# OpenTallas memory compiler (tools/mem_compiler), ASAP7 abstract view
VERSION 5.7 ;
BUSBITCHARS "[]" ;
DIVIDERCHAR "/" ;
PROPERTYDEFINITIONS
  MACRO width INTEGER ;
  MACRO depth INTEGER ;
  MACRO banks INTEGER ;
END PROPERTYDEFINITIONS
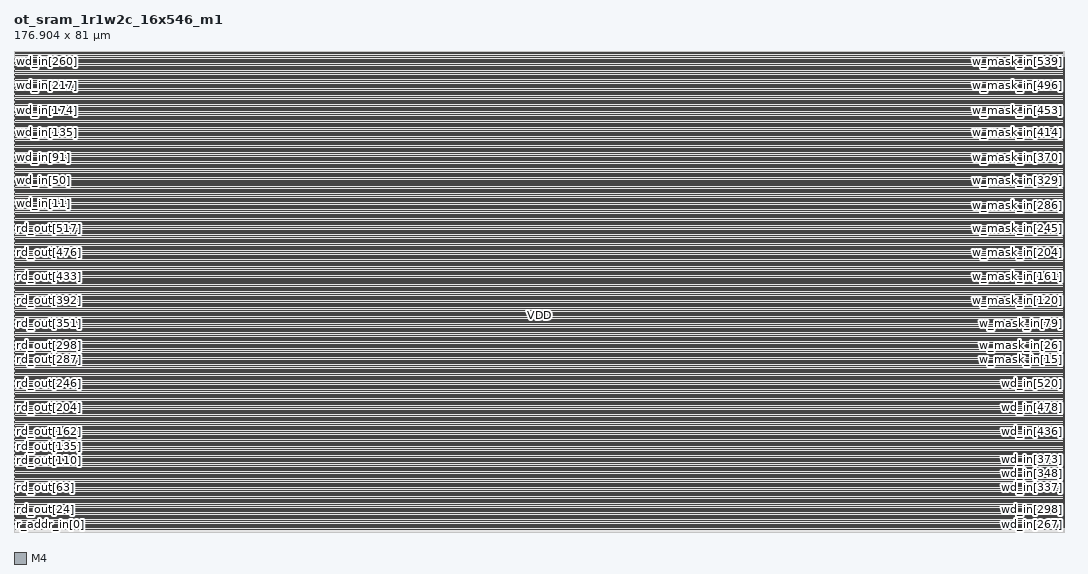
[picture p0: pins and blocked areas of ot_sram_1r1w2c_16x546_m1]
MACRO ot_sram_1r1w2c_16x546_m1
  PROPERTY width 546 ;
  PROPERTY depth 16 ;
  PROPERTY banks 1 ;
  FOREIGN ot_sram_1r1w2c_16x546_m1 0 0 ;
  SYMMETRY X Y R90 ;
  SIZE 176.904 BY 81.000 ;
  CLASS BLOCK ;
  PIN wclk
    DIRECTION INPUT ;
    USE CLOCK ;
    SHAPE ABUTMENT ;
    PORT
      LAYER M4 ;
      RECT 0.000 0.768 0.024 0.792 ;
    END
  END wclk
  PIN rclk
    DIRECTION INPUT ;
    USE CLOCK ;
    SHAPE ABUTMENT ;
    PORT
      LAYER M4 ;
      RECT 0.000 0.864 0.024 0.888 ;
    END
  END rclk
  PIN r_ce_in
    DIRECTION INPUT ;
    USE SIGNAL ;
    SHAPE ABUTMENT ;
    PORT
      LAYER M4 ;
      RECT 0.000 0.960 0.024 0.984 ;
    END
  END r_ce_in
  PIN r_addr_in[0]
    DIRECTION INPUT ;
    USE SIGNAL ;
    SHAPE ABUTMENT ;
    PORT
      LAYER M4 ;
      RECT 0.000 1.056 0.024 1.080 ;
    END
  END r_addr_in[0]
  PIN r_addr_in[1]
    DIRECTION INPUT ;
    USE SIGNAL ;
    SHAPE ABUTMENT ;
    PORT
      LAYER M4 ;
      RECT 0.000 1.152 0.024 1.176 ;
    END
  END r_addr_in[1]
  PIN r_addr_in[2]
    DIRECTION INPUT ;
    USE SIGNAL ;
    SHAPE ABUTMENT ;
    PORT
      LAYER M4 ;
      RECT 0.000 1.248 0.024 1.272 ;
    END
  END r_addr_in[2]
  PIN r_addr_in[3]
    DIRECTION INPUT ;
    USE SIGNAL ;
    SHAPE ABUTMENT ;
    PORT
      LAYER M4 ;
      RECT 0.000 1.344 0.024 1.368 ;
    END
  END r_addr_in[3]
  PIN rd_out[0]
    DIRECTION OUTPUT ;
    USE SIGNAL ;
    SHAPE ABUTMENT ;
    PORT
      LAYER M4 ;
      RECT 0.000 1.440 0.024 1.464 ;
    END
  END rd_out[0]
  PIN rd_out[1]
    DIRECTION OUTPUT ;
    USE SIGNAL ;
    SHAPE ABUTMENT ;
    PORT
      LAYER M4 ;
      RECT 0.000 1.536 0.024 1.560 ;
    END
  END rd_out[1]
  PIN rd_out[2]
    DIRECTION OUTPUT ;
    USE SIGNAL ;
    SHAPE ABUTMENT ;
    PORT
      LAYER M4 ;
      RECT 0.000 1.632 0.024 1.656 ;
    END
  END rd_out[2]
  PIN rd_out[3]
    DIRECTION OUTPUT ;
    USE SIGNAL ;
    SHAPE ABUTMENT ;
    PORT
      LAYER M4 ;
      RECT 0.000 1.728 0.024 1.752 ;
    END
  END rd_out[3]
  PIN rd_out[4]
    DIRECTION OUTPUT ;
    USE SIGNAL ;
    SHAPE ABUTMENT ;
    PORT
      LAYER M4 ;
      RECT 0.000 1.824 0.024 1.848 ;
    END
  END rd_out[4]
  PIN rd_out[5]
    DIRECTION OUTPUT ;
    USE SIGNAL ;
    SHAPE ABUTMENT ;
    PORT
      LAYER M4 ;
      RECT 0.000 1.920 0.024 1.944 ;
    END
  END rd_out[5]
  PIN rd_out[6]
    DIRECTION OUTPUT ;
    USE SIGNAL ;
    SHAPE ABUTMENT ;
    PORT
      LAYER M4 ;
      RECT 0.000 2.016 0.024 2.040 ;
    END
  END rd_out[6]
  PIN rd_out[7]
    DIRECTION OUTPUT ;
    USE SIGNAL ;
    SHAPE ABUTMENT ;
    PORT
      LAYER M4 ;
      RECT 0.000 2.112 0.024 2.136 ;
    END
  END rd_out[7]
  PIN rd_out[8]
    DIRECTION OUTPUT ;
    USE SIGNAL ;
    SHAPE ABUTMENT ;
    PORT
      LAYER M4 ;
      RECT 0.000 2.208 0.024 2.232 ;
    END
  END rd_out[8]
  PIN rd_out[9]
    DIRECTION OUTPUT ;
    USE SIGNAL ;
    SHAPE ABUTMENT ;
    PORT
      LAYER M4 ;
      RECT 0.000 2.304 0.024 2.328 ;
    END
  END rd_out[9]
  PIN rd_out[10]
    DIRECTION OUTPUT ;
    USE SIGNAL ;
    SHAPE ABUTMENT ;
    PORT
      LAYER M4 ;
      RECT 0.000 2.400 0.024 2.424 ;
    END
  END rd_out[10]
  PIN rd_out[11]
    DIRECTION OUTPUT ;
    USE SIGNAL ;
    SHAPE ABUTMENT ;
    PORT
      LAYER M4 ;
      RECT 0.000 2.496 0.024 2.520 ;
    END
  END rd_out[11]
  PIN rd_out[12]
    DIRECTION OUTPUT ;
    USE SIGNAL ;
    SHAPE ABUTMENT ;
    PORT
      LAYER M4 ;
      RECT 0.000 2.592 0.024 2.616 ;
    END
  END rd_out[12]
  PIN rd_out[13]
    DIRECTION OUTPUT ;
    USE SIGNAL ;
    SHAPE ABUTMENT ;
    PORT
      LAYER M4 ;
      RECT 0.000 2.688 0.024 2.712 ;
    END
  END rd_out[13]
  PIN rd_out[14]
    DIRECTION OUTPUT ;
    USE SIGNAL ;
    SHAPE ABUTMENT ;
    PORT
      LAYER M4 ;
      RECT 0.000 2.784 0.024 2.808 ;
    END
  END rd_out[14]
  PIN rd_out[15]
    DIRECTION OUTPUT ;
    USE SIGNAL ;
    SHAPE ABUTMENT ;
    PORT
      LAYER M4 ;
      RECT 0.000 2.880 0.024 2.904 ;
    END
  END rd_out[15]
  PIN rd_out[16]
    DIRECTION OUTPUT ;
    USE SIGNAL ;
    SHAPE ABUTMENT ;
    PORT
      LAYER M4 ;
      RECT 0.000 2.976 0.024 3.000 ;
    END
  END rd_out[16]
  PIN rd_out[17]
    DIRECTION OUTPUT ;
    USE SIGNAL ;
    SHAPE ABUTMENT ;
    PORT
      LAYER M4 ;
      RECT 0.000 3.072 0.024 3.096 ;
    END
  END rd_out[17]
  PIN rd_out[18]
    DIRECTION OUTPUT ;
    USE SIGNAL ;
    SHAPE ABUTMENT ;
    PORT
      LAYER M4 ;
      RECT 0.000 3.168 0.024 3.192 ;
    END
  END rd_out[18]
  PIN rd_out[19]
    DIRECTION OUTPUT ;
    USE SIGNAL ;
    SHAPE ABUTMENT ;
    PORT
      LAYER M4 ;
      RECT 0.000 3.264 0.024 3.288 ;
    END
  END rd_out[19]
  PIN rd_out[20]
    DIRECTION OUTPUT ;
    USE SIGNAL ;
    SHAPE ABUTMENT ;
    PORT
      LAYER M4 ;
      RECT 0.000 3.360 0.024 3.384 ;
    END
  END rd_out[20]
  PIN rd_out[21]
    DIRECTION OUTPUT ;
    USE SIGNAL ;
    SHAPE ABUTMENT ;
    PORT
      LAYER M4 ;
      RECT 0.000 3.456 0.024 3.480 ;
    END
  END rd_out[21]
  PIN rd_out[22]
    DIRECTION OUTPUT ;
    USE SIGNAL ;
    SHAPE ABUTMENT ;
    PORT
      LAYER M4 ;
      RECT 0.000 3.552 0.024 3.576 ;
    END
  END rd_out[22]
  PIN rd_out[23]
    DIRECTION OUTPUT ;
    USE SIGNAL ;
    SHAPE ABUTMENT ;
    PORT
      LAYER M4 ;
      RECT 0.000 3.648 0.024 3.672 ;
    END
  END rd_out[23]
  PIN rd_out[24]
    DIRECTION OUTPUT ;
    USE SIGNAL ;
    SHAPE ABUTMENT ;
    PORT
      LAYER M4 ;
      RECT 0.000 3.744 0.024 3.768 ;
    END
  END rd_out[24]
  PIN rd_out[25]
    DIRECTION OUTPUT ;
    USE SIGNAL ;
    SHAPE ABUTMENT ;
    PORT
      LAYER M4 ;
      RECT 0.000 3.840 0.024 3.864 ;
    END
  END rd_out[25]
  PIN rd_out[26]
    DIRECTION OUTPUT ;
    USE SIGNAL ;
    SHAPE ABUTMENT ;
    PORT
      LAYER M4 ;
      RECT 0.000 3.936 0.024 3.960 ;
    END
  END rd_out[26]
  PIN rd_out[27]
    DIRECTION OUTPUT ;
    USE SIGNAL ;
    SHAPE ABUTMENT ;
    PORT
      LAYER M4 ;
      RECT 0.000 4.032 0.024 4.056 ;
    END
  END rd_out[27]
  PIN rd_out[28]
    DIRECTION OUTPUT ;
    USE SIGNAL ;
    SHAPE ABUTMENT ;
    PORT
      LAYER M4 ;
      RECT 0.000 4.128 0.024 4.152 ;
    END
  END rd_out[28]
  PIN rd_out[29]
    DIRECTION OUTPUT ;
    USE SIGNAL ;
    SHAPE ABUTMENT ;
    PORT
      LAYER M4 ;
      RECT 0.000 4.224 0.024 4.248 ;
    END
  END rd_out[29]
  PIN rd_out[30]
    DIRECTION OUTPUT ;
    USE SIGNAL ;
    SHAPE ABUTMENT ;
    PORT
      LAYER M4 ;
      RECT 0.000 4.320 0.024 4.344 ;
    END
  END rd_out[30]
  PIN rd_out[31]
    DIRECTION OUTPUT ;
    USE SIGNAL ;
    SHAPE ABUTMENT ;
    PORT
      LAYER M4 ;
      RECT 0.000 4.416 0.024 4.440 ;
    END
  END rd_out[31]
  PIN rd_out[32]
    DIRECTION OUTPUT ;
    USE SIGNAL ;
    SHAPE ABUTMENT ;
    PORT
      LAYER M4 ;
      RECT 0.000 4.512 0.024 4.536 ;
    END
  END rd_out[32]
  PIN rd_out[33]
    DIRECTION OUTPUT ;
    USE SIGNAL ;
    SHAPE ABUTMENT ;
    PORT
      LAYER M4 ;
      RECT 0.000 4.608 0.024 4.632 ;
    END
  END rd_out[33]
  PIN rd_out[34]
    DIRECTION OUTPUT ;
    USE SIGNAL ;
    SHAPE ABUTMENT ;
    PORT
      LAYER M4 ;
      RECT 0.000 4.704 0.024 4.728 ;
    END
  END rd_out[34]
  PIN rd_out[35]
    DIRECTION OUTPUT ;
    USE SIGNAL ;
    SHAPE ABUTMENT ;
    PORT
      LAYER M4 ;
      RECT 0.000 4.800 0.024 4.824 ;
    END
  END rd_out[35]
  PIN rd_out[36]
    DIRECTION OUTPUT ;
    USE SIGNAL ;
    SHAPE ABUTMENT ;
    PORT
      LAYER M4 ;
      RECT 0.000 4.896 0.024 4.920 ;
    END
  END rd_out[36]
  PIN rd_out[37]
    DIRECTION OUTPUT ;
    USE SIGNAL ;
    SHAPE ABUTMENT ;
    PORT
      LAYER M4 ;
      RECT 0.000 4.992 0.024 5.016 ;
    END
  END rd_out[37]
  PIN rd_out[38]
    DIRECTION OUTPUT ;
    USE SIGNAL ;
    SHAPE ABUTMENT ;
    PORT
      LAYER M4 ;
      RECT 0.000 5.088 0.024 5.112 ;
    END
  END rd_out[38]
  PIN rd_out[39]
    DIRECTION OUTPUT ;
    USE SIGNAL ;
    SHAPE ABUTMENT ;
    PORT
      LAYER M4 ;
      RECT 0.000 5.184 0.024 5.208 ;
    END
  END rd_out[39]
  PIN rd_out[40]
    DIRECTION OUTPUT ;
    USE SIGNAL ;
    SHAPE ABUTMENT ;
    PORT
      LAYER M4 ;
      RECT 0.000 5.280 0.024 5.304 ;
    END
  END rd_out[40]
  PIN rd_out[41]
    DIRECTION OUTPUT ;
    USE SIGNAL ;
    SHAPE ABUTMENT ;
    PORT
      LAYER M4 ;
      RECT 0.000 5.376 0.024 5.400 ;
    END
  END rd_out[41]
  PIN rd_out[42]
    DIRECTION OUTPUT ;
    USE SIGNAL ;
    SHAPE ABUTMENT ;
    PORT
      LAYER M4 ;
      RECT 0.000 5.472 0.024 5.496 ;
    END
  END rd_out[42]
  PIN rd_out[43]
    DIRECTION OUTPUT ;
    USE SIGNAL ;
    SHAPE ABUTMENT ;
    PORT
      LAYER M4 ;
      RECT 0.000 5.568 0.024 5.592 ;
    END
  END rd_out[43]
  PIN rd_out[44]
    DIRECTION OUTPUT ;
    USE SIGNAL ;
    SHAPE ABUTMENT ;
    PORT
      LAYER M4 ;
      RECT 0.000 5.664 0.024 5.688 ;
    END
  END rd_out[44]
  PIN rd_out[45]
    DIRECTION OUTPUT ;
    USE SIGNAL ;
    SHAPE ABUTMENT ;
    PORT
      LAYER M4 ;
      RECT 0.000 5.760 0.024 5.784 ;
    END
  END rd_out[45]
  PIN rd_out[46]
    DIRECTION OUTPUT ;
    USE SIGNAL ;
    SHAPE ABUTMENT ;
    PORT
      LAYER M4 ;
      RECT 0.000 5.856 0.024 5.880 ;
    END
  END rd_out[46]
  PIN rd_out[47]
    DIRECTION OUTPUT ;
    USE SIGNAL ;
    SHAPE ABUTMENT ;
    PORT
      LAYER M4 ;
      RECT 0.000 5.952 0.024 5.976 ;
    END
  END rd_out[47]
  PIN rd_out[48]
    DIRECTION OUTPUT ;
    USE SIGNAL ;
    SHAPE ABUTMENT ;
    PORT
      LAYER M4 ;
      RECT 0.000 6.048 0.024 6.072 ;
    END
  END rd_out[48]
  PIN rd_out[49]
    DIRECTION OUTPUT ;
    USE SIGNAL ;
    SHAPE ABUTMENT ;
    PORT
      LAYER M4 ;
      RECT 0.000 6.144 0.024 6.168 ;
    END
  END rd_out[49]
  PIN rd_out[50]
    DIRECTION OUTPUT ;
    USE SIGNAL ;
    SHAPE ABUTMENT ;
    PORT
      LAYER M4 ;
      RECT 0.000 6.240 0.024 6.264 ;
    END
  END rd_out[50]
  PIN rd_out[51]
    DIRECTION OUTPUT ;
    USE SIGNAL ;
    SHAPE ABUTMENT ;
    PORT
      LAYER M4 ;
      RECT 0.000 6.336 0.024 6.360 ;
    END
  END rd_out[51]
  PIN rd_out[52]
    DIRECTION OUTPUT ;
    USE SIGNAL ;
    SHAPE ABUTMENT ;
    PORT
      LAYER M4 ;
      RECT 0.000 6.432 0.024 6.456 ;
    END
  END rd_out[52]
  PIN rd_out[53]
    DIRECTION OUTPUT ;
    USE SIGNAL ;
    SHAPE ABUTMENT ;
    PORT
      LAYER M4 ;
      RECT 0.000 6.528 0.024 6.552 ;
    END
  END rd_out[53]
  PIN rd_out[54]
    DIRECTION OUTPUT ;
    USE SIGNAL ;
    SHAPE ABUTMENT ;
    PORT
      LAYER M4 ;
      RECT 0.000 6.624 0.024 6.648 ;
    END
  END rd_out[54]
  PIN rd_out[55]
    DIRECTION OUTPUT ;
    USE SIGNAL ;
    SHAPE ABUTMENT ;
    PORT
      LAYER M4 ;
      RECT 0.000 6.720 0.024 6.744 ;
    END
  END rd_out[55]
  PIN rd_out[56]
    DIRECTION OUTPUT ;
    USE SIGNAL ;
    SHAPE ABUTMENT ;
    PORT
      LAYER M4 ;
      RECT 0.000 6.816 0.024 6.840 ;
    END
  END rd_out[56]
  PIN rd_out[57]
    DIRECTION OUTPUT ;
    USE SIGNAL ;
    SHAPE ABUTMENT ;
    PORT
      LAYER M4 ;
      RECT 0.000 6.912 0.024 6.936 ;
    END
  END rd_out[57]
  PIN rd_out[58]
    DIRECTION OUTPUT ;
    USE SIGNAL ;
    SHAPE ABUTMENT ;
    PORT
      LAYER M4 ;
      RECT 0.000 7.008 0.024 7.032 ;
    END
  END rd_out[58]
  PIN rd_out[59]
    DIRECTION OUTPUT ;
    USE SIGNAL ;
    SHAPE ABUTMENT ;
    PORT
      LAYER M4 ;
      RECT 0.000 7.104 0.024 7.128 ;
    END
  END rd_out[59]
  PIN rd_out[60]
    DIRECTION OUTPUT ;
    USE SIGNAL ;
    SHAPE ABUTMENT ;
    PORT
      LAYER M4 ;
      RECT 0.000 7.200 0.024 7.224 ;
    END
  END rd_out[60]
  PIN rd_out[61]
    DIRECTION OUTPUT ;
    USE SIGNAL ;
    SHAPE ABUTMENT ;
    PORT
      LAYER M4 ;
      RECT 0.000 7.296 0.024 7.320 ;
    END
  END rd_out[61]
  PIN rd_out[62]
    DIRECTION OUTPUT ;
    USE SIGNAL ;
    SHAPE ABUTMENT ;
    PORT
      LAYER M4 ;
      RECT 0.000 7.392 0.024 7.416 ;
    END
  END rd_out[62]
  PIN rd_out[63]
    DIRECTION OUTPUT ;
    USE SIGNAL ;
    SHAPE ABUTMENT ;
    PORT
      LAYER M4 ;
      RECT 0.000 7.488 0.024 7.512 ;
    END
  END rd_out[63]
  PIN rd_out[64]
    DIRECTION OUTPUT ;
    USE SIGNAL ;
    SHAPE ABUTMENT ;
    PORT
      LAYER M4 ;
      RECT 0.000 7.584 0.024 7.608 ;
    END
  END rd_out[64]
  PIN rd_out[65]
    DIRECTION OUTPUT ;
    USE SIGNAL ;
    SHAPE ABUTMENT ;
    PORT
      LAYER M4 ;
      RECT 0.000 7.680 0.024 7.704 ;
    END
  END rd_out[65]
  PIN rd_out[66]
    DIRECTION OUTPUT ;
    USE SIGNAL ;
    SHAPE ABUTMENT ;
    PORT
      LAYER M4 ;
      RECT 0.000 7.776 0.024 7.800 ;
    END
  END rd_out[66]
  PIN rd_out[67]
    DIRECTION OUTPUT ;
    USE SIGNAL ;
    SHAPE ABUTMENT ;
    PORT
      LAYER M4 ;
      RECT 0.000 7.872 0.024 7.896 ;
    END
  END rd_out[67]
  PIN rd_out[68]
    DIRECTION OUTPUT ;
    USE SIGNAL ;
    SHAPE ABUTMENT ;
    PORT
      LAYER M4 ;
      RECT 0.000 7.968 0.024 7.992 ;
    END
  END rd_out[68]
  PIN rd_out[69]
    DIRECTION OUTPUT ;
    USE SIGNAL ;
    SHAPE ABUTMENT ;
    PORT
      LAYER M4 ;
      RECT 0.000 8.064 0.024 8.088 ;
    END
  END rd_out[69]
  PIN rd_out[70]
    DIRECTION OUTPUT ;
    USE SIGNAL ;
    SHAPE ABUTMENT ;
    PORT
      LAYER M4 ;
      RECT 0.000 8.160 0.024 8.184 ;
    END
  END rd_out[70]
  PIN rd_out[71]
    DIRECTION OUTPUT ;
    USE SIGNAL ;
    SHAPE ABUTMENT ;
    PORT
      LAYER M4 ;
      RECT 0.000 8.256 0.024 8.280 ;
    END
  END rd_out[71]
  PIN rd_out[72]
    DIRECTION OUTPUT ;
    USE SIGNAL ;
    SHAPE ABUTMENT ;
    PORT
      LAYER M4 ;
      RECT 0.000 8.352 0.024 8.376 ;
    END
  END rd_out[72]
  PIN rd_out[73]
    DIRECTION OUTPUT ;
    USE SIGNAL ;
    SHAPE ABUTMENT ;
    PORT
      LAYER M4 ;
      RECT 0.000 8.448 0.024 8.472 ;
    END
  END rd_out[73]
  PIN rd_out[74]
    DIRECTION OUTPUT ;
    USE SIGNAL ;
    SHAPE ABUTMENT ;
    PORT
      LAYER M4 ;
      RECT 0.000 8.544 0.024 8.568 ;
    END
  END rd_out[74]
  PIN rd_out[75]
    DIRECTION OUTPUT ;
    USE SIGNAL ;
    SHAPE ABUTMENT ;
    PORT
      LAYER M4 ;
      RECT 0.000 8.640 0.024 8.664 ;
    END
  END rd_out[75]
  PIN rd_out[76]
    DIRECTION OUTPUT ;
    USE SIGNAL ;
    SHAPE ABUTMENT ;
    PORT
      LAYER M4 ;
      RECT 0.000 8.736 0.024 8.760 ;
    END
  END rd_out[76]
  PIN rd_out[77]
    DIRECTION OUTPUT ;
    USE SIGNAL ;
    SHAPE ABUTMENT ;
    PORT
      LAYER M4 ;
      RECT 0.000 8.832 0.024 8.856 ;
    END
  END rd_out[77]
  PIN rd_out[78]
    DIRECTION OUTPUT ;
    USE SIGNAL ;
    SHAPE ABUTMENT ;
    PORT
      LAYER M4 ;
      RECT 0.000 8.928 0.024 8.952 ;
    END
  END rd_out[78]
  PIN rd_out[79]
    DIRECTION OUTPUT ;
    USE SIGNAL ;
    SHAPE ABUTMENT ;
    PORT
      LAYER M4 ;
      RECT 0.000 9.024 0.024 9.048 ;
    END
  END rd_out[79]
  PIN rd_out[80]
    DIRECTION OUTPUT ;
    USE SIGNAL ;
    SHAPE ABUTMENT ;
    PORT
      LAYER M4 ;
      RECT 0.000 9.120 0.024 9.144 ;
    END
  END rd_out[80]
  PIN rd_out[81]
    DIRECTION OUTPUT ;
    USE SIGNAL ;
    SHAPE ABUTMENT ;
    PORT
      LAYER M4 ;
      RECT 0.000 9.216 0.024 9.240 ;
    END
  END rd_out[81]
  PIN rd_out[82]
    DIRECTION OUTPUT ;
    USE SIGNAL ;
    SHAPE ABUTMENT ;
    PORT
      LAYER M4 ;
      RECT 0.000 9.312 0.024 9.336 ;
    END
  END rd_out[82]
  PIN rd_out[83]
    DIRECTION OUTPUT ;
    USE SIGNAL ;
    SHAPE ABUTMENT ;
    PORT
      LAYER M4 ;
      RECT 0.000 9.408 0.024 9.432 ;
    END
  END rd_out[83]
  PIN rd_out[84]
    DIRECTION OUTPUT ;
    USE SIGNAL ;
    SHAPE ABUTMENT ;
    PORT
      LAYER M4 ;
      RECT 0.000 9.504 0.024 9.528 ;
    END
  END rd_out[84]
  PIN rd_out[85]
    DIRECTION OUTPUT ;
    USE SIGNAL ;
    SHAPE ABUTMENT ;
    PORT
      LAYER M4 ;
      RECT 0.000 9.600 0.024 9.624 ;
    END
  END rd_out[85]
  PIN rd_out[86]
    DIRECTION OUTPUT ;
    USE SIGNAL ;
    SHAPE ABUTMENT ;
    PORT
      LAYER M4 ;
      RECT 0.000 9.696 0.024 9.720 ;
    END
  END rd_out[86]
  PIN rd_out[87]
    DIRECTION OUTPUT ;
    USE SIGNAL ;
    SHAPE ABUTMENT ;
    PORT
      LAYER M4 ;
      RECT 0.000 9.792 0.024 9.816 ;
    END
  END rd_out[87]
  PIN rd_out[88]
    DIRECTION OUTPUT ;
    USE SIGNAL ;
    SHAPE ABUTMENT ;
    PORT
      LAYER M4 ;
      RECT 0.000 9.888 0.024 9.912 ;
    END
  END rd_out[88]
  PIN rd_out[89]
    DIRECTION OUTPUT ;
    USE SIGNAL ;
    SHAPE ABUTMENT ;
    PORT
      LAYER M4 ;
      RECT 0.000 9.984 0.024 10.008 ;
    END
  END rd_out[89]
  PIN rd_out[90]
    DIRECTION OUTPUT ;
    USE SIGNAL ;
    SHAPE ABUTMENT ;
    PORT
      LAYER M4 ;
      RECT 0.000 10.080 0.024 10.104 ;
    END
  END rd_out[90]
  PIN rd_out[91]
    DIRECTION OUTPUT ;
    USE SIGNAL ;
    SHAPE ABUTMENT ;
    PORT
      LAYER M4 ;
      RECT 0.000 10.176 0.024 10.200 ;
    END
  END rd_out[91]
  PIN rd_out[92]
    DIRECTION OUTPUT ;
    USE SIGNAL ;
    SHAPE ABUTMENT ;
    PORT
      LAYER M4 ;
      RECT 0.000 10.272 0.024 10.296 ;
    END
  END rd_out[92]
  PIN rd_out[93]
    DIRECTION OUTPUT ;
    USE SIGNAL ;
    SHAPE ABUTMENT ;
    PORT
      LAYER M4 ;
      RECT 0.000 10.368 0.024 10.392 ;
    END
  END rd_out[93]
  PIN rd_out[94]
    DIRECTION OUTPUT ;
    USE SIGNAL ;
    SHAPE ABUTMENT ;
    PORT
      LAYER M4 ;
      RECT 0.000 10.464 0.024 10.488 ;
    END
  END rd_out[94]
  PIN rd_out[95]
    DIRECTION OUTPUT ;
    USE SIGNAL ;
    SHAPE ABUTMENT ;
    PORT
      LAYER M4 ;
      RECT 0.000 10.560 0.024 10.584 ;
    END
  END rd_out[95]
  PIN rd_out[96]
    DIRECTION OUTPUT ;
    USE SIGNAL ;
    SHAPE ABUTMENT ;
    PORT
      LAYER M4 ;
      RECT 0.000 10.656 0.024 10.680 ;
    END
  END rd_out[96]
  PIN rd_out[97]
    DIRECTION OUTPUT ;
    USE SIGNAL ;
    SHAPE ABUTMENT ;
    PORT
      LAYER M4 ;
      RECT 0.000 10.752 0.024 10.776 ;
    END
  END rd_out[97]
  PIN rd_out[98]
    DIRECTION OUTPUT ;
    USE SIGNAL ;
    SHAPE ABUTMENT ;
    PORT
      LAYER M4 ;
      RECT 0.000 10.848 0.024 10.872 ;
    END
  END rd_out[98]
  PIN rd_out[99]
    DIRECTION OUTPUT ;
    USE SIGNAL ;
    SHAPE ABUTMENT ;
    PORT
      LAYER M4 ;
      RECT 0.000 10.944 0.024 10.968 ;
    END
  END rd_out[99]
  PIN rd_out[100]
    DIRECTION OUTPUT ;
    USE SIGNAL ;
    SHAPE ABUTMENT ;
    PORT
      LAYER M4 ;
      RECT 0.000 11.040 0.024 11.064 ;
    END
  END rd_out[100]
  PIN rd_out[101]
    DIRECTION OUTPUT ;
    USE SIGNAL ;
    SHAPE ABUTMENT ;
    PORT
      LAYER M4 ;
      RECT 0.000 11.136 0.024 11.160 ;
    END
  END rd_out[101]
  PIN rd_out[102]
    DIRECTION OUTPUT ;
    USE SIGNAL ;
    SHAPE ABUTMENT ;
    PORT
      LAYER M4 ;
      RECT 0.000 11.232 0.024 11.256 ;
    END
  END rd_out[102]
  PIN rd_out[103]
    DIRECTION OUTPUT ;
    USE SIGNAL ;
    SHAPE ABUTMENT ;
    PORT
      LAYER M4 ;
      RECT 0.000 11.328 0.024 11.352 ;
    END
  END rd_out[103]
  PIN rd_out[104]
    DIRECTION OUTPUT ;
    USE SIGNAL ;
    SHAPE ABUTMENT ;
    PORT
      LAYER M4 ;
      RECT 0.000 11.424 0.024 11.448 ;
    END
  END rd_out[104]
  PIN rd_out[105]
    DIRECTION OUTPUT ;
    USE SIGNAL ;
    SHAPE ABUTMENT ;
    PORT
      LAYER M4 ;
      RECT 0.000 11.520 0.024 11.544 ;
    END
  END rd_out[105]
  PIN rd_out[106]
    DIRECTION OUTPUT ;
    USE SIGNAL ;
    SHAPE ABUTMENT ;
    PORT
      LAYER M4 ;
      RECT 0.000 11.616 0.024 11.640 ;
    END
  END rd_out[106]
  PIN rd_out[107]
    DIRECTION OUTPUT ;
    USE SIGNAL ;
    SHAPE ABUTMENT ;
    PORT
      LAYER M4 ;
      RECT 0.000 11.712 0.024 11.736 ;
    END
  END rd_out[107]
  PIN rd_out[108]
    DIRECTION OUTPUT ;
    USE SIGNAL ;
    SHAPE ABUTMENT ;
    PORT
      LAYER M4 ;
      RECT 0.000 11.808 0.024 11.832 ;
    END
  END rd_out[108]
  PIN rd_out[109]
    DIRECTION OUTPUT ;
    USE SIGNAL ;
    SHAPE ABUTMENT ;
    PORT
      LAYER M4 ;
      RECT 0.000 11.904 0.024 11.928 ;
    END
  END rd_out[109]
  PIN rd_out[110]
    DIRECTION OUTPUT ;
    USE SIGNAL ;
    SHAPE ABUTMENT ;
    PORT
      LAYER M4 ;
      RECT 0.000 12.000 0.024 12.024 ;
    END
  END rd_out[110]
  PIN rd_out[111]
    DIRECTION OUTPUT ;
    USE SIGNAL ;
    SHAPE ABUTMENT ;
    PORT
      LAYER M4 ;
      RECT 0.000 12.096 0.024 12.120 ;
    END
  END rd_out[111]
  PIN rd_out[112]
    DIRECTION OUTPUT ;
    USE SIGNAL ;
    SHAPE ABUTMENT ;
    PORT
      LAYER M4 ;
      RECT 0.000 12.192 0.024 12.216 ;
    END
  END rd_out[112]
  PIN rd_out[113]
    DIRECTION OUTPUT ;
    USE SIGNAL ;
    SHAPE ABUTMENT ;
    PORT
      LAYER M4 ;
      RECT 0.000 12.288 0.024 12.312 ;
    END
  END rd_out[113]
  PIN rd_out[114]
    DIRECTION OUTPUT ;
    USE SIGNAL ;
    SHAPE ABUTMENT ;
    PORT
      LAYER M4 ;
      RECT 0.000 12.384 0.024 12.408 ;
    END
  END rd_out[114]
  PIN rd_out[115]
    DIRECTION OUTPUT ;
    USE SIGNAL ;
    SHAPE ABUTMENT ;
    PORT
      LAYER M4 ;
      RECT 0.000 12.480 0.024 12.504 ;
    END
  END rd_out[115]
  PIN rd_out[116]
    DIRECTION OUTPUT ;
    USE SIGNAL ;
    SHAPE ABUTMENT ;
    PORT
      LAYER M4 ;
      RECT 0.000 12.576 0.024 12.600 ;
    END
  END rd_out[116]
  PIN rd_out[117]
    DIRECTION OUTPUT ;
    USE SIGNAL ;
    SHAPE ABUTMENT ;
    PORT
      LAYER M4 ;
      RECT 0.000 12.672 0.024 12.696 ;
    END
  END rd_out[117]
  PIN rd_out[118]
    DIRECTION OUTPUT ;
    USE SIGNAL ;
    SHAPE ABUTMENT ;
    PORT
      LAYER M4 ;
      RECT 0.000 12.768 0.024 12.792 ;
    END
  END rd_out[118]
  PIN rd_out[119]
    DIRECTION OUTPUT ;
    USE SIGNAL ;
    SHAPE ABUTMENT ;
    PORT
      LAYER M4 ;
      RECT 0.000 12.864 0.024 12.888 ;
    END
  END rd_out[119]
  PIN rd_out[120]
    DIRECTION OUTPUT ;
    USE SIGNAL ;
    SHAPE ABUTMENT ;
    PORT
      LAYER M4 ;
      RECT 0.000 12.960 0.024 12.984 ;
    END
  END rd_out[120]
  PIN rd_out[121]
    DIRECTION OUTPUT ;
    USE SIGNAL ;
    SHAPE ABUTMENT ;
    PORT
      LAYER M4 ;
      RECT 0.000 13.056 0.024 13.080 ;
    END
  END rd_out[121]
  PIN rd_out[122]
    DIRECTION OUTPUT ;
    USE SIGNAL ;
    SHAPE ABUTMENT ;
    PORT
      LAYER M4 ;
      RECT 0.000 13.152 0.024 13.176 ;
    END
  END rd_out[122]
  PIN rd_out[123]
    DIRECTION OUTPUT ;
    USE SIGNAL ;
    SHAPE ABUTMENT ;
    PORT
      LAYER M4 ;
      RECT 0.000 13.248 0.024 13.272 ;
    END
  END rd_out[123]
  PIN rd_out[124]
    DIRECTION OUTPUT ;
    USE SIGNAL ;
    SHAPE ABUTMENT ;
    PORT
      LAYER M4 ;
      RECT 0.000 13.344 0.024 13.368 ;
    END
  END rd_out[124]
  PIN rd_out[125]
    DIRECTION OUTPUT ;
    USE SIGNAL ;
    SHAPE ABUTMENT ;
    PORT
      LAYER M4 ;
      RECT 0.000 13.440 0.024 13.464 ;
    END
  END rd_out[125]
  PIN rd_out[126]
    DIRECTION OUTPUT ;
    USE SIGNAL ;
    SHAPE ABUTMENT ;
    PORT
      LAYER M4 ;
      RECT 0.000 13.536 0.024 13.560 ;
    END
  END rd_out[126]
  PIN rd_out[127]
    DIRECTION OUTPUT ;
    USE SIGNAL ;
    SHAPE ABUTMENT ;
    PORT
      LAYER M4 ;
      RECT 0.000 13.632 0.024 13.656 ;
    END
  END rd_out[127]
  PIN rd_out[128]
    DIRECTION OUTPUT ;
    USE SIGNAL ;
    SHAPE ABUTMENT ;
    PORT
      LAYER M4 ;
      RECT 0.000 13.728 0.024 13.752 ;
    END
  END rd_out[128]
  PIN rd_out[129]
    DIRECTION OUTPUT ;
    USE SIGNAL ;
    SHAPE ABUTMENT ;
    PORT
      LAYER M4 ;
      RECT 0.000 13.824 0.024 13.848 ;
    END
  END rd_out[129]
  PIN rd_out[130]
    DIRECTION OUTPUT ;
    USE SIGNAL ;
    SHAPE ABUTMENT ;
    PORT
      LAYER M4 ;
      RECT 0.000 13.920 0.024 13.944 ;
    END
  END rd_out[130]
  PIN rd_out[131]
    DIRECTION OUTPUT ;
    USE SIGNAL ;
    SHAPE ABUTMENT ;
    PORT
      LAYER M4 ;
      RECT 0.000 14.016 0.024 14.040 ;
    END
  END rd_out[131]
  PIN rd_out[132]
    DIRECTION OUTPUT ;
    USE SIGNAL ;
    SHAPE ABUTMENT ;
    PORT
      LAYER M4 ;
      RECT 0.000 14.112 0.024 14.136 ;
    END
  END rd_out[132]
  PIN rd_out[133]
    DIRECTION OUTPUT ;
    USE SIGNAL ;
    SHAPE ABUTMENT ;
    PORT
      LAYER M4 ;
      RECT 0.000 14.208 0.024 14.232 ;
    END
  END rd_out[133]
  PIN rd_out[134]
    DIRECTION OUTPUT ;
    USE SIGNAL ;
    SHAPE ABUTMENT ;
    PORT
      LAYER M4 ;
      RECT 0.000 14.304 0.024 14.328 ;
    END
  END rd_out[134]
  PIN rd_out[135]
    DIRECTION OUTPUT ;
    USE SIGNAL ;
    SHAPE ABUTMENT ;
    PORT
      LAYER M4 ;
      RECT 0.000 14.400 0.024 14.424 ;
    END
  END rd_out[135]
  PIN rd_out[136]
    DIRECTION OUTPUT ;
    USE SIGNAL ;
    SHAPE ABUTMENT ;
    PORT
      LAYER M4 ;
      RECT 0.000 14.496 0.024 14.520 ;
    END
  END rd_out[136]
  PIN rd_out[137]
    DIRECTION OUTPUT ;
    USE SIGNAL ;
    SHAPE ABUTMENT ;
    PORT
      LAYER M4 ;
      RECT 0.000 14.592 0.024 14.616 ;
    END
  END rd_out[137]
  PIN rd_out[138]
    DIRECTION OUTPUT ;
    USE SIGNAL ;
    SHAPE ABUTMENT ;
    PORT
      LAYER M4 ;
      RECT 0.000 14.688 0.024 14.712 ;
    END
  END rd_out[138]
  PIN rd_out[139]
    DIRECTION OUTPUT ;
    USE SIGNAL ;
    SHAPE ABUTMENT ;
    PORT
      LAYER M4 ;
      RECT 0.000 14.784 0.024 14.808 ;
    END
  END rd_out[139]
  PIN rd_out[140]
    DIRECTION OUTPUT ;
    USE SIGNAL ;
    SHAPE ABUTMENT ;
    PORT
      LAYER M4 ;
      RECT 0.000 14.880 0.024 14.904 ;
    END
  END rd_out[140]
  PIN rd_out[141]
    DIRECTION OUTPUT ;
    USE SIGNAL ;
    SHAPE ABUTMENT ;
    PORT
      LAYER M4 ;
      RECT 0.000 14.976 0.024 15.000 ;
    END
  END rd_out[141]
  PIN rd_out[142]
    DIRECTION OUTPUT ;
    USE SIGNAL ;
    SHAPE ABUTMENT ;
    PORT
      LAYER M4 ;
      RECT 0.000 15.072 0.024 15.096 ;
    END
  END rd_out[142]
  PIN rd_out[143]
    DIRECTION OUTPUT ;
    USE SIGNAL ;
    SHAPE ABUTMENT ;
    PORT
      LAYER M4 ;
      RECT 0.000 15.168 0.024 15.192 ;
    END
  END rd_out[143]
  PIN rd_out[144]
    DIRECTION OUTPUT ;
    USE SIGNAL ;
    SHAPE ABUTMENT ;
    PORT
      LAYER M4 ;
      RECT 0.000 15.264 0.024 15.288 ;
    END
  END rd_out[144]
  PIN rd_out[145]
    DIRECTION OUTPUT ;
    USE SIGNAL ;
    SHAPE ABUTMENT ;
    PORT
      LAYER M4 ;
      RECT 0.000 15.360 0.024 15.384 ;
    END
  END rd_out[145]
  PIN rd_out[146]
    DIRECTION OUTPUT ;
    USE SIGNAL ;
    SHAPE ABUTMENT ;
    PORT
      LAYER M4 ;
      RECT 0.000 15.456 0.024 15.480 ;
    END
  END rd_out[146]
  PIN rd_out[147]
    DIRECTION OUTPUT ;
    USE SIGNAL ;
    SHAPE ABUTMENT ;
    PORT
      LAYER M4 ;
      RECT 0.000 15.552 0.024 15.576 ;
    END
  END rd_out[147]
  PIN rd_out[148]
    DIRECTION OUTPUT ;
    USE SIGNAL ;
    SHAPE ABUTMENT ;
    PORT
      LAYER M4 ;
      RECT 0.000 15.648 0.024 15.672 ;
    END
  END rd_out[148]
  PIN rd_out[149]
    DIRECTION OUTPUT ;
    USE SIGNAL ;
    SHAPE ABUTMENT ;
    PORT
      LAYER M4 ;
      RECT 0.000 15.744 0.024 15.768 ;
    END
  END rd_out[149]
  PIN rd_out[150]
    DIRECTION OUTPUT ;
    USE SIGNAL ;
    SHAPE ABUTMENT ;
    PORT
      LAYER M4 ;
      RECT 0.000 15.840 0.024 15.864 ;
    END
  END rd_out[150]
  PIN rd_out[151]
    DIRECTION OUTPUT ;
    USE SIGNAL ;
    SHAPE ABUTMENT ;
    PORT
      LAYER M4 ;
      RECT 0.000 15.936 0.024 15.960 ;
    END
  END rd_out[151]
  PIN rd_out[152]
    DIRECTION OUTPUT ;
    USE SIGNAL ;
    SHAPE ABUTMENT ;
    PORT
      LAYER M4 ;
      RECT 0.000 16.032 0.024 16.056 ;
    END
  END rd_out[152]
  PIN rd_out[153]
    DIRECTION OUTPUT ;
    USE SIGNAL ;
    SHAPE ABUTMENT ;
    PORT
      LAYER M4 ;
      RECT 0.000 16.128 0.024 16.152 ;
    END
  END rd_out[153]
  PIN rd_out[154]
    DIRECTION OUTPUT ;
    USE SIGNAL ;
    SHAPE ABUTMENT ;
    PORT
      LAYER M4 ;
      RECT 0.000 16.224 0.024 16.248 ;
    END
  END rd_out[154]
  PIN rd_out[155]
    DIRECTION OUTPUT ;
    USE SIGNAL ;
    SHAPE ABUTMENT ;
    PORT
      LAYER M4 ;
      RECT 0.000 16.320 0.024 16.344 ;
    END
  END rd_out[155]
  PIN rd_out[156]
    DIRECTION OUTPUT ;
    USE SIGNAL ;
    SHAPE ABUTMENT ;
    PORT
      LAYER M4 ;
      RECT 0.000 16.416 0.024 16.440 ;
    END
  END rd_out[156]
  PIN rd_out[157]
    DIRECTION OUTPUT ;
    USE SIGNAL ;
    SHAPE ABUTMENT ;
    PORT
      LAYER M4 ;
      RECT 0.000 16.512 0.024 16.536 ;
    END
  END rd_out[157]
  PIN rd_out[158]
    DIRECTION OUTPUT ;
    USE SIGNAL ;
    SHAPE ABUTMENT ;
    PORT
      LAYER M4 ;
      RECT 0.000 16.608 0.024 16.632 ;
    END
  END rd_out[158]
  PIN rd_out[159]
    DIRECTION OUTPUT ;
    USE SIGNAL ;
    SHAPE ABUTMENT ;
    PORT
      LAYER M4 ;
      RECT 0.000 16.704 0.024 16.728 ;
    END
  END rd_out[159]
  PIN rd_out[160]
    DIRECTION OUTPUT ;
    USE SIGNAL ;
    SHAPE ABUTMENT ;
    PORT
      LAYER M4 ;
      RECT 0.000 16.800 0.024 16.824 ;
    END
  END rd_out[160]
  PIN rd_out[161]
    DIRECTION OUTPUT ;
    USE SIGNAL ;
    SHAPE ABUTMENT ;
    PORT
      LAYER M4 ;
      RECT 0.000 16.896 0.024 16.920 ;
    END
  END rd_out[161]
  PIN rd_out[162]
    DIRECTION OUTPUT ;
    USE SIGNAL ;
    SHAPE ABUTMENT ;
    PORT
      LAYER M4 ;
      RECT 0.000 16.992 0.024 17.016 ;
    END
  END rd_out[162]
  PIN rd_out[163]
    DIRECTION OUTPUT ;
    USE SIGNAL ;
    SHAPE ABUTMENT ;
    PORT
      LAYER M4 ;
      RECT 0.000 17.088 0.024 17.112 ;
    END
  END rd_out[163]
  PIN rd_out[164]
    DIRECTION OUTPUT ;
    USE SIGNAL ;
    SHAPE ABUTMENT ;
    PORT
      LAYER M4 ;
      RECT 0.000 17.184 0.024 17.208 ;
    END
  END rd_out[164]
  PIN rd_out[165]
    DIRECTION OUTPUT ;
    USE SIGNAL ;
    SHAPE ABUTMENT ;
    PORT
      LAYER M4 ;
      RECT 0.000 17.280 0.024 17.304 ;
    END
  END rd_out[165]
  PIN rd_out[166]
    DIRECTION OUTPUT ;
    USE SIGNAL ;
    SHAPE ABUTMENT ;
    PORT
      LAYER M4 ;
      RECT 0.000 17.376 0.024 17.400 ;
    END
  END rd_out[166]
  PIN rd_out[167]
    DIRECTION OUTPUT ;
    USE SIGNAL ;
    SHAPE ABUTMENT ;
    PORT
      LAYER M4 ;
      RECT 0.000 17.472 0.024 17.496 ;
    END
  END rd_out[167]
  PIN rd_out[168]
    DIRECTION OUTPUT ;
    USE SIGNAL ;
    SHAPE ABUTMENT ;
    PORT
      LAYER M4 ;
      RECT 0.000 17.568 0.024 17.592 ;
    END
  END rd_out[168]
  PIN rd_out[169]
    DIRECTION OUTPUT ;
    USE SIGNAL ;
    SHAPE ABUTMENT ;
    PORT
      LAYER M4 ;
      RECT 0.000 17.664 0.024 17.688 ;
    END
  END rd_out[169]
  PIN rd_out[170]
    DIRECTION OUTPUT ;
    USE SIGNAL ;
    SHAPE ABUTMENT ;
    PORT
      LAYER M4 ;
      RECT 0.000 17.760 0.024 17.784 ;
    END
  END rd_out[170]
  PIN rd_out[171]
    DIRECTION OUTPUT ;
    USE SIGNAL ;
    SHAPE ABUTMENT ;
    PORT
      LAYER M4 ;
      RECT 0.000 17.856 0.024 17.880 ;
    END
  END rd_out[171]
  PIN rd_out[172]
    DIRECTION OUTPUT ;
    USE SIGNAL ;
    SHAPE ABUTMENT ;
    PORT
      LAYER M4 ;
      RECT 0.000 17.952 0.024 17.976 ;
    END
  END rd_out[172]
  PIN rd_out[173]
    DIRECTION OUTPUT ;
    USE SIGNAL ;
    SHAPE ABUTMENT ;
    PORT
      LAYER M4 ;
      RECT 0.000 18.048 0.024 18.072 ;
    END
  END rd_out[173]
  PIN rd_out[174]
    DIRECTION OUTPUT ;
    USE SIGNAL ;
    SHAPE ABUTMENT ;
    PORT
      LAYER M4 ;
      RECT 0.000 18.144 0.024 18.168 ;
    END
  END rd_out[174]
  PIN rd_out[175]
    DIRECTION OUTPUT ;
    USE SIGNAL ;
    SHAPE ABUTMENT ;
    PORT
      LAYER M4 ;
      RECT 0.000 18.240 0.024 18.264 ;
    END
  END rd_out[175]
  PIN rd_out[176]
    DIRECTION OUTPUT ;
    USE SIGNAL ;
    SHAPE ABUTMENT ;
    PORT
      LAYER M4 ;
      RECT 0.000 18.336 0.024 18.360 ;
    END
  END rd_out[176]
  PIN rd_out[177]
    DIRECTION OUTPUT ;
    USE SIGNAL ;
    SHAPE ABUTMENT ;
    PORT
      LAYER M4 ;
      RECT 0.000 18.432 0.024 18.456 ;
    END
  END rd_out[177]
  PIN rd_out[178]
    DIRECTION OUTPUT ;
    USE SIGNAL ;
    SHAPE ABUTMENT ;
    PORT
      LAYER M4 ;
      RECT 0.000 18.528 0.024 18.552 ;
    END
  END rd_out[178]
  PIN rd_out[179]
    DIRECTION OUTPUT ;
    USE SIGNAL ;
    SHAPE ABUTMENT ;
    PORT
      LAYER M4 ;
      RECT 0.000 18.624 0.024 18.648 ;
    END
  END rd_out[179]
  PIN rd_out[180]
    DIRECTION OUTPUT ;
    USE SIGNAL ;
    SHAPE ABUTMENT ;
    PORT
      LAYER M4 ;
      RECT 0.000 18.720 0.024 18.744 ;
    END
  END rd_out[180]
  PIN rd_out[181]
    DIRECTION OUTPUT ;
    USE SIGNAL ;
    SHAPE ABUTMENT ;
    PORT
      LAYER M4 ;
      RECT 0.000 18.816 0.024 18.840 ;
    END
  END rd_out[181]
  PIN rd_out[182]
    DIRECTION OUTPUT ;
    USE SIGNAL ;
    SHAPE ABUTMENT ;
    PORT
      LAYER M4 ;
      RECT 0.000 18.912 0.024 18.936 ;
    END
  END rd_out[182]
  PIN rd_out[183]
    DIRECTION OUTPUT ;
    USE SIGNAL ;
    SHAPE ABUTMENT ;
    PORT
      LAYER M4 ;
      RECT 0.000 19.008 0.024 19.032 ;
    END
  END rd_out[183]
  PIN rd_out[184]
    DIRECTION OUTPUT ;
    USE SIGNAL ;
    SHAPE ABUTMENT ;
    PORT
      LAYER M4 ;
      RECT 0.000 19.104 0.024 19.128 ;
    END
  END rd_out[184]
  PIN rd_out[185]
    DIRECTION OUTPUT ;
    USE SIGNAL ;
    SHAPE ABUTMENT ;
    PORT
      LAYER M4 ;
      RECT 0.000 19.200 0.024 19.224 ;
    END
  END rd_out[185]
  PIN rd_out[186]
    DIRECTION OUTPUT ;
    USE SIGNAL ;
    SHAPE ABUTMENT ;
    PORT
      LAYER M4 ;
      RECT 0.000 19.296 0.024 19.320 ;
    END
  END rd_out[186]
  PIN rd_out[187]
    DIRECTION OUTPUT ;
    USE SIGNAL ;
    SHAPE ABUTMENT ;
    PORT
      LAYER M4 ;
      RECT 0.000 19.392 0.024 19.416 ;
    END
  END rd_out[187]
  PIN rd_out[188]
    DIRECTION OUTPUT ;
    USE SIGNAL ;
    SHAPE ABUTMENT ;
    PORT
      LAYER M4 ;
      RECT 0.000 19.488 0.024 19.512 ;
    END
  END rd_out[188]
  PIN rd_out[189]
    DIRECTION OUTPUT ;
    USE SIGNAL ;
    SHAPE ABUTMENT ;
    PORT
      LAYER M4 ;
      RECT 0.000 19.584 0.024 19.608 ;
    END
  END rd_out[189]
  PIN rd_out[190]
    DIRECTION OUTPUT ;
    USE SIGNAL ;
    SHAPE ABUTMENT ;
    PORT
      LAYER M4 ;
      RECT 0.000 19.680 0.024 19.704 ;
    END
  END rd_out[190]
  PIN rd_out[191]
    DIRECTION OUTPUT ;
    USE SIGNAL ;
    SHAPE ABUTMENT ;
    PORT
      LAYER M4 ;
      RECT 0.000 19.776 0.024 19.800 ;
    END
  END rd_out[191]
  PIN rd_out[192]
    DIRECTION OUTPUT ;
    USE SIGNAL ;
    SHAPE ABUTMENT ;
    PORT
      LAYER M4 ;
      RECT 0.000 19.872 0.024 19.896 ;
    END
  END rd_out[192]
  PIN rd_out[193]
    DIRECTION OUTPUT ;
    USE SIGNAL ;
    SHAPE ABUTMENT ;
    PORT
      LAYER M4 ;
      RECT 0.000 19.968 0.024 19.992 ;
    END
  END rd_out[193]
  PIN rd_out[194]
    DIRECTION OUTPUT ;
    USE SIGNAL ;
    SHAPE ABUTMENT ;
    PORT
      LAYER M4 ;
      RECT 0.000 20.064 0.024 20.088 ;
    END
  END rd_out[194]
  PIN rd_out[195]
    DIRECTION OUTPUT ;
    USE SIGNAL ;
    SHAPE ABUTMENT ;
    PORT
      LAYER M4 ;
      RECT 0.000 20.160 0.024 20.184 ;
    END
  END rd_out[195]
  PIN rd_out[196]
    DIRECTION OUTPUT ;
    USE SIGNAL ;
    SHAPE ABUTMENT ;
    PORT
      LAYER M4 ;
      RECT 0.000 20.256 0.024 20.280 ;
    END
  END rd_out[196]
  PIN rd_out[197]
    DIRECTION OUTPUT ;
    USE SIGNAL ;
    SHAPE ABUTMENT ;
    PORT
      LAYER M4 ;
      RECT 0.000 20.352 0.024 20.376 ;
    END
  END rd_out[197]
  PIN rd_out[198]
    DIRECTION OUTPUT ;
    USE SIGNAL ;
    SHAPE ABUTMENT ;
    PORT
      LAYER M4 ;
      RECT 0.000 20.448 0.024 20.472 ;
    END
  END rd_out[198]
  PIN rd_out[199]
    DIRECTION OUTPUT ;
    USE SIGNAL ;
    SHAPE ABUTMENT ;
    PORT
      LAYER M4 ;
      RECT 0.000 20.544 0.024 20.568 ;
    END
  END rd_out[199]
  PIN rd_out[200]
    DIRECTION OUTPUT ;
    USE SIGNAL ;
    SHAPE ABUTMENT ;
    PORT
      LAYER M4 ;
      RECT 0.000 20.640 0.024 20.664 ;
    END
  END rd_out[200]
  PIN rd_out[201]
    DIRECTION OUTPUT ;
    USE SIGNAL ;
    SHAPE ABUTMENT ;
    PORT
      LAYER M4 ;
      RECT 0.000 20.736 0.024 20.760 ;
    END
  END rd_out[201]
  PIN rd_out[202]
    DIRECTION OUTPUT ;
    USE SIGNAL ;
    SHAPE ABUTMENT ;
    PORT
      LAYER M4 ;
      RECT 0.000 20.832 0.024 20.856 ;
    END
  END rd_out[202]
  PIN rd_out[203]
    DIRECTION OUTPUT ;
    USE SIGNAL ;
    SHAPE ABUTMENT ;
    PORT
      LAYER M4 ;
      RECT 0.000 20.928 0.024 20.952 ;
    END
  END rd_out[203]
  PIN rd_out[204]
    DIRECTION OUTPUT ;
    USE SIGNAL ;
    SHAPE ABUTMENT ;
    PORT
      LAYER M4 ;
      RECT 0.000 21.024 0.024 21.048 ;
    END
  END rd_out[204]
  PIN rd_out[205]
    DIRECTION OUTPUT ;
    USE SIGNAL ;
    SHAPE ABUTMENT ;
    PORT
      LAYER M4 ;
      RECT 0.000 21.120 0.024 21.144 ;
    END
  END rd_out[205]
  PIN rd_out[206]
    DIRECTION OUTPUT ;
    USE SIGNAL ;
    SHAPE ABUTMENT ;
    PORT
      LAYER M4 ;
      RECT 0.000 21.216 0.024 21.240 ;
    END
  END rd_out[206]
  PIN rd_out[207]
    DIRECTION OUTPUT ;
    USE SIGNAL ;
    SHAPE ABUTMENT ;
    PORT
      LAYER M4 ;
      RECT 0.000 21.312 0.024 21.336 ;
    END
  END rd_out[207]
  PIN rd_out[208]
    DIRECTION OUTPUT ;
    USE SIGNAL ;
    SHAPE ABUTMENT ;
    PORT
      LAYER M4 ;
      RECT 0.000 21.408 0.024 21.432 ;
    END
  END rd_out[208]
  PIN rd_out[209]
    DIRECTION OUTPUT ;
    USE SIGNAL ;
    SHAPE ABUTMENT ;
    PORT
      LAYER M4 ;
      RECT 0.000 21.504 0.024 21.528 ;
    END
  END rd_out[209]
  PIN rd_out[210]
    DIRECTION OUTPUT ;
    USE SIGNAL ;
    SHAPE ABUTMENT ;
    PORT
      LAYER M4 ;
      RECT 0.000 21.600 0.024 21.624 ;
    END
  END rd_out[210]
  PIN rd_out[211]
    DIRECTION OUTPUT ;
    USE SIGNAL ;
    SHAPE ABUTMENT ;
    PORT
      LAYER M4 ;
      RECT 0.000 21.696 0.024 21.720 ;
    END
  END rd_out[211]
  PIN rd_out[212]
    DIRECTION OUTPUT ;
    USE SIGNAL ;
    SHAPE ABUTMENT ;
    PORT
      LAYER M4 ;
      RECT 0.000 21.792 0.024 21.816 ;
    END
  END rd_out[212]
  PIN rd_out[213]
    DIRECTION OUTPUT ;
    USE SIGNAL ;
    SHAPE ABUTMENT ;
    PORT
      LAYER M4 ;
      RECT 0.000 21.888 0.024 21.912 ;
    END
  END rd_out[213]
  PIN rd_out[214]
    DIRECTION OUTPUT ;
    USE SIGNAL ;
    SHAPE ABUTMENT ;
    PORT
      LAYER M4 ;
      RECT 0.000 21.984 0.024 22.008 ;
    END
  END rd_out[214]
  PIN rd_out[215]
    DIRECTION OUTPUT ;
    USE SIGNAL ;
    SHAPE ABUTMENT ;
    PORT
      LAYER M4 ;
      RECT 0.000 22.080 0.024 22.104 ;
    END
  END rd_out[215]
  PIN rd_out[216]
    DIRECTION OUTPUT ;
    USE SIGNAL ;
    SHAPE ABUTMENT ;
    PORT
      LAYER M4 ;
      RECT 0.000 22.176 0.024 22.200 ;
    END
  END rd_out[216]
  PIN rd_out[217]
    DIRECTION OUTPUT ;
    USE SIGNAL ;
    SHAPE ABUTMENT ;
    PORT
      LAYER M4 ;
      RECT 0.000 22.272 0.024 22.296 ;
    END
  END rd_out[217]
  PIN rd_out[218]
    DIRECTION OUTPUT ;
    USE SIGNAL ;
    SHAPE ABUTMENT ;
    PORT
      LAYER M4 ;
      RECT 0.000 22.368 0.024 22.392 ;
    END
  END rd_out[218]
  PIN rd_out[219]
    DIRECTION OUTPUT ;
    USE SIGNAL ;
    SHAPE ABUTMENT ;
    PORT
      LAYER M4 ;
      RECT 0.000 22.464 0.024 22.488 ;
    END
  END rd_out[219]
  PIN rd_out[220]
    DIRECTION OUTPUT ;
    USE SIGNAL ;
    SHAPE ABUTMENT ;
    PORT
      LAYER M4 ;
      RECT 0.000 22.560 0.024 22.584 ;
    END
  END rd_out[220]
  PIN rd_out[221]
    DIRECTION OUTPUT ;
    USE SIGNAL ;
    SHAPE ABUTMENT ;
    PORT
      LAYER M4 ;
      RECT 0.000 22.656 0.024 22.680 ;
    END
  END rd_out[221]
  PIN rd_out[222]
    DIRECTION OUTPUT ;
    USE SIGNAL ;
    SHAPE ABUTMENT ;
    PORT
      LAYER M4 ;
      RECT 0.000 22.752 0.024 22.776 ;
    END
  END rd_out[222]
  PIN rd_out[223]
    DIRECTION OUTPUT ;
    USE SIGNAL ;
    SHAPE ABUTMENT ;
    PORT
      LAYER M4 ;
      RECT 0.000 22.848 0.024 22.872 ;
    END
  END rd_out[223]
  PIN rd_out[224]
    DIRECTION OUTPUT ;
    USE SIGNAL ;
    SHAPE ABUTMENT ;
    PORT
      LAYER M4 ;
      RECT 0.000 22.944 0.024 22.968 ;
    END
  END rd_out[224]
  PIN rd_out[225]
    DIRECTION OUTPUT ;
    USE SIGNAL ;
    SHAPE ABUTMENT ;
    PORT
      LAYER M4 ;
      RECT 0.000 23.040 0.024 23.064 ;
    END
  END rd_out[225]
  PIN rd_out[226]
    DIRECTION OUTPUT ;
    USE SIGNAL ;
    SHAPE ABUTMENT ;
    PORT
      LAYER M4 ;
      RECT 0.000 23.136 0.024 23.160 ;
    END
  END rd_out[226]
  PIN rd_out[227]
    DIRECTION OUTPUT ;
    USE SIGNAL ;
    SHAPE ABUTMENT ;
    PORT
      LAYER M4 ;
      RECT 0.000 23.232 0.024 23.256 ;
    END
  END rd_out[227]
  PIN rd_out[228]
    DIRECTION OUTPUT ;
    USE SIGNAL ;
    SHAPE ABUTMENT ;
    PORT
      LAYER M4 ;
      RECT 0.000 23.328 0.024 23.352 ;
    END
  END rd_out[228]
  PIN rd_out[229]
    DIRECTION OUTPUT ;
    USE SIGNAL ;
    SHAPE ABUTMENT ;
    PORT
      LAYER M4 ;
      RECT 0.000 23.424 0.024 23.448 ;
    END
  END rd_out[229]
  PIN rd_out[230]
    DIRECTION OUTPUT ;
    USE SIGNAL ;
    SHAPE ABUTMENT ;
    PORT
      LAYER M4 ;
      RECT 0.000 23.520 0.024 23.544 ;
    END
  END rd_out[230]
  PIN rd_out[231]
    DIRECTION OUTPUT ;
    USE SIGNAL ;
    SHAPE ABUTMENT ;
    PORT
      LAYER M4 ;
      RECT 0.000 23.616 0.024 23.640 ;
    END
  END rd_out[231]
  PIN rd_out[232]
    DIRECTION OUTPUT ;
    USE SIGNAL ;
    SHAPE ABUTMENT ;
    PORT
      LAYER M4 ;
      RECT 0.000 23.712 0.024 23.736 ;
    END
  END rd_out[232]
  PIN rd_out[233]
    DIRECTION OUTPUT ;
    USE SIGNAL ;
    SHAPE ABUTMENT ;
    PORT
      LAYER M4 ;
      RECT 0.000 23.808 0.024 23.832 ;
    END
  END rd_out[233]
  PIN rd_out[234]
    DIRECTION OUTPUT ;
    USE SIGNAL ;
    SHAPE ABUTMENT ;
    PORT
      LAYER M4 ;
      RECT 0.000 23.904 0.024 23.928 ;
    END
  END rd_out[234]
  PIN rd_out[235]
    DIRECTION OUTPUT ;
    USE SIGNAL ;
    SHAPE ABUTMENT ;
    PORT
      LAYER M4 ;
      RECT 0.000 24.000 0.024 24.024 ;
    END
  END rd_out[235]
  PIN rd_out[236]
    DIRECTION OUTPUT ;
    USE SIGNAL ;
    SHAPE ABUTMENT ;
    PORT
      LAYER M4 ;
      RECT 0.000 24.096 0.024 24.120 ;
    END
  END rd_out[236]
  PIN rd_out[237]
    DIRECTION OUTPUT ;
    USE SIGNAL ;
    SHAPE ABUTMENT ;
    PORT
      LAYER M4 ;
      RECT 0.000 24.192 0.024 24.216 ;
    END
  END rd_out[237]
  PIN rd_out[238]
    DIRECTION OUTPUT ;
    USE SIGNAL ;
    SHAPE ABUTMENT ;
    PORT
      LAYER M4 ;
      RECT 0.000 24.288 0.024 24.312 ;
    END
  END rd_out[238]
  PIN rd_out[239]
    DIRECTION OUTPUT ;
    USE SIGNAL ;
    SHAPE ABUTMENT ;
    PORT
      LAYER M4 ;
      RECT 0.000 24.384 0.024 24.408 ;
    END
  END rd_out[239]
  PIN rd_out[240]
    DIRECTION OUTPUT ;
    USE SIGNAL ;
    SHAPE ABUTMENT ;
    PORT
      LAYER M4 ;
      RECT 0.000 24.480 0.024 24.504 ;
    END
  END rd_out[240]
  PIN rd_out[241]
    DIRECTION OUTPUT ;
    USE SIGNAL ;
    SHAPE ABUTMENT ;
    PORT
      LAYER M4 ;
      RECT 0.000 24.576 0.024 24.600 ;
    END
  END rd_out[241]
  PIN rd_out[242]
    DIRECTION OUTPUT ;
    USE SIGNAL ;
    SHAPE ABUTMENT ;
    PORT
      LAYER M4 ;
      RECT 0.000 24.672 0.024 24.696 ;
    END
  END rd_out[242]
  PIN rd_out[243]
    DIRECTION OUTPUT ;
    USE SIGNAL ;
    SHAPE ABUTMENT ;
    PORT
      LAYER M4 ;
      RECT 0.000 24.768 0.024 24.792 ;
    END
  END rd_out[243]
  PIN rd_out[244]
    DIRECTION OUTPUT ;
    USE SIGNAL ;
    SHAPE ABUTMENT ;
    PORT
      LAYER M4 ;
      RECT 0.000 24.864 0.024 24.888 ;
    END
  END rd_out[244]
  PIN rd_out[245]
    DIRECTION OUTPUT ;
    USE SIGNAL ;
    SHAPE ABUTMENT ;
    PORT
      LAYER M4 ;
      RECT 0.000 24.960 0.024 24.984 ;
    END
  END rd_out[245]
  PIN rd_out[246]
    DIRECTION OUTPUT ;
    USE SIGNAL ;
    SHAPE ABUTMENT ;
    PORT
      LAYER M4 ;
      RECT 0.000 25.056 0.024 25.080 ;
    END
  END rd_out[246]
  PIN rd_out[247]
    DIRECTION OUTPUT ;
    USE SIGNAL ;
    SHAPE ABUTMENT ;
    PORT
      LAYER M4 ;
      RECT 0.000 25.152 0.024 25.176 ;
    END
  END rd_out[247]
  PIN rd_out[248]
    DIRECTION OUTPUT ;
    USE SIGNAL ;
    SHAPE ABUTMENT ;
    PORT
      LAYER M4 ;
      RECT 0.000 25.248 0.024 25.272 ;
    END
  END rd_out[248]
  PIN rd_out[249]
    DIRECTION OUTPUT ;
    USE SIGNAL ;
    SHAPE ABUTMENT ;
    PORT
      LAYER M4 ;
      RECT 0.000 25.344 0.024 25.368 ;
    END
  END rd_out[249]
  PIN rd_out[250]
    DIRECTION OUTPUT ;
    USE SIGNAL ;
    SHAPE ABUTMENT ;
    PORT
      LAYER M4 ;
      RECT 0.000 25.440 0.024 25.464 ;
    END
  END rd_out[250]
  PIN rd_out[251]
    DIRECTION OUTPUT ;
    USE SIGNAL ;
    SHAPE ABUTMENT ;
    PORT
      LAYER M4 ;
      RECT 0.000 25.536 0.024 25.560 ;
    END
  END rd_out[251]
  PIN rd_out[252]
    DIRECTION OUTPUT ;
    USE SIGNAL ;
    SHAPE ABUTMENT ;
    PORT
      LAYER M4 ;
      RECT 0.000 25.632 0.024 25.656 ;
    END
  END rd_out[252]
  PIN rd_out[253]
    DIRECTION OUTPUT ;
    USE SIGNAL ;
    SHAPE ABUTMENT ;
    PORT
      LAYER M4 ;
      RECT 0.000 25.728 0.024 25.752 ;
    END
  END rd_out[253]
  PIN rd_out[254]
    DIRECTION OUTPUT ;
    USE SIGNAL ;
    SHAPE ABUTMENT ;
    PORT
      LAYER M4 ;
      RECT 0.000 25.824 0.024 25.848 ;
    END
  END rd_out[254]
  PIN rd_out[255]
    DIRECTION OUTPUT ;
    USE SIGNAL ;
    SHAPE ABUTMENT ;
    PORT
      LAYER M4 ;
      RECT 0.000 25.920 0.024 25.944 ;
    END
  END rd_out[255]
  PIN rd_out[256]
    DIRECTION OUTPUT ;
    USE SIGNAL ;
    SHAPE ABUTMENT ;
    PORT
      LAYER M4 ;
      RECT 0.000 26.016 0.024 26.040 ;
    END
  END rd_out[256]
  PIN rd_out[257]
    DIRECTION OUTPUT ;
    USE SIGNAL ;
    SHAPE ABUTMENT ;
    PORT
      LAYER M4 ;
      RECT 0.000 26.112 0.024 26.136 ;
    END
  END rd_out[257]
  PIN rd_out[258]
    DIRECTION OUTPUT ;
    USE SIGNAL ;
    SHAPE ABUTMENT ;
    PORT
      LAYER M4 ;
      RECT 0.000 26.208 0.024 26.232 ;
    END
  END rd_out[258]
  PIN rd_out[259]
    DIRECTION OUTPUT ;
    USE SIGNAL ;
    SHAPE ABUTMENT ;
    PORT
      LAYER M4 ;
      RECT 0.000 26.304 0.024 26.328 ;
    END
  END rd_out[259]
  PIN rd_out[260]
    DIRECTION OUTPUT ;
    USE SIGNAL ;
    SHAPE ABUTMENT ;
    PORT
      LAYER M4 ;
      RECT 0.000 26.400 0.024 26.424 ;
    END
  END rd_out[260]
  PIN rd_out[261]
    DIRECTION OUTPUT ;
    USE SIGNAL ;
    SHAPE ABUTMENT ;
    PORT
      LAYER M4 ;
      RECT 0.000 26.496 0.024 26.520 ;
    END
  END rd_out[261]
  PIN rd_out[262]
    DIRECTION OUTPUT ;
    USE SIGNAL ;
    SHAPE ABUTMENT ;
    PORT
      LAYER M4 ;
      RECT 0.000 26.592 0.024 26.616 ;
    END
  END rd_out[262]
  PIN rd_out[263]
    DIRECTION OUTPUT ;
    USE SIGNAL ;
    SHAPE ABUTMENT ;
    PORT
      LAYER M4 ;
      RECT 0.000 26.688 0.024 26.712 ;
    END
  END rd_out[263]
  PIN rd_out[264]
    DIRECTION OUTPUT ;
    USE SIGNAL ;
    SHAPE ABUTMENT ;
    PORT
      LAYER M4 ;
      RECT 0.000 26.784 0.024 26.808 ;
    END
  END rd_out[264]
  PIN rd_out[265]
    DIRECTION OUTPUT ;
    USE SIGNAL ;
    SHAPE ABUTMENT ;
    PORT
      LAYER M4 ;
      RECT 0.000 26.880 0.024 26.904 ;
    END
  END rd_out[265]
  PIN rd_out[266]
    DIRECTION OUTPUT ;
    USE SIGNAL ;
    SHAPE ABUTMENT ;
    PORT
      LAYER M4 ;
      RECT 0.000 26.976 0.024 27.000 ;
    END
  END rd_out[266]
  PIN rd_out[267]
    DIRECTION OUTPUT ;
    USE SIGNAL ;
    SHAPE ABUTMENT ;
    PORT
      LAYER M4 ;
      RECT 0.000 27.072 0.024 27.096 ;
    END
  END rd_out[267]
  PIN rd_out[268]
    DIRECTION OUTPUT ;
    USE SIGNAL ;
    SHAPE ABUTMENT ;
    PORT
      LAYER M4 ;
      RECT 0.000 27.168 0.024 27.192 ;
    END
  END rd_out[268]
  PIN rd_out[269]
    DIRECTION OUTPUT ;
    USE SIGNAL ;
    SHAPE ABUTMENT ;
    PORT
      LAYER M4 ;
      RECT 0.000 27.264 0.024 27.288 ;
    END
  END rd_out[269]
  PIN rd_out[270]
    DIRECTION OUTPUT ;
    USE SIGNAL ;
    SHAPE ABUTMENT ;
    PORT
      LAYER M4 ;
      RECT 0.000 27.360 0.024 27.384 ;
    END
  END rd_out[270]
  PIN rd_out[271]
    DIRECTION OUTPUT ;
    USE SIGNAL ;
    SHAPE ABUTMENT ;
    PORT
      LAYER M4 ;
      RECT 0.000 27.456 0.024 27.480 ;
    END
  END rd_out[271]
  PIN rd_out[272]
    DIRECTION OUTPUT ;
    USE SIGNAL ;
    SHAPE ABUTMENT ;
    PORT
      LAYER M4 ;
      RECT 0.000 27.552 0.024 27.576 ;
    END
  END rd_out[272]
  PIN rd_out[273]
    DIRECTION OUTPUT ;
    USE SIGNAL ;
    SHAPE ABUTMENT ;
    PORT
      LAYER M4 ;
      RECT 0.000 27.648 0.024 27.672 ;
    END
  END rd_out[273]
  PIN rd_out[274]
    DIRECTION OUTPUT ;
    USE SIGNAL ;
    SHAPE ABUTMENT ;
    PORT
      LAYER M4 ;
      RECT 0.000 27.744 0.024 27.768 ;
    END
  END rd_out[274]
  PIN rd_out[275]
    DIRECTION OUTPUT ;
    USE SIGNAL ;
    SHAPE ABUTMENT ;
    PORT
      LAYER M4 ;
      RECT 0.000 27.840 0.024 27.864 ;
    END
  END rd_out[275]
  PIN rd_out[276]
    DIRECTION OUTPUT ;
    USE SIGNAL ;
    SHAPE ABUTMENT ;
    PORT
      LAYER M4 ;
      RECT 0.000 27.936 0.024 27.960 ;
    END
  END rd_out[276]
  PIN rd_out[277]
    DIRECTION OUTPUT ;
    USE SIGNAL ;
    SHAPE ABUTMENT ;
    PORT
      LAYER M4 ;
      RECT 0.000 28.032 0.024 28.056 ;
    END
  END rd_out[277]
  PIN rd_out[278]
    DIRECTION OUTPUT ;
    USE SIGNAL ;
    SHAPE ABUTMENT ;
    PORT
      LAYER M4 ;
      RECT 0.000 28.128 0.024 28.152 ;
    END
  END rd_out[278]
  PIN rd_out[279]
    DIRECTION OUTPUT ;
    USE SIGNAL ;
    SHAPE ABUTMENT ;
    PORT
      LAYER M4 ;
      RECT 0.000 28.224 0.024 28.248 ;
    END
  END rd_out[279]
  PIN rd_out[280]
    DIRECTION OUTPUT ;
    USE SIGNAL ;
    SHAPE ABUTMENT ;
    PORT
      LAYER M4 ;
      RECT 0.000 28.320 0.024 28.344 ;
    END
  END rd_out[280]
  PIN rd_out[281]
    DIRECTION OUTPUT ;
    USE SIGNAL ;
    SHAPE ABUTMENT ;
    PORT
      LAYER M4 ;
      RECT 0.000 28.416 0.024 28.440 ;
    END
  END rd_out[281]
  PIN rd_out[282]
    DIRECTION OUTPUT ;
    USE SIGNAL ;
    SHAPE ABUTMENT ;
    PORT
      LAYER M4 ;
      RECT 0.000 28.512 0.024 28.536 ;
    END
  END rd_out[282]
  PIN rd_out[283]
    DIRECTION OUTPUT ;
    USE SIGNAL ;
    SHAPE ABUTMENT ;
    PORT
      LAYER M4 ;
      RECT 0.000 28.608 0.024 28.632 ;
    END
  END rd_out[283]
  PIN rd_out[284]
    DIRECTION OUTPUT ;
    USE SIGNAL ;
    SHAPE ABUTMENT ;
    PORT
      LAYER M4 ;
      RECT 0.000 28.704 0.024 28.728 ;
    END
  END rd_out[284]
  PIN rd_out[285]
    DIRECTION OUTPUT ;
    USE SIGNAL ;
    SHAPE ABUTMENT ;
    PORT
      LAYER M4 ;
      RECT 0.000 28.800 0.024 28.824 ;
    END
  END rd_out[285]
  PIN rd_out[286]
    DIRECTION OUTPUT ;
    USE SIGNAL ;
    SHAPE ABUTMENT ;
    PORT
      LAYER M4 ;
      RECT 0.000 28.896 0.024 28.920 ;
    END
  END rd_out[286]
  PIN rd_out[287]
    DIRECTION OUTPUT ;
    USE SIGNAL ;
    SHAPE ABUTMENT ;
    PORT
      LAYER M4 ;
      RECT 0.000 28.992 0.024 29.016 ;
    END
  END rd_out[287]
  PIN rd_out[288]
    DIRECTION OUTPUT ;
    USE SIGNAL ;
    SHAPE ABUTMENT ;
    PORT
      LAYER M4 ;
      RECT 0.000 29.088 0.024 29.112 ;
    END
  END rd_out[288]
  PIN rd_out[289]
    DIRECTION OUTPUT ;
    USE SIGNAL ;
    SHAPE ABUTMENT ;
    PORT
      LAYER M4 ;
      RECT 0.000 29.184 0.024 29.208 ;
    END
  END rd_out[289]
  PIN rd_out[290]
    DIRECTION OUTPUT ;
    USE SIGNAL ;
    SHAPE ABUTMENT ;
    PORT
      LAYER M4 ;
      RECT 0.000 29.280 0.024 29.304 ;
    END
  END rd_out[290]
  PIN rd_out[291]
    DIRECTION OUTPUT ;
    USE SIGNAL ;
    SHAPE ABUTMENT ;
    PORT
      LAYER M4 ;
      RECT 0.000 29.376 0.024 29.400 ;
    END
  END rd_out[291]
  PIN rd_out[292]
    DIRECTION OUTPUT ;
    USE SIGNAL ;
    SHAPE ABUTMENT ;
    PORT
      LAYER M4 ;
      RECT 0.000 29.472 0.024 29.496 ;
    END
  END rd_out[292]
  PIN rd_out[293]
    DIRECTION OUTPUT ;
    USE SIGNAL ;
    SHAPE ABUTMENT ;
    PORT
      LAYER M4 ;
      RECT 0.000 29.568 0.024 29.592 ;
    END
  END rd_out[293]
  PIN rd_out[294]
    DIRECTION OUTPUT ;
    USE SIGNAL ;
    SHAPE ABUTMENT ;
    PORT
      LAYER M4 ;
      RECT 0.000 29.664 0.024 29.688 ;
    END
  END rd_out[294]
  PIN rd_out[295]
    DIRECTION OUTPUT ;
    USE SIGNAL ;
    SHAPE ABUTMENT ;
    PORT
      LAYER M4 ;
      RECT 0.000 29.760 0.024 29.784 ;
    END
  END rd_out[295]
  PIN rd_out[296]
    DIRECTION OUTPUT ;
    USE SIGNAL ;
    SHAPE ABUTMENT ;
    PORT
      LAYER M4 ;
      RECT 0.000 29.856 0.024 29.880 ;
    END
  END rd_out[296]
  PIN rd_out[297]
    DIRECTION OUTPUT ;
    USE SIGNAL ;
    SHAPE ABUTMENT ;
    PORT
      LAYER M4 ;
      RECT 0.000 29.952 0.024 29.976 ;
    END
  END rd_out[297]
  PIN rd_out[298]
    DIRECTION OUTPUT ;
    USE SIGNAL ;
    SHAPE ABUTMENT ;
    PORT
      LAYER M4 ;
      RECT 0.000 30.048 0.024 30.072 ;
    END
  END rd_out[298]
  PIN rd_out[299]
    DIRECTION OUTPUT ;
    USE SIGNAL ;
    SHAPE ABUTMENT ;
    PORT
      LAYER M4 ;
      RECT 0.000 30.144 0.024 30.168 ;
    END
  END rd_out[299]
  PIN rd_out[300]
    DIRECTION OUTPUT ;
    USE SIGNAL ;
    SHAPE ABUTMENT ;
    PORT
      LAYER M4 ;
      RECT 0.000 30.240 0.024 30.264 ;
    END
  END rd_out[300]
  PIN rd_out[301]
    DIRECTION OUTPUT ;
    USE SIGNAL ;
    SHAPE ABUTMENT ;
    PORT
      LAYER M4 ;
      RECT 0.000 30.336 0.024 30.360 ;
    END
  END rd_out[301]
  PIN rd_out[302]
    DIRECTION OUTPUT ;
    USE SIGNAL ;
    SHAPE ABUTMENT ;
    PORT
      LAYER M4 ;
      RECT 0.000 30.432 0.024 30.456 ;
    END
  END rd_out[302]
  PIN rd_out[303]
    DIRECTION OUTPUT ;
    USE SIGNAL ;
    SHAPE ABUTMENT ;
    PORT
      LAYER M4 ;
      RECT 0.000 30.528 0.024 30.552 ;
    END
  END rd_out[303]
  PIN rd_out[304]
    DIRECTION OUTPUT ;
    USE SIGNAL ;
    SHAPE ABUTMENT ;
    PORT
      LAYER M4 ;
      RECT 0.000 30.624 0.024 30.648 ;
    END
  END rd_out[304]
  PIN rd_out[305]
    DIRECTION OUTPUT ;
    USE SIGNAL ;
    SHAPE ABUTMENT ;
    PORT
      LAYER M4 ;
      RECT 0.000 30.720 0.024 30.744 ;
    END
  END rd_out[305]
  PIN rd_out[306]
    DIRECTION OUTPUT ;
    USE SIGNAL ;
    SHAPE ABUTMENT ;
    PORT
      LAYER M4 ;
      RECT 0.000 30.816 0.024 30.840 ;
    END
  END rd_out[306]
  PIN rd_out[307]
    DIRECTION OUTPUT ;
    USE SIGNAL ;
    SHAPE ABUTMENT ;
    PORT
      LAYER M4 ;
      RECT 0.000 30.912 0.024 30.936 ;
    END
  END rd_out[307]
  PIN rd_out[308]
    DIRECTION OUTPUT ;
    USE SIGNAL ;
    SHAPE ABUTMENT ;
    PORT
      LAYER M4 ;
      RECT 0.000 31.008 0.024 31.032 ;
    END
  END rd_out[308]
  PIN rd_out[309]
    DIRECTION OUTPUT ;
    USE SIGNAL ;
    SHAPE ABUTMENT ;
    PORT
      LAYER M4 ;
      RECT 0.000 31.104 0.024 31.128 ;
    END
  END rd_out[309]
  PIN rd_out[310]
    DIRECTION OUTPUT ;
    USE SIGNAL ;
    SHAPE ABUTMENT ;
    PORT
      LAYER M4 ;
      RECT 0.000 31.200 0.024 31.224 ;
    END
  END rd_out[310]
  PIN rd_out[311]
    DIRECTION OUTPUT ;
    USE SIGNAL ;
    SHAPE ABUTMENT ;
    PORT
      LAYER M4 ;
      RECT 0.000 31.296 0.024 31.320 ;
    END
  END rd_out[311]
  PIN rd_out[312]
    DIRECTION OUTPUT ;
    USE SIGNAL ;
    SHAPE ABUTMENT ;
    PORT
      LAYER M4 ;
      RECT 0.000 31.392 0.024 31.416 ;
    END
  END rd_out[312]
  PIN rd_out[313]
    DIRECTION OUTPUT ;
    USE SIGNAL ;
    SHAPE ABUTMENT ;
    PORT
      LAYER M4 ;
      RECT 0.000 31.488 0.024 31.512 ;
    END
  END rd_out[313]
  PIN rd_out[314]
    DIRECTION OUTPUT ;
    USE SIGNAL ;
    SHAPE ABUTMENT ;
    PORT
      LAYER M4 ;
      RECT 0.000 31.584 0.024 31.608 ;
    END
  END rd_out[314]
  PIN rd_out[315]
    DIRECTION OUTPUT ;
    USE SIGNAL ;
    SHAPE ABUTMENT ;
    PORT
      LAYER M4 ;
      RECT 0.000 31.680 0.024 31.704 ;
    END
  END rd_out[315]
  PIN rd_out[316]
    DIRECTION OUTPUT ;
    USE SIGNAL ;
    SHAPE ABUTMENT ;
    PORT
      LAYER M4 ;
      RECT 0.000 31.776 0.024 31.800 ;
    END
  END rd_out[316]
  PIN rd_out[317]
    DIRECTION OUTPUT ;
    USE SIGNAL ;
    SHAPE ABUTMENT ;
    PORT
      LAYER M4 ;
      RECT 0.000 31.872 0.024 31.896 ;
    END
  END rd_out[317]
  PIN rd_out[318]
    DIRECTION OUTPUT ;
    USE SIGNAL ;
    SHAPE ABUTMENT ;
    PORT
      LAYER M4 ;
      RECT 0.000 31.968 0.024 31.992 ;
    END
  END rd_out[318]
  PIN rd_out[319]
    DIRECTION OUTPUT ;
    USE SIGNAL ;
    SHAPE ABUTMENT ;
    PORT
      LAYER M4 ;
      RECT 0.000 32.064 0.024 32.088 ;
    END
  END rd_out[319]
  PIN rd_out[320]
    DIRECTION OUTPUT ;
    USE SIGNAL ;
    SHAPE ABUTMENT ;
    PORT
      LAYER M4 ;
      RECT 0.000 32.160 0.024 32.184 ;
    END
  END rd_out[320]
  PIN rd_out[321]
    DIRECTION OUTPUT ;
    USE SIGNAL ;
    SHAPE ABUTMENT ;
    PORT
      LAYER M4 ;
      RECT 0.000 32.256 0.024 32.280 ;
    END
  END rd_out[321]
  PIN rd_out[322]
    DIRECTION OUTPUT ;
    USE SIGNAL ;
    SHAPE ABUTMENT ;
    PORT
      LAYER M4 ;
      RECT 0.000 32.352 0.024 32.376 ;
    END
  END rd_out[322]
  PIN rd_out[323]
    DIRECTION OUTPUT ;
    USE SIGNAL ;
    SHAPE ABUTMENT ;
    PORT
      LAYER M4 ;
      RECT 0.000 32.448 0.024 32.472 ;
    END
  END rd_out[323]
  PIN rd_out[324]
    DIRECTION OUTPUT ;
    USE SIGNAL ;
    SHAPE ABUTMENT ;
    PORT
      LAYER M4 ;
      RECT 0.000 32.544 0.024 32.568 ;
    END
  END rd_out[324]
  PIN rd_out[325]
    DIRECTION OUTPUT ;
    USE SIGNAL ;
    SHAPE ABUTMENT ;
    PORT
      LAYER M4 ;
      RECT 0.000 32.640 0.024 32.664 ;
    END
  END rd_out[325]
  PIN rd_out[326]
    DIRECTION OUTPUT ;
    USE SIGNAL ;
    SHAPE ABUTMENT ;
    PORT
      LAYER M4 ;
      RECT 0.000 32.736 0.024 32.760 ;
    END
  END rd_out[326]
  PIN rd_out[327]
    DIRECTION OUTPUT ;
    USE SIGNAL ;
    SHAPE ABUTMENT ;
    PORT
      LAYER M4 ;
      RECT 0.000 32.832 0.024 32.856 ;
    END
  END rd_out[327]
  PIN rd_out[328]
    DIRECTION OUTPUT ;
    USE SIGNAL ;
    SHAPE ABUTMENT ;
    PORT
      LAYER M4 ;
      RECT 0.000 32.928 0.024 32.952 ;
    END
  END rd_out[328]
  PIN rd_out[329]
    DIRECTION OUTPUT ;
    USE SIGNAL ;
    SHAPE ABUTMENT ;
    PORT
      LAYER M4 ;
      RECT 0.000 33.024 0.024 33.048 ;
    END
  END rd_out[329]
  PIN rd_out[330]
    DIRECTION OUTPUT ;
    USE SIGNAL ;
    SHAPE ABUTMENT ;
    PORT
      LAYER M4 ;
      RECT 0.000 33.120 0.024 33.144 ;
    END
  END rd_out[330]
  PIN rd_out[331]
    DIRECTION OUTPUT ;
    USE SIGNAL ;
    SHAPE ABUTMENT ;
    PORT
      LAYER M4 ;
      RECT 0.000 33.216 0.024 33.240 ;
    END
  END rd_out[331]
  PIN rd_out[332]
    DIRECTION OUTPUT ;
    USE SIGNAL ;
    SHAPE ABUTMENT ;
    PORT
      LAYER M4 ;
      RECT 0.000 33.312 0.024 33.336 ;
    END
  END rd_out[332]
  PIN rd_out[333]
    DIRECTION OUTPUT ;
    USE SIGNAL ;
    SHAPE ABUTMENT ;
    PORT
      LAYER M4 ;
      RECT 0.000 33.408 0.024 33.432 ;
    END
  END rd_out[333]
  PIN rd_out[334]
    DIRECTION OUTPUT ;
    USE SIGNAL ;
    SHAPE ABUTMENT ;
    PORT
      LAYER M4 ;
      RECT 0.000 33.504 0.024 33.528 ;
    END
  END rd_out[334]
  PIN rd_out[335]
    DIRECTION OUTPUT ;
    USE SIGNAL ;
    SHAPE ABUTMENT ;
    PORT
      LAYER M4 ;
      RECT 0.000 33.600 0.024 33.624 ;
    END
  END rd_out[335]
  PIN rd_out[336]
    DIRECTION OUTPUT ;
    USE SIGNAL ;
    SHAPE ABUTMENT ;
    PORT
      LAYER M4 ;
      RECT 0.000 33.696 0.024 33.720 ;
    END
  END rd_out[336]
  PIN rd_out[337]
    DIRECTION OUTPUT ;
    USE SIGNAL ;
    SHAPE ABUTMENT ;
    PORT
      LAYER M4 ;
      RECT 0.000 33.792 0.024 33.816 ;
    END
  END rd_out[337]
  PIN rd_out[338]
    DIRECTION OUTPUT ;
    USE SIGNAL ;
    SHAPE ABUTMENT ;
    PORT
      LAYER M4 ;
      RECT 0.000 33.888 0.024 33.912 ;
    END
  END rd_out[338]
  PIN rd_out[339]
    DIRECTION OUTPUT ;
    USE SIGNAL ;
    SHAPE ABUTMENT ;
    PORT
      LAYER M4 ;
      RECT 0.000 33.984 0.024 34.008 ;
    END
  END rd_out[339]
  PIN rd_out[340]
    DIRECTION OUTPUT ;
    USE SIGNAL ;
    SHAPE ABUTMENT ;
    PORT
      LAYER M4 ;
      RECT 0.000 34.080 0.024 34.104 ;
    END
  END rd_out[340]
  PIN rd_out[341]
    DIRECTION OUTPUT ;
    USE SIGNAL ;
    SHAPE ABUTMENT ;
    PORT
      LAYER M4 ;
      RECT 0.000 34.176 0.024 34.200 ;
    END
  END rd_out[341]
  PIN rd_out[342]
    DIRECTION OUTPUT ;
    USE SIGNAL ;
    SHAPE ABUTMENT ;
    PORT
      LAYER M4 ;
      RECT 0.000 34.272 0.024 34.296 ;
    END
  END rd_out[342]
  PIN rd_out[343]
    DIRECTION OUTPUT ;
    USE SIGNAL ;
    SHAPE ABUTMENT ;
    PORT
      LAYER M4 ;
      RECT 0.000 34.368 0.024 34.392 ;
    END
  END rd_out[343]
  PIN rd_out[344]
    DIRECTION OUTPUT ;
    USE SIGNAL ;
    SHAPE ABUTMENT ;
    PORT
      LAYER M4 ;
      RECT 0.000 34.464 0.024 34.488 ;
    END
  END rd_out[344]
  PIN rd_out[345]
    DIRECTION OUTPUT ;
    USE SIGNAL ;
    SHAPE ABUTMENT ;
    PORT
      LAYER M4 ;
      RECT 0.000 34.560 0.024 34.584 ;
    END
  END rd_out[345]
  PIN rd_out[346]
    DIRECTION OUTPUT ;
    USE SIGNAL ;
    SHAPE ABUTMENT ;
    PORT
      LAYER M4 ;
      RECT 0.000 34.656 0.024 34.680 ;
    END
  END rd_out[346]
  PIN rd_out[347]
    DIRECTION OUTPUT ;
    USE SIGNAL ;
    SHAPE ABUTMENT ;
    PORT
      LAYER M4 ;
      RECT 0.000 34.752 0.024 34.776 ;
    END
  END rd_out[347]
  PIN rd_out[348]
    DIRECTION OUTPUT ;
    USE SIGNAL ;
    SHAPE ABUTMENT ;
    PORT
      LAYER M4 ;
      RECT 0.000 34.848 0.024 34.872 ;
    END
  END rd_out[348]
  PIN rd_out[349]
    DIRECTION OUTPUT ;
    USE SIGNAL ;
    SHAPE ABUTMENT ;
    PORT
      LAYER M4 ;
      RECT 0.000 34.944 0.024 34.968 ;
    END
  END rd_out[349]
  PIN rd_out[350]
    DIRECTION OUTPUT ;
    USE SIGNAL ;
    SHAPE ABUTMENT ;
    PORT
      LAYER M4 ;
      RECT 0.000 35.040 0.024 35.064 ;
    END
  END rd_out[350]
  PIN rd_out[351]
    DIRECTION OUTPUT ;
    USE SIGNAL ;
    SHAPE ABUTMENT ;
    PORT
      LAYER M4 ;
      RECT 0.000 35.136 0.024 35.160 ;
    END
  END rd_out[351]
  PIN rd_out[352]
    DIRECTION OUTPUT ;
    USE SIGNAL ;
    SHAPE ABUTMENT ;
    PORT
      LAYER M4 ;
      RECT 0.000 35.232 0.024 35.256 ;
    END
  END rd_out[352]
  PIN rd_out[353]
    DIRECTION OUTPUT ;
    USE SIGNAL ;
    SHAPE ABUTMENT ;
    PORT
      LAYER M4 ;
      RECT 0.000 35.328 0.024 35.352 ;
    END
  END rd_out[353]
  PIN rd_out[354]
    DIRECTION OUTPUT ;
    USE SIGNAL ;
    SHAPE ABUTMENT ;
    PORT
      LAYER M4 ;
      RECT 0.000 35.424 0.024 35.448 ;
    END
  END rd_out[354]
  PIN rd_out[355]
    DIRECTION OUTPUT ;
    USE SIGNAL ;
    SHAPE ABUTMENT ;
    PORT
      LAYER M4 ;
      RECT 0.000 35.520 0.024 35.544 ;
    END
  END rd_out[355]
  PIN rd_out[356]
    DIRECTION OUTPUT ;
    USE SIGNAL ;
    SHAPE ABUTMENT ;
    PORT
      LAYER M4 ;
      RECT 0.000 35.616 0.024 35.640 ;
    END
  END rd_out[356]
  PIN rd_out[357]
    DIRECTION OUTPUT ;
    USE SIGNAL ;
    SHAPE ABUTMENT ;
    PORT
      LAYER M4 ;
      RECT 0.000 35.712 0.024 35.736 ;
    END
  END rd_out[357]
  PIN rd_out[358]
    DIRECTION OUTPUT ;
    USE SIGNAL ;
    SHAPE ABUTMENT ;
    PORT
      LAYER M4 ;
      RECT 0.000 35.808 0.024 35.832 ;
    END
  END rd_out[358]
  PIN rd_out[359]
    DIRECTION OUTPUT ;
    USE SIGNAL ;
    SHAPE ABUTMENT ;
    PORT
      LAYER M4 ;
      RECT 0.000 35.904 0.024 35.928 ;
    END
  END rd_out[359]
  PIN rd_out[360]
    DIRECTION OUTPUT ;
    USE SIGNAL ;
    SHAPE ABUTMENT ;
    PORT
      LAYER M4 ;
      RECT 0.000 36.000 0.024 36.024 ;
    END
  END rd_out[360]
  PIN rd_out[361]
    DIRECTION OUTPUT ;
    USE SIGNAL ;
    SHAPE ABUTMENT ;
    PORT
      LAYER M4 ;
      RECT 0.000 36.096 0.024 36.120 ;
    END
  END rd_out[361]
  PIN rd_out[362]
    DIRECTION OUTPUT ;
    USE SIGNAL ;
    SHAPE ABUTMENT ;
    PORT
      LAYER M4 ;
      RECT 0.000 36.192 0.024 36.216 ;
    END
  END rd_out[362]
  PIN rd_out[363]
    DIRECTION OUTPUT ;
    USE SIGNAL ;
    SHAPE ABUTMENT ;
    PORT
      LAYER M4 ;
      RECT 0.000 36.288 0.024 36.312 ;
    END
  END rd_out[363]
  PIN rd_out[364]
    DIRECTION OUTPUT ;
    USE SIGNAL ;
    SHAPE ABUTMENT ;
    PORT
      LAYER M4 ;
      RECT 0.000 36.384 0.024 36.408 ;
    END
  END rd_out[364]
  PIN rd_out[365]
    DIRECTION OUTPUT ;
    USE SIGNAL ;
    SHAPE ABUTMENT ;
    PORT
      LAYER M4 ;
      RECT 0.000 36.480 0.024 36.504 ;
    END
  END rd_out[365]
  PIN rd_out[366]
    DIRECTION OUTPUT ;
    USE SIGNAL ;
    SHAPE ABUTMENT ;
    PORT
      LAYER M4 ;
      RECT 0.000 36.576 0.024 36.600 ;
    END
  END rd_out[366]
  PIN rd_out[367]
    DIRECTION OUTPUT ;
    USE SIGNAL ;
    SHAPE ABUTMENT ;
    PORT
      LAYER M4 ;
      RECT 0.000 36.672 0.024 36.696 ;
    END
  END rd_out[367]
  PIN rd_out[368]
    DIRECTION OUTPUT ;
    USE SIGNAL ;
    SHAPE ABUTMENT ;
    PORT
      LAYER M4 ;
      RECT 0.000 36.768 0.024 36.792 ;
    END
  END rd_out[368]
  PIN rd_out[369]
    DIRECTION OUTPUT ;
    USE SIGNAL ;
    SHAPE ABUTMENT ;
    PORT
      LAYER M4 ;
      RECT 0.000 36.864 0.024 36.888 ;
    END
  END rd_out[369]
  PIN rd_out[370]
    DIRECTION OUTPUT ;
    USE SIGNAL ;
    SHAPE ABUTMENT ;
    PORT
      LAYER M4 ;
      RECT 0.000 36.960 0.024 36.984 ;
    END
  END rd_out[370]
  PIN rd_out[371]
    DIRECTION OUTPUT ;
    USE SIGNAL ;
    SHAPE ABUTMENT ;
    PORT
      LAYER M4 ;
      RECT 0.000 37.056 0.024 37.080 ;
    END
  END rd_out[371]
  PIN rd_out[372]
    DIRECTION OUTPUT ;
    USE SIGNAL ;
    SHAPE ABUTMENT ;
    PORT
      LAYER M4 ;
      RECT 0.000 37.152 0.024 37.176 ;
    END
  END rd_out[372]
  PIN rd_out[373]
    DIRECTION OUTPUT ;
    USE SIGNAL ;
    SHAPE ABUTMENT ;
    PORT
      LAYER M4 ;
      RECT 0.000 37.248 0.024 37.272 ;
    END
  END rd_out[373]
  PIN rd_out[374]
    DIRECTION OUTPUT ;
    USE SIGNAL ;
    SHAPE ABUTMENT ;
    PORT
      LAYER M4 ;
      RECT 0.000 37.344 0.024 37.368 ;
    END
  END rd_out[374]
  PIN rd_out[375]
    DIRECTION OUTPUT ;
    USE SIGNAL ;
    SHAPE ABUTMENT ;
    PORT
      LAYER M4 ;
      RECT 0.000 37.440 0.024 37.464 ;
    END
  END rd_out[375]
  PIN rd_out[376]
    DIRECTION OUTPUT ;
    USE SIGNAL ;
    SHAPE ABUTMENT ;
    PORT
      LAYER M4 ;
      RECT 0.000 37.536 0.024 37.560 ;
    END
  END rd_out[376]
  PIN rd_out[377]
    DIRECTION OUTPUT ;
    USE SIGNAL ;
    SHAPE ABUTMENT ;
    PORT
      LAYER M4 ;
      RECT 0.000 37.632 0.024 37.656 ;
    END
  END rd_out[377]
  PIN rd_out[378]
    DIRECTION OUTPUT ;
    USE SIGNAL ;
    SHAPE ABUTMENT ;
    PORT
      LAYER M4 ;
      RECT 0.000 37.728 0.024 37.752 ;
    END
  END rd_out[378]
  PIN rd_out[379]
    DIRECTION OUTPUT ;
    USE SIGNAL ;
    SHAPE ABUTMENT ;
    PORT
      LAYER M4 ;
      RECT 0.000 37.824 0.024 37.848 ;
    END
  END rd_out[379]
  PIN rd_out[380]
    DIRECTION OUTPUT ;
    USE SIGNAL ;
    SHAPE ABUTMENT ;
    PORT
      LAYER M4 ;
      RECT 0.000 37.920 0.024 37.944 ;
    END
  END rd_out[380]
  PIN rd_out[381]
    DIRECTION OUTPUT ;
    USE SIGNAL ;
    SHAPE ABUTMENT ;
    PORT
      LAYER M4 ;
      RECT 0.000 38.016 0.024 38.040 ;
    END
  END rd_out[381]
  PIN rd_out[382]
    DIRECTION OUTPUT ;
    USE SIGNAL ;
    SHAPE ABUTMENT ;
    PORT
      LAYER M4 ;
      RECT 0.000 38.112 0.024 38.136 ;
    END
  END rd_out[382]
  PIN rd_out[383]
    DIRECTION OUTPUT ;
    USE SIGNAL ;
    SHAPE ABUTMENT ;
    PORT
      LAYER M4 ;
      RECT 0.000 38.208 0.024 38.232 ;
    END
  END rd_out[383]
  PIN rd_out[384]
    DIRECTION OUTPUT ;
    USE SIGNAL ;
    SHAPE ABUTMENT ;
    PORT
      LAYER M4 ;
      RECT 0.000 38.304 0.024 38.328 ;
    END
  END rd_out[384]
  PIN rd_out[385]
    DIRECTION OUTPUT ;
    USE SIGNAL ;
    SHAPE ABUTMENT ;
    PORT
      LAYER M4 ;
      RECT 0.000 38.400 0.024 38.424 ;
    END
  END rd_out[385]
  PIN rd_out[386]
    DIRECTION OUTPUT ;
    USE SIGNAL ;
    SHAPE ABUTMENT ;
    PORT
      LAYER M4 ;
      RECT 0.000 38.496 0.024 38.520 ;
    END
  END rd_out[386]
  PIN rd_out[387]
    DIRECTION OUTPUT ;
    USE SIGNAL ;
    SHAPE ABUTMENT ;
    PORT
      LAYER M4 ;
      RECT 0.000 38.592 0.024 38.616 ;
    END
  END rd_out[387]
  PIN rd_out[388]
    DIRECTION OUTPUT ;
    USE SIGNAL ;
    SHAPE ABUTMENT ;
    PORT
      LAYER M4 ;
      RECT 0.000 38.688 0.024 38.712 ;
    END
  END rd_out[388]
  PIN rd_out[389]
    DIRECTION OUTPUT ;
    USE SIGNAL ;
    SHAPE ABUTMENT ;
    PORT
      LAYER M4 ;
      RECT 0.000 38.784 0.024 38.808 ;
    END
  END rd_out[389]
  PIN rd_out[390]
    DIRECTION OUTPUT ;
    USE SIGNAL ;
    SHAPE ABUTMENT ;
    PORT
      LAYER M4 ;
      RECT 0.000 38.880 0.024 38.904 ;
    END
  END rd_out[390]
  PIN rd_out[391]
    DIRECTION OUTPUT ;
    USE SIGNAL ;
    SHAPE ABUTMENT ;
    PORT
      LAYER M4 ;
      RECT 0.000 38.976 0.024 39.000 ;
    END
  END rd_out[391]
  PIN rd_out[392]
    DIRECTION OUTPUT ;
    USE SIGNAL ;
    SHAPE ABUTMENT ;
    PORT
      LAYER M4 ;
      RECT 0.000 39.072 0.024 39.096 ;
    END
  END rd_out[392]
  PIN rd_out[393]
    DIRECTION OUTPUT ;
    USE SIGNAL ;
    SHAPE ABUTMENT ;
    PORT
      LAYER M4 ;
      RECT 0.000 39.168 0.024 39.192 ;
    END
  END rd_out[393]
  PIN rd_out[394]
    DIRECTION OUTPUT ;
    USE SIGNAL ;
    SHAPE ABUTMENT ;
    PORT
      LAYER M4 ;
      RECT 0.000 39.264 0.024 39.288 ;
    END
  END rd_out[394]
  PIN rd_out[395]
    DIRECTION OUTPUT ;
    USE SIGNAL ;
    SHAPE ABUTMENT ;
    PORT
      LAYER M4 ;
      RECT 0.000 39.360 0.024 39.384 ;
    END
  END rd_out[395]
  PIN rd_out[396]
    DIRECTION OUTPUT ;
    USE SIGNAL ;
    SHAPE ABUTMENT ;
    PORT
      LAYER M4 ;
      RECT 0.000 39.456 0.024 39.480 ;
    END
  END rd_out[396]
  PIN rd_out[397]
    DIRECTION OUTPUT ;
    USE SIGNAL ;
    SHAPE ABUTMENT ;
    PORT
      LAYER M4 ;
      RECT 0.000 39.552 0.024 39.576 ;
    END
  END rd_out[397]
  PIN rd_out[398]
    DIRECTION OUTPUT ;
    USE SIGNAL ;
    SHAPE ABUTMENT ;
    PORT
      LAYER M4 ;
      RECT 0.000 39.648 0.024 39.672 ;
    END
  END rd_out[398]
  PIN rd_out[399]
    DIRECTION OUTPUT ;
    USE SIGNAL ;
    SHAPE ABUTMENT ;
    PORT
      LAYER M4 ;
      RECT 0.000 39.744 0.024 39.768 ;
    END
  END rd_out[399]
  PIN rd_out[400]
    DIRECTION OUTPUT ;
    USE SIGNAL ;
    SHAPE ABUTMENT ;
    PORT
      LAYER M4 ;
      RECT 0.000 39.840 0.024 39.864 ;
    END
  END rd_out[400]
  PIN rd_out[401]
    DIRECTION OUTPUT ;
    USE SIGNAL ;
    SHAPE ABUTMENT ;
    PORT
      LAYER M4 ;
      RECT 0.000 39.936 0.024 39.960 ;
    END
  END rd_out[401]
  PIN rd_out[402]
    DIRECTION OUTPUT ;
    USE SIGNAL ;
    SHAPE ABUTMENT ;
    PORT
      LAYER M4 ;
      RECT 0.000 40.032 0.024 40.056 ;
    END
  END rd_out[402]
  PIN rd_out[403]
    DIRECTION OUTPUT ;
    USE SIGNAL ;
    SHAPE ABUTMENT ;
    PORT
      LAYER M4 ;
      RECT 0.000 40.128 0.024 40.152 ;
    END
  END rd_out[403]
  PIN rd_out[404]
    DIRECTION OUTPUT ;
    USE SIGNAL ;
    SHAPE ABUTMENT ;
    PORT
      LAYER M4 ;
      RECT 0.000 40.224 0.024 40.248 ;
    END
  END rd_out[404]
  PIN rd_out[405]
    DIRECTION OUTPUT ;
    USE SIGNAL ;
    SHAPE ABUTMENT ;
    PORT
      LAYER M4 ;
      RECT 0.000 40.320 0.024 40.344 ;
    END
  END rd_out[405]
  PIN rd_out[406]
    DIRECTION OUTPUT ;
    USE SIGNAL ;
    SHAPE ABUTMENT ;
    PORT
      LAYER M4 ;
      RECT 0.000 40.416 0.024 40.440 ;
    END
  END rd_out[406]
  PIN rd_out[407]
    DIRECTION OUTPUT ;
    USE SIGNAL ;
    SHAPE ABUTMENT ;
    PORT
      LAYER M4 ;
      RECT 0.000 40.512 0.024 40.536 ;
    END
  END rd_out[407]
  PIN rd_out[408]
    DIRECTION OUTPUT ;
    USE SIGNAL ;
    SHAPE ABUTMENT ;
    PORT
      LAYER M4 ;
      RECT 0.000 40.608 0.024 40.632 ;
    END
  END rd_out[408]
  PIN rd_out[409]
    DIRECTION OUTPUT ;
    USE SIGNAL ;
    SHAPE ABUTMENT ;
    PORT
      LAYER M4 ;
      RECT 0.000 40.704 0.024 40.728 ;
    END
  END rd_out[409]
  PIN rd_out[410]
    DIRECTION OUTPUT ;
    USE SIGNAL ;
    SHAPE ABUTMENT ;
    PORT
      LAYER M4 ;
      RECT 0.000 40.800 0.024 40.824 ;
    END
  END rd_out[410]
  PIN rd_out[411]
    DIRECTION OUTPUT ;
    USE SIGNAL ;
    SHAPE ABUTMENT ;
    PORT
      LAYER M4 ;
      RECT 0.000 40.896 0.024 40.920 ;
    END
  END rd_out[411]
  PIN rd_out[412]
    DIRECTION OUTPUT ;
    USE SIGNAL ;
    SHAPE ABUTMENT ;
    PORT
      LAYER M4 ;
      RECT 0.000 40.992 0.024 41.016 ;
    END
  END rd_out[412]
  PIN rd_out[413]
    DIRECTION OUTPUT ;
    USE SIGNAL ;
    SHAPE ABUTMENT ;
    PORT
      LAYER M4 ;
      RECT 0.000 41.088 0.024 41.112 ;
    END
  END rd_out[413]
  PIN rd_out[414]
    DIRECTION OUTPUT ;
    USE SIGNAL ;
    SHAPE ABUTMENT ;
    PORT
      LAYER M4 ;
      RECT 0.000 41.184 0.024 41.208 ;
    END
  END rd_out[414]
  PIN rd_out[415]
    DIRECTION OUTPUT ;
    USE SIGNAL ;
    SHAPE ABUTMENT ;
    PORT
      LAYER M4 ;
      RECT 0.000 41.280 0.024 41.304 ;
    END
  END rd_out[415]
  PIN rd_out[416]
    DIRECTION OUTPUT ;
    USE SIGNAL ;
    SHAPE ABUTMENT ;
    PORT
      LAYER M4 ;
      RECT 0.000 41.376 0.024 41.400 ;
    END
  END rd_out[416]
  PIN rd_out[417]
    DIRECTION OUTPUT ;
    USE SIGNAL ;
    SHAPE ABUTMENT ;
    PORT
      LAYER M4 ;
      RECT 0.000 41.472 0.024 41.496 ;
    END
  END rd_out[417]
  PIN rd_out[418]
    DIRECTION OUTPUT ;
    USE SIGNAL ;
    SHAPE ABUTMENT ;
    PORT
      LAYER M4 ;
      RECT 0.000 41.568 0.024 41.592 ;
    END
  END rd_out[418]
  PIN rd_out[419]
    DIRECTION OUTPUT ;
    USE SIGNAL ;
    SHAPE ABUTMENT ;
    PORT
      LAYER M4 ;
      RECT 0.000 41.664 0.024 41.688 ;
    END
  END rd_out[419]
  PIN rd_out[420]
    DIRECTION OUTPUT ;
    USE SIGNAL ;
    SHAPE ABUTMENT ;
    PORT
      LAYER M4 ;
      RECT 0.000 41.760 0.024 41.784 ;
    END
  END rd_out[420]
  PIN rd_out[421]
    DIRECTION OUTPUT ;
    USE SIGNAL ;
    SHAPE ABUTMENT ;
    PORT
      LAYER M4 ;
      RECT 0.000 41.856 0.024 41.880 ;
    END
  END rd_out[421]
  PIN rd_out[422]
    DIRECTION OUTPUT ;
    USE SIGNAL ;
    SHAPE ABUTMENT ;
    PORT
      LAYER M4 ;
      RECT 0.000 41.952 0.024 41.976 ;
    END
  END rd_out[422]
  PIN rd_out[423]
    DIRECTION OUTPUT ;
    USE SIGNAL ;
    SHAPE ABUTMENT ;
    PORT
      LAYER M4 ;
      RECT 0.000 42.048 0.024 42.072 ;
    END
  END rd_out[423]
  PIN rd_out[424]
    DIRECTION OUTPUT ;
    USE SIGNAL ;
    SHAPE ABUTMENT ;
    PORT
      LAYER M4 ;
      RECT 0.000 42.144 0.024 42.168 ;
    END
  END rd_out[424]
  PIN rd_out[425]
    DIRECTION OUTPUT ;
    USE SIGNAL ;
    SHAPE ABUTMENT ;
    PORT
      LAYER M4 ;
      RECT 0.000 42.240 0.024 42.264 ;
    END
  END rd_out[425]
  PIN rd_out[426]
    DIRECTION OUTPUT ;
    USE SIGNAL ;
    SHAPE ABUTMENT ;
    PORT
      LAYER M4 ;
      RECT 0.000 42.336 0.024 42.360 ;
    END
  END rd_out[426]
  PIN rd_out[427]
    DIRECTION OUTPUT ;
    USE SIGNAL ;
    SHAPE ABUTMENT ;
    PORT
      LAYER M4 ;
      RECT 0.000 42.432 0.024 42.456 ;
    END
  END rd_out[427]
  PIN rd_out[428]
    DIRECTION OUTPUT ;
    USE SIGNAL ;
    SHAPE ABUTMENT ;
    PORT
      LAYER M4 ;
      RECT 0.000 42.528 0.024 42.552 ;
    END
  END rd_out[428]
  PIN rd_out[429]
    DIRECTION OUTPUT ;
    USE SIGNAL ;
    SHAPE ABUTMENT ;
    PORT
      LAYER M4 ;
      RECT 0.000 42.624 0.024 42.648 ;
    END
  END rd_out[429]
  PIN rd_out[430]
    DIRECTION OUTPUT ;
    USE SIGNAL ;
    SHAPE ABUTMENT ;
    PORT
      LAYER M4 ;
      RECT 0.000 42.720 0.024 42.744 ;
    END
  END rd_out[430]
  PIN rd_out[431]
    DIRECTION OUTPUT ;
    USE SIGNAL ;
    SHAPE ABUTMENT ;
    PORT
      LAYER M4 ;
      RECT 0.000 42.816 0.024 42.840 ;
    END
  END rd_out[431]
  PIN rd_out[432]
    DIRECTION OUTPUT ;
    USE SIGNAL ;
    SHAPE ABUTMENT ;
    PORT
      LAYER M4 ;
      RECT 0.000 42.912 0.024 42.936 ;
    END
  END rd_out[432]
  PIN rd_out[433]
    DIRECTION OUTPUT ;
    USE SIGNAL ;
    SHAPE ABUTMENT ;
    PORT
      LAYER M4 ;
      RECT 0.000 43.008 0.024 43.032 ;
    END
  END rd_out[433]
  PIN rd_out[434]
    DIRECTION OUTPUT ;
    USE SIGNAL ;
    SHAPE ABUTMENT ;
    PORT
      LAYER M4 ;
      RECT 0.000 43.104 0.024 43.128 ;
    END
  END rd_out[434]
  PIN rd_out[435]
    DIRECTION OUTPUT ;
    USE SIGNAL ;
    SHAPE ABUTMENT ;
    PORT
      LAYER M4 ;
      RECT 0.000 43.200 0.024 43.224 ;
    END
  END rd_out[435]
  PIN rd_out[436]
    DIRECTION OUTPUT ;
    USE SIGNAL ;
    SHAPE ABUTMENT ;
    PORT
      LAYER M4 ;
      RECT 0.000 43.296 0.024 43.320 ;
    END
  END rd_out[436]
  PIN rd_out[437]
    DIRECTION OUTPUT ;
    USE SIGNAL ;
    SHAPE ABUTMENT ;
    PORT
      LAYER M4 ;
      RECT 0.000 43.392 0.024 43.416 ;
    END
  END rd_out[437]
  PIN rd_out[438]
    DIRECTION OUTPUT ;
    USE SIGNAL ;
    SHAPE ABUTMENT ;
    PORT
      LAYER M4 ;
      RECT 0.000 43.488 0.024 43.512 ;
    END
  END rd_out[438]
  PIN rd_out[439]
    DIRECTION OUTPUT ;
    USE SIGNAL ;
    SHAPE ABUTMENT ;
    PORT
      LAYER M4 ;
      RECT 0.000 43.584 0.024 43.608 ;
    END
  END rd_out[439]
  PIN rd_out[440]
    DIRECTION OUTPUT ;
    USE SIGNAL ;
    SHAPE ABUTMENT ;
    PORT
      LAYER M4 ;
      RECT 0.000 43.680 0.024 43.704 ;
    END
  END rd_out[440]
  PIN rd_out[441]
    DIRECTION OUTPUT ;
    USE SIGNAL ;
    SHAPE ABUTMENT ;
    PORT
      LAYER M4 ;
      RECT 0.000 43.776 0.024 43.800 ;
    END
  END rd_out[441]
  PIN rd_out[442]
    DIRECTION OUTPUT ;
    USE SIGNAL ;
    SHAPE ABUTMENT ;
    PORT
      LAYER M4 ;
      RECT 0.000 43.872 0.024 43.896 ;
    END
  END rd_out[442]
  PIN rd_out[443]
    DIRECTION OUTPUT ;
    USE SIGNAL ;
    SHAPE ABUTMENT ;
    PORT
      LAYER M4 ;
      RECT 0.000 43.968 0.024 43.992 ;
    END
  END rd_out[443]
  PIN rd_out[444]
    DIRECTION OUTPUT ;
    USE SIGNAL ;
    SHAPE ABUTMENT ;
    PORT
      LAYER M4 ;
      RECT 0.000 44.064 0.024 44.088 ;
    END
  END rd_out[444]
  PIN rd_out[445]
    DIRECTION OUTPUT ;
    USE SIGNAL ;
    SHAPE ABUTMENT ;
    PORT
      LAYER M4 ;
      RECT 0.000 44.160 0.024 44.184 ;
    END
  END rd_out[445]
  PIN rd_out[446]
    DIRECTION OUTPUT ;
    USE SIGNAL ;
    SHAPE ABUTMENT ;
    PORT
      LAYER M4 ;
      RECT 0.000 44.256 0.024 44.280 ;
    END
  END rd_out[446]
  PIN rd_out[447]
    DIRECTION OUTPUT ;
    USE SIGNAL ;
    SHAPE ABUTMENT ;
    PORT
      LAYER M4 ;
      RECT 0.000 44.352 0.024 44.376 ;
    END
  END rd_out[447]
  PIN rd_out[448]
    DIRECTION OUTPUT ;
    USE SIGNAL ;
    SHAPE ABUTMENT ;
    PORT
      LAYER M4 ;
      RECT 0.000 44.448 0.024 44.472 ;
    END
  END rd_out[448]
  PIN rd_out[449]
    DIRECTION OUTPUT ;
    USE SIGNAL ;
    SHAPE ABUTMENT ;
    PORT
      LAYER M4 ;
      RECT 0.000 44.544 0.024 44.568 ;
    END
  END rd_out[449]
  PIN rd_out[450]
    DIRECTION OUTPUT ;
    USE SIGNAL ;
    SHAPE ABUTMENT ;
    PORT
      LAYER M4 ;
      RECT 0.000 44.640 0.024 44.664 ;
    END
  END rd_out[450]
  PIN rd_out[451]
    DIRECTION OUTPUT ;
    USE SIGNAL ;
    SHAPE ABUTMENT ;
    PORT
      LAYER M4 ;
      RECT 0.000 44.736 0.024 44.760 ;
    END
  END rd_out[451]
  PIN rd_out[452]
    DIRECTION OUTPUT ;
    USE SIGNAL ;
    SHAPE ABUTMENT ;
    PORT
      LAYER M4 ;
      RECT 0.000 44.832 0.024 44.856 ;
    END
  END rd_out[452]
  PIN rd_out[453]
    DIRECTION OUTPUT ;
    USE SIGNAL ;
    SHAPE ABUTMENT ;
    PORT
      LAYER M4 ;
      RECT 0.000 44.928 0.024 44.952 ;
    END
  END rd_out[453]
  PIN rd_out[454]
    DIRECTION OUTPUT ;
    USE SIGNAL ;
    SHAPE ABUTMENT ;
    PORT
      LAYER M4 ;
      RECT 0.000 45.024 0.024 45.048 ;
    END
  END rd_out[454]
  PIN rd_out[455]
    DIRECTION OUTPUT ;
    USE SIGNAL ;
    SHAPE ABUTMENT ;
    PORT
      LAYER M4 ;
      RECT 0.000 45.120 0.024 45.144 ;
    END
  END rd_out[455]
  PIN rd_out[456]
    DIRECTION OUTPUT ;
    USE SIGNAL ;
    SHAPE ABUTMENT ;
    PORT
      LAYER M4 ;
      RECT 0.000 45.216 0.024 45.240 ;
    END
  END rd_out[456]
  PIN rd_out[457]
    DIRECTION OUTPUT ;
    USE SIGNAL ;
    SHAPE ABUTMENT ;
    PORT
      LAYER M4 ;
      RECT 0.000 45.312 0.024 45.336 ;
    END
  END rd_out[457]
  PIN rd_out[458]
    DIRECTION OUTPUT ;
    USE SIGNAL ;
    SHAPE ABUTMENT ;
    PORT
      LAYER M4 ;
      RECT 0.000 45.408 0.024 45.432 ;
    END
  END rd_out[458]
  PIN rd_out[459]
    DIRECTION OUTPUT ;
    USE SIGNAL ;
    SHAPE ABUTMENT ;
    PORT
      LAYER M4 ;
      RECT 0.000 45.504 0.024 45.528 ;
    END
  END rd_out[459]
  PIN rd_out[460]
    DIRECTION OUTPUT ;
    USE SIGNAL ;
    SHAPE ABUTMENT ;
    PORT
      LAYER M4 ;
      RECT 0.000 45.600 0.024 45.624 ;
    END
  END rd_out[460]
  PIN rd_out[461]
    DIRECTION OUTPUT ;
    USE SIGNAL ;
    SHAPE ABUTMENT ;
    PORT
      LAYER M4 ;
      RECT 0.000 45.696 0.024 45.720 ;
    END
  END rd_out[461]
  PIN rd_out[462]
    DIRECTION OUTPUT ;
    USE SIGNAL ;
    SHAPE ABUTMENT ;
    PORT
      LAYER M4 ;
      RECT 0.000 45.792 0.024 45.816 ;
    END
  END rd_out[462]
  PIN rd_out[463]
    DIRECTION OUTPUT ;
    USE SIGNAL ;
    SHAPE ABUTMENT ;
    PORT
      LAYER M4 ;
      RECT 0.000 45.888 0.024 45.912 ;
    END
  END rd_out[463]
  PIN rd_out[464]
    DIRECTION OUTPUT ;
    USE SIGNAL ;
    SHAPE ABUTMENT ;
    PORT
      LAYER M4 ;
      RECT 0.000 45.984 0.024 46.008 ;
    END
  END rd_out[464]
  PIN rd_out[465]
    DIRECTION OUTPUT ;
    USE SIGNAL ;
    SHAPE ABUTMENT ;
    PORT
      LAYER M4 ;
      RECT 0.000 46.080 0.024 46.104 ;
    END
  END rd_out[465]
  PIN rd_out[466]
    DIRECTION OUTPUT ;
    USE SIGNAL ;
    SHAPE ABUTMENT ;
    PORT
      LAYER M4 ;
      RECT 0.000 46.176 0.024 46.200 ;
    END
  END rd_out[466]
  PIN rd_out[467]
    DIRECTION OUTPUT ;
    USE SIGNAL ;
    SHAPE ABUTMENT ;
    PORT
      LAYER M4 ;
      RECT 0.000 46.272 0.024 46.296 ;
    END
  END rd_out[467]
  PIN rd_out[468]
    DIRECTION OUTPUT ;
    USE SIGNAL ;
    SHAPE ABUTMENT ;
    PORT
      LAYER M4 ;
      RECT 0.000 46.368 0.024 46.392 ;
    END
  END rd_out[468]
  PIN rd_out[469]
    DIRECTION OUTPUT ;
    USE SIGNAL ;
    SHAPE ABUTMENT ;
    PORT
      LAYER M4 ;
      RECT 0.000 46.464 0.024 46.488 ;
    END
  END rd_out[469]
  PIN rd_out[470]
    DIRECTION OUTPUT ;
    USE SIGNAL ;
    SHAPE ABUTMENT ;
    PORT
      LAYER M4 ;
      RECT 0.000 46.560 0.024 46.584 ;
    END
  END rd_out[470]
  PIN rd_out[471]
    DIRECTION OUTPUT ;
    USE SIGNAL ;
    SHAPE ABUTMENT ;
    PORT
      LAYER M4 ;
      RECT 0.000 46.656 0.024 46.680 ;
    END
  END rd_out[471]
  PIN rd_out[472]
    DIRECTION OUTPUT ;
    USE SIGNAL ;
    SHAPE ABUTMENT ;
    PORT
      LAYER M4 ;
      RECT 0.000 46.752 0.024 46.776 ;
    END
  END rd_out[472]
  PIN rd_out[473]
    DIRECTION OUTPUT ;
    USE SIGNAL ;
    SHAPE ABUTMENT ;
    PORT
      LAYER M4 ;
      RECT 0.000 46.848 0.024 46.872 ;
    END
  END rd_out[473]
  PIN rd_out[474]
    DIRECTION OUTPUT ;
    USE SIGNAL ;
    SHAPE ABUTMENT ;
    PORT
      LAYER M4 ;
      RECT 0.000 46.944 0.024 46.968 ;
    END
  END rd_out[474]
  PIN rd_out[475]
    DIRECTION OUTPUT ;
    USE SIGNAL ;
    SHAPE ABUTMENT ;
    PORT
      LAYER M4 ;
      RECT 0.000 47.040 0.024 47.064 ;
    END
  END rd_out[475]
  PIN rd_out[476]
    DIRECTION OUTPUT ;
    USE SIGNAL ;
    SHAPE ABUTMENT ;
    PORT
      LAYER M4 ;
      RECT 0.000 47.136 0.024 47.160 ;
    END
  END rd_out[476]
  PIN rd_out[477]
    DIRECTION OUTPUT ;
    USE SIGNAL ;
    SHAPE ABUTMENT ;
    PORT
      LAYER M4 ;
      RECT 0.000 47.232 0.024 47.256 ;
    END
  END rd_out[477]
  PIN rd_out[478]
    DIRECTION OUTPUT ;
    USE SIGNAL ;
    SHAPE ABUTMENT ;
    PORT
      LAYER M4 ;
      RECT 0.000 47.328 0.024 47.352 ;
    END
  END rd_out[478]
  PIN rd_out[479]
    DIRECTION OUTPUT ;
    USE SIGNAL ;
    SHAPE ABUTMENT ;
    PORT
      LAYER M4 ;
      RECT 0.000 47.424 0.024 47.448 ;
    END
  END rd_out[479]
  PIN rd_out[480]
    DIRECTION OUTPUT ;
    USE SIGNAL ;
    SHAPE ABUTMENT ;
    PORT
      LAYER M4 ;
      RECT 0.000 47.520 0.024 47.544 ;
    END
  END rd_out[480]
  PIN rd_out[481]
    DIRECTION OUTPUT ;
    USE SIGNAL ;
    SHAPE ABUTMENT ;
    PORT
      LAYER M4 ;
      RECT 0.000 47.616 0.024 47.640 ;
    END
  END rd_out[481]
  PIN rd_out[482]
    DIRECTION OUTPUT ;
    USE SIGNAL ;
    SHAPE ABUTMENT ;
    PORT
      LAYER M4 ;
      RECT 0.000 47.712 0.024 47.736 ;
    END
  END rd_out[482]
  PIN rd_out[483]
    DIRECTION OUTPUT ;
    USE SIGNAL ;
    SHAPE ABUTMENT ;
    PORT
      LAYER M4 ;
      RECT 0.000 47.808 0.024 47.832 ;
    END
  END rd_out[483]
  PIN rd_out[484]
    DIRECTION OUTPUT ;
    USE SIGNAL ;
    SHAPE ABUTMENT ;
    PORT
      LAYER M4 ;
      RECT 0.000 47.904 0.024 47.928 ;
    END
  END rd_out[484]
  PIN rd_out[485]
    DIRECTION OUTPUT ;
    USE SIGNAL ;
    SHAPE ABUTMENT ;
    PORT
      LAYER M4 ;
      RECT 0.000 48.000 0.024 48.024 ;
    END
  END rd_out[485]
  PIN rd_out[486]
    DIRECTION OUTPUT ;
    USE SIGNAL ;
    SHAPE ABUTMENT ;
    PORT
      LAYER M4 ;
      RECT 0.000 48.096 0.024 48.120 ;
    END
  END rd_out[486]
  PIN rd_out[487]
    DIRECTION OUTPUT ;
    USE SIGNAL ;
    SHAPE ABUTMENT ;
    PORT
      LAYER M4 ;
      RECT 0.000 48.192 0.024 48.216 ;
    END
  END rd_out[487]
  PIN rd_out[488]
    DIRECTION OUTPUT ;
    USE SIGNAL ;
    SHAPE ABUTMENT ;
    PORT
      LAYER M4 ;
      RECT 0.000 48.288 0.024 48.312 ;
    END
  END rd_out[488]
  PIN rd_out[489]
    DIRECTION OUTPUT ;
    USE SIGNAL ;
    SHAPE ABUTMENT ;
    PORT
      LAYER M4 ;
      RECT 0.000 48.384 0.024 48.408 ;
    END
  END rd_out[489]
  PIN rd_out[490]
    DIRECTION OUTPUT ;
    USE SIGNAL ;
    SHAPE ABUTMENT ;
    PORT
      LAYER M4 ;
      RECT 0.000 48.480 0.024 48.504 ;
    END
  END rd_out[490]
  PIN rd_out[491]
    DIRECTION OUTPUT ;
    USE SIGNAL ;
    SHAPE ABUTMENT ;
    PORT
      LAYER M4 ;
      RECT 0.000 48.576 0.024 48.600 ;
    END
  END rd_out[491]
  PIN rd_out[492]
    DIRECTION OUTPUT ;
    USE SIGNAL ;
    SHAPE ABUTMENT ;
    PORT
      LAYER M4 ;
      RECT 0.000 48.672 0.024 48.696 ;
    END
  END rd_out[492]
  PIN rd_out[493]
    DIRECTION OUTPUT ;
    USE SIGNAL ;
    SHAPE ABUTMENT ;
    PORT
      LAYER M4 ;
      RECT 0.000 48.768 0.024 48.792 ;
    END
  END rd_out[493]
  PIN rd_out[494]
    DIRECTION OUTPUT ;
    USE SIGNAL ;
    SHAPE ABUTMENT ;
    PORT
      LAYER M4 ;
      RECT 0.000 48.864 0.024 48.888 ;
    END
  END rd_out[494]
  PIN rd_out[495]
    DIRECTION OUTPUT ;
    USE SIGNAL ;
    SHAPE ABUTMENT ;
    PORT
      LAYER M4 ;
      RECT 0.000 48.960 0.024 48.984 ;
    END
  END rd_out[495]
  PIN rd_out[496]
    DIRECTION OUTPUT ;
    USE SIGNAL ;
    SHAPE ABUTMENT ;
    PORT
      LAYER M4 ;
      RECT 0.000 49.056 0.024 49.080 ;
    END
  END rd_out[496]
  PIN rd_out[497]
    DIRECTION OUTPUT ;
    USE SIGNAL ;
    SHAPE ABUTMENT ;
    PORT
      LAYER M4 ;
      RECT 0.000 49.152 0.024 49.176 ;
    END
  END rd_out[497]
  PIN rd_out[498]
    DIRECTION OUTPUT ;
    USE SIGNAL ;
    SHAPE ABUTMENT ;
    PORT
      LAYER M4 ;
      RECT 0.000 49.248 0.024 49.272 ;
    END
  END rd_out[498]
  PIN rd_out[499]
    DIRECTION OUTPUT ;
    USE SIGNAL ;
    SHAPE ABUTMENT ;
    PORT
      LAYER M4 ;
      RECT 0.000 49.344 0.024 49.368 ;
    END
  END rd_out[499]
  PIN rd_out[500]
    DIRECTION OUTPUT ;
    USE SIGNAL ;
    SHAPE ABUTMENT ;
    PORT
      LAYER M4 ;
      RECT 0.000 49.440 0.024 49.464 ;
    END
  END rd_out[500]
  PIN rd_out[501]
    DIRECTION OUTPUT ;
    USE SIGNAL ;
    SHAPE ABUTMENT ;
    PORT
      LAYER M4 ;
      RECT 0.000 49.536 0.024 49.560 ;
    END
  END rd_out[501]
  PIN rd_out[502]
    DIRECTION OUTPUT ;
    USE SIGNAL ;
    SHAPE ABUTMENT ;
    PORT
      LAYER M4 ;
      RECT 0.000 49.632 0.024 49.656 ;
    END
  END rd_out[502]
  PIN rd_out[503]
    DIRECTION OUTPUT ;
    USE SIGNAL ;
    SHAPE ABUTMENT ;
    PORT
      LAYER M4 ;
      RECT 0.000 49.728 0.024 49.752 ;
    END
  END rd_out[503]
  PIN rd_out[504]
    DIRECTION OUTPUT ;
    USE SIGNAL ;
    SHAPE ABUTMENT ;
    PORT
      LAYER M4 ;
      RECT 0.000 49.824 0.024 49.848 ;
    END
  END rd_out[504]
  PIN rd_out[505]
    DIRECTION OUTPUT ;
    USE SIGNAL ;
    SHAPE ABUTMENT ;
    PORT
      LAYER M4 ;
      RECT 0.000 49.920 0.024 49.944 ;
    END
  END rd_out[505]
  PIN rd_out[506]
    DIRECTION OUTPUT ;
    USE SIGNAL ;
    SHAPE ABUTMENT ;
    PORT
      LAYER M4 ;
      RECT 0.000 50.016 0.024 50.040 ;
    END
  END rd_out[506]
  PIN rd_out[507]
    DIRECTION OUTPUT ;
    USE SIGNAL ;
    SHAPE ABUTMENT ;
    PORT
      LAYER M4 ;
      RECT 0.000 50.112 0.024 50.136 ;
    END
  END rd_out[507]
  PIN rd_out[508]
    DIRECTION OUTPUT ;
    USE SIGNAL ;
    SHAPE ABUTMENT ;
    PORT
      LAYER M4 ;
      RECT 0.000 50.208 0.024 50.232 ;
    END
  END rd_out[508]
  PIN rd_out[509]
    DIRECTION OUTPUT ;
    USE SIGNAL ;
    SHAPE ABUTMENT ;
    PORT
      LAYER M4 ;
      RECT 0.000 50.304 0.024 50.328 ;
    END
  END rd_out[509]
  PIN rd_out[510]
    DIRECTION OUTPUT ;
    USE SIGNAL ;
    SHAPE ABUTMENT ;
    PORT
      LAYER M4 ;
      RECT 0.000 50.400 0.024 50.424 ;
    END
  END rd_out[510]
  PIN rd_out[511]
    DIRECTION OUTPUT ;
    USE SIGNAL ;
    SHAPE ABUTMENT ;
    PORT
      LAYER M4 ;
      RECT 0.000 50.496 0.024 50.520 ;
    END
  END rd_out[511]
  PIN rd_out[512]
    DIRECTION OUTPUT ;
    USE SIGNAL ;
    SHAPE ABUTMENT ;
    PORT
      LAYER M4 ;
      RECT 0.000 50.592 0.024 50.616 ;
    END
  END rd_out[512]
  PIN rd_out[513]
    DIRECTION OUTPUT ;
    USE SIGNAL ;
    SHAPE ABUTMENT ;
    PORT
      LAYER M4 ;
      RECT 0.000 50.688 0.024 50.712 ;
    END
  END rd_out[513]
  PIN rd_out[514]
    DIRECTION OUTPUT ;
    USE SIGNAL ;
    SHAPE ABUTMENT ;
    PORT
      LAYER M4 ;
      RECT 0.000 50.784 0.024 50.808 ;
    END
  END rd_out[514]
  PIN rd_out[515]
    DIRECTION OUTPUT ;
    USE SIGNAL ;
    SHAPE ABUTMENT ;
    PORT
      LAYER M4 ;
      RECT 0.000 50.880 0.024 50.904 ;
    END
  END rd_out[515]
  PIN rd_out[516]
    DIRECTION OUTPUT ;
    USE SIGNAL ;
    SHAPE ABUTMENT ;
    PORT
      LAYER M4 ;
      RECT 0.000 50.976 0.024 51.000 ;
    END
  END rd_out[516]
  PIN rd_out[517]
    DIRECTION OUTPUT ;
    USE SIGNAL ;
    SHAPE ABUTMENT ;
    PORT
      LAYER M4 ;
      RECT 0.000 51.072 0.024 51.096 ;
    END
  END rd_out[517]
  PIN rd_out[518]
    DIRECTION OUTPUT ;
    USE SIGNAL ;
    SHAPE ABUTMENT ;
    PORT
      LAYER M4 ;
      RECT 0.000 51.168 0.024 51.192 ;
    END
  END rd_out[518]
  PIN rd_out[519]
    DIRECTION OUTPUT ;
    USE SIGNAL ;
    SHAPE ABUTMENT ;
    PORT
      LAYER M4 ;
      RECT 0.000 51.264 0.024 51.288 ;
    END
  END rd_out[519]
  PIN rd_out[520]
    DIRECTION OUTPUT ;
    USE SIGNAL ;
    SHAPE ABUTMENT ;
    PORT
      LAYER M4 ;
      RECT 0.000 51.360 0.024 51.384 ;
    END
  END rd_out[520]
  PIN rd_out[521]
    DIRECTION OUTPUT ;
    USE SIGNAL ;
    SHAPE ABUTMENT ;
    PORT
      LAYER M4 ;
      RECT 0.000 51.456 0.024 51.480 ;
    END
  END rd_out[521]
  PIN rd_out[522]
    DIRECTION OUTPUT ;
    USE SIGNAL ;
    SHAPE ABUTMENT ;
    PORT
      LAYER M4 ;
      RECT 0.000 51.552 0.024 51.576 ;
    END
  END rd_out[522]
  PIN rd_out[523]
    DIRECTION OUTPUT ;
    USE SIGNAL ;
    SHAPE ABUTMENT ;
    PORT
      LAYER M4 ;
      RECT 0.000 51.648 0.024 51.672 ;
    END
  END rd_out[523]
  PIN rd_out[524]
    DIRECTION OUTPUT ;
    USE SIGNAL ;
    SHAPE ABUTMENT ;
    PORT
      LAYER M4 ;
      RECT 0.000 51.744 0.024 51.768 ;
    END
  END rd_out[524]
  PIN rd_out[525]
    DIRECTION OUTPUT ;
    USE SIGNAL ;
    SHAPE ABUTMENT ;
    PORT
      LAYER M4 ;
      RECT 0.000 51.840 0.024 51.864 ;
    END
  END rd_out[525]
  PIN rd_out[526]
    DIRECTION OUTPUT ;
    USE SIGNAL ;
    SHAPE ABUTMENT ;
    PORT
      LAYER M4 ;
      RECT 0.000 51.936 0.024 51.960 ;
    END
  END rd_out[526]
  PIN rd_out[527]
    DIRECTION OUTPUT ;
    USE SIGNAL ;
    SHAPE ABUTMENT ;
    PORT
      LAYER M4 ;
      RECT 0.000 52.032 0.024 52.056 ;
    END
  END rd_out[527]
  PIN rd_out[528]
    DIRECTION OUTPUT ;
    USE SIGNAL ;
    SHAPE ABUTMENT ;
    PORT
      LAYER M4 ;
      RECT 0.000 52.128 0.024 52.152 ;
    END
  END rd_out[528]
  PIN rd_out[529]
    DIRECTION OUTPUT ;
    USE SIGNAL ;
    SHAPE ABUTMENT ;
    PORT
      LAYER M4 ;
      RECT 0.000 52.224 0.024 52.248 ;
    END
  END rd_out[529]
  PIN rd_out[530]
    DIRECTION OUTPUT ;
    USE SIGNAL ;
    SHAPE ABUTMENT ;
    PORT
      LAYER M4 ;
      RECT 0.000 52.320 0.024 52.344 ;
    END
  END rd_out[530]
  PIN rd_out[531]
    DIRECTION OUTPUT ;
    USE SIGNAL ;
    SHAPE ABUTMENT ;
    PORT
      LAYER M4 ;
      RECT 0.000 52.416 0.024 52.440 ;
    END
  END rd_out[531]
  PIN rd_out[532]
    DIRECTION OUTPUT ;
    USE SIGNAL ;
    SHAPE ABUTMENT ;
    PORT
      LAYER M4 ;
      RECT 0.000 52.512 0.024 52.536 ;
    END
  END rd_out[532]
  PIN rd_out[533]
    DIRECTION OUTPUT ;
    USE SIGNAL ;
    SHAPE ABUTMENT ;
    PORT
      LAYER M4 ;
      RECT 0.000 52.608 0.024 52.632 ;
    END
  END rd_out[533]
  PIN rd_out[534]
    DIRECTION OUTPUT ;
    USE SIGNAL ;
    SHAPE ABUTMENT ;
    PORT
      LAYER M4 ;
      RECT 0.000 52.704 0.024 52.728 ;
    END
  END rd_out[534]
  PIN rd_out[535]
    DIRECTION OUTPUT ;
    USE SIGNAL ;
    SHAPE ABUTMENT ;
    PORT
      LAYER M4 ;
      RECT 0.000 52.800 0.024 52.824 ;
    END
  END rd_out[535]
  PIN rd_out[536]
    DIRECTION OUTPUT ;
    USE SIGNAL ;
    SHAPE ABUTMENT ;
    PORT
      LAYER M4 ;
      RECT 0.000 52.896 0.024 52.920 ;
    END
  END rd_out[536]
  PIN rd_out[537]
    DIRECTION OUTPUT ;
    USE SIGNAL ;
    SHAPE ABUTMENT ;
    PORT
      LAYER M4 ;
      RECT 0.000 52.992 0.024 53.016 ;
    END
  END rd_out[537]
  PIN rd_out[538]
    DIRECTION OUTPUT ;
    USE SIGNAL ;
    SHAPE ABUTMENT ;
    PORT
      LAYER M4 ;
      RECT 0.000 53.088 0.024 53.112 ;
    END
  END rd_out[538]
  PIN rd_out[539]
    DIRECTION OUTPUT ;
    USE SIGNAL ;
    SHAPE ABUTMENT ;
    PORT
      LAYER M4 ;
      RECT 0.000 53.184 0.024 53.208 ;
    END
  END rd_out[539]
  PIN rd_out[540]
    DIRECTION OUTPUT ;
    USE SIGNAL ;
    SHAPE ABUTMENT ;
    PORT
      LAYER M4 ;
      RECT 0.000 53.280 0.024 53.304 ;
    END
  END rd_out[540]
  PIN rd_out[541]
    DIRECTION OUTPUT ;
    USE SIGNAL ;
    SHAPE ABUTMENT ;
    PORT
      LAYER M4 ;
      RECT 0.000 53.376 0.024 53.400 ;
    END
  END rd_out[541]
  PIN rd_out[542]
    DIRECTION OUTPUT ;
    USE SIGNAL ;
    SHAPE ABUTMENT ;
    PORT
      LAYER M4 ;
      RECT 0.000 53.472 0.024 53.496 ;
    END
  END rd_out[542]
  PIN rd_out[543]
    DIRECTION OUTPUT ;
    USE SIGNAL ;
    SHAPE ABUTMENT ;
    PORT
      LAYER M4 ;
      RECT 0.000 53.568 0.024 53.592 ;
    END
  END rd_out[543]
  PIN rd_out[544]
    DIRECTION OUTPUT ;
    USE SIGNAL ;
    SHAPE ABUTMENT ;
    PORT
      LAYER M4 ;
      RECT 0.000 53.664 0.024 53.688 ;
    END
  END rd_out[544]
  PIN rd_out[545]
    DIRECTION OUTPUT ;
    USE SIGNAL ;
    SHAPE ABUTMENT ;
    PORT
      LAYER M4 ;
      RECT 0.000 53.760 0.024 53.784 ;
    END
  END rd_out[545]
  PIN w_ce_in
    DIRECTION INPUT ;
    USE SIGNAL ;
    SHAPE ABUTMENT ;
    PORT
      LAYER M4 ;
      RECT 0.000 53.856 0.024 53.880 ;
    END
  END w_ce_in
  PIN w_addr_in[0]
    DIRECTION INPUT ;
    USE SIGNAL ;
    SHAPE ABUTMENT ;
    PORT
      LAYER M4 ;
      RECT 0.000 53.952 0.024 53.976 ;
    END
  END w_addr_in[0]
  PIN w_addr_in[1]
    DIRECTION INPUT ;
    USE SIGNAL ;
    SHAPE ABUTMENT ;
    PORT
      LAYER M4 ;
      RECT 0.000 54.048 0.024 54.072 ;
    END
  END w_addr_in[1]
  PIN w_addr_in[2]
    DIRECTION INPUT ;
    USE SIGNAL ;
    SHAPE ABUTMENT ;
    PORT
      LAYER M4 ;
      RECT 0.000 54.144 0.024 54.168 ;
    END
  END w_addr_in[2]
  PIN w_addr_in[3]
    DIRECTION INPUT ;
    USE SIGNAL ;
    SHAPE ABUTMENT ;
    PORT
      LAYER M4 ;
      RECT 0.000 54.240 0.024 54.264 ;
    END
  END w_addr_in[3]
  PIN wd_in[0]
    DIRECTION INPUT ;
    USE SIGNAL ;
    SHAPE ABUTMENT ;
    PORT
      LAYER M4 ;
      RECT 0.000 54.336 0.024 54.360 ;
    END
  END wd_in[0]
  PIN wd_in[1]
    DIRECTION INPUT ;
    USE SIGNAL ;
    SHAPE ABUTMENT ;
    PORT
      LAYER M4 ;
      RECT 0.000 54.432 0.024 54.456 ;
    END
  END wd_in[1]
  PIN wd_in[2]
    DIRECTION INPUT ;
    USE SIGNAL ;
    SHAPE ABUTMENT ;
    PORT
      LAYER M4 ;
      RECT 0.000 54.528 0.024 54.552 ;
    END
  END wd_in[2]
  PIN wd_in[3]
    DIRECTION INPUT ;
    USE SIGNAL ;
    SHAPE ABUTMENT ;
    PORT
      LAYER M4 ;
      RECT 0.000 54.624 0.024 54.648 ;
    END
  END wd_in[3]
  PIN wd_in[4]
    DIRECTION INPUT ;
    USE SIGNAL ;
    SHAPE ABUTMENT ;
    PORT
      LAYER M4 ;
      RECT 0.000 54.720 0.024 54.744 ;
    END
  END wd_in[4]
  PIN wd_in[5]
    DIRECTION INPUT ;
    USE SIGNAL ;
    SHAPE ABUTMENT ;
    PORT
      LAYER M4 ;
      RECT 0.000 54.816 0.024 54.840 ;
    END
  END wd_in[5]
  PIN wd_in[6]
    DIRECTION INPUT ;
    USE SIGNAL ;
    SHAPE ABUTMENT ;
    PORT
      LAYER M4 ;
      RECT 0.000 54.912 0.024 54.936 ;
    END
  END wd_in[6]
  PIN wd_in[7]
    DIRECTION INPUT ;
    USE SIGNAL ;
    SHAPE ABUTMENT ;
    PORT
      LAYER M4 ;
      RECT 0.000 55.008 0.024 55.032 ;
    END
  END wd_in[7]
  PIN wd_in[8]
    DIRECTION INPUT ;
    USE SIGNAL ;
    SHAPE ABUTMENT ;
    PORT
      LAYER M4 ;
      RECT 0.000 55.104 0.024 55.128 ;
    END
  END wd_in[8]
  PIN wd_in[9]
    DIRECTION INPUT ;
    USE SIGNAL ;
    SHAPE ABUTMENT ;
    PORT
      LAYER M4 ;
      RECT 0.000 55.200 0.024 55.224 ;
    END
  END wd_in[9]
  PIN wd_in[10]
    DIRECTION INPUT ;
    USE SIGNAL ;
    SHAPE ABUTMENT ;
    PORT
      LAYER M4 ;
      RECT 0.000 55.296 0.024 55.320 ;
    END
  END wd_in[10]
  PIN wd_in[11]
    DIRECTION INPUT ;
    USE SIGNAL ;
    SHAPE ABUTMENT ;
    PORT
      LAYER M4 ;
      RECT 0.000 55.392 0.024 55.416 ;
    END
  END wd_in[11]
  PIN wd_in[12]
    DIRECTION INPUT ;
    USE SIGNAL ;
    SHAPE ABUTMENT ;
    PORT
      LAYER M4 ;
      RECT 0.000 55.488 0.024 55.512 ;
    END
  END wd_in[12]
  PIN wd_in[13]
    DIRECTION INPUT ;
    USE SIGNAL ;
    SHAPE ABUTMENT ;
    PORT
      LAYER M4 ;
      RECT 0.000 55.584 0.024 55.608 ;
    END
  END wd_in[13]
  PIN wd_in[14]
    DIRECTION INPUT ;
    USE SIGNAL ;
    SHAPE ABUTMENT ;
    PORT
      LAYER M4 ;
      RECT 0.000 55.680 0.024 55.704 ;
    END
  END wd_in[14]
  PIN wd_in[15]
    DIRECTION INPUT ;
    USE SIGNAL ;
    SHAPE ABUTMENT ;
    PORT
      LAYER M4 ;
      RECT 0.000 55.776 0.024 55.800 ;
    END
  END wd_in[15]
  PIN wd_in[16]
    DIRECTION INPUT ;
    USE SIGNAL ;
    SHAPE ABUTMENT ;
    PORT
      LAYER M4 ;
      RECT 0.000 55.872 0.024 55.896 ;
    END
  END wd_in[16]
  PIN wd_in[17]
    DIRECTION INPUT ;
    USE SIGNAL ;
    SHAPE ABUTMENT ;
    PORT
      LAYER M4 ;
      RECT 0.000 55.968 0.024 55.992 ;
    END
  END wd_in[17]
  PIN wd_in[18]
    DIRECTION INPUT ;
    USE SIGNAL ;
    SHAPE ABUTMENT ;
    PORT
      LAYER M4 ;
      RECT 0.000 56.064 0.024 56.088 ;
    END
  END wd_in[18]
  PIN wd_in[19]
    DIRECTION INPUT ;
    USE SIGNAL ;
    SHAPE ABUTMENT ;
    PORT
      LAYER M4 ;
      RECT 0.000 56.160 0.024 56.184 ;
    END
  END wd_in[19]
  PIN wd_in[20]
    DIRECTION INPUT ;
    USE SIGNAL ;
    SHAPE ABUTMENT ;
    PORT
      LAYER M4 ;
      RECT 0.000 56.256 0.024 56.280 ;
    END
  END wd_in[20]
  PIN wd_in[21]
    DIRECTION INPUT ;
    USE SIGNAL ;
    SHAPE ABUTMENT ;
    PORT
      LAYER M4 ;
      RECT 0.000 56.352 0.024 56.376 ;
    END
  END wd_in[21]
  PIN wd_in[22]
    DIRECTION INPUT ;
    USE SIGNAL ;
    SHAPE ABUTMENT ;
    PORT
      LAYER M4 ;
      RECT 0.000 56.448 0.024 56.472 ;
    END
  END wd_in[22]
  PIN wd_in[23]
    DIRECTION INPUT ;
    USE SIGNAL ;
    SHAPE ABUTMENT ;
    PORT
      LAYER M4 ;
      RECT 0.000 56.544 0.024 56.568 ;
    END
  END wd_in[23]
  PIN wd_in[24]
    DIRECTION INPUT ;
    USE SIGNAL ;
    SHAPE ABUTMENT ;
    PORT
      LAYER M4 ;
      RECT 0.000 56.640 0.024 56.664 ;
    END
  END wd_in[24]
  PIN wd_in[25]
    DIRECTION INPUT ;
    USE SIGNAL ;
    SHAPE ABUTMENT ;
    PORT
      LAYER M4 ;
      RECT 0.000 56.736 0.024 56.760 ;
    END
  END wd_in[25]
  PIN wd_in[26]
    DIRECTION INPUT ;
    USE SIGNAL ;
    SHAPE ABUTMENT ;
    PORT
      LAYER M4 ;
      RECT 0.000 56.832 0.024 56.856 ;
    END
  END wd_in[26]
  PIN wd_in[27]
    DIRECTION INPUT ;
    USE SIGNAL ;
    SHAPE ABUTMENT ;
    PORT
      LAYER M4 ;
      RECT 0.000 56.928 0.024 56.952 ;
    END
  END wd_in[27]
  PIN wd_in[28]
    DIRECTION INPUT ;
    USE SIGNAL ;
    SHAPE ABUTMENT ;
    PORT
      LAYER M4 ;
      RECT 0.000 57.024 0.024 57.048 ;
    END
  END wd_in[28]
  PIN wd_in[29]
    DIRECTION INPUT ;
    USE SIGNAL ;
    SHAPE ABUTMENT ;
    PORT
      LAYER M4 ;
      RECT 0.000 57.120 0.024 57.144 ;
    END
  END wd_in[29]
  PIN wd_in[30]
    DIRECTION INPUT ;
    USE SIGNAL ;
    SHAPE ABUTMENT ;
    PORT
      LAYER M4 ;
      RECT 0.000 57.216 0.024 57.240 ;
    END
  END wd_in[30]
  PIN wd_in[31]
    DIRECTION INPUT ;
    USE SIGNAL ;
    SHAPE ABUTMENT ;
    PORT
      LAYER M4 ;
      RECT 0.000 57.312 0.024 57.336 ;
    END
  END wd_in[31]
  PIN wd_in[32]
    DIRECTION INPUT ;
    USE SIGNAL ;
    SHAPE ABUTMENT ;
    PORT
      LAYER M4 ;
      RECT 0.000 57.408 0.024 57.432 ;
    END
  END wd_in[32]
  PIN wd_in[33]
    DIRECTION INPUT ;
    USE SIGNAL ;
    SHAPE ABUTMENT ;
    PORT
      LAYER M4 ;
      RECT 0.000 57.504 0.024 57.528 ;
    END
  END wd_in[33]
  PIN wd_in[34]
    DIRECTION INPUT ;
    USE SIGNAL ;
    SHAPE ABUTMENT ;
    PORT
      LAYER M4 ;
      RECT 0.000 57.600 0.024 57.624 ;
    END
  END wd_in[34]
  PIN wd_in[35]
    DIRECTION INPUT ;
    USE SIGNAL ;
    SHAPE ABUTMENT ;
    PORT
      LAYER M4 ;
      RECT 0.000 57.696 0.024 57.720 ;
    END
  END wd_in[35]
  PIN wd_in[36]
    DIRECTION INPUT ;
    USE SIGNAL ;
    SHAPE ABUTMENT ;
    PORT
      LAYER M4 ;
      RECT 0.000 57.792 0.024 57.816 ;
    END
  END wd_in[36]
  PIN wd_in[37]
    DIRECTION INPUT ;
    USE SIGNAL ;
    SHAPE ABUTMENT ;
    PORT
      LAYER M4 ;
      RECT 0.000 57.888 0.024 57.912 ;
    END
  END wd_in[37]
  PIN wd_in[38]
    DIRECTION INPUT ;
    USE SIGNAL ;
    SHAPE ABUTMENT ;
    PORT
      LAYER M4 ;
      RECT 0.000 57.984 0.024 58.008 ;
    END
  END wd_in[38]
  PIN wd_in[39]
    DIRECTION INPUT ;
    USE SIGNAL ;
    SHAPE ABUTMENT ;
    PORT
      LAYER M4 ;
      RECT 0.000 58.080 0.024 58.104 ;
    END
  END wd_in[39]
  PIN wd_in[40]
    DIRECTION INPUT ;
    USE SIGNAL ;
    SHAPE ABUTMENT ;
    PORT
      LAYER M4 ;
      RECT 0.000 58.176 0.024 58.200 ;
    END
  END wd_in[40]
  PIN wd_in[41]
    DIRECTION INPUT ;
    USE SIGNAL ;
    SHAPE ABUTMENT ;
    PORT
      LAYER M4 ;
      RECT 0.000 58.272 0.024 58.296 ;
    END
  END wd_in[41]
  PIN wd_in[42]
    DIRECTION INPUT ;
    USE SIGNAL ;
    SHAPE ABUTMENT ;
    PORT
      LAYER M4 ;
      RECT 0.000 58.368 0.024 58.392 ;
    END
  END wd_in[42]
  PIN wd_in[43]
    DIRECTION INPUT ;
    USE SIGNAL ;
    SHAPE ABUTMENT ;
    PORT
      LAYER M4 ;
      RECT 0.000 58.464 0.024 58.488 ;
    END
  END wd_in[43]
  PIN wd_in[44]
    DIRECTION INPUT ;
    USE SIGNAL ;
    SHAPE ABUTMENT ;
    PORT
      LAYER M4 ;
      RECT 0.000 58.560 0.024 58.584 ;
    END
  END wd_in[44]
  PIN wd_in[45]
    DIRECTION INPUT ;
    USE SIGNAL ;
    SHAPE ABUTMENT ;
    PORT
      LAYER M4 ;
      RECT 0.000 58.656 0.024 58.680 ;
    END
  END wd_in[45]
  PIN wd_in[46]
    DIRECTION INPUT ;
    USE SIGNAL ;
    SHAPE ABUTMENT ;
    PORT
      LAYER M4 ;
      RECT 0.000 58.752 0.024 58.776 ;
    END
  END wd_in[46]
  PIN wd_in[47]
    DIRECTION INPUT ;
    USE SIGNAL ;
    SHAPE ABUTMENT ;
    PORT
      LAYER M4 ;
      RECT 0.000 58.848 0.024 58.872 ;
    END
  END wd_in[47]
  PIN wd_in[48]
    DIRECTION INPUT ;
    USE SIGNAL ;
    SHAPE ABUTMENT ;
    PORT
      LAYER M4 ;
      RECT 0.000 58.944 0.024 58.968 ;
    END
  END wd_in[48]
  PIN wd_in[49]
    DIRECTION INPUT ;
    USE SIGNAL ;
    SHAPE ABUTMENT ;
    PORT
      LAYER M4 ;
      RECT 0.000 59.040 0.024 59.064 ;
    END
  END wd_in[49]
  PIN wd_in[50]
    DIRECTION INPUT ;
    USE SIGNAL ;
    SHAPE ABUTMENT ;
    PORT
      LAYER M4 ;
      RECT 0.000 59.136 0.024 59.160 ;
    END
  END wd_in[50]
  PIN wd_in[51]
    DIRECTION INPUT ;
    USE SIGNAL ;
    SHAPE ABUTMENT ;
    PORT
      LAYER M4 ;
      RECT 0.000 59.232 0.024 59.256 ;
    END
  END wd_in[51]
  PIN wd_in[52]
    DIRECTION INPUT ;
    USE SIGNAL ;
    SHAPE ABUTMENT ;
    PORT
      LAYER M4 ;
      RECT 0.000 59.328 0.024 59.352 ;
    END
  END wd_in[52]
  PIN wd_in[53]
    DIRECTION INPUT ;
    USE SIGNAL ;
    SHAPE ABUTMENT ;
    PORT
      LAYER M4 ;
      RECT 0.000 59.424 0.024 59.448 ;
    END
  END wd_in[53]
  PIN wd_in[54]
    DIRECTION INPUT ;
    USE SIGNAL ;
    SHAPE ABUTMENT ;
    PORT
      LAYER M4 ;
      RECT 0.000 59.520 0.024 59.544 ;
    END
  END wd_in[54]
  PIN wd_in[55]
    DIRECTION INPUT ;
    USE SIGNAL ;
    SHAPE ABUTMENT ;
    PORT
      LAYER M4 ;
      RECT 0.000 59.616 0.024 59.640 ;
    END
  END wd_in[55]
  PIN wd_in[56]
    DIRECTION INPUT ;
    USE SIGNAL ;
    SHAPE ABUTMENT ;
    PORT
      LAYER M4 ;
      RECT 0.000 59.712 0.024 59.736 ;
    END
  END wd_in[56]
  PIN wd_in[57]
    DIRECTION INPUT ;
    USE SIGNAL ;
    SHAPE ABUTMENT ;
    PORT
      LAYER M4 ;
      RECT 0.000 59.808 0.024 59.832 ;
    END
  END wd_in[57]
  PIN wd_in[58]
    DIRECTION INPUT ;
    USE SIGNAL ;
    SHAPE ABUTMENT ;
    PORT
      LAYER M4 ;
      RECT 0.000 59.904 0.024 59.928 ;
    END
  END wd_in[58]
  PIN wd_in[59]
    DIRECTION INPUT ;
    USE SIGNAL ;
    SHAPE ABUTMENT ;
    PORT
      LAYER M4 ;
      RECT 0.000 60.000 0.024 60.024 ;
    END
  END wd_in[59]
  PIN wd_in[60]
    DIRECTION INPUT ;
    USE SIGNAL ;
    SHAPE ABUTMENT ;
    PORT
      LAYER M4 ;
      RECT 0.000 60.096 0.024 60.120 ;
    END
  END wd_in[60]
  PIN wd_in[61]
    DIRECTION INPUT ;
    USE SIGNAL ;
    SHAPE ABUTMENT ;
    PORT
      LAYER M4 ;
      RECT 0.000 60.192 0.024 60.216 ;
    END
  END wd_in[61]
  PIN wd_in[62]
    DIRECTION INPUT ;
    USE SIGNAL ;
    SHAPE ABUTMENT ;
    PORT
      LAYER M4 ;
      RECT 0.000 60.288 0.024 60.312 ;
    END
  END wd_in[62]
  PIN wd_in[63]
    DIRECTION INPUT ;
    USE SIGNAL ;
    SHAPE ABUTMENT ;
    PORT
      LAYER M4 ;
      RECT 0.000 60.384 0.024 60.408 ;
    END
  END wd_in[63]
  PIN wd_in[64]
    DIRECTION INPUT ;
    USE SIGNAL ;
    SHAPE ABUTMENT ;
    PORT
      LAYER M4 ;
      RECT 0.000 60.480 0.024 60.504 ;
    END
  END wd_in[64]
  PIN wd_in[65]
    DIRECTION INPUT ;
    USE SIGNAL ;
    SHAPE ABUTMENT ;
    PORT
      LAYER M4 ;
      RECT 0.000 60.576 0.024 60.600 ;
    END
  END wd_in[65]
  PIN wd_in[66]
    DIRECTION INPUT ;
    USE SIGNAL ;
    SHAPE ABUTMENT ;
    PORT
      LAYER M4 ;
      RECT 0.000 60.672 0.024 60.696 ;
    END
  END wd_in[66]
  PIN wd_in[67]
    DIRECTION INPUT ;
    USE SIGNAL ;
    SHAPE ABUTMENT ;
    PORT
      LAYER M4 ;
      RECT 0.000 60.768 0.024 60.792 ;
    END
  END wd_in[67]
  PIN wd_in[68]
    DIRECTION INPUT ;
    USE SIGNAL ;
    SHAPE ABUTMENT ;
    PORT
      LAYER M4 ;
      RECT 0.000 60.864 0.024 60.888 ;
    END
  END wd_in[68]
  PIN wd_in[69]
    DIRECTION INPUT ;
    USE SIGNAL ;
    SHAPE ABUTMENT ;
    PORT
      LAYER M4 ;
      RECT 0.000 60.960 0.024 60.984 ;
    END
  END wd_in[69]
  PIN wd_in[70]
    DIRECTION INPUT ;
    USE SIGNAL ;
    SHAPE ABUTMENT ;
    PORT
      LAYER M4 ;
      RECT 0.000 61.056 0.024 61.080 ;
    END
  END wd_in[70]
  PIN wd_in[71]
    DIRECTION INPUT ;
    USE SIGNAL ;
    SHAPE ABUTMENT ;
    PORT
      LAYER M4 ;
      RECT 0.000 61.152 0.024 61.176 ;
    END
  END wd_in[71]
  PIN wd_in[72]
    DIRECTION INPUT ;
    USE SIGNAL ;
    SHAPE ABUTMENT ;
    PORT
      LAYER M4 ;
      RECT 0.000 61.248 0.024 61.272 ;
    END
  END wd_in[72]
  PIN wd_in[73]
    DIRECTION INPUT ;
    USE SIGNAL ;
    SHAPE ABUTMENT ;
    PORT
      LAYER M4 ;
      RECT 0.000 61.344 0.024 61.368 ;
    END
  END wd_in[73]
  PIN wd_in[74]
    DIRECTION INPUT ;
    USE SIGNAL ;
    SHAPE ABUTMENT ;
    PORT
      LAYER M4 ;
      RECT 0.000 61.440 0.024 61.464 ;
    END
  END wd_in[74]
  PIN wd_in[75]
    DIRECTION INPUT ;
    USE SIGNAL ;
    SHAPE ABUTMENT ;
    PORT
      LAYER M4 ;
      RECT 0.000 61.536 0.024 61.560 ;
    END
  END wd_in[75]
  PIN wd_in[76]
    DIRECTION INPUT ;
    USE SIGNAL ;
    SHAPE ABUTMENT ;
    PORT
      LAYER M4 ;
      RECT 0.000 61.632 0.024 61.656 ;
    END
  END wd_in[76]
  PIN wd_in[77]
    DIRECTION INPUT ;
    USE SIGNAL ;
    SHAPE ABUTMENT ;
    PORT
      LAYER M4 ;
      RECT 0.000 61.728 0.024 61.752 ;
    END
  END wd_in[77]
  PIN wd_in[78]
    DIRECTION INPUT ;
    USE SIGNAL ;
    SHAPE ABUTMENT ;
    PORT
      LAYER M4 ;
      RECT 0.000 61.824 0.024 61.848 ;
    END
  END wd_in[78]
  PIN wd_in[79]
    DIRECTION INPUT ;
    USE SIGNAL ;
    SHAPE ABUTMENT ;
    PORT
      LAYER M4 ;
      RECT 0.000 61.920 0.024 61.944 ;
    END
  END wd_in[79]
  PIN wd_in[80]
    DIRECTION INPUT ;
    USE SIGNAL ;
    SHAPE ABUTMENT ;
    PORT
      LAYER M4 ;
      RECT 0.000 62.016 0.024 62.040 ;
    END
  END wd_in[80]
  PIN wd_in[81]
    DIRECTION INPUT ;
    USE SIGNAL ;
    SHAPE ABUTMENT ;
    PORT
      LAYER M4 ;
      RECT 0.000 62.112 0.024 62.136 ;
    END
  END wd_in[81]
  PIN wd_in[82]
    DIRECTION INPUT ;
    USE SIGNAL ;
    SHAPE ABUTMENT ;
    PORT
      LAYER M4 ;
      RECT 0.000 62.208 0.024 62.232 ;
    END
  END wd_in[82]
  PIN wd_in[83]
    DIRECTION INPUT ;
    USE SIGNAL ;
    SHAPE ABUTMENT ;
    PORT
      LAYER M4 ;
      RECT 0.000 62.304 0.024 62.328 ;
    END
  END wd_in[83]
  PIN wd_in[84]
    DIRECTION INPUT ;
    USE SIGNAL ;
    SHAPE ABUTMENT ;
    PORT
      LAYER M4 ;
      RECT 0.000 62.400 0.024 62.424 ;
    END
  END wd_in[84]
  PIN wd_in[85]
    DIRECTION INPUT ;
    USE SIGNAL ;
    SHAPE ABUTMENT ;
    PORT
      LAYER M4 ;
      RECT 0.000 62.496 0.024 62.520 ;
    END
  END wd_in[85]
  PIN wd_in[86]
    DIRECTION INPUT ;
    USE SIGNAL ;
    SHAPE ABUTMENT ;
    PORT
      LAYER M4 ;
      RECT 0.000 62.592 0.024 62.616 ;
    END
  END wd_in[86]
  PIN wd_in[87]
    DIRECTION INPUT ;
    USE SIGNAL ;
    SHAPE ABUTMENT ;
    PORT
      LAYER M4 ;
      RECT 0.000 62.688 0.024 62.712 ;
    END
  END wd_in[87]
  PIN wd_in[88]
    DIRECTION INPUT ;
    USE SIGNAL ;
    SHAPE ABUTMENT ;
    PORT
      LAYER M4 ;
      RECT 0.000 62.784 0.024 62.808 ;
    END
  END wd_in[88]
  PIN wd_in[89]
    DIRECTION INPUT ;
    USE SIGNAL ;
    SHAPE ABUTMENT ;
    PORT
      LAYER M4 ;
      RECT 0.000 62.880 0.024 62.904 ;
    END
  END wd_in[89]
  PIN wd_in[90]
    DIRECTION INPUT ;
    USE SIGNAL ;
    SHAPE ABUTMENT ;
    PORT
      LAYER M4 ;
      RECT 0.000 62.976 0.024 63.000 ;
    END
  END wd_in[90]
  PIN wd_in[91]
    DIRECTION INPUT ;
    USE SIGNAL ;
    SHAPE ABUTMENT ;
    PORT
      LAYER M4 ;
      RECT 0.000 63.072 0.024 63.096 ;
    END
  END wd_in[91]
  PIN wd_in[92]
    DIRECTION INPUT ;
    USE SIGNAL ;
    SHAPE ABUTMENT ;
    PORT
      LAYER M4 ;
      RECT 0.000 63.168 0.024 63.192 ;
    END
  END wd_in[92]
  PIN wd_in[93]
    DIRECTION INPUT ;
    USE SIGNAL ;
    SHAPE ABUTMENT ;
    PORT
      LAYER M4 ;
      RECT 0.000 63.264 0.024 63.288 ;
    END
  END wd_in[93]
  PIN wd_in[94]
    DIRECTION INPUT ;
    USE SIGNAL ;
    SHAPE ABUTMENT ;
    PORT
      LAYER M4 ;
      RECT 0.000 63.360 0.024 63.384 ;
    END
  END wd_in[94]
  PIN wd_in[95]
    DIRECTION INPUT ;
    USE SIGNAL ;
    SHAPE ABUTMENT ;
    PORT
      LAYER M4 ;
      RECT 0.000 63.456 0.024 63.480 ;
    END
  END wd_in[95]
  PIN wd_in[96]
    DIRECTION INPUT ;
    USE SIGNAL ;
    SHAPE ABUTMENT ;
    PORT
      LAYER M4 ;
      RECT 0.000 63.552 0.024 63.576 ;
    END
  END wd_in[96]
  PIN wd_in[97]
    DIRECTION INPUT ;
    USE SIGNAL ;
    SHAPE ABUTMENT ;
    PORT
      LAYER M4 ;
      RECT 0.000 63.648 0.024 63.672 ;
    END
  END wd_in[97]
  PIN wd_in[98]
    DIRECTION INPUT ;
    USE SIGNAL ;
    SHAPE ABUTMENT ;
    PORT
      LAYER M4 ;
      RECT 0.000 63.744 0.024 63.768 ;
    END
  END wd_in[98]
  PIN wd_in[99]
    DIRECTION INPUT ;
    USE SIGNAL ;
    SHAPE ABUTMENT ;
    PORT
      LAYER M4 ;
      RECT 0.000 63.840 0.024 63.864 ;
    END
  END wd_in[99]
  PIN wd_in[100]
    DIRECTION INPUT ;
    USE SIGNAL ;
    SHAPE ABUTMENT ;
    PORT
      LAYER M4 ;
      RECT 0.000 63.936 0.024 63.960 ;
    END
  END wd_in[100]
  PIN wd_in[101]
    DIRECTION INPUT ;
    USE SIGNAL ;
    SHAPE ABUTMENT ;
    PORT
      LAYER M4 ;
      RECT 0.000 64.032 0.024 64.056 ;
    END
  END wd_in[101]
  PIN wd_in[102]
    DIRECTION INPUT ;
    USE SIGNAL ;
    SHAPE ABUTMENT ;
    PORT
      LAYER M4 ;
      RECT 0.000 64.128 0.024 64.152 ;
    END
  END wd_in[102]
  PIN wd_in[103]
    DIRECTION INPUT ;
    USE SIGNAL ;
    SHAPE ABUTMENT ;
    PORT
      LAYER M4 ;
      RECT 0.000 64.224 0.024 64.248 ;
    END
  END wd_in[103]
  PIN wd_in[104]
    DIRECTION INPUT ;
    USE SIGNAL ;
    SHAPE ABUTMENT ;
    PORT
      LAYER M4 ;
      RECT 0.000 64.320 0.024 64.344 ;
    END
  END wd_in[104]
  PIN wd_in[105]
    DIRECTION INPUT ;
    USE SIGNAL ;
    SHAPE ABUTMENT ;
    PORT
      LAYER M4 ;
      RECT 0.000 64.416 0.024 64.440 ;
    END
  END wd_in[105]
  PIN wd_in[106]
    DIRECTION INPUT ;
    USE SIGNAL ;
    SHAPE ABUTMENT ;
    PORT
      LAYER M4 ;
      RECT 0.000 64.512 0.024 64.536 ;
    END
  END wd_in[106]
  PIN wd_in[107]
    DIRECTION INPUT ;
    USE SIGNAL ;
    SHAPE ABUTMENT ;
    PORT
      LAYER M4 ;
      RECT 0.000 64.608 0.024 64.632 ;
    END
  END wd_in[107]
  PIN wd_in[108]
    DIRECTION INPUT ;
    USE SIGNAL ;
    SHAPE ABUTMENT ;
    PORT
      LAYER M4 ;
      RECT 0.000 64.704 0.024 64.728 ;
    END
  END wd_in[108]
  PIN wd_in[109]
    DIRECTION INPUT ;
    USE SIGNAL ;
    SHAPE ABUTMENT ;
    PORT
      LAYER M4 ;
      RECT 0.000 64.800 0.024 64.824 ;
    END
  END wd_in[109]
  PIN wd_in[110]
    DIRECTION INPUT ;
    USE SIGNAL ;
    SHAPE ABUTMENT ;
    PORT
      LAYER M4 ;
      RECT 0.000 64.896 0.024 64.920 ;
    END
  END wd_in[110]
  PIN wd_in[111]
    DIRECTION INPUT ;
    USE SIGNAL ;
    SHAPE ABUTMENT ;
    PORT
      LAYER M4 ;
      RECT 0.000 64.992 0.024 65.016 ;
    END
  END wd_in[111]
  PIN wd_in[112]
    DIRECTION INPUT ;
    USE SIGNAL ;
    SHAPE ABUTMENT ;
    PORT
      LAYER M4 ;
      RECT 0.000 65.088 0.024 65.112 ;
    END
  END wd_in[112]
  PIN wd_in[113]
    DIRECTION INPUT ;
    USE SIGNAL ;
    SHAPE ABUTMENT ;
    PORT
      LAYER M4 ;
      RECT 0.000 65.184 0.024 65.208 ;
    END
  END wd_in[113]
  PIN wd_in[114]
    DIRECTION INPUT ;
    USE SIGNAL ;
    SHAPE ABUTMENT ;
    PORT
      LAYER M4 ;
      RECT 0.000 65.280 0.024 65.304 ;
    END
  END wd_in[114]
  PIN wd_in[115]
    DIRECTION INPUT ;
    USE SIGNAL ;
    SHAPE ABUTMENT ;
    PORT
      LAYER M4 ;
      RECT 0.000 65.376 0.024 65.400 ;
    END
  END wd_in[115]
  PIN wd_in[116]
    DIRECTION INPUT ;
    USE SIGNAL ;
    SHAPE ABUTMENT ;
    PORT
      LAYER M4 ;
      RECT 0.000 65.472 0.024 65.496 ;
    END
  END wd_in[116]
  PIN wd_in[117]
    DIRECTION INPUT ;
    USE SIGNAL ;
    SHAPE ABUTMENT ;
    PORT
      LAYER M4 ;
      RECT 0.000 65.568 0.024 65.592 ;
    END
  END wd_in[117]
  PIN wd_in[118]
    DIRECTION INPUT ;
    USE SIGNAL ;
    SHAPE ABUTMENT ;
    PORT
      LAYER M4 ;
      RECT 0.000 65.664 0.024 65.688 ;
    END
  END wd_in[118]
  PIN wd_in[119]
    DIRECTION INPUT ;
    USE SIGNAL ;
    SHAPE ABUTMENT ;
    PORT
      LAYER M4 ;
      RECT 0.000 65.760 0.024 65.784 ;
    END
  END wd_in[119]
  PIN wd_in[120]
    DIRECTION INPUT ;
    USE SIGNAL ;
    SHAPE ABUTMENT ;
    PORT
      LAYER M4 ;
      RECT 0.000 65.856 0.024 65.880 ;
    END
  END wd_in[120]
  PIN wd_in[121]
    DIRECTION INPUT ;
    USE SIGNAL ;
    SHAPE ABUTMENT ;
    PORT
      LAYER M4 ;
      RECT 0.000 65.952 0.024 65.976 ;
    END
  END wd_in[121]
  PIN wd_in[122]
    DIRECTION INPUT ;
    USE SIGNAL ;
    SHAPE ABUTMENT ;
    PORT
      LAYER M4 ;
      RECT 0.000 66.048 0.024 66.072 ;
    END
  END wd_in[122]
  PIN wd_in[123]
    DIRECTION INPUT ;
    USE SIGNAL ;
    SHAPE ABUTMENT ;
    PORT
      LAYER M4 ;
      RECT 0.000 66.144 0.024 66.168 ;
    END
  END wd_in[123]
  PIN wd_in[124]
    DIRECTION INPUT ;
    USE SIGNAL ;
    SHAPE ABUTMENT ;
    PORT
      LAYER M4 ;
      RECT 0.000 66.240 0.024 66.264 ;
    END
  END wd_in[124]
  PIN wd_in[125]
    DIRECTION INPUT ;
    USE SIGNAL ;
    SHAPE ABUTMENT ;
    PORT
      LAYER M4 ;
      RECT 0.000 66.336 0.024 66.360 ;
    END
  END wd_in[125]
  PIN wd_in[126]
    DIRECTION INPUT ;
    USE SIGNAL ;
    SHAPE ABUTMENT ;
    PORT
      LAYER M4 ;
      RECT 0.000 66.432 0.024 66.456 ;
    END
  END wd_in[126]
  PIN wd_in[127]
    DIRECTION INPUT ;
    USE SIGNAL ;
    SHAPE ABUTMENT ;
    PORT
      LAYER M4 ;
      RECT 0.000 66.528 0.024 66.552 ;
    END
  END wd_in[127]
  PIN wd_in[128]
    DIRECTION INPUT ;
    USE SIGNAL ;
    SHAPE ABUTMENT ;
    PORT
      LAYER M4 ;
      RECT 0.000 66.624 0.024 66.648 ;
    END
  END wd_in[128]
  PIN wd_in[129]
    DIRECTION INPUT ;
    USE SIGNAL ;
    SHAPE ABUTMENT ;
    PORT
      LAYER M4 ;
      RECT 0.000 66.720 0.024 66.744 ;
    END
  END wd_in[129]
  PIN wd_in[130]
    DIRECTION INPUT ;
    USE SIGNAL ;
    SHAPE ABUTMENT ;
    PORT
      LAYER M4 ;
      RECT 0.000 66.816 0.024 66.840 ;
    END
  END wd_in[130]
  PIN wd_in[131]
    DIRECTION INPUT ;
    USE SIGNAL ;
    SHAPE ABUTMENT ;
    PORT
      LAYER M4 ;
      RECT 0.000 66.912 0.024 66.936 ;
    END
  END wd_in[131]
  PIN wd_in[132]
    DIRECTION INPUT ;
    USE SIGNAL ;
    SHAPE ABUTMENT ;
    PORT
      LAYER M4 ;
      RECT 0.000 67.008 0.024 67.032 ;
    END
  END wd_in[132]
  PIN wd_in[133]
    DIRECTION INPUT ;
    USE SIGNAL ;
    SHAPE ABUTMENT ;
    PORT
      LAYER M4 ;
      RECT 0.000 67.104 0.024 67.128 ;
    END
  END wd_in[133]
  PIN wd_in[134]
    DIRECTION INPUT ;
    USE SIGNAL ;
    SHAPE ABUTMENT ;
    PORT
      LAYER M4 ;
      RECT 0.000 67.200 0.024 67.224 ;
    END
  END wd_in[134]
  PIN wd_in[135]
    DIRECTION INPUT ;
    USE SIGNAL ;
    SHAPE ABUTMENT ;
    PORT
      LAYER M4 ;
      RECT 0.000 67.296 0.024 67.320 ;
    END
  END wd_in[135]
  PIN wd_in[136]
    DIRECTION INPUT ;
    USE SIGNAL ;
    SHAPE ABUTMENT ;
    PORT
      LAYER M4 ;
      RECT 0.000 67.392 0.024 67.416 ;
    END
  END wd_in[136]
  PIN wd_in[137]
    DIRECTION INPUT ;
    USE SIGNAL ;
    SHAPE ABUTMENT ;
    PORT
      LAYER M4 ;
      RECT 0.000 67.488 0.024 67.512 ;
    END
  END wd_in[137]
  PIN wd_in[138]
    DIRECTION INPUT ;
    USE SIGNAL ;
    SHAPE ABUTMENT ;
    PORT
      LAYER M4 ;
      RECT 0.000 67.584 0.024 67.608 ;
    END
  END wd_in[138]
  PIN wd_in[139]
    DIRECTION INPUT ;
    USE SIGNAL ;
    SHAPE ABUTMENT ;
    PORT
      LAYER M4 ;
      RECT 0.000 67.680 0.024 67.704 ;
    END
  END wd_in[139]
  PIN wd_in[140]
    DIRECTION INPUT ;
    USE SIGNAL ;
    SHAPE ABUTMENT ;
    PORT
      LAYER M4 ;
      RECT 0.000 67.776 0.024 67.800 ;
    END
  END wd_in[140]
  PIN wd_in[141]
    DIRECTION INPUT ;
    USE SIGNAL ;
    SHAPE ABUTMENT ;
    PORT
      LAYER M4 ;
      RECT 0.000 67.872 0.024 67.896 ;
    END
  END wd_in[141]
  PIN wd_in[142]
    DIRECTION INPUT ;
    USE SIGNAL ;
    SHAPE ABUTMENT ;
    PORT
      LAYER M4 ;
      RECT 0.000 67.968 0.024 67.992 ;
    END
  END wd_in[142]
  PIN wd_in[143]
    DIRECTION INPUT ;
    USE SIGNAL ;
    SHAPE ABUTMENT ;
    PORT
      LAYER M4 ;
      RECT 0.000 68.064 0.024 68.088 ;
    END
  END wd_in[143]
  PIN wd_in[144]
    DIRECTION INPUT ;
    USE SIGNAL ;
    SHAPE ABUTMENT ;
    PORT
      LAYER M4 ;
      RECT 0.000 68.160 0.024 68.184 ;
    END
  END wd_in[144]
  PIN wd_in[145]
    DIRECTION INPUT ;
    USE SIGNAL ;
    SHAPE ABUTMENT ;
    PORT
      LAYER M4 ;
      RECT 0.000 68.256 0.024 68.280 ;
    END
  END wd_in[145]
  PIN wd_in[146]
    DIRECTION INPUT ;
    USE SIGNAL ;
    SHAPE ABUTMENT ;
    PORT
      LAYER M4 ;
      RECT 0.000 68.352 0.024 68.376 ;
    END
  END wd_in[146]
  PIN wd_in[147]
    DIRECTION INPUT ;
    USE SIGNAL ;
    SHAPE ABUTMENT ;
    PORT
      LAYER M4 ;
      RECT 0.000 68.448 0.024 68.472 ;
    END
  END wd_in[147]
  PIN wd_in[148]
    DIRECTION INPUT ;
    USE SIGNAL ;
    SHAPE ABUTMENT ;
    PORT
      LAYER M4 ;
      RECT 0.000 68.544 0.024 68.568 ;
    END
  END wd_in[148]
  PIN wd_in[149]
    DIRECTION INPUT ;
    USE SIGNAL ;
    SHAPE ABUTMENT ;
    PORT
      LAYER M4 ;
      RECT 0.000 68.640 0.024 68.664 ;
    END
  END wd_in[149]
  PIN wd_in[150]
    DIRECTION INPUT ;
    USE SIGNAL ;
    SHAPE ABUTMENT ;
    PORT
      LAYER M4 ;
      RECT 0.000 68.736 0.024 68.760 ;
    END
  END wd_in[150]
  PIN wd_in[151]
    DIRECTION INPUT ;
    USE SIGNAL ;
    SHAPE ABUTMENT ;
    PORT
      LAYER M4 ;
      RECT 0.000 68.832 0.024 68.856 ;
    END
  END wd_in[151]
  PIN wd_in[152]
    DIRECTION INPUT ;
    USE SIGNAL ;
    SHAPE ABUTMENT ;
    PORT
      LAYER M4 ;
      RECT 0.000 68.928 0.024 68.952 ;
    END
  END wd_in[152]
  PIN wd_in[153]
    DIRECTION INPUT ;
    USE SIGNAL ;
    SHAPE ABUTMENT ;
    PORT
      LAYER M4 ;
      RECT 0.000 69.024 0.024 69.048 ;
    END
  END wd_in[153]
  PIN wd_in[154]
    DIRECTION INPUT ;
    USE SIGNAL ;
    SHAPE ABUTMENT ;
    PORT
      LAYER M4 ;
      RECT 0.000 69.120 0.024 69.144 ;
    END
  END wd_in[154]
  PIN wd_in[155]
    DIRECTION INPUT ;
    USE SIGNAL ;
    SHAPE ABUTMENT ;
    PORT
      LAYER M4 ;
      RECT 0.000 69.216 0.024 69.240 ;
    END
  END wd_in[155]
  PIN wd_in[156]
    DIRECTION INPUT ;
    USE SIGNAL ;
    SHAPE ABUTMENT ;
    PORT
      LAYER M4 ;
      RECT 0.000 69.312 0.024 69.336 ;
    END
  END wd_in[156]
  PIN wd_in[157]
    DIRECTION INPUT ;
    USE SIGNAL ;
    SHAPE ABUTMENT ;
    PORT
      LAYER M4 ;
      RECT 0.000 69.408 0.024 69.432 ;
    END
  END wd_in[157]
  PIN wd_in[158]
    DIRECTION INPUT ;
    USE SIGNAL ;
    SHAPE ABUTMENT ;
    PORT
      LAYER M4 ;
      RECT 0.000 69.504 0.024 69.528 ;
    END
  END wd_in[158]
  PIN wd_in[159]
    DIRECTION INPUT ;
    USE SIGNAL ;
    SHAPE ABUTMENT ;
    PORT
      LAYER M4 ;
      RECT 0.000 69.600 0.024 69.624 ;
    END
  END wd_in[159]
  PIN wd_in[160]
    DIRECTION INPUT ;
    USE SIGNAL ;
    SHAPE ABUTMENT ;
    PORT
      LAYER M4 ;
      RECT 0.000 69.696 0.024 69.720 ;
    END
  END wd_in[160]
  PIN wd_in[161]
    DIRECTION INPUT ;
    USE SIGNAL ;
    SHAPE ABUTMENT ;
    PORT
      LAYER M4 ;
      RECT 0.000 69.792 0.024 69.816 ;
    END
  END wd_in[161]
  PIN wd_in[162]
    DIRECTION INPUT ;
    USE SIGNAL ;
    SHAPE ABUTMENT ;
    PORT
      LAYER M4 ;
      RECT 0.000 69.888 0.024 69.912 ;
    END
  END wd_in[162]
  PIN wd_in[163]
    DIRECTION INPUT ;
    USE SIGNAL ;
    SHAPE ABUTMENT ;
    PORT
      LAYER M4 ;
      RECT 0.000 69.984 0.024 70.008 ;
    END
  END wd_in[163]
  PIN wd_in[164]
    DIRECTION INPUT ;
    USE SIGNAL ;
    SHAPE ABUTMENT ;
    PORT
      LAYER M4 ;
      RECT 0.000 70.080 0.024 70.104 ;
    END
  END wd_in[164]
  PIN wd_in[165]
    DIRECTION INPUT ;
    USE SIGNAL ;
    SHAPE ABUTMENT ;
    PORT
      LAYER M4 ;
      RECT 0.000 70.176 0.024 70.200 ;
    END
  END wd_in[165]
  PIN wd_in[166]
    DIRECTION INPUT ;
    USE SIGNAL ;
    SHAPE ABUTMENT ;
    PORT
      LAYER M4 ;
      RECT 0.000 70.272 0.024 70.296 ;
    END
  END wd_in[166]
  PIN wd_in[167]
    DIRECTION INPUT ;
    USE SIGNAL ;
    SHAPE ABUTMENT ;
    PORT
      LAYER M4 ;
      RECT 0.000 70.368 0.024 70.392 ;
    END
  END wd_in[167]
  PIN wd_in[168]
    DIRECTION INPUT ;
    USE SIGNAL ;
    SHAPE ABUTMENT ;
    PORT
      LAYER M4 ;
      RECT 0.000 70.464 0.024 70.488 ;
    END
  END wd_in[168]
  PIN wd_in[169]
    DIRECTION INPUT ;
    USE SIGNAL ;
    SHAPE ABUTMENT ;
    PORT
      LAYER M4 ;
      RECT 0.000 70.560 0.024 70.584 ;
    END
  END wd_in[169]
  PIN wd_in[170]
    DIRECTION INPUT ;
    USE SIGNAL ;
    SHAPE ABUTMENT ;
    PORT
      LAYER M4 ;
      RECT 0.000 70.656 0.024 70.680 ;
    END
  END wd_in[170]
  PIN wd_in[171]
    DIRECTION INPUT ;
    USE SIGNAL ;
    SHAPE ABUTMENT ;
    PORT
      LAYER M4 ;
      RECT 0.000 70.752 0.024 70.776 ;
    END
  END wd_in[171]
  PIN wd_in[172]
    DIRECTION INPUT ;
    USE SIGNAL ;
    SHAPE ABUTMENT ;
    PORT
      LAYER M4 ;
      RECT 0.000 70.848 0.024 70.872 ;
    END
  END wd_in[172]
  PIN wd_in[173]
    DIRECTION INPUT ;
    USE SIGNAL ;
    SHAPE ABUTMENT ;
    PORT
      LAYER M4 ;
      RECT 0.000 70.944 0.024 70.968 ;
    END
  END wd_in[173]
  PIN wd_in[174]
    DIRECTION INPUT ;
    USE SIGNAL ;
    SHAPE ABUTMENT ;
    PORT
      LAYER M4 ;
      RECT 0.000 71.040 0.024 71.064 ;
    END
  END wd_in[174]
  PIN wd_in[175]
    DIRECTION INPUT ;
    USE SIGNAL ;
    SHAPE ABUTMENT ;
    PORT
      LAYER M4 ;
      RECT 0.000 71.136 0.024 71.160 ;
    END
  END wd_in[175]
  PIN wd_in[176]
    DIRECTION INPUT ;
    USE SIGNAL ;
    SHAPE ABUTMENT ;
    PORT
      LAYER M4 ;
      RECT 0.000 71.232 0.024 71.256 ;
    END
  END wd_in[176]
  PIN wd_in[177]
    DIRECTION INPUT ;
    USE SIGNAL ;
    SHAPE ABUTMENT ;
    PORT
      LAYER M4 ;
      RECT 0.000 71.328 0.024 71.352 ;
    END
  END wd_in[177]
  PIN wd_in[178]
    DIRECTION INPUT ;
    USE SIGNAL ;
    SHAPE ABUTMENT ;
    PORT
      LAYER M4 ;
      RECT 0.000 71.424 0.024 71.448 ;
    END
  END wd_in[178]
  PIN wd_in[179]
    DIRECTION INPUT ;
    USE SIGNAL ;
    SHAPE ABUTMENT ;
    PORT
      LAYER M4 ;
      RECT 0.000 71.520 0.024 71.544 ;
    END
  END wd_in[179]
  PIN wd_in[180]
    DIRECTION INPUT ;
    USE SIGNAL ;
    SHAPE ABUTMENT ;
    PORT
      LAYER M4 ;
      RECT 0.000 71.616 0.024 71.640 ;
    END
  END wd_in[180]
  PIN wd_in[181]
    DIRECTION INPUT ;
    USE SIGNAL ;
    SHAPE ABUTMENT ;
    PORT
      LAYER M4 ;
      RECT 0.000 71.712 0.024 71.736 ;
    END
  END wd_in[181]
  PIN wd_in[182]
    DIRECTION INPUT ;
    USE SIGNAL ;
    SHAPE ABUTMENT ;
    PORT
      LAYER M4 ;
      RECT 0.000 71.808 0.024 71.832 ;
    END
  END wd_in[182]
  PIN wd_in[183]
    DIRECTION INPUT ;
    USE SIGNAL ;
    SHAPE ABUTMENT ;
    PORT
      LAYER M4 ;
      RECT 0.000 71.904 0.024 71.928 ;
    END
  END wd_in[183]
  PIN wd_in[184]
    DIRECTION INPUT ;
    USE SIGNAL ;
    SHAPE ABUTMENT ;
    PORT
      LAYER M4 ;
      RECT 0.000 72.000 0.024 72.024 ;
    END
  END wd_in[184]
  PIN wd_in[185]
    DIRECTION INPUT ;
    USE SIGNAL ;
    SHAPE ABUTMENT ;
    PORT
      LAYER M4 ;
      RECT 0.000 72.096 0.024 72.120 ;
    END
  END wd_in[185]
  PIN wd_in[186]
    DIRECTION INPUT ;
    USE SIGNAL ;
    SHAPE ABUTMENT ;
    PORT
      LAYER M4 ;
      RECT 0.000 72.192 0.024 72.216 ;
    END
  END wd_in[186]
  PIN wd_in[187]
    DIRECTION INPUT ;
    USE SIGNAL ;
    SHAPE ABUTMENT ;
    PORT
      LAYER M4 ;
      RECT 0.000 72.288 0.024 72.312 ;
    END
  END wd_in[187]
  PIN wd_in[188]
    DIRECTION INPUT ;
    USE SIGNAL ;
    SHAPE ABUTMENT ;
    PORT
      LAYER M4 ;
      RECT 0.000 72.384 0.024 72.408 ;
    END
  END wd_in[188]
  PIN wd_in[189]
    DIRECTION INPUT ;
    USE SIGNAL ;
    SHAPE ABUTMENT ;
    PORT
      LAYER M4 ;
      RECT 0.000 72.480 0.024 72.504 ;
    END
  END wd_in[189]
  PIN wd_in[190]
    DIRECTION INPUT ;
    USE SIGNAL ;
    SHAPE ABUTMENT ;
    PORT
      LAYER M4 ;
      RECT 0.000 72.576 0.024 72.600 ;
    END
  END wd_in[190]
  PIN wd_in[191]
    DIRECTION INPUT ;
    USE SIGNAL ;
    SHAPE ABUTMENT ;
    PORT
      LAYER M4 ;
      RECT 0.000 72.672 0.024 72.696 ;
    END
  END wd_in[191]
  PIN wd_in[192]
    DIRECTION INPUT ;
    USE SIGNAL ;
    SHAPE ABUTMENT ;
    PORT
      LAYER M4 ;
      RECT 0.000 72.768 0.024 72.792 ;
    END
  END wd_in[192]
  PIN wd_in[193]
    DIRECTION INPUT ;
    USE SIGNAL ;
    SHAPE ABUTMENT ;
    PORT
      LAYER M4 ;
      RECT 0.000 72.864 0.024 72.888 ;
    END
  END wd_in[193]
  PIN wd_in[194]
    DIRECTION INPUT ;
    USE SIGNAL ;
    SHAPE ABUTMENT ;
    PORT
      LAYER M4 ;
      RECT 0.000 72.960 0.024 72.984 ;
    END
  END wd_in[194]
  PIN wd_in[195]
    DIRECTION INPUT ;
    USE SIGNAL ;
    SHAPE ABUTMENT ;
    PORT
      LAYER M4 ;
      RECT 0.000 73.056 0.024 73.080 ;
    END
  END wd_in[195]
  PIN wd_in[196]
    DIRECTION INPUT ;
    USE SIGNAL ;
    SHAPE ABUTMENT ;
    PORT
      LAYER M4 ;
      RECT 0.000 73.152 0.024 73.176 ;
    END
  END wd_in[196]
  PIN wd_in[197]
    DIRECTION INPUT ;
    USE SIGNAL ;
    SHAPE ABUTMENT ;
    PORT
      LAYER M4 ;
      RECT 0.000 73.248 0.024 73.272 ;
    END
  END wd_in[197]
  PIN wd_in[198]
    DIRECTION INPUT ;
    USE SIGNAL ;
    SHAPE ABUTMENT ;
    PORT
      LAYER M4 ;
      RECT 0.000 73.344 0.024 73.368 ;
    END
  END wd_in[198]
  PIN wd_in[199]
    DIRECTION INPUT ;
    USE SIGNAL ;
    SHAPE ABUTMENT ;
    PORT
      LAYER M4 ;
      RECT 0.000 73.440 0.024 73.464 ;
    END
  END wd_in[199]
  PIN wd_in[200]
    DIRECTION INPUT ;
    USE SIGNAL ;
    SHAPE ABUTMENT ;
    PORT
      LAYER M4 ;
      RECT 0.000 73.536 0.024 73.560 ;
    END
  END wd_in[200]
  PIN wd_in[201]
    DIRECTION INPUT ;
    USE SIGNAL ;
    SHAPE ABUTMENT ;
    PORT
      LAYER M4 ;
      RECT 0.000 73.632 0.024 73.656 ;
    END
  END wd_in[201]
  PIN wd_in[202]
    DIRECTION INPUT ;
    USE SIGNAL ;
    SHAPE ABUTMENT ;
    PORT
      LAYER M4 ;
      RECT 0.000 73.728 0.024 73.752 ;
    END
  END wd_in[202]
  PIN wd_in[203]
    DIRECTION INPUT ;
    USE SIGNAL ;
    SHAPE ABUTMENT ;
    PORT
      LAYER M4 ;
      RECT 0.000 73.824 0.024 73.848 ;
    END
  END wd_in[203]
  PIN wd_in[204]
    DIRECTION INPUT ;
    USE SIGNAL ;
    SHAPE ABUTMENT ;
    PORT
      LAYER M4 ;
      RECT 0.000 73.920 0.024 73.944 ;
    END
  END wd_in[204]
  PIN wd_in[205]
    DIRECTION INPUT ;
    USE SIGNAL ;
    SHAPE ABUTMENT ;
    PORT
      LAYER M4 ;
      RECT 0.000 74.016 0.024 74.040 ;
    END
  END wd_in[205]
  PIN wd_in[206]
    DIRECTION INPUT ;
    USE SIGNAL ;
    SHAPE ABUTMENT ;
    PORT
      LAYER M4 ;
      RECT 0.000 74.112 0.024 74.136 ;
    END
  END wd_in[206]
  PIN wd_in[207]
    DIRECTION INPUT ;
    USE SIGNAL ;
    SHAPE ABUTMENT ;
    PORT
      LAYER M4 ;
      RECT 0.000 74.208 0.024 74.232 ;
    END
  END wd_in[207]
  PIN wd_in[208]
    DIRECTION INPUT ;
    USE SIGNAL ;
    SHAPE ABUTMENT ;
    PORT
      LAYER M4 ;
      RECT 0.000 74.304 0.024 74.328 ;
    END
  END wd_in[208]
  PIN wd_in[209]
    DIRECTION INPUT ;
    USE SIGNAL ;
    SHAPE ABUTMENT ;
    PORT
      LAYER M4 ;
      RECT 0.000 74.400 0.024 74.424 ;
    END
  END wd_in[209]
  PIN wd_in[210]
    DIRECTION INPUT ;
    USE SIGNAL ;
    SHAPE ABUTMENT ;
    PORT
      LAYER M4 ;
      RECT 0.000 74.496 0.024 74.520 ;
    END
  END wd_in[210]
  PIN wd_in[211]
    DIRECTION INPUT ;
    USE SIGNAL ;
    SHAPE ABUTMENT ;
    PORT
      LAYER M4 ;
      RECT 0.000 74.592 0.024 74.616 ;
    END
  END wd_in[211]
  PIN wd_in[212]
    DIRECTION INPUT ;
    USE SIGNAL ;
    SHAPE ABUTMENT ;
    PORT
      LAYER M4 ;
      RECT 0.000 74.688 0.024 74.712 ;
    END
  END wd_in[212]
  PIN wd_in[213]
    DIRECTION INPUT ;
    USE SIGNAL ;
    SHAPE ABUTMENT ;
    PORT
      LAYER M4 ;
      RECT 0.000 74.784 0.024 74.808 ;
    END
  END wd_in[213]
  PIN wd_in[214]
    DIRECTION INPUT ;
    USE SIGNAL ;
    SHAPE ABUTMENT ;
    PORT
      LAYER M4 ;
      RECT 0.000 74.880 0.024 74.904 ;
    END
  END wd_in[214]
  PIN wd_in[215]
    DIRECTION INPUT ;
    USE SIGNAL ;
    SHAPE ABUTMENT ;
    PORT
      LAYER M4 ;
      RECT 0.000 74.976 0.024 75.000 ;
    END
  END wd_in[215]
  PIN wd_in[216]
    DIRECTION INPUT ;
    USE SIGNAL ;
    SHAPE ABUTMENT ;
    PORT
      LAYER M4 ;
      RECT 0.000 75.072 0.024 75.096 ;
    END
  END wd_in[216]
  PIN wd_in[217]
    DIRECTION INPUT ;
    USE SIGNAL ;
    SHAPE ABUTMENT ;
    PORT
      LAYER M4 ;
      RECT 0.000 75.168 0.024 75.192 ;
    END
  END wd_in[217]
  PIN wd_in[218]
    DIRECTION INPUT ;
    USE SIGNAL ;
    SHAPE ABUTMENT ;
    PORT
      LAYER M4 ;
      RECT 0.000 75.264 0.024 75.288 ;
    END
  END wd_in[218]
  PIN wd_in[219]
    DIRECTION INPUT ;
    USE SIGNAL ;
    SHAPE ABUTMENT ;
    PORT
      LAYER M4 ;
      RECT 0.000 75.360 0.024 75.384 ;
    END
  END wd_in[219]
  PIN wd_in[220]
    DIRECTION INPUT ;
    USE SIGNAL ;
    SHAPE ABUTMENT ;
    PORT
      LAYER M4 ;
      RECT 0.000 75.456 0.024 75.480 ;
    END
  END wd_in[220]
  PIN wd_in[221]
    DIRECTION INPUT ;
    USE SIGNAL ;
    SHAPE ABUTMENT ;
    PORT
      LAYER M4 ;
      RECT 0.000 75.552 0.024 75.576 ;
    END
  END wd_in[221]
  PIN wd_in[222]
    DIRECTION INPUT ;
    USE SIGNAL ;
    SHAPE ABUTMENT ;
    PORT
      LAYER M4 ;
      RECT 0.000 75.648 0.024 75.672 ;
    END
  END wd_in[222]
  PIN wd_in[223]
    DIRECTION INPUT ;
    USE SIGNAL ;
    SHAPE ABUTMENT ;
    PORT
      LAYER M4 ;
      RECT 0.000 75.744 0.024 75.768 ;
    END
  END wd_in[223]
  PIN wd_in[224]
    DIRECTION INPUT ;
    USE SIGNAL ;
    SHAPE ABUTMENT ;
    PORT
      LAYER M4 ;
      RECT 0.000 75.840 0.024 75.864 ;
    END
  END wd_in[224]
  PIN wd_in[225]
    DIRECTION INPUT ;
    USE SIGNAL ;
    SHAPE ABUTMENT ;
    PORT
      LAYER M4 ;
      RECT 0.000 75.936 0.024 75.960 ;
    END
  END wd_in[225]
  PIN wd_in[226]
    DIRECTION INPUT ;
    USE SIGNAL ;
    SHAPE ABUTMENT ;
    PORT
      LAYER M4 ;
      RECT 0.000 76.032 0.024 76.056 ;
    END
  END wd_in[226]
  PIN wd_in[227]
    DIRECTION INPUT ;
    USE SIGNAL ;
    SHAPE ABUTMENT ;
    PORT
      LAYER M4 ;
      RECT 0.000 76.128 0.024 76.152 ;
    END
  END wd_in[227]
  PIN wd_in[228]
    DIRECTION INPUT ;
    USE SIGNAL ;
    SHAPE ABUTMENT ;
    PORT
      LAYER M4 ;
      RECT 0.000 76.224 0.024 76.248 ;
    END
  END wd_in[228]
  PIN wd_in[229]
    DIRECTION INPUT ;
    USE SIGNAL ;
    SHAPE ABUTMENT ;
    PORT
      LAYER M4 ;
      RECT 0.000 76.320 0.024 76.344 ;
    END
  END wd_in[229]
  PIN wd_in[230]
    DIRECTION INPUT ;
    USE SIGNAL ;
    SHAPE ABUTMENT ;
    PORT
      LAYER M4 ;
      RECT 0.000 76.416 0.024 76.440 ;
    END
  END wd_in[230]
  PIN wd_in[231]
    DIRECTION INPUT ;
    USE SIGNAL ;
    SHAPE ABUTMENT ;
    PORT
      LAYER M4 ;
      RECT 0.000 76.512 0.024 76.536 ;
    END
  END wd_in[231]
  PIN wd_in[232]
    DIRECTION INPUT ;
    USE SIGNAL ;
    SHAPE ABUTMENT ;
    PORT
      LAYER M4 ;
      RECT 0.000 76.608 0.024 76.632 ;
    END
  END wd_in[232]
  PIN wd_in[233]
    DIRECTION INPUT ;
    USE SIGNAL ;
    SHAPE ABUTMENT ;
    PORT
      LAYER M4 ;
      RECT 0.000 76.704 0.024 76.728 ;
    END
  END wd_in[233]
  PIN wd_in[234]
    DIRECTION INPUT ;
    USE SIGNAL ;
    SHAPE ABUTMENT ;
    PORT
      LAYER M4 ;
      RECT 0.000 76.800 0.024 76.824 ;
    END
  END wd_in[234]
  PIN wd_in[235]
    DIRECTION INPUT ;
    USE SIGNAL ;
    SHAPE ABUTMENT ;
    PORT
      LAYER M4 ;
      RECT 0.000 76.896 0.024 76.920 ;
    END
  END wd_in[235]
  PIN wd_in[236]
    DIRECTION INPUT ;
    USE SIGNAL ;
    SHAPE ABUTMENT ;
    PORT
      LAYER M4 ;
      RECT 0.000 76.992 0.024 77.016 ;
    END
  END wd_in[236]
  PIN wd_in[237]
    DIRECTION INPUT ;
    USE SIGNAL ;
    SHAPE ABUTMENT ;
    PORT
      LAYER M4 ;
      RECT 0.000 77.088 0.024 77.112 ;
    END
  END wd_in[237]
  PIN wd_in[238]
    DIRECTION INPUT ;
    USE SIGNAL ;
    SHAPE ABUTMENT ;
    PORT
      LAYER M4 ;
      RECT 0.000 77.184 0.024 77.208 ;
    END
  END wd_in[238]
  PIN wd_in[239]
    DIRECTION INPUT ;
    USE SIGNAL ;
    SHAPE ABUTMENT ;
    PORT
      LAYER M4 ;
      RECT 0.000 77.280 0.024 77.304 ;
    END
  END wd_in[239]
  PIN wd_in[240]
    DIRECTION INPUT ;
    USE SIGNAL ;
    SHAPE ABUTMENT ;
    PORT
      LAYER M4 ;
      RECT 0.000 77.376 0.024 77.400 ;
    END
  END wd_in[240]
  PIN wd_in[241]
    DIRECTION INPUT ;
    USE SIGNAL ;
    SHAPE ABUTMENT ;
    PORT
      LAYER M4 ;
      RECT 0.000 77.472 0.024 77.496 ;
    END
  END wd_in[241]
  PIN wd_in[242]
    DIRECTION INPUT ;
    USE SIGNAL ;
    SHAPE ABUTMENT ;
    PORT
      LAYER M4 ;
      RECT 0.000 77.568 0.024 77.592 ;
    END
  END wd_in[242]
  PIN wd_in[243]
    DIRECTION INPUT ;
    USE SIGNAL ;
    SHAPE ABUTMENT ;
    PORT
      LAYER M4 ;
      RECT 0.000 77.664 0.024 77.688 ;
    END
  END wd_in[243]
  PIN wd_in[244]
    DIRECTION INPUT ;
    USE SIGNAL ;
    SHAPE ABUTMENT ;
    PORT
      LAYER M4 ;
      RECT 0.000 77.760 0.024 77.784 ;
    END
  END wd_in[244]
  PIN wd_in[245]
    DIRECTION INPUT ;
    USE SIGNAL ;
    SHAPE ABUTMENT ;
    PORT
      LAYER M4 ;
      RECT 0.000 77.856 0.024 77.880 ;
    END
  END wd_in[245]
  PIN wd_in[246]
    DIRECTION INPUT ;
    USE SIGNAL ;
    SHAPE ABUTMENT ;
    PORT
      LAYER M4 ;
      RECT 0.000 77.952 0.024 77.976 ;
    END
  END wd_in[246]
  PIN wd_in[247]
    DIRECTION INPUT ;
    USE SIGNAL ;
    SHAPE ABUTMENT ;
    PORT
      LAYER M4 ;
      RECT 0.000 78.048 0.024 78.072 ;
    END
  END wd_in[247]
  PIN wd_in[248]
    DIRECTION INPUT ;
    USE SIGNAL ;
    SHAPE ABUTMENT ;
    PORT
      LAYER M4 ;
      RECT 0.000 78.144 0.024 78.168 ;
    END
  END wd_in[248]
  PIN wd_in[249]
    DIRECTION INPUT ;
    USE SIGNAL ;
    SHAPE ABUTMENT ;
    PORT
      LAYER M4 ;
      RECT 0.000 78.240 0.024 78.264 ;
    END
  END wd_in[249]
  PIN wd_in[250]
    DIRECTION INPUT ;
    USE SIGNAL ;
    SHAPE ABUTMENT ;
    PORT
      LAYER M4 ;
      RECT 0.000 78.336 0.024 78.360 ;
    END
  END wd_in[250]
  PIN wd_in[251]
    DIRECTION INPUT ;
    USE SIGNAL ;
    SHAPE ABUTMENT ;
    PORT
      LAYER M4 ;
      RECT 0.000 78.432 0.024 78.456 ;
    END
  END wd_in[251]
  PIN wd_in[252]
    DIRECTION INPUT ;
    USE SIGNAL ;
    SHAPE ABUTMENT ;
    PORT
      LAYER M4 ;
      RECT 0.000 78.528 0.024 78.552 ;
    END
  END wd_in[252]
  PIN wd_in[253]
    DIRECTION INPUT ;
    USE SIGNAL ;
    SHAPE ABUTMENT ;
    PORT
      LAYER M4 ;
      RECT 0.000 78.624 0.024 78.648 ;
    END
  END wd_in[253]
  PIN wd_in[254]
    DIRECTION INPUT ;
    USE SIGNAL ;
    SHAPE ABUTMENT ;
    PORT
      LAYER M4 ;
      RECT 0.000 78.720 0.024 78.744 ;
    END
  END wd_in[254]
  PIN wd_in[255]
    DIRECTION INPUT ;
    USE SIGNAL ;
    SHAPE ABUTMENT ;
    PORT
      LAYER M4 ;
      RECT 0.000 78.816 0.024 78.840 ;
    END
  END wd_in[255]
  PIN wd_in[256]
    DIRECTION INPUT ;
    USE SIGNAL ;
    SHAPE ABUTMENT ;
    PORT
      LAYER M4 ;
      RECT 0.000 78.912 0.024 78.936 ;
    END
  END wd_in[256]
  PIN wd_in[257]
    DIRECTION INPUT ;
    USE SIGNAL ;
    SHAPE ABUTMENT ;
    PORT
      LAYER M4 ;
      RECT 0.000 79.008 0.024 79.032 ;
    END
  END wd_in[257]
  PIN wd_in[258]
    DIRECTION INPUT ;
    USE SIGNAL ;
    SHAPE ABUTMENT ;
    PORT
      LAYER M4 ;
      RECT 0.000 79.104 0.024 79.128 ;
    END
  END wd_in[258]
  PIN wd_in[259]
    DIRECTION INPUT ;
    USE SIGNAL ;
    SHAPE ABUTMENT ;
    PORT
      LAYER M4 ;
      RECT 0.000 79.200 0.024 79.224 ;
    END
  END wd_in[259]
  PIN wd_in[260]
    DIRECTION INPUT ;
    USE SIGNAL ;
    SHAPE ABUTMENT ;
    PORT
      LAYER M4 ;
      RECT 0.000 79.296 0.024 79.320 ;
    END
  END wd_in[260]
  PIN wd_in[261]
    DIRECTION INPUT ;
    USE SIGNAL ;
    SHAPE ABUTMENT ;
    PORT
      LAYER M4 ;
      RECT 0.000 79.392 0.024 79.416 ;
    END
  END wd_in[261]
  PIN wd_in[262]
    DIRECTION INPUT ;
    USE SIGNAL ;
    SHAPE ABUTMENT ;
    PORT
      LAYER M4 ;
      RECT 0.000 79.488 0.024 79.512 ;
    END
  END wd_in[262]
  PIN wd_in[263]
    DIRECTION INPUT ;
    USE SIGNAL ;
    SHAPE ABUTMENT ;
    PORT
      LAYER M4 ;
      RECT 0.000 79.584 0.024 79.608 ;
    END
  END wd_in[263]
  PIN wd_in[264]
    DIRECTION INPUT ;
    USE SIGNAL ;
    SHAPE ABUTMENT ;
    PORT
      LAYER M4 ;
      RECT 0.000 79.680 0.024 79.704 ;
    END
  END wd_in[264]
  PIN wd_in[265]
    DIRECTION INPUT ;
    USE SIGNAL ;
    SHAPE ABUTMENT ;
    PORT
      LAYER M4 ;
      RECT 0.000 79.776 0.024 79.800 ;
    END
  END wd_in[265]
  PIN wd_in[266]
    DIRECTION INPUT ;
    USE SIGNAL ;
    SHAPE ABUTMENT ;
    PORT
      LAYER M4 ;
      RECT 0.000 79.872 0.024 79.896 ;
    END
  END wd_in[266]
  PIN wd_in[267]
    DIRECTION INPUT ;
    USE SIGNAL ;
    SHAPE ABUTMENT ;
    PORT
      LAYER M4 ;
      RECT 176.880 0.768 176.904 0.792 ;
    END
  END wd_in[267]
  PIN wd_in[268]
    DIRECTION INPUT ;
    USE SIGNAL ;
    SHAPE ABUTMENT ;
    PORT
      LAYER M4 ;
      RECT 176.880 0.864 176.904 0.888 ;
    END
  END wd_in[268]
  PIN wd_in[269]
    DIRECTION INPUT ;
    USE SIGNAL ;
    SHAPE ABUTMENT ;
    PORT
      LAYER M4 ;
      RECT 176.880 0.960 176.904 0.984 ;
    END
  END wd_in[269]
  PIN wd_in[270]
    DIRECTION INPUT ;
    USE SIGNAL ;
    SHAPE ABUTMENT ;
    PORT
      LAYER M4 ;
      RECT 176.880 1.056 176.904 1.080 ;
    END
  END wd_in[270]
  PIN wd_in[271]
    DIRECTION INPUT ;
    USE SIGNAL ;
    SHAPE ABUTMENT ;
    PORT
      LAYER M4 ;
      RECT 176.880 1.152 176.904 1.176 ;
    END
  END wd_in[271]
  PIN wd_in[272]
    DIRECTION INPUT ;
    USE SIGNAL ;
    SHAPE ABUTMENT ;
    PORT
      LAYER M4 ;
      RECT 176.880 1.248 176.904 1.272 ;
    END
  END wd_in[272]
  PIN wd_in[273]
    DIRECTION INPUT ;
    USE SIGNAL ;
    SHAPE ABUTMENT ;
    PORT
      LAYER M4 ;
      RECT 176.880 1.344 176.904 1.368 ;
    END
  END wd_in[273]
  PIN wd_in[274]
    DIRECTION INPUT ;
    USE SIGNAL ;
    SHAPE ABUTMENT ;
    PORT
      LAYER M4 ;
      RECT 176.880 1.440 176.904 1.464 ;
    END
  END wd_in[274]
  PIN wd_in[275]
    DIRECTION INPUT ;
    USE SIGNAL ;
    SHAPE ABUTMENT ;
    PORT
      LAYER M4 ;
      RECT 176.880 1.536 176.904 1.560 ;
    END
  END wd_in[275]
  PIN wd_in[276]
    DIRECTION INPUT ;
    USE SIGNAL ;
    SHAPE ABUTMENT ;
    PORT
      LAYER M4 ;
      RECT 176.880 1.632 176.904 1.656 ;
    END
  END wd_in[276]
  PIN wd_in[277]
    DIRECTION INPUT ;
    USE SIGNAL ;
    SHAPE ABUTMENT ;
    PORT
      LAYER M4 ;
      RECT 176.880 1.728 176.904 1.752 ;
    END
  END wd_in[277]
  PIN wd_in[278]
    DIRECTION INPUT ;
    USE SIGNAL ;
    SHAPE ABUTMENT ;
    PORT
      LAYER M4 ;
      RECT 176.880 1.824 176.904 1.848 ;
    END
  END wd_in[278]
  PIN wd_in[279]
    DIRECTION INPUT ;
    USE SIGNAL ;
    SHAPE ABUTMENT ;
    PORT
      LAYER M4 ;
      RECT 176.880 1.920 176.904 1.944 ;
    END
  END wd_in[279]
  PIN wd_in[280]
    DIRECTION INPUT ;
    USE SIGNAL ;
    SHAPE ABUTMENT ;
    PORT
      LAYER M4 ;
      RECT 176.880 2.016 176.904 2.040 ;
    END
  END wd_in[280]
  PIN wd_in[281]
    DIRECTION INPUT ;
    USE SIGNAL ;
    SHAPE ABUTMENT ;
    PORT
      LAYER M4 ;
      RECT 176.880 2.112 176.904 2.136 ;
    END
  END wd_in[281]
  PIN wd_in[282]
    DIRECTION INPUT ;
    USE SIGNAL ;
    SHAPE ABUTMENT ;
    PORT
      LAYER M4 ;
      RECT 176.880 2.208 176.904 2.232 ;
    END
  END wd_in[282]
  PIN wd_in[283]
    DIRECTION INPUT ;
    USE SIGNAL ;
    SHAPE ABUTMENT ;
    PORT
      LAYER M4 ;
      RECT 176.880 2.304 176.904 2.328 ;
    END
  END wd_in[283]
  PIN wd_in[284]
    DIRECTION INPUT ;
    USE SIGNAL ;
    SHAPE ABUTMENT ;
    PORT
      LAYER M4 ;
      RECT 176.880 2.400 176.904 2.424 ;
    END
  END wd_in[284]
  PIN wd_in[285]
    DIRECTION INPUT ;
    USE SIGNAL ;
    SHAPE ABUTMENT ;
    PORT
      LAYER M4 ;
      RECT 176.880 2.496 176.904 2.520 ;
    END
  END wd_in[285]
  PIN wd_in[286]
    DIRECTION INPUT ;
    USE SIGNAL ;
    SHAPE ABUTMENT ;
    PORT
      LAYER M4 ;
      RECT 176.880 2.592 176.904 2.616 ;
    END
  END wd_in[286]
  PIN wd_in[287]
    DIRECTION INPUT ;
    USE SIGNAL ;
    SHAPE ABUTMENT ;
    PORT
      LAYER M4 ;
      RECT 176.880 2.688 176.904 2.712 ;
    END
  END wd_in[287]
  PIN wd_in[288]
    DIRECTION INPUT ;
    USE SIGNAL ;
    SHAPE ABUTMENT ;
    PORT
      LAYER M4 ;
      RECT 176.880 2.784 176.904 2.808 ;
    END
  END wd_in[288]
  PIN wd_in[289]
    DIRECTION INPUT ;
    USE SIGNAL ;
    SHAPE ABUTMENT ;
    PORT
      LAYER M4 ;
      RECT 176.880 2.880 176.904 2.904 ;
    END
  END wd_in[289]
  PIN wd_in[290]
    DIRECTION INPUT ;
    USE SIGNAL ;
    SHAPE ABUTMENT ;
    PORT
      LAYER M4 ;
      RECT 176.880 2.976 176.904 3.000 ;
    END
  END wd_in[290]
  PIN wd_in[291]
    DIRECTION INPUT ;
    USE SIGNAL ;
    SHAPE ABUTMENT ;
    PORT
      LAYER M4 ;
      RECT 176.880 3.072 176.904 3.096 ;
    END
  END wd_in[291]
  PIN wd_in[292]
    DIRECTION INPUT ;
    USE SIGNAL ;
    SHAPE ABUTMENT ;
    PORT
      LAYER M4 ;
      RECT 176.880 3.168 176.904 3.192 ;
    END
  END wd_in[292]
  PIN wd_in[293]
    DIRECTION INPUT ;
    USE SIGNAL ;
    SHAPE ABUTMENT ;
    PORT
      LAYER M4 ;
      RECT 176.880 3.264 176.904 3.288 ;
    END
  END wd_in[293]
  PIN wd_in[294]
    DIRECTION INPUT ;
    USE SIGNAL ;
    SHAPE ABUTMENT ;
    PORT
      LAYER M4 ;
      RECT 176.880 3.360 176.904 3.384 ;
    END
  END wd_in[294]
  PIN wd_in[295]
    DIRECTION INPUT ;
    USE SIGNAL ;
    SHAPE ABUTMENT ;
    PORT
      LAYER M4 ;
      RECT 176.880 3.456 176.904 3.480 ;
    END
  END wd_in[295]
  PIN wd_in[296]
    DIRECTION INPUT ;
    USE SIGNAL ;
    SHAPE ABUTMENT ;
    PORT
      LAYER M4 ;
      RECT 176.880 3.552 176.904 3.576 ;
    END
  END wd_in[296]
  PIN wd_in[297]
    DIRECTION INPUT ;
    USE SIGNAL ;
    SHAPE ABUTMENT ;
    PORT
      LAYER M4 ;
      RECT 176.880 3.648 176.904 3.672 ;
    END
  END wd_in[297]
  PIN wd_in[298]
    DIRECTION INPUT ;
    USE SIGNAL ;
    SHAPE ABUTMENT ;
    PORT
      LAYER M4 ;
      RECT 176.880 3.744 176.904 3.768 ;
    END
  END wd_in[298]
  PIN wd_in[299]
    DIRECTION INPUT ;
    USE SIGNAL ;
    SHAPE ABUTMENT ;
    PORT
      LAYER M4 ;
      RECT 176.880 3.840 176.904 3.864 ;
    END
  END wd_in[299]
  PIN wd_in[300]
    DIRECTION INPUT ;
    USE SIGNAL ;
    SHAPE ABUTMENT ;
    PORT
      LAYER M4 ;
      RECT 176.880 3.936 176.904 3.960 ;
    END
  END wd_in[300]
  PIN wd_in[301]
    DIRECTION INPUT ;
    USE SIGNAL ;
    SHAPE ABUTMENT ;
    PORT
      LAYER M4 ;
      RECT 176.880 4.032 176.904 4.056 ;
    END
  END wd_in[301]
  PIN wd_in[302]
    DIRECTION INPUT ;
    USE SIGNAL ;
    SHAPE ABUTMENT ;
    PORT
      LAYER M4 ;
      RECT 176.880 4.128 176.904 4.152 ;
    END
  END wd_in[302]
  PIN wd_in[303]
    DIRECTION INPUT ;
    USE SIGNAL ;
    SHAPE ABUTMENT ;
    PORT
      LAYER M4 ;
      RECT 176.880 4.224 176.904 4.248 ;
    END
  END wd_in[303]
  PIN wd_in[304]
    DIRECTION INPUT ;
    USE SIGNAL ;
    SHAPE ABUTMENT ;
    PORT
      LAYER M4 ;
      RECT 176.880 4.320 176.904 4.344 ;
    END
  END wd_in[304]
  PIN wd_in[305]
    DIRECTION INPUT ;
    USE SIGNAL ;
    SHAPE ABUTMENT ;
    PORT
      LAYER M4 ;
      RECT 176.880 4.416 176.904 4.440 ;
    END
  END wd_in[305]
  PIN wd_in[306]
    DIRECTION INPUT ;
    USE SIGNAL ;
    SHAPE ABUTMENT ;
    PORT
      LAYER M4 ;
      RECT 176.880 4.512 176.904 4.536 ;
    END
  END wd_in[306]
  PIN wd_in[307]
    DIRECTION INPUT ;
    USE SIGNAL ;
    SHAPE ABUTMENT ;
    PORT
      LAYER M4 ;
      RECT 176.880 4.608 176.904 4.632 ;
    END
  END wd_in[307]
  PIN wd_in[308]
    DIRECTION INPUT ;
    USE SIGNAL ;
    SHAPE ABUTMENT ;
    PORT
      LAYER M4 ;
      RECT 176.880 4.704 176.904 4.728 ;
    END
  END wd_in[308]
  PIN wd_in[309]
    DIRECTION INPUT ;
    USE SIGNAL ;
    SHAPE ABUTMENT ;
    PORT
      LAYER M4 ;
      RECT 176.880 4.800 176.904 4.824 ;
    END
  END wd_in[309]
  PIN wd_in[310]
    DIRECTION INPUT ;
    USE SIGNAL ;
    SHAPE ABUTMENT ;
    PORT
      LAYER M4 ;
      RECT 176.880 4.896 176.904 4.920 ;
    END
  END wd_in[310]
  PIN wd_in[311]
    DIRECTION INPUT ;
    USE SIGNAL ;
    SHAPE ABUTMENT ;
    PORT
      LAYER M4 ;
      RECT 176.880 4.992 176.904 5.016 ;
    END
  END wd_in[311]
  PIN wd_in[312]
    DIRECTION INPUT ;
    USE SIGNAL ;
    SHAPE ABUTMENT ;
    PORT
      LAYER M4 ;
      RECT 176.880 5.088 176.904 5.112 ;
    END
  END wd_in[312]
  PIN wd_in[313]
    DIRECTION INPUT ;
    USE SIGNAL ;
    SHAPE ABUTMENT ;
    PORT
      LAYER M4 ;
      RECT 176.880 5.184 176.904 5.208 ;
    END
  END wd_in[313]
  PIN wd_in[314]
    DIRECTION INPUT ;
    USE SIGNAL ;
    SHAPE ABUTMENT ;
    PORT
      LAYER M4 ;
      RECT 176.880 5.280 176.904 5.304 ;
    END
  END wd_in[314]
  PIN wd_in[315]
    DIRECTION INPUT ;
    USE SIGNAL ;
    SHAPE ABUTMENT ;
    PORT
      LAYER M4 ;
      RECT 176.880 5.376 176.904 5.400 ;
    END
  END wd_in[315]
  PIN wd_in[316]
    DIRECTION INPUT ;
    USE SIGNAL ;
    SHAPE ABUTMENT ;
    PORT
      LAYER M4 ;
      RECT 176.880 5.472 176.904 5.496 ;
    END
  END wd_in[316]
  PIN wd_in[317]
    DIRECTION INPUT ;
    USE SIGNAL ;
    SHAPE ABUTMENT ;
    PORT
      LAYER M4 ;
      RECT 176.880 5.568 176.904 5.592 ;
    END
  END wd_in[317]
  PIN wd_in[318]
    DIRECTION INPUT ;
    USE SIGNAL ;
    SHAPE ABUTMENT ;
    PORT
      LAYER M4 ;
      RECT 176.880 5.664 176.904 5.688 ;
    END
  END wd_in[318]
  PIN wd_in[319]
    DIRECTION INPUT ;
    USE SIGNAL ;
    SHAPE ABUTMENT ;
    PORT
      LAYER M4 ;
      RECT 176.880 5.760 176.904 5.784 ;
    END
  END wd_in[319]
  PIN wd_in[320]
    DIRECTION INPUT ;
    USE SIGNAL ;
    SHAPE ABUTMENT ;
    PORT
      LAYER M4 ;
      RECT 176.880 5.856 176.904 5.880 ;
    END
  END wd_in[320]
  PIN wd_in[321]
    DIRECTION INPUT ;
    USE SIGNAL ;
    SHAPE ABUTMENT ;
    PORT
      LAYER M4 ;
      RECT 176.880 5.952 176.904 5.976 ;
    END
  END wd_in[321]
  PIN wd_in[322]
    DIRECTION INPUT ;
    USE SIGNAL ;
    SHAPE ABUTMENT ;
    PORT
      LAYER M4 ;
      RECT 176.880 6.048 176.904 6.072 ;
    END
  END wd_in[322]
  PIN wd_in[323]
    DIRECTION INPUT ;
    USE SIGNAL ;
    SHAPE ABUTMENT ;
    PORT
      LAYER M4 ;
      RECT 176.880 6.144 176.904 6.168 ;
    END
  END wd_in[323]
  PIN wd_in[324]
    DIRECTION INPUT ;
    USE SIGNAL ;
    SHAPE ABUTMENT ;
    PORT
      LAYER M4 ;
      RECT 176.880 6.240 176.904 6.264 ;
    END
  END wd_in[324]
  PIN wd_in[325]
    DIRECTION INPUT ;
    USE SIGNAL ;
    SHAPE ABUTMENT ;
    PORT
      LAYER M4 ;
      RECT 176.880 6.336 176.904 6.360 ;
    END
  END wd_in[325]
  PIN wd_in[326]
    DIRECTION INPUT ;
    USE SIGNAL ;
    SHAPE ABUTMENT ;
    PORT
      LAYER M4 ;
      RECT 176.880 6.432 176.904 6.456 ;
    END
  END wd_in[326]
  PIN wd_in[327]
    DIRECTION INPUT ;
    USE SIGNAL ;
    SHAPE ABUTMENT ;
    PORT
      LAYER M4 ;
      RECT 176.880 6.528 176.904 6.552 ;
    END
  END wd_in[327]
  PIN wd_in[328]
    DIRECTION INPUT ;
    USE SIGNAL ;
    SHAPE ABUTMENT ;
    PORT
      LAYER M4 ;
      RECT 176.880 6.624 176.904 6.648 ;
    END
  END wd_in[328]
  PIN wd_in[329]
    DIRECTION INPUT ;
    USE SIGNAL ;
    SHAPE ABUTMENT ;
    PORT
      LAYER M4 ;
      RECT 176.880 6.720 176.904 6.744 ;
    END
  END wd_in[329]
  PIN wd_in[330]
    DIRECTION INPUT ;
    USE SIGNAL ;
    SHAPE ABUTMENT ;
    PORT
      LAYER M4 ;
      RECT 176.880 6.816 176.904 6.840 ;
    END
  END wd_in[330]
  PIN wd_in[331]
    DIRECTION INPUT ;
    USE SIGNAL ;
    SHAPE ABUTMENT ;
    PORT
      LAYER M4 ;
      RECT 176.880 6.912 176.904 6.936 ;
    END
  END wd_in[331]
  PIN wd_in[332]
    DIRECTION INPUT ;
    USE SIGNAL ;
    SHAPE ABUTMENT ;
    PORT
      LAYER M4 ;
      RECT 176.880 7.008 176.904 7.032 ;
    END
  END wd_in[332]
  PIN wd_in[333]
    DIRECTION INPUT ;
    USE SIGNAL ;
    SHAPE ABUTMENT ;
    PORT
      LAYER M4 ;
      RECT 176.880 7.104 176.904 7.128 ;
    END
  END wd_in[333]
  PIN wd_in[334]
    DIRECTION INPUT ;
    USE SIGNAL ;
    SHAPE ABUTMENT ;
    PORT
      LAYER M4 ;
      RECT 176.880 7.200 176.904 7.224 ;
    END
  END wd_in[334]
  PIN wd_in[335]
    DIRECTION INPUT ;
    USE SIGNAL ;
    SHAPE ABUTMENT ;
    PORT
      LAYER M4 ;
      RECT 176.880 7.296 176.904 7.320 ;
    END
  END wd_in[335]
  PIN wd_in[336]
    DIRECTION INPUT ;
    USE SIGNAL ;
    SHAPE ABUTMENT ;
    PORT
      LAYER M4 ;
      RECT 176.880 7.392 176.904 7.416 ;
    END
  END wd_in[336]
  PIN wd_in[337]
    DIRECTION INPUT ;
    USE SIGNAL ;
    SHAPE ABUTMENT ;
    PORT
      LAYER M4 ;
      RECT 176.880 7.488 176.904 7.512 ;
    END
  END wd_in[337]
  PIN wd_in[338]
    DIRECTION INPUT ;
    USE SIGNAL ;
    SHAPE ABUTMENT ;
    PORT
      LAYER M4 ;
      RECT 176.880 7.584 176.904 7.608 ;
    END
  END wd_in[338]
  PIN wd_in[339]
    DIRECTION INPUT ;
    USE SIGNAL ;
    SHAPE ABUTMENT ;
    PORT
      LAYER M4 ;
      RECT 176.880 7.680 176.904 7.704 ;
    END
  END wd_in[339]
  PIN wd_in[340]
    DIRECTION INPUT ;
    USE SIGNAL ;
    SHAPE ABUTMENT ;
    PORT
      LAYER M4 ;
      RECT 176.880 7.776 176.904 7.800 ;
    END
  END wd_in[340]
  PIN wd_in[341]
    DIRECTION INPUT ;
    USE SIGNAL ;
    SHAPE ABUTMENT ;
    PORT
      LAYER M4 ;
      RECT 176.880 7.872 176.904 7.896 ;
    END
  END wd_in[341]
  PIN wd_in[342]
    DIRECTION INPUT ;
    USE SIGNAL ;
    SHAPE ABUTMENT ;
    PORT
      LAYER M4 ;
      RECT 176.880 7.968 176.904 7.992 ;
    END
  END wd_in[342]
  PIN wd_in[343]
    DIRECTION INPUT ;
    USE SIGNAL ;
    SHAPE ABUTMENT ;
    PORT
      LAYER M4 ;
      RECT 176.880 8.064 176.904 8.088 ;
    END
  END wd_in[343]
  PIN wd_in[344]
    DIRECTION INPUT ;
    USE SIGNAL ;
    SHAPE ABUTMENT ;
    PORT
      LAYER M4 ;
      RECT 176.880 8.160 176.904 8.184 ;
    END
  END wd_in[344]
  PIN wd_in[345]
    DIRECTION INPUT ;
    USE SIGNAL ;
    SHAPE ABUTMENT ;
    PORT
      LAYER M4 ;
      RECT 176.880 8.256 176.904 8.280 ;
    END
  END wd_in[345]
  PIN wd_in[346]
    DIRECTION INPUT ;
    USE SIGNAL ;
    SHAPE ABUTMENT ;
    PORT
      LAYER M4 ;
      RECT 176.880 8.352 176.904 8.376 ;
    END
  END wd_in[346]
  PIN wd_in[347]
    DIRECTION INPUT ;
    USE SIGNAL ;
    SHAPE ABUTMENT ;
    PORT
      LAYER M4 ;
      RECT 176.880 8.448 176.904 8.472 ;
    END
  END wd_in[347]
  PIN wd_in[348]
    DIRECTION INPUT ;
    USE SIGNAL ;
    SHAPE ABUTMENT ;
    PORT
      LAYER M4 ;
      RECT 176.880 8.544 176.904 8.568 ;
    END
  END wd_in[348]
  PIN wd_in[349]
    DIRECTION INPUT ;
    USE SIGNAL ;
    SHAPE ABUTMENT ;
    PORT
      LAYER M4 ;
      RECT 176.880 8.640 176.904 8.664 ;
    END
  END wd_in[349]
  PIN wd_in[350]
    DIRECTION INPUT ;
    USE SIGNAL ;
    SHAPE ABUTMENT ;
    PORT
      LAYER M4 ;
      RECT 176.880 8.736 176.904 8.760 ;
    END
  END wd_in[350]
  PIN wd_in[351]
    DIRECTION INPUT ;
    USE SIGNAL ;
    SHAPE ABUTMENT ;
    PORT
      LAYER M4 ;
      RECT 176.880 8.832 176.904 8.856 ;
    END
  END wd_in[351]
  PIN wd_in[352]
    DIRECTION INPUT ;
    USE SIGNAL ;
    SHAPE ABUTMENT ;
    PORT
      LAYER M4 ;
      RECT 176.880 8.928 176.904 8.952 ;
    END
  END wd_in[352]
  PIN wd_in[353]
    DIRECTION INPUT ;
    USE SIGNAL ;
    SHAPE ABUTMENT ;
    PORT
      LAYER M4 ;
      RECT 176.880 9.024 176.904 9.048 ;
    END
  END wd_in[353]
  PIN wd_in[354]
    DIRECTION INPUT ;
    USE SIGNAL ;
    SHAPE ABUTMENT ;
    PORT
      LAYER M4 ;
      RECT 176.880 9.120 176.904 9.144 ;
    END
  END wd_in[354]
  PIN wd_in[355]
    DIRECTION INPUT ;
    USE SIGNAL ;
    SHAPE ABUTMENT ;
    PORT
      LAYER M4 ;
      RECT 176.880 9.216 176.904 9.240 ;
    END
  END wd_in[355]
  PIN wd_in[356]
    DIRECTION INPUT ;
    USE SIGNAL ;
    SHAPE ABUTMENT ;
    PORT
      LAYER M4 ;
      RECT 176.880 9.312 176.904 9.336 ;
    END
  END wd_in[356]
  PIN wd_in[357]
    DIRECTION INPUT ;
    USE SIGNAL ;
    SHAPE ABUTMENT ;
    PORT
      LAYER M4 ;
      RECT 176.880 9.408 176.904 9.432 ;
    END
  END wd_in[357]
  PIN wd_in[358]
    DIRECTION INPUT ;
    USE SIGNAL ;
    SHAPE ABUTMENT ;
    PORT
      LAYER M4 ;
      RECT 176.880 9.504 176.904 9.528 ;
    END
  END wd_in[358]
  PIN wd_in[359]
    DIRECTION INPUT ;
    USE SIGNAL ;
    SHAPE ABUTMENT ;
    PORT
      LAYER M4 ;
      RECT 176.880 9.600 176.904 9.624 ;
    END
  END wd_in[359]
  PIN wd_in[360]
    DIRECTION INPUT ;
    USE SIGNAL ;
    SHAPE ABUTMENT ;
    PORT
      LAYER M4 ;
      RECT 176.880 9.696 176.904 9.720 ;
    END
  END wd_in[360]
  PIN wd_in[361]
    DIRECTION INPUT ;
    USE SIGNAL ;
    SHAPE ABUTMENT ;
    PORT
      LAYER M4 ;
      RECT 176.880 9.792 176.904 9.816 ;
    END
  END wd_in[361]
  PIN wd_in[362]
    DIRECTION INPUT ;
    USE SIGNAL ;
    SHAPE ABUTMENT ;
    PORT
      LAYER M4 ;
      RECT 176.880 9.888 176.904 9.912 ;
    END
  END wd_in[362]
  PIN wd_in[363]
    DIRECTION INPUT ;
    USE SIGNAL ;
    SHAPE ABUTMENT ;
    PORT
      LAYER M4 ;
      RECT 176.880 9.984 176.904 10.008 ;
    END
  END wd_in[363]
  PIN wd_in[364]
    DIRECTION INPUT ;
    USE SIGNAL ;
    SHAPE ABUTMENT ;
    PORT
      LAYER M4 ;
      RECT 176.880 10.080 176.904 10.104 ;
    END
  END wd_in[364]
  PIN wd_in[365]
    DIRECTION INPUT ;
    USE SIGNAL ;
    SHAPE ABUTMENT ;
    PORT
      LAYER M4 ;
      RECT 176.880 10.176 176.904 10.200 ;
    END
  END wd_in[365]
  PIN wd_in[366]
    DIRECTION INPUT ;
    USE SIGNAL ;
    SHAPE ABUTMENT ;
    PORT
      LAYER M4 ;
      RECT 176.880 10.272 176.904 10.296 ;
    END
  END wd_in[366]
  PIN wd_in[367]
    DIRECTION INPUT ;
    USE SIGNAL ;
    SHAPE ABUTMENT ;
    PORT
      LAYER M4 ;
      RECT 176.880 10.368 176.904 10.392 ;
    END
  END wd_in[367]
  PIN wd_in[368]
    DIRECTION INPUT ;
    USE SIGNAL ;
    SHAPE ABUTMENT ;
    PORT
      LAYER M4 ;
      RECT 176.880 10.464 176.904 10.488 ;
    END
  END wd_in[368]
  PIN wd_in[369]
    DIRECTION INPUT ;
    USE SIGNAL ;
    SHAPE ABUTMENT ;
    PORT
      LAYER M4 ;
      RECT 176.880 10.560 176.904 10.584 ;
    END
  END wd_in[369]
  PIN wd_in[370]
    DIRECTION INPUT ;
    USE SIGNAL ;
    SHAPE ABUTMENT ;
    PORT
      LAYER M4 ;
      RECT 176.880 10.656 176.904 10.680 ;
    END
  END wd_in[370]
  PIN wd_in[371]
    DIRECTION INPUT ;
    USE SIGNAL ;
    SHAPE ABUTMENT ;
    PORT
      LAYER M4 ;
      RECT 176.880 10.752 176.904 10.776 ;
    END
  END wd_in[371]
  PIN wd_in[372]
    DIRECTION INPUT ;
    USE SIGNAL ;
    SHAPE ABUTMENT ;
    PORT
      LAYER M4 ;
      RECT 176.880 10.848 176.904 10.872 ;
    END
  END wd_in[372]
  PIN wd_in[373]
    DIRECTION INPUT ;
    USE SIGNAL ;
    SHAPE ABUTMENT ;
    PORT
      LAYER M4 ;
      RECT 176.880 10.944 176.904 10.968 ;
    END
  END wd_in[373]
  PIN wd_in[374]
    DIRECTION INPUT ;
    USE SIGNAL ;
    SHAPE ABUTMENT ;
    PORT
      LAYER M4 ;
      RECT 176.880 11.040 176.904 11.064 ;
    END
  END wd_in[374]
  PIN wd_in[375]
    DIRECTION INPUT ;
    USE SIGNAL ;
    SHAPE ABUTMENT ;
    PORT
      LAYER M4 ;
      RECT 176.880 11.136 176.904 11.160 ;
    END
  END wd_in[375]
  PIN wd_in[376]
    DIRECTION INPUT ;
    USE SIGNAL ;
    SHAPE ABUTMENT ;
    PORT
      LAYER M4 ;
      RECT 176.880 11.232 176.904 11.256 ;
    END
  END wd_in[376]
  PIN wd_in[377]
    DIRECTION INPUT ;
    USE SIGNAL ;
    SHAPE ABUTMENT ;
    PORT
      LAYER M4 ;
      RECT 176.880 11.328 176.904 11.352 ;
    END
  END wd_in[377]
  PIN wd_in[378]
    DIRECTION INPUT ;
    USE SIGNAL ;
    SHAPE ABUTMENT ;
    PORT
      LAYER M4 ;
      RECT 176.880 11.424 176.904 11.448 ;
    END
  END wd_in[378]
  PIN wd_in[379]
    DIRECTION INPUT ;
    USE SIGNAL ;
    SHAPE ABUTMENT ;
    PORT
      LAYER M4 ;
      RECT 176.880 11.520 176.904 11.544 ;
    END
  END wd_in[379]
  PIN wd_in[380]
    DIRECTION INPUT ;
    USE SIGNAL ;
    SHAPE ABUTMENT ;
    PORT
      LAYER M4 ;
      RECT 176.880 11.616 176.904 11.640 ;
    END
  END wd_in[380]
  PIN wd_in[381]
    DIRECTION INPUT ;
    USE SIGNAL ;
    SHAPE ABUTMENT ;
    PORT
      LAYER M4 ;
      RECT 176.880 11.712 176.904 11.736 ;
    END
  END wd_in[381]
  PIN wd_in[382]
    DIRECTION INPUT ;
    USE SIGNAL ;
    SHAPE ABUTMENT ;
    PORT
      LAYER M4 ;
      RECT 176.880 11.808 176.904 11.832 ;
    END
  END wd_in[382]
  PIN wd_in[383]
    DIRECTION INPUT ;
    USE SIGNAL ;
    SHAPE ABUTMENT ;
    PORT
      LAYER M4 ;
      RECT 176.880 11.904 176.904 11.928 ;
    END
  END wd_in[383]
  PIN wd_in[384]
    DIRECTION INPUT ;
    USE SIGNAL ;
    SHAPE ABUTMENT ;
    PORT
      LAYER M4 ;
      RECT 176.880 12.000 176.904 12.024 ;
    END
  END wd_in[384]
  PIN wd_in[385]
    DIRECTION INPUT ;
    USE SIGNAL ;
    SHAPE ABUTMENT ;
    PORT
      LAYER M4 ;
      RECT 176.880 12.096 176.904 12.120 ;
    END
  END wd_in[385]
  PIN wd_in[386]
    DIRECTION INPUT ;
    USE SIGNAL ;
    SHAPE ABUTMENT ;
    PORT
      LAYER M4 ;
      RECT 176.880 12.192 176.904 12.216 ;
    END
  END wd_in[386]
  PIN wd_in[387]
    DIRECTION INPUT ;
    USE SIGNAL ;
    SHAPE ABUTMENT ;
    PORT
      LAYER M4 ;
      RECT 176.880 12.288 176.904 12.312 ;
    END
  END wd_in[387]
  PIN wd_in[388]
    DIRECTION INPUT ;
    USE SIGNAL ;
    SHAPE ABUTMENT ;
    PORT
      LAYER M4 ;
      RECT 176.880 12.384 176.904 12.408 ;
    END
  END wd_in[388]
  PIN wd_in[389]
    DIRECTION INPUT ;
    USE SIGNAL ;
    SHAPE ABUTMENT ;
    PORT
      LAYER M4 ;
      RECT 176.880 12.480 176.904 12.504 ;
    END
  END wd_in[389]
  PIN wd_in[390]
    DIRECTION INPUT ;
    USE SIGNAL ;
    SHAPE ABUTMENT ;
    PORT
      LAYER M4 ;
      RECT 176.880 12.576 176.904 12.600 ;
    END
  END wd_in[390]
  PIN wd_in[391]
    DIRECTION INPUT ;
    USE SIGNAL ;
    SHAPE ABUTMENT ;
    PORT
      LAYER M4 ;
      RECT 176.880 12.672 176.904 12.696 ;
    END
  END wd_in[391]
  PIN wd_in[392]
    DIRECTION INPUT ;
    USE SIGNAL ;
    SHAPE ABUTMENT ;
    PORT
      LAYER M4 ;
      RECT 176.880 12.768 176.904 12.792 ;
    END
  END wd_in[392]
  PIN wd_in[393]
    DIRECTION INPUT ;
    USE SIGNAL ;
    SHAPE ABUTMENT ;
    PORT
      LAYER M4 ;
      RECT 176.880 12.864 176.904 12.888 ;
    END
  END wd_in[393]
  PIN wd_in[394]
    DIRECTION INPUT ;
    USE SIGNAL ;
    SHAPE ABUTMENT ;
    PORT
      LAYER M4 ;
      RECT 176.880 12.960 176.904 12.984 ;
    END
  END wd_in[394]
  PIN wd_in[395]
    DIRECTION INPUT ;
    USE SIGNAL ;
    SHAPE ABUTMENT ;
    PORT
      LAYER M4 ;
      RECT 176.880 13.056 176.904 13.080 ;
    END
  END wd_in[395]
  PIN wd_in[396]
    DIRECTION INPUT ;
    USE SIGNAL ;
    SHAPE ABUTMENT ;
    PORT
      LAYER M4 ;
      RECT 176.880 13.152 176.904 13.176 ;
    END
  END wd_in[396]
  PIN wd_in[397]
    DIRECTION INPUT ;
    USE SIGNAL ;
    SHAPE ABUTMENT ;
    PORT
      LAYER M4 ;
      RECT 176.880 13.248 176.904 13.272 ;
    END
  END wd_in[397]
  PIN wd_in[398]
    DIRECTION INPUT ;
    USE SIGNAL ;
    SHAPE ABUTMENT ;
    PORT
      LAYER M4 ;
      RECT 176.880 13.344 176.904 13.368 ;
    END
  END wd_in[398]
  PIN wd_in[399]
    DIRECTION INPUT ;
    USE SIGNAL ;
    SHAPE ABUTMENT ;
    PORT
      LAYER M4 ;
      RECT 176.880 13.440 176.904 13.464 ;
    END
  END wd_in[399]
  PIN wd_in[400]
    DIRECTION INPUT ;
    USE SIGNAL ;
    SHAPE ABUTMENT ;
    PORT
      LAYER M4 ;
      RECT 176.880 13.536 176.904 13.560 ;
    END
  END wd_in[400]
  PIN wd_in[401]
    DIRECTION INPUT ;
    USE SIGNAL ;
    SHAPE ABUTMENT ;
    PORT
      LAYER M4 ;
      RECT 176.880 13.632 176.904 13.656 ;
    END
  END wd_in[401]
  PIN wd_in[402]
    DIRECTION INPUT ;
    USE SIGNAL ;
    SHAPE ABUTMENT ;
    PORT
      LAYER M4 ;
      RECT 176.880 13.728 176.904 13.752 ;
    END
  END wd_in[402]
  PIN wd_in[403]
    DIRECTION INPUT ;
    USE SIGNAL ;
    SHAPE ABUTMENT ;
    PORT
      LAYER M4 ;
      RECT 176.880 13.824 176.904 13.848 ;
    END
  END wd_in[403]
  PIN wd_in[404]
    DIRECTION INPUT ;
    USE SIGNAL ;
    SHAPE ABUTMENT ;
    PORT
      LAYER M4 ;
      RECT 176.880 13.920 176.904 13.944 ;
    END
  END wd_in[404]
  PIN wd_in[405]
    DIRECTION INPUT ;
    USE SIGNAL ;
    SHAPE ABUTMENT ;
    PORT
      LAYER M4 ;
      RECT 176.880 14.016 176.904 14.040 ;
    END
  END wd_in[405]
  PIN wd_in[406]
    DIRECTION INPUT ;
    USE SIGNAL ;
    SHAPE ABUTMENT ;
    PORT
      LAYER M4 ;
      RECT 176.880 14.112 176.904 14.136 ;
    END
  END wd_in[406]
  PIN wd_in[407]
    DIRECTION INPUT ;
    USE SIGNAL ;
    SHAPE ABUTMENT ;
    PORT
      LAYER M4 ;
      RECT 176.880 14.208 176.904 14.232 ;
    END
  END wd_in[407]
  PIN wd_in[408]
    DIRECTION INPUT ;
    USE SIGNAL ;
    SHAPE ABUTMENT ;
    PORT
      LAYER M4 ;
      RECT 176.880 14.304 176.904 14.328 ;
    END
  END wd_in[408]
  PIN wd_in[409]
    DIRECTION INPUT ;
    USE SIGNAL ;
    SHAPE ABUTMENT ;
    PORT
      LAYER M4 ;
      RECT 176.880 14.400 176.904 14.424 ;
    END
  END wd_in[409]
  PIN wd_in[410]
    DIRECTION INPUT ;
    USE SIGNAL ;
    SHAPE ABUTMENT ;
    PORT
      LAYER M4 ;
      RECT 176.880 14.496 176.904 14.520 ;
    END
  END wd_in[410]
  PIN wd_in[411]
    DIRECTION INPUT ;
    USE SIGNAL ;
    SHAPE ABUTMENT ;
    PORT
      LAYER M4 ;
      RECT 176.880 14.592 176.904 14.616 ;
    END
  END wd_in[411]
  PIN wd_in[412]
    DIRECTION INPUT ;
    USE SIGNAL ;
    SHAPE ABUTMENT ;
    PORT
      LAYER M4 ;
      RECT 176.880 14.688 176.904 14.712 ;
    END
  END wd_in[412]
  PIN wd_in[413]
    DIRECTION INPUT ;
    USE SIGNAL ;
    SHAPE ABUTMENT ;
    PORT
      LAYER M4 ;
      RECT 176.880 14.784 176.904 14.808 ;
    END
  END wd_in[413]
  PIN wd_in[414]
    DIRECTION INPUT ;
    USE SIGNAL ;
    SHAPE ABUTMENT ;
    PORT
      LAYER M4 ;
      RECT 176.880 14.880 176.904 14.904 ;
    END
  END wd_in[414]
  PIN wd_in[415]
    DIRECTION INPUT ;
    USE SIGNAL ;
    SHAPE ABUTMENT ;
    PORT
      LAYER M4 ;
      RECT 176.880 14.976 176.904 15.000 ;
    END
  END wd_in[415]
  PIN wd_in[416]
    DIRECTION INPUT ;
    USE SIGNAL ;
    SHAPE ABUTMENT ;
    PORT
      LAYER M4 ;
      RECT 176.880 15.072 176.904 15.096 ;
    END
  END wd_in[416]
  PIN wd_in[417]
    DIRECTION INPUT ;
    USE SIGNAL ;
    SHAPE ABUTMENT ;
    PORT
      LAYER M4 ;
      RECT 176.880 15.168 176.904 15.192 ;
    END
  END wd_in[417]
  PIN wd_in[418]
    DIRECTION INPUT ;
    USE SIGNAL ;
    SHAPE ABUTMENT ;
    PORT
      LAYER M4 ;
      RECT 176.880 15.264 176.904 15.288 ;
    END
  END wd_in[418]
  PIN wd_in[419]
    DIRECTION INPUT ;
    USE SIGNAL ;
    SHAPE ABUTMENT ;
    PORT
      LAYER M4 ;
      RECT 176.880 15.360 176.904 15.384 ;
    END
  END wd_in[419]
  PIN wd_in[420]
    DIRECTION INPUT ;
    USE SIGNAL ;
    SHAPE ABUTMENT ;
    PORT
      LAYER M4 ;
      RECT 176.880 15.456 176.904 15.480 ;
    END
  END wd_in[420]
  PIN wd_in[421]
    DIRECTION INPUT ;
    USE SIGNAL ;
    SHAPE ABUTMENT ;
    PORT
      LAYER M4 ;
      RECT 176.880 15.552 176.904 15.576 ;
    END
  END wd_in[421]
  PIN wd_in[422]
    DIRECTION INPUT ;
    USE SIGNAL ;
    SHAPE ABUTMENT ;
    PORT
      LAYER M4 ;
      RECT 176.880 15.648 176.904 15.672 ;
    END
  END wd_in[422]
  PIN wd_in[423]
    DIRECTION INPUT ;
    USE SIGNAL ;
    SHAPE ABUTMENT ;
    PORT
      LAYER M4 ;
      RECT 176.880 15.744 176.904 15.768 ;
    END
  END wd_in[423]
  PIN wd_in[424]
    DIRECTION INPUT ;
    USE SIGNAL ;
    SHAPE ABUTMENT ;
    PORT
      LAYER M4 ;
      RECT 176.880 15.840 176.904 15.864 ;
    END
  END wd_in[424]
  PIN wd_in[425]
    DIRECTION INPUT ;
    USE SIGNAL ;
    SHAPE ABUTMENT ;
    PORT
      LAYER M4 ;
      RECT 176.880 15.936 176.904 15.960 ;
    END
  END wd_in[425]
  PIN wd_in[426]
    DIRECTION INPUT ;
    USE SIGNAL ;
    SHAPE ABUTMENT ;
    PORT
      LAYER M4 ;
      RECT 176.880 16.032 176.904 16.056 ;
    END
  END wd_in[426]
  PIN wd_in[427]
    DIRECTION INPUT ;
    USE SIGNAL ;
    SHAPE ABUTMENT ;
    PORT
      LAYER M4 ;
      RECT 176.880 16.128 176.904 16.152 ;
    END
  END wd_in[427]
  PIN wd_in[428]
    DIRECTION INPUT ;
    USE SIGNAL ;
    SHAPE ABUTMENT ;
    PORT
      LAYER M4 ;
      RECT 176.880 16.224 176.904 16.248 ;
    END
  END wd_in[428]
  PIN wd_in[429]
    DIRECTION INPUT ;
    USE SIGNAL ;
    SHAPE ABUTMENT ;
    PORT
      LAYER M4 ;
      RECT 176.880 16.320 176.904 16.344 ;
    END
  END wd_in[429]
  PIN wd_in[430]
    DIRECTION INPUT ;
    USE SIGNAL ;
    SHAPE ABUTMENT ;
    PORT
      LAYER M4 ;
      RECT 176.880 16.416 176.904 16.440 ;
    END
  END wd_in[430]
  PIN wd_in[431]
    DIRECTION INPUT ;
    USE SIGNAL ;
    SHAPE ABUTMENT ;
    PORT
      LAYER M4 ;
      RECT 176.880 16.512 176.904 16.536 ;
    END
  END wd_in[431]
  PIN wd_in[432]
    DIRECTION INPUT ;
    USE SIGNAL ;
    SHAPE ABUTMENT ;
    PORT
      LAYER M4 ;
      RECT 176.880 16.608 176.904 16.632 ;
    END
  END wd_in[432]
  PIN wd_in[433]
    DIRECTION INPUT ;
    USE SIGNAL ;
    SHAPE ABUTMENT ;
    PORT
      LAYER M4 ;
      RECT 176.880 16.704 176.904 16.728 ;
    END
  END wd_in[433]
  PIN wd_in[434]
    DIRECTION INPUT ;
    USE SIGNAL ;
    SHAPE ABUTMENT ;
    PORT
      LAYER M4 ;
      RECT 176.880 16.800 176.904 16.824 ;
    END
  END wd_in[434]
  PIN wd_in[435]
    DIRECTION INPUT ;
    USE SIGNAL ;
    SHAPE ABUTMENT ;
    PORT
      LAYER M4 ;
      RECT 176.880 16.896 176.904 16.920 ;
    END
  END wd_in[435]
  PIN wd_in[436]
    DIRECTION INPUT ;
    USE SIGNAL ;
    SHAPE ABUTMENT ;
    PORT
      LAYER M4 ;
      RECT 176.880 16.992 176.904 17.016 ;
    END
  END wd_in[436]
  PIN wd_in[437]
    DIRECTION INPUT ;
    USE SIGNAL ;
    SHAPE ABUTMENT ;
    PORT
      LAYER M4 ;
      RECT 176.880 17.088 176.904 17.112 ;
    END
  END wd_in[437]
  PIN wd_in[438]
    DIRECTION INPUT ;
    USE SIGNAL ;
    SHAPE ABUTMENT ;
    PORT
      LAYER M4 ;
      RECT 176.880 17.184 176.904 17.208 ;
    END
  END wd_in[438]
  PIN wd_in[439]
    DIRECTION INPUT ;
    USE SIGNAL ;
    SHAPE ABUTMENT ;
    PORT
      LAYER M4 ;
      RECT 176.880 17.280 176.904 17.304 ;
    END
  END wd_in[439]
  PIN wd_in[440]
    DIRECTION INPUT ;
    USE SIGNAL ;
    SHAPE ABUTMENT ;
    PORT
      LAYER M4 ;
      RECT 176.880 17.376 176.904 17.400 ;
    END
  END wd_in[440]
  PIN wd_in[441]
    DIRECTION INPUT ;
    USE SIGNAL ;
    SHAPE ABUTMENT ;
    PORT
      LAYER M4 ;
      RECT 176.880 17.472 176.904 17.496 ;
    END
  END wd_in[441]
  PIN wd_in[442]
    DIRECTION INPUT ;
    USE SIGNAL ;
    SHAPE ABUTMENT ;
    PORT
      LAYER M4 ;
      RECT 176.880 17.568 176.904 17.592 ;
    END
  END wd_in[442]
  PIN wd_in[443]
    DIRECTION INPUT ;
    USE SIGNAL ;
    SHAPE ABUTMENT ;
    PORT
      LAYER M4 ;
      RECT 176.880 17.664 176.904 17.688 ;
    END
  END wd_in[443]
  PIN wd_in[444]
    DIRECTION INPUT ;
    USE SIGNAL ;
    SHAPE ABUTMENT ;
    PORT
      LAYER M4 ;
      RECT 176.880 17.760 176.904 17.784 ;
    END
  END wd_in[444]
  PIN wd_in[445]
    DIRECTION INPUT ;
    USE SIGNAL ;
    SHAPE ABUTMENT ;
    PORT
      LAYER M4 ;
      RECT 176.880 17.856 176.904 17.880 ;
    END
  END wd_in[445]
  PIN wd_in[446]
    DIRECTION INPUT ;
    USE SIGNAL ;
    SHAPE ABUTMENT ;
    PORT
      LAYER M4 ;
      RECT 176.880 17.952 176.904 17.976 ;
    END
  END wd_in[446]
  PIN wd_in[447]
    DIRECTION INPUT ;
    USE SIGNAL ;
    SHAPE ABUTMENT ;
    PORT
      LAYER M4 ;
      RECT 176.880 18.048 176.904 18.072 ;
    END
  END wd_in[447]
  PIN wd_in[448]
    DIRECTION INPUT ;
    USE SIGNAL ;
    SHAPE ABUTMENT ;
    PORT
      LAYER M4 ;
      RECT 176.880 18.144 176.904 18.168 ;
    END
  END wd_in[448]
  PIN wd_in[449]
    DIRECTION INPUT ;
    USE SIGNAL ;
    SHAPE ABUTMENT ;
    PORT
      LAYER M4 ;
      RECT 176.880 18.240 176.904 18.264 ;
    END
  END wd_in[449]
  PIN wd_in[450]
    DIRECTION INPUT ;
    USE SIGNAL ;
    SHAPE ABUTMENT ;
    PORT
      LAYER M4 ;
      RECT 176.880 18.336 176.904 18.360 ;
    END
  END wd_in[450]
  PIN wd_in[451]
    DIRECTION INPUT ;
    USE SIGNAL ;
    SHAPE ABUTMENT ;
    PORT
      LAYER M4 ;
      RECT 176.880 18.432 176.904 18.456 ;
    END
  END wd_in[451]
  PIN wd_in[452]
    DIRECTION INPUT ;
    USE SIGNAL ;
    SHAPE ABUTMENT ;
    PORT
      LAYER M4 ;
      RECT 176.880 18.528 176.904 18.552 ;
    END
  END wd_in[452]
  PIN wd_in[453]
    DIRECTION INPUT ;
    USE SIGNAL ;
    SHAPE ABUTMENT ;
    PORT
      LAYER M4 ;
      RECT 176.880 18.624 176.904 18.648 ;
    END
  END wd_in[453]
  PIN wd_in[454]
    DIRECTION INPUT ;
    USE SIGNAL ;
    SHAPE ABUTMENT ;
    PORT
      LAYER M4 ;
      RECT 176.880 18.720 176.904 18.744 ;
    END
  END wd_in[454]
  PIN wd_in[455]
    DIRECTION INPUT ;
    USE SIGNAL ;
    SHAPE ABUTMENT ;
    PORT
      LAYER M4 ;
      RECT 176.880 18.816 176.904 18.840 ;
    END
  END wd_in[455]
  PIN wd_in[456]
    DIRECTION INPUT ;
    USE SIGNAL ;
    SHAPE ABUTMENT ;
    PORT
      LAYER M4 ;
      RECT 176.880 18.912 176.904 18.936 ;
    END
  END wd_in[456]
  PIN wd_in[457]
    DIRECTION INPUT ;
    USE SIGNAL ;
    SHAPE ABUTMENT ;
    PORT
      LAYER M4 ;
      RECT 176.880 19.008 176.904 19.032 ;
    END
  END wd_in[457]
  PIN wd_in[458]
    DIRECTION INPUT ;
    USE SIGNAL ;
    SHAPE ABUTMENT ;
    PORT
      LAYER M4 ;
      RECT 176.880 19.104 176.904 19.128 ;
    END
  END wd_in[458]
  PIN wd_in[459]
    DIRECTION INPUT ;
    USE SIGNAL ;
    SHAPE ABUTMENT ;
    PORT
      LAYER M4 ;
      RECT 176.880 19.200 176.904 19.224 ;
    END
  END wd_in[459]
  PIN wd_in[460]
    DIRECTION INPUT ;
    USE SIGNAL ;
    SHAPE ABUTMENT ;
    PORT
      LAYER M4 ;
      RECT 176.880 19.296 176.904 19.320 ;
    END
  END wd_in[460]
  PIN wd_in[461]
    DIRECTION INPUT ;
    USE SIGNAL ;
    SHAPE ABUTMENT ;
    PORT
      LAYER M4 ;
      RECT 176.880 19.392 176.904 19.416 ;
    END
  END wd_in[461]
  PIN wd_in[462]
    DIRECTION INPUT ;
    USE SIGNAL ;
    SHAPE ABUTMENT ;
    PORT
      LAYER M4 ;
      RECT 176.880 19.488 176.904 19.512 ;
    END
  END wd_in[462]
  PIN wd_in[463]
    DIRECTION INPUT ;
    USE SIGNAL ;
    SHAPE ABUTMENT ;
    PORT
      LAYER M4 ;
      RECT 176.880 19.584 176.904 19.608 ;
    END
  END wd_in[463]
  PIN wd_in[464]
    DIRECTION INPUT ;
    USE SIGNAL ;
    SHAPE ABUTMENT ;
    PORT
      LAYER M4 ;
      RECT 176.880 19.680 176.904 19.704 ;
    END
  END wd_in[464]
  PIN wd_in[465]
    DIRECTION INPUT ;
    USE SIGNAL ;
    SHAPE ABUTMENT ;
    PORT
      LAYER M4 ;
      RECT 176.880 19.776 176.904 19.800 ;
    END
  END wd_in[465]
  PIN wd_in[466]
    DIRECTION INPUT ;
    USE SIGNAL ;
    SHAPE ABUTMENT ;
    PORT
      LAYER M4 ;
      RECT 176.880 19.872 176.904 19.896 ;
    END
  END wd_in[466]
  PIN wd_in[467]
    DIRECTION INPUT ;
    USE SIGNAL ;
    SHAPE ABUTMENT ;
    PORT
      LAYER M4 ;
      RECT 176.880 19.968 176.904 19.992 ;
    END
  END wd_in[467]
  PIN wd_in[468]
    DIRECTION INPUT ;
    USE SIGNAL ;
    SHAPE ABUTMENT ;
    PORT
      LAYER M4 ;
      RECT 176.880 20.064 176.904 20.088 ;
    END
  END wd_in[468]
  PIN wd_in[469]
    DIRECTION INPUT ;
    USE SIGNAL ;
    SHAPE ABUTMENT ;
    PORT
      LAYER M4 ;
      RECT 176.880 20.160 176.904 20.184 ;
    END
  END wd_in[469]
  PIN wd_in[470]
    DIRECTION INPUT ;
    USE SIGNAL ;
    SHAPE ABUTMENT ;
    PORT
      LAYER M4 ;
      RECT 176.880 20.256 176.904 20.280 ;
    END
  END wd_in[470]
  PIN wd_in[471]
    DIRECTION INPUT ;
    USE SIGNAL ;
    SHAPE ABUTMENT ;
    PORT
      LAYER M4 ;
      RECT 176.880 20.352 176.904 20.376 ;
    END
  END wd_in[471]
  PIN wd_in[472]
    DIRECTION INPUT ;
    USE SIGNAL ;
    SHAPE ABUTMENT ;
    PORT
      LAYER M4 ;
      RECT 176.880 20.448 176.904 20.472 ;
    END
  END wd_in[472]
  PIN wd_in[473]
    DIRECTION INPUT ;
    USE SIGNAL ;
    SHAPE ABUTMENT ;
    PORT
      LAYER M4 ;
      RECT 176.880 20.544 176.904 20.568 ;
    END
  END wd_in[473]
  PIN wd_in[474]
    DIRECTION INPUT ;
    USE SIGNAL ;
    SHAPE ABUTMENT ;
    PORT
      LAYER M4 ;
      RECT 176.880 20.640 176.904 20.664 ;
    END
  END wd_in[474]
  PIN wd_in[475]
    DIRECTION INPUT ;
    USE SIGNAL ;
    SHAPE ABUTMENT ;
    PORT
      LAYER M4 ;
      RECT 176.880 20.736 176.904 20.760 ;
    END
  END wd_in[475]
  PIN wd_in[476]
    DIRECTION INPUT ;
    USE SIGNAL ;
    SHAPE ABUTMENT ;
    PORT
      LAYER M4 ;
      RECT 176.880 20.832 176.904 20.856 ;
    END
  END wd_in[476]
  PIN wd_in[477]
    DIRECTION INPUT ;
    USE SIGNAL ;
    SHAPE ABUTMENT ;
    PORT
      LAYER M4 ;
      RECT 176.880 20.928 176.904 20.952 ;
    END
  END wd_in[477]
  PIN wd_in[478]
    DIRECTION INPUT ;
    USE SIGNAL ;
    SHAPE ABUTMENT ;
    PORT
      LAYER M4 ;
      RECT 176.880 21.024 176.904 21.048 ;
    END
  END wd_in[478]
  PIN wd_in[479]
    DIRECTION INPUT ;
    USE SIGNAL ;
    SHAPE ABUTMENT ;
    PORT
      LAYER M4 ;
      RECT 176.880 21.120 176.904 21.144 ;
    END
  END wd_in[479]
  PIN wd_in[480]
    DIRECTION INPUT ;
    USE SIGNAL ;
    SHAPE ABUTMENT ;
    PORT
      LAYER M4 ;
      RECT 176.880 21.216 176.904 21.240 ;
    END
  END wd_in[480]
  PIN wd_in[481]
    DIRECTION INPUT ;
    USE SIGNAL ;
    SHAPE ABUTMENT ;
    PORT
      LAYER M4 ;
      RECT 176.880 21.312 176.904 21.336 ;
    END
  END wd_in[481]
  PIN wd_in[482]
    DIRECTION INPUT ;
    USE SIGNAL ;
    SHAPE ABUTMENT ;
    PORT
      LAYER M4 ;
      RECT 176.880 21.408 176.904 21.432 ;
    END
  END wd_in[482]
  PIN wd_in[483]
    DIRECTION INPUT ;
    USE SIGNAL ;
    SHAPE ABUTMENT ;
    PORT
      LAYER M4 ;
      RECT 176.880 21.504 176.904 21.528 ;
    END
  END wd_in[483]
  PIN wd_in[484]
    DIRECTION INPUT ;
    USE SIGNAL ;
    SHAPE ABUTMENT ;
    PORT
      LAYER M4 ;
      RECT 176.880 21.600 176.904 21.624 ;
    END
  END wd_in[484]
  PIN wd_in[485]
    DIRECTION INPUT ;
    USE SIGNAL ;
    SHAPE ABUTMENT ;
    PORT
      LAYER M4 ;
      RECT 176.880 21.696 176.904 21.720 ;
    END
  END wd_in[485]
  PIN wd_in[486]
    DIRECTION INPUT ;
    USE SIGNAL ;
    SHAPE ABUTMENT ;
    PORT
      LAYER M4 ;
      RECT 176.880 21.792 176.904 21.816 ;
    END
  END wd_in[486]
  PIN wd_in[487]
    DIRECTION INPUT ;
    USE SIGNAL ;
    SHAPE ABUTMENT ;
    PORT
      LAYER M4 ;
      RECT 176.880 21.888 176.904 21.912 ;
    END
  END wd_in[487]
  PIN wd_in[488]
    DIRECTION INPUT ;
    USE SIGNAL ;
    SHAPE ABUTMENT ;
    PORT
      LAYER M4 ;
      RECT 176.880 21.984 176.904 22.008 ;
    END
  END wd_in[488]
  PIN wd_in[489]
    DIRECTION INPUT ;
    USE SIGNAL ;
    SHAPE ABUTMENT ;
    PORT
      LAYER M4 ;
      RECT 176.880 22.080 176.904 22.104 ;
    END
  END wd_in[489]
  PIN wd_in[490]
    DIRECTION INPUT ;
    USE SIGNAL ;
    SHAPE ABUTMENT ;
    PORT
      LAYER M4 ;
      RECT 176.880 22.176 176.904 22.200 ;
    END
  END wd_in[490]
  PIN wd_in[491]
    DIRECTION INPUT ;
    USE SIGNAL ;
    SHAPE ABUTMENT ;
    PORT
      LAYER M4 ;
      RECT 176.880 22.272 176.904 22.296 ;
    END
  END wd_in[491]
  PIN wd_in[492]
    DIRECTION INPUT ;
    USE SIGNAL ;
    SHAPE ABUTMENT ;
    PORT
      LAYER M4 ;
      RECT 176.880 22.368 176.904 22.392 ;
    END
  END wd_in[492]
  PIN wd_in[493]
    DIRECTION INPUT ;
    USE SIGNAL ;
    SHAPE ABUTMENT ;
    PORT
      LAYER M4 ;
      RECT 176.880 22.464 176.904 22.488 ;
    END
  END wd_in[493]
  PIN wd_in[494]
    DIRECTION INPUT ;
    USE SIGNAL ;
    SHAPE ABUTMENT ;
    PORT
      LAYER M4 ;
      RECT 176.880 22.560 176.904 22.584 ;
    END
  END wd_in[494]
  PIN wd_in[495]
    DIRECTION INPUT ;
    USE SIGNAL ;
    SHAPE ABUTMENT ;
    PORT
      LAYER M4 ;
      RECT 176.880 22.656 176.904 22.680 ;
    END
  END wd_in[495]
  PIN wd_in[496]
    DIRECTION INPUT ;
    USE SIGNAL ;
    SHAPE ABUTMENT ;
    PORT
      LAYER M4 ;
      RECT 176.880 22.752 176.904 22.776 ;
    END
  END wd_in[496]
  PIN wd_in[497]
    DIRECTION INPUT ;
    USE SIGNAL ;
    SHAPE ABUTMENT ;
    PORT
      LAYER M4 ;
      RECT 176.880 22.848 176.904 22.872 ;
    END
  END wd_in[497]
  PIN wd_in[498]
    DIRECTION INPUT ;
    USE SIGNAL ;
    SHAPE ABUTMENT ;
    PORT
      LAYER M4 ;
      RECT 176.880 22.944 176.904 22.968 ;
    END
  END wd_in[498]
  PIN wd_in[499]
    DIRECTION INPUT ;
    USE SIGNAL ;
    SHAPE ABUTMENT ;
    PORT
      LAYER M4 ;
      RECT 176.880 23.040 176.904 23.064 ;
    END
  END wd_in[499]
  PIN wd_in[500]
    DIRECTION INPUT ;
    USE SIGNAL ;
    SHAPE ABUTMENT ;
    PORT
      LAYER M4 ;
      RECT 176.880 23.136 176.904 23.160 ;
    END
  END wd_in[500]
  PIN wd_in[501]
    DIRECTION INPUT ;
    USE SIGNAL ;
    SHAPE ABUTMENT ;
    PORT
      LAYER M4 ;
      RECT 176.880 23.232 176.904 23.256 ;
    END
  END wd_in[501]
  PIN wd_in[502]
    DIRECTION INPUT ;
    USE SIGNAL ;
    SHAPE ABUTMENT ;
    PORT
      LAYER M4 ;
      RECT 176.880 23.328 176.904 23.352 ;
    END
  END wd_in[502]
  PIN wd_in[503]
    DIRECTION INPUT ;
    USE SIGNAL ;
    SHAPE ABUTMENT ;
    PORT
      LAYER M4 ;
      RECT 176.880 23.424 176.904 23.448 ;
    END
  END wd_in[503]
  PIN wd_in[504]
    DIRECTION INPUT ;
    USE SIGNAL ;
    SHAPE ABUTMENT ;
    PORT
      LAYER M4 ;
      RECT 176.880 23.520 176.904 23.544 ;
    END
  END wd_in[504]
  PIN wd_in[505]
    DIRECTION INPUT ;
    USE SIGNAL ;
    SHAPE ABUTMENT ;
    PORT
      LAYER M4 ;
      RECT 176.880 23.616 176.904 23.640 ;
    END
  END wd_in[505]
  PIN wd_in[506]
    DIRECTION INPUT ;
    USE SIGNAL ;
    SHAPE ABUTMENT ;
    PORT
      LAYER M4 ;
      RECT 176.880 23.712 176.904 23.736 ;
    END
  END wd_in[506]
  PIN wd_in[507]
    DIRECTION INPUT ;
    USE SIGNAL ;
    SHAPE ABUTMENT ;
    PORT
      LAYER M4 ;
      RECT 176.880 23.808 176.904 23.832 ;
    END
  END wd_in[507]
  PIN wd_in[508]
    DIRECTION INPUT ;
    USE SIGNAL ;
    SHAPE ABUTMENT ;
    PORT
      LAYER M4 ;
      RECT 176.880 23.904 176.904 23.928 ;
    END
  END wd_in[508]
  PIN wd_in[509]
    DIRECTION INPUT ;
    USE SIGNAL ;
    SHAPE ABUTMENT ;
    PORT
      LAYER M4 ;
      RECT 176.880 24.000 176.904 24.024 ;
    END
  END wd_in[509]
  PIN wd_in[510]
    DIRECTION INPUT ;
    USE SIGNAL ;
    SHAPE ABUTMENT ;
    PORT
      LAYER M4 ;
      RECT 176.880 24.096 176.904 24.120 ;
    END
  END wd_in[510]
  PIN wd_in[511]
    DIRECTION INPUT ;
    USE SIGNAL ;
    SHAPE ABUTMENT ;
    PORT
      LAYER M4 ;
      RECT 176.880 24.192 176.904 24.216 ;
    END
  END wd_in[511]
  PIN wd_in[512]
    DIRECTION INPUT ;
    USE SIGNAL ;
    SHAPE ABUTMENT ;
    PORT
      LAYER M4 ;
      RECT 176.880 24.288 176.904 24.312 ;
    END
  END wd_in[512]
  PIN wd_in[513]
    DIRECTION INPUT ;
    USE SIGNAL ;
    SHAPE ABUTMENT ;
    PORT
      LAYER M4 ;
      RECT 176.880 24.384 176.904 24.408 ;
    END
  END wd_in[513]
  PIN wd_in[514]
    DIRECTION INPUT ;
    USE SIGNAL ;
    SHAPE ABUTMENT ;
    PORT
      LAYER M4 ;
      RECT 176.880 24.480 176.904 24.504 ;
    END
  END wd_in[514]
  PIN wd_in[515]
    DIRECTION INPUT ;
    USE SIGNAL ;
    SHAPE ABUTMENT ;
    PORT
      LAYER M4 ;
      RECT 176.880 24.576 176.904 24.600 ;
    END
  END wd_in[515]
  PIN wd_in[516]
    DIRECTION INPUT ;
    USE SIGNAL ;
    SHAPE ABUTMENT ;
    PORT
      LAYER M4 ;
      RECT 176.880 24.672 176.904 24.696 ;
    END
  END wd_in[516]
  PIN wd_in[517]
    DIRECTION INPUT ;
    USE SIGNAL ;
    SHAPE ABUTMENT ;
    PORT
      LAYER M4 ;
      RECT 176.880 24.768 176.904 24.792 ;
    END
  END wd_in[517]
  PIN wd_in[518]
    DIRECTION INPUT ;
    USE SIGNAL ;
    SHAPE ABUTMENT ;
    PORT
      LAYER M4 ;
      RECT 176.880 24.864 176.904 24.888 ;
    END
  END wd_in[518]
  PIN wd_in[519]
    DIRECTION INPUT ;
    USE SIGNAL ;
    SHAPE ABUTMENT ;
    PORT
      LAYER M4 ;
      RECT 176.880 24.960 176.904 24.984 ;
    END
  END wd_in[519]
  PIN wd_in[520]
    DIRECTION INPUT ;
    USE SIGNAL ;
    SHAPE ABUTMENT ;
    PORT
      LAYER M4 ;
      RECT 176.880 25.056 176.904 25.080 ;
    END
  END wd_in[520]
  PIN wd_in[521]
    DIRECTION INPUT ;
    USE SIGNAL ;
    SHAPE ABUTMENT ;
    PORT
      LAYER M4 ;
      RECT 176.880 25.152 176.904 25.176 ;
    END
  END wd_in[521]
  PIN wd_in[522]
    DIRECTION INPUT ;
    USE SIGNAL ;
    SHAPE ABUTMENT ;
    PORT
      LAYER M4 ;
      RECT 176.880 25.248 176.904 25.272 ;
    END
  END wd_in[522]
  PIN wd_in[523]
    DIRECTION INPUT ;
    USE SIGNAL ;
    SHAPE ABUTMENT ;
    PORT
      LAYER M4 ;
      RECT 176.880 25.344 176.904 25.368 ;
    END
  END wd_in[523]
  PIN wd_in[524]
    DIRECTION INPUT ;
    USE SIGNAL ;
    SHAPE ABUTMENT ;
    PORT
      LAYER M4 ;
      RECT 176.880 25.440 176.904 25.464 ;
    END
  END wd_in[524]
  PIN wd_in[525]
    DIRECTION INPUT ;
    USE SIGNAL ;
    SHAPE ABUTMENT ;
    PORT
      LAYER M4 ;
      RECT 176.880 25.536 176.904 25.560 ;
    END
  END wd_in[525]
  PIN wd_in[526]
    DIRECTION INPUT ;
    USE SIGNAL ;
    SHAPE ABUTMENT ;
    PORT
      LAYER M4 ;
      RECT 176.880 25.632 176.904 25.656 ;
    END
  END wd_in[526]
  PIN wd_in[527]
    DIRECTION INPUT ;
    USE SIGNAL ;
    SHAPE ABUTMENT ;
    PORT
      LAYER M4 ;
      RECT 176.880 25.728 176.904 25.752 ;
    END
  END wd_in[527]
  PIN wd_in[528]
    DIRECTION INPUT ;
    USE SIGNAL ;
    SHAPE ABUTMENT ;
    PORT
      LAYER M4 ;
      RECT 176.880 25.824 176.904 25.848 ;
    END
  END wd_in[528]
  PIN wd_in[529]
    DIRECTION INPUT ;
    USE SIGNAL ;
    SHAPE ABUTMENT ;
    PORT
      LAYER M4 ;
      RECT 176.880 25.920 176.904 25.944 ;
    END
  END wd_in[529]
  PIN wd_in[530]
    DIRECTION INPUT ;
    USE SIGNAL ;
    SHAPE ABUTMENT ;
    PORT
      LAYER M4 ;
      RECT 176.880 26.016 176.904 26.040 ;
    END
  END wd_in[530]
  PIN wd_in[531]
    DIRECTION INPUT ;
    USE SIGNAL ;
    SHAPE ABUTMENT ;
    PORT
      LAYER M4 ;
      RECT 176.880 26.112 176.904 26.136 ;
    END
  END wd_in[531]
  PIN wd_in[532]
    DIRECTION INPUT ;
    USE SIGNAL ;
    SHAPE ABUTMENT ;
    PORT
      LAYER M4 ;
      RECT 176.880 26.208 176.904 26.232 ;
    END
  END wd_in[532]
  PIN wd_in[533]
    DIRECTION INPUT ;
    USE SIGNAL ;
    SHAPE ABUTMENT ;
    PORT
      LAYER M4 ;
      RECT 176.880 26.304 176.904 26.328 ;
    END
  END wd_in[533]
  PIN wd_in[534]
    DIRECTION INPUT ;
    USE SIGNAL ;
    SHAPE ABUTMENT ;
    PORT
      LAYER M4 ;
      RECT 176.880 26.400 176.904 26.424 ;
    END
  END wd_in[534]
  PIN wd_in[535]
    DIRECTION INPUT ;
    USE SIGNAL ;
    SHAPE ABUTMENT ;
    PORT
      LAYER M4 ;
      RECT 176.880 26.496 176.904 26.520 ;
    END
  END wd_in[535]
  PIN wd_in[536]
    DIRECTION INPUT ;
    USE SIGNAL ;
    SHAPE ABUTMENT ;
    PORT
      LAYER M4 ;
      RECT 176.880 26.592 176.904 26.616 ;
    END
  END wd_in[536]
  PIN wd_in[537]
    DIRECTION INPUT ;
    USE SIGNAL ;
    SHAPE ABUTMENT ;
    PORT
      LAYER M4 ;
      RECT 176.880 26.688 176.904 26.712 ;
    END
  END wd_in[537]
  PIN wd_in[538]
    DIRECTION INPUT ;
    USE SIGNAL ;
    SHAPE ABUTMENT ;
    PORT
      LAYER M4 ;
      RECT 176.880 26.784 176.904 26.808 ;
    END
  END wd_in[538]
  PIN wd_in[539]
    DIRECTION INPUT ;
    USE SIGNAL ;
    SHAPE ABUTMENT ;
    PORT
      LAYER M4 ;
      RECT 176.880 26.880 176.904 26.904 ;
    END
  END wd_in[539]
  PIN wd_in[540]
    DIRECTION INPUT ;
    USE SIGNAL ;
    SHAPE ABUTMENT ;
    PORT
      LAYER M4 ;
      RECT 176.880 26.976 176.904 27.000 ;
    END
  END wd_in[540]
  PIN wd_in[541]
    DIRECTION INPUT ;
    USE SIGNAL ;
    SHAPE ABUTMENT ;
    PORT
      LAYER M4 ;
      RECT 176.880 27.072 176.904 27.096 ;
    END
  END wd_in[541]
  PIN wd_in[542]
    DIRECTION INPUT ;
    USE SIGNAL ;
    SHAPE ABUTMENT ;
    PORT
      LAYER M4 ;
      RECT 176.880 27.168 176.904 27.192 ;
    END
  END wd_in[542]
  PIN wd_in[543]
    DIRECTION INPUT ;
    USE SIGNAL ;
    SHAPE ABUTMENT ;
    PORT
      LAYER M4 ;
      RECT 176.880 27.264 176.904 27.288 ;
    END
  END wd_in[543]
  PIN wd_in[544]
    DIRECTION INPUT ;
    USE SIGNAL ;
    SHAPE ABUTMENT ;
    PORT
      LAYER M4 ;
      RECT 176.880 27.360 176.904 27.384 ;
    END
  END wd_in[544]
  PIN wd_in[545]
    DIRECTION INPUT ;
    USE SIGNAL ;
    SHAPE ABUTMENT ;
    PORT
      LAYER M4 ;
      RECT 176.880 27.456 176.904 27.480 ;
    END
  END wd_in[545]
  PIN w_mask_in[0]
    DIRECTION INPUT ;
    USE SIGNAL ;
    SHAPE ABUTMENT ;
    PORT
      LAYER M4 ;
      RECT 176.880 27.552 176.904 27.576 ;
    END
  END w_mask_in[0]
  PIN w_mask_in[1]
    DIRECTION INPUT ;
    USE SIGNAL ;
    SHAPE ABUTMENT ;
    PORT
      LAYER M4 ;
      RECT 176.880 27.648 176.904 27.672 ;
    END
  END w_mask_in[1]
  PIN w_mask_in[2]
    DIRECTION INPUT ;
    USE SIGNAL ;
    SHAPE ABUTMENT ;
    PORT
      LAYER M4 ;
      RECT 176.880 27.744 176.904 27.768 ;
    END
  END w_mask_in[2]
  PIN w_mask_in[3]
    DIRECTION INPUT ;
    USE SIGNAL ;
    SHAPE ABUTMENT ;
    PORT
      LAYER M4 ;
      RECT 176.880 27.840 176.904 27.864 ;
    END
  END w_mask_in[3]
  PIN w_mask_in[4]
    DIRECTION INPUT ;
    USE SIGNAL ;
    SHAPE ABUTMENT ;
    PORT
      LAYER M4 ;
      RECT 176.880 27.936 176.904 27.960 ;
    END
  END w_mask_in[4]
  PIN w_mask_in[5]
    DIRECTION INPUT ;
    USE SIGNAL ;
    SHAPE ABUTMENT ;
    PORT
      LAYER M4 ;
      RECT 176.880 28.032 176.904 28.056 ;
    END
  END w_mask_in[5]
  PIN w_mask_in[6]
    DIRECTION INPUT ;
    USE SIGNAL ;
    SHAPE ABUTMENT ;
    PORT
      LAYER M4 ;
      RECT 176.880 28.128 176.904 28.152 ;
    END
  END w_mask_in[6]
  PIN w_mask_in[7]
    DIRECTION INPUT ;
    USE SIGNAL ;
    SHAPE ABUTMENT ;
    PORT
      LAYER M4 ;
      RECT 176.880 28.224 176.904 28.248 ;
    END
  END w_mask_in[7]
  PIN w_mask_in[8]
    DIRECTION INPUT ;
    USE SIGNAL ;
    SHAPE ABUTMENT ;
    PORT
      LAYER M4 ;
      RECT 176.880 28.320 176.904 28.344 ;
    END
  END w_mask_in[8]
  PIN w_mask_in[9]
    DIRECTION INPUT ;
    USE SIGNAL ;
    SHAPE ABUTMENT ;
    PORT
      LAYER M4 ;
      RECT 176.880 28.416 176.904 28.440 ;
    END
  END w_mask_in[9]
  PIN w_mask_in[10]
    DIRECTION INPUT ;
    USE SIGNAL ;
    SHAPE ABUTMENT ;
    PORT
      LAYER M4 ;
      RECT 176.880 28.512 176.904 28.536 ;
    END
  END w_mask_in[10]
  PIN w_mask_in[11]
    DIRECTION INPUT ;
    USE SIGNAL ;
    SHAPE ABUTMENT ;
    PORT
      LAYER M4 ;
      RECT 176.880 28.608 176.904 28.632 ;
    END
  END w_mask_in[11]
  PIN w_mask_in[12]
    DIRECTION INPUT ;
    USE SIGNAL ;
    SHAPE ABUTMENT ;
    PORT
      LAYER M4 ;
      RECT 176.880 28.704 176.904 28.728 ;
    END
  END w_mask_in[12]
  PIN w_mask_in[13]
    DIRECTION INPUT ;
    USE SIGNAL ;
    SHAPE ABUTMENT ;
    PORT
      LAYER M4 ;
      RECT 176.880 28.800 176.904 28.824 ;
    END
  END w_mask_in[13]
  PIN w_mask_in[14]
    DIRECTION INPUT ;
    USE SIGNAL ;
    SHAPE ABUTMENT ;
    PORT
      LAYER M4 ;
      RECT 176.880 28.896 176.904 28.920 ;
    END
  END w_mask_in[14]
  PIN w_mask_in[15]
    DIRECTION INPUT ;
    USE SIGNAL ;
    SHAPE ABUTMENT ;
    PORT
      LAYER M4 ;
      RECT 176.880 28.992 176.904 29.016 ;
    END
  END w_mask_in[15]
  PIN w_mask_in[16]
    DIRECTION INPUT ;
    USE SIGNAL ;
    SHAPE ABUTMENT ;
    PORT
      LAYER M4 ;
      RECT 176.880 29.088 176.904 29.112 ;
    END
  END w_mask_in[16]
  PIN w_mask_in[17]
    DIRECTION INPUT ;
    USE SIGNAL ;
    SHAPE ABUTMENT ;
    PORT
      LAYER M4 ;
      RECT 176.880 29.184 176.904 29.208 ;
    END
  END w_mask_in[17]
  PIN w_mask_in[18]
    DIRECTION INPUT ;
    USE SIGNAL ;
    SHAPE ABUTMENT ;
    PORT
      LAYER M4 ;
      RECT 176.880 29.280 176.904 29.304 ;
    END
  END w_mask_in[18]
  PIN w_mask_in[19]
    DIRECTION INPUT ;
    USE SIGNAL ;
    SHAPE ABUTMENT ;
    PORT
      LAYER M4 ;
      RECT 176.880 29.376 176.904 29.400 ;
    END
  END w_mask_in[19]
  PIN w_mask_in[20]
    DIRECTION INPUT ;
    USE SIGNAL ;
    SHAPE ABUTMENT ;
    PORT
      LAYER M4 ;
      RECT 176.880 29.472 176.904 29.496 ;
    END
  END w_mask_in[20]
  PIN w_mask_in[21]
    DIRECTION INPUT ;
    USE SIGNAL ;
    SHAPE ABUTMENT ;
    PORT
      LAYER M4 ;
      RECT 176.880 29.568 176.904 29.592 ;
    END
  END w_mask_in[21]
  PIN w_mask_in[22]
    DIRECTION INPUT ;
    USE SIGNAL ;
    SHAPE ABUTMENT ;
    PORT
      LAYER M4 ;
      RECT 176.880 29.664 176.904 29.688 ;
    END
  END w_mask_in[22]
  PIN w_mask_in[23]
    DIRECTION INPUT ;
    USE SIGNAL ;
    SHAPE ABUTMENT ;
    PORT
      LAYER M4 ;
      RECT 176.880 29.760 176.904 29.784 ;
    END
  END w_mask_in[23]
  PIN w_mask_in[24]
    DIRECTION INPUT ;
    USE SIGNAL ;
    SHAPE ABUTMENT ;
    PORT
      LAYER M4 ;
      RECT 176.880 29.856 176.904 29.880 ;
    END
  END w_mask_in[24]
  PIN w_mask_in[25]
    DIRECTION INPUT ;
    USE SIGNAL ;
    SHAPE ABUTMENT ;
    PORT
      LAYER M4 ;
      RECT 176.880 29.952 176.904 29.976 ;
    END
  END w_mask_in[25]
  PIN w_mask_in[26]
    DIRECTION INPUT ;
    USE SIGNAL ;
    SHAPE ABUTMENT ;
    PORT
      LAYER M4 ;
      RECT 176.880 30.048 176.904 30.072 ;
    END
  END w_mask_in[26]
  PIN w_mask_in[27]
    DIRECTION INPUT ;
    USE SIGNAL ;
    SHAPE ABUTMENT ;
    PORT
      LAYER M4 ;
      RECT 176.880 30.144 176.904 30.168 ;
    END
  END w_mask_in[27]
  PIN w_mask_in[28]
    DIRECTION INPUT ;
    USE SIGNAL ;
    SHAPE ABUTMENT ;
    PORT
      LAYER M4 ;
      RECT 176.880 30.240 176.904 30.264 ;
    END
  END w_mask_in[28]
  PIN w_mask_in[29]
    DIRECTION INPUT ;
    USE SIGNAL ;
    SHAPE ABUTMENT ;
    PORT
      LAYER M4 ;
      RECT 176.880 30.336 176.904 30.360 ;
    END
  END w_mask_in[29]
  PIN w_mask_in[30]
    DIRECTION INPUT ;
    USE SIGNAL ;
    SHAPE ABUTMENT ;
    PORT
      LAYER M4 ;
      RECT 176.880 30.432 176.904 30.456 ;
    END
  END w_mask_in[30]
  PIN w_mask_in[31]
    DIRECTION INPUT ;
    USE SIGNAL ;
    SHAPE ABUTMENT ;
    PORT
      LAYER M4 ;
      RECT 176.880 30.528 176.904 30.552 ;
    END
  END w_mask_in[31]
  PIN w_mask_in[32]
    DIRECTION INPUT ;
    USE SIGNAL ;
    SHAPE ABUTMENT ;
    PORT
      LAYER M4 ;
      RECT 176.880 30.624 176.904 30.648 ;
    END
  END w_mask_in[32]
  PIN w_mask_in[33]
    DIRECTION INPUT ;
    USE SIGNAL ;
    SHAPE ABUTMENT ;
    PORT
      LAYER M4 ;
      RECT 176.880 30.720 176.904 30.744 ;
    END
  END w_mask_in[33]
  PIN w_mask_in[34]
    DIRECTION INPUT ;
    USE SIGNAL ;
    SHAPE ABUTMENT ;
    PORT
      LAYER M4 ;
      RECT 176.880 30.816 176.904 30.840 ;
    END
  END w_mask_in[34]
  PIN w_mask_in[35]
    DIRECTION INPUT ;
    USE SIGNAL ;
    SHAPE ABUTMENT ;
    PORT
      LAYER M4 ;
      RECT 176.880 30.912 176.904 30.936 ;
    END
  END w_mask_in[35]
  PIN w_mask_in[36]
    DIRECTION INPUT ;
    USE SIGNAL ;
    SHAPE ABUTMENT ;
    PORT
      LAYER M4 ;
      RECT 176.880 31.008 176.904 31.032 ;
    END
  END w_mask_in[36]
  PIN w_mask_in[37]
    DIRECTION INPUT ;
    USE SIGNAL ;
    SHAPE ABUTMENT ;
    PORT
      LAYER M4 ;
      RECT 176.880 31.104 176.904 31.128 ;
    END
  END w_mask_in[37]
  PIN w_mask_in[38]
    DIRECTION INPUT ;
    USE SIGNAL ;
    SHAPE ABUTMENT ;
    PORT
      LAYER M4 ;
      RECT 176.880 31.200 176.904 31.224 ;
    END
  END w_mask_in[38]
  PIN w_mask_in[39]
    DIRECTION INPUT ;
    USE SIGNAL ;
    SHAPE ABUTMENT ;
    PORT
      LAYER M4 ;
      RECT 176.880 31.296 176.904 31.320 ;
    END
  END w_mask_in[39]
  PIN w_mask_in[40]
    DIRECTION INPUT ;
    USE SIGNAL ;
    SHAPE ABUTMENT ;
    PORT
      LAYER M4 ;
      RECT 176.880 31.392 176.904 31.416 ;
    END
  END w_mask_in[40]
  PIN w_mask_in[41]
    DIRECTION INPUT ;
    USE SIGNAL ;
    SHAPE ABUTMENT ;
    PORT
      LAYER M4 ;
      RECT 176.880 31.488 176.904 31.512 ;
    END
  END w_mask_in[41]
  PIN w_mask_in[42]
    DIRECTION INPUT ;
    USE SIGNAL ;
    SHAPE ABUTMENT ;
    PORT
      LAYER M4 ;
      RECT 176.880 31.584 176.904 31.608 ;
    END
  END w_mask_in[42]
  PIN w_mask_in[43]
    DIRECTION INPUT ;
    USE SIGNAL ;
    SHAPE ABUTMENT ;
    PORT
      LAYER M4 ;
      RECT 176.880 31.680 176.904 31.704 ;
    END
  END w_mask_in[43]
  PIN w_mask_in[44]
    DIRECTION INPUT ;
    USE SIGNAL ;
    SHAPE ABUTMENT ;
    PORT
      LAYER M4 ;
      RECT 176.880 31.776 176.904 31.800 ;
    END
  END w_mask_in[44]
  PIN w_mask_in[45]
    DIRECTION INPUT ;
    USE SIGNAL ;
    SHAPE ABUTMENT ;
    PORT
      LAYER M4 ;
      RECT 176.880 31.872 176.904 31.896 ;
    END
  END w_mask_in[45]
  PIN w_mask_in[46]
    DIRECTION INPUT ;
    USE SIGNAL ;
    SHAPE ABUTMENT ;
    PORT
      LAYER M4 ;
      RECT 176.880 31.968 176.904 31.992 ;
    END
  END w_mask_in[46]
  PIN w_mask_in[47]
    DIRECTION INPUT ;
    USE SIGNAL ;
    SHAPE ABUTMENT ;
    PORT
      LAYER M4 ;
      RECT 176.880 32.064 176.904 32.088 ;
    END
  END w_mask_in[47]
  PIN w_mask_in[48]
    DIRECTION INPUT ;
    USE SIGNAL ;
    SHAPE ABUTMENT ;
    PORT
      LAYER M4 ;
      RECT 176.880 32.160 176.904 32.184 ;
    END
  END w_mask_in[48]
  PIN w_mask_in[49]
    DIRECTION INPUT ;
    USE SIGNAL ;
    SHAPE ABUTMENT ;
    PORT
      LAYER M4 ;
      RECT 176.880 32.256 176.904 32.280 ;
    END
  END w_mask_in[49]
  PIN w_mask_in[50]
    DIRECTION INPUT ;
    USE SIGNAL ;
    SHAPE ABUTMENT ;
    PORT
      LAYER M4 ;
      RECT 176.880 32.352 176.904 32.376 ;
    END
  END w_mask_in[50]
  PIN w_mask_in[51]
    DIRECTION INPUT ;
    USE SIGNAL ;
    SHAPE ABUTMENT ;
    PORT
      LAYER M4 ;
      RECT 176.880 32.448 176.904 32.472 ;
    END
  END w_mask_in[51]
  PIN w_mask_in[52]
    DIRECTION INPUT ;
    USE SIGNAL ;
    SHAPE ABUTMENT ;
    PORT
      LAYER M4 ;
      RECT 176.880 32.544 176.904 32.568 ;
    END
  END w_mask_in[52]
  PIN w_mask_in[53]
    DIRECTION INPUT ;
    USE SIGNAL ;
    SHAPE ABUTMENT ;
    PORT
      LAYER M4 ;
      RECT 176.880 32.640 176.904 32.664 ;
    END
  END w_mask_in[53]
  PIN w_mask_in[54]
    DIRECTION INPUT ;
    USE SIGNAL ;
    SHAPE ABUTMENT ;
    PORT
      LAYER M4 ;
      RECT 176.880 32.736 176.904 32.760 ;
    END
  END w_mask_in[54]
  PIN w_mask_in[55]
    DIRECTION INPUT ;
    USE SIGNAL ;
    SHAPE ABUTMENT ;
    PORT
      LAYER M4 ;
      RECT 176.880 32.832 176.904 32.856 ;
    END
  END w_mask_in[55]
  PIN w_mask_in[56]
    DIRECTION INPUT ;
    USE SIGNAL ;
    SHAPE ABUTMENT ;
    PORT
      LAYER M4 ;
      RECT 176.880 32.928 176.904 32.952 ;
    END
  END w_mask_in[56]
  PIN w_mask_in[57]
    DIRECTION INPUT ;
    USE SIGNAL ;
    SHAPE ABUTMENT ;
    PORT
      LAYER M4 ;
      RECT 176.880 33.024 176.904 33.048 ;
    END
  END w_mask_in[57]
  PIN w_mask_in[58]
    DIRECTION INPUT ;
    USE SIGNAL ;
    SHAPE ABUTMENT ;
    PORT
      LAYER M4 ;
      RECT 176.880 33.120 176.904 33.144 ;
    END
  END w_mask_in[58]
  PIN w_mask_in[59]
    DIRECTION INPUT ;
    USE SIGNAL ;
    SHAPE ABUTMENT ;
    PORT
      LAYER M4 ;
      RECT 176.880 33.216 176.904 33.240 ;
    END
  END w_mask_in[59]
  PIN w_mask_in[60]
    DIRECTION INPUT ;
    USE SIGNAL ;
    SHAPE ABUTMENT ;
    PORT
      LAYER M4 ;
      RECT 176.880 33.312 176.904 33.336 ;
    END
  END w_mask_in[60]
  PIN w_mask_in[61]
    DIRECTION INPUT ;
    USE SIGNAL ;
    SHAPE ABUTMENT ;
    PORT
      LAYER M4 ;
      RECT 176.880 33.408 176.904 33.432 ;
    END
  END w_mask_in[61]
  PIN w_mask_in[62]
    DIRECTION INPUT ;
    USE SIGNAL ;
    SHAPE ABUTMENT ;
    PORT
      LAYER M4 ;
      RECT 176.880 33.504 176.904 33.528 ;
    END
  END w_mask_in[62]
  PIN w_mask_in[63]
    DIRECTION INPUT ;
    USE SIGNAL ;
    SHAPE ABUTMENT ;
    PORT
      LAYER M4 ;
      RECT 176.880 33.600 176.904 33.624 ;
    END
  END w_mask_in[63]
  PIN w_mask_in[64]
    DIRECTION INPUT ;
    USE SIGNAL ;
    SHAPE ABUTMENT ;
    PORT
      LAYER M4 ;
      RECT 176.880 33.696 176.904 33.720 ;
    END
  END w_mask_in[64]
  PIN w_mask_in[65]
    DIRECTION INPUT ;
    USE SIGNAL ;
    SHAPE ABUTMENT ;
    PORT
      LAYER M4 ;
      RECT 176.880 33.792 176.904 33.816 ;
    END
  END w_mask_in[65]
  PIN w_mask_in[66]
    DIRECTION INPUT ;
    USE SIGNAL ;
    SHAPE ABUTMENT ;
    PORT
      LAYER M4 ;
      RECT 176.880 33.888 176.904 33.912 ;
    END
  END w_mask_in[66]
  PIN w_mask_in[67]
    DIRECTION INPUT ;
    USE SIGNAL ;
    SHAPE ABUTMENT ;
    PORT
      LAYER M4 ;
      RECT 176.880 33.984 176.904 34.008 ;
    END
  END w_mask_in[67]
  PIN w_mask_in[68]
    DIRECTION INPUT ;
    USE SIGNAL ;
    SHAPE ABUTMENT ;
    PORT
      LAYER M4 ;
      RECT 176.880 34.080 176.904 34.104 ;
    END
  END w_mask_in[68]
  PIN w_mask_in[69]
    DIRECTION INPUT ;
    USE SIGNAL ;
    SHAPE ABUTMENT ;
    PORT
      LAYER M4 ;
      RECT 176.880 34.176 176.904 34.200 ;
    END
  END w_mask_in[69]
  PIN w_mask_in[70]
    DIRECTION INPUT ;
    USE SIGNAL ;
    SHAPE ABUTMENT ;
    PORT
      LAYER M4 ;
      RECT 176.880 34.272 176.904 34.296 ;
    END
  END w_mask_in[70]
  PIN w_mask_in[71]
    DIRECTION INPUT ;
    USE SIGNAL ;
    SHAPE ABUTMENT ;
    PORT
      LAYER M4 ;
      RECT 176.880 34.368 176.904 34.392 ;
    END
  END w_mask_in[71]
  PIN w_mask_in[72]
    DIRECTION INPUT ;
    USE SIGNAL ;
    SHAPE ABUTMENT ;
    PORT
      LAYER M4 ;
      RECT 176.880 34.464 176.904 34.488 ;
    END
  END w_mask_in[72]
  PIN w_mask_in[73]
    DIRECTION INPUT ;
    USE SIGNAL ;
    SHAPE ABUTMENT ;
    PORT
      LAYER M4 ;
      RECT 176.880 34.560 176.904 34.584 ;
    END
  END w_mask_in[73]
  PIN w_mask_in[74]
    DIRECTION INPUT ;
    USE SIGNAL ;
    SHAPE ABUTMENT ;
    PORT
      LAYER M4 ;
      RECT 176.880 34.656 176.904 34.680 ;
    END
  END w_mask_in[74]
  PIN w_mask_in[75]
    DIRECTION INPUT ;
    USE SIGNAL ;
    SHAPE ABUTMENT ;
    PORT
      LAYER M4 ;
      RECT 176.880 34.752 176.904 34.776 ;
    END
  END w_mask_in[75]
  PIN w_mask_in[76]
    DIRECTION INPUT ;
    USE SIGNAL ;
    SHAPE ABUTMENT ;
    PORT
      LAYER M4 ;
      RECT 176.880 34.848 176.904 34.872 ;
    END
  END w_mask_in[76]
  PIN w_mask_in[77]
    DIRECTION INPUT ;
    USE SIGNAL ;
    SHAPE ABUTMENT ;
    PORT
      LAYER M4 ;
      RECT 176.880 34.944 176.904 34.968 ;
    END
  END w_mask_in[77]
  PIN w_mask_in[78]
    DIRECTION INPUT ;
    USE SIGNAL ;
    SHAPE ABUTMENT ;
    PORT
      LAYER M4 ;
      RECT 176.880 35.040 176.904 35.064 ;
    END
  END w_mask_in[78]
  PIN w_mask_in[79]
    DIRECTION INPUT ;
    USE SIGNAL ;
    SHAPE ABUTMENT ;
    PORT
      LAYER M4 ;
      RECT 176.880 35.136 176.904 35.160 ;
    END
  END w_mask_in[79]
  PIN w_mask_in[80]
    DIRECTION INPUT ;
    USE SIGNAL ;
    SHAPE ABUTMENT ;
    PORT
      LAYER M4 ;
      RECT 176.880 35.232 176.904 35.256 ;
    END
  END w_mask_in[80]
  PIN w_mask_in[81]
    DIRECTION INPUT ;
    USE SIGNAL ;
    SHAPE ABUTMENT ;
    PORT
      LAYER M4 ;
      RECT 176.880 35.328 176.904 35.352 ;
    END
  END w_mask_in[81]
  PIN w_mask_in[82]
    DIRECTION INPUT ;
    USE SIGNAL ;
    SHAPE ABUTMENT ;
    PORT
      LAYER M4 ;
      RECT 176.880 35.424 176.904 35.448 ;
    END
  END w_mask_in[82]
  PIN w_mask_in[83]
    DIRECTION INPUT ;
    USE SIGNAL ;
    SHAPE ABUTMENT ;
    PORT
      LAYER M4 ;
      RECT 176.880 35.520 176.904 35.544 ;
    END
  END w_mask_in[83]
  PIN w_mask_in[84]
    DIRECTION INPUT ;
    USE SIGNAL ;
    SHAPE ABUTMENT ;
    PORT
      LAYER M4 ;
      RECT 176.880 35.616 176.904 35.640 ;
    END
  END w_mask_in[84]
  PIN w_mask_in[85]
    DIRECTION INPUT ;
    USE SIGNAL ;
    SHAPE ABUTMENT ;
    PORT
      LAYER M4 ;
      RECT 176.880 35.712 176.904 35.736 ;
    END
  END w_mask_in[85]
  PIN w_mask_in[86]
    DIRECTION INPUT ;
    USE SIGNAL ;
    SHAPE ABUTMENT ;
    PORT
      LAYER M4 ;
      RECT 176.880 35.808 176.904 35.832 ;
    END
  END w_mask_in[86]
  PIN w_mask_in[87]
    DIRECTION INPUT ;
    USE SIGNAL ;
    SHAPE ABUTMENT ;
    PORT
      LAYER M4 ;
      RECT 176.880 35.904 176.904 35.928 ;
    END
  END w_mask_in[87]
  PIN w_mask_in[88]
    DIRECTION INPUT ;
    USE SIGNAL ;
    SHAPE ABUTMENT ;
    PORT
      LAYER M4 ;
      RECT 176.880 36.000 176.904 36.024 ;
    END
  END w_mask_in[88]
  PIN w_mask_in[89]
    DIRECTION INPUT ;
    USE SIGNAL ;
    SHAPE ABUTMENT ;
    PORT
      LAYER M4 ;
      RECT 176.880 36.096 176.904 36.120 ;
    END
  END w_mask_in[89]
  PIN w_mask_in[90]
    DIRECTION INPUT ;
    USE SIGNAL ;
    SHAPE ABUTMENT ;
    PORT
      LAYER M4 ;
      RECT 176.880 36.192 176.904 36.216 ;
    END
  END w_mask_in[90]
  PIN w_mask_in[91]
    DIRECTION INPUT ;
    USE SIGNAL ;
    SHAPE ABUTMENT ;
    PORT
      LAYER M4 ;
      RECT 176.880 36.288 176.904 36.312 ;
    END
  END w_mask_in[91]
  PIN w_mask_in[92]
    DIRECTION INPUT ;
    USE SIGNAL ;
    SHAPE ABUTMENT ;
    PORT
      LAYER M4 ;
      RECT 176.880 36.384 176.904 36.408 ;
    END
  END w_mask_in[92]
  PIN w_mask_in[93]
    DIRECTION INPUT ;
    USE SIGNAL ;
    SHAPE ABUTMENT ;
    PORT
      LAYER M4 ;
      RECT 176.880 36.480 176.904 36.504 ;
    END
  END w_mask_in[93]
  PIN w_mask_in[94]
    DIRECTION INPUT ;
    USE SIGNAL ;
    SHAPE ABUTMENT ;
    PORT
      LAYER M4 ;
      RECT 176.880 36.576 176.904 36.600 ;
    END
  END w_mask_in[94]
  PIN w_mask_in[95]
    DIRECTION INPUT ;
    USE SIGNAL ;
    SHAPE ABUTMENT ;
    PORT
      LAYER M4 ;
      RECT 176.880 36.672 176.904 36.696 ;
    END
  END w_mask_in[95]
  PIN w_mask_in[96]
    DIRECTION INPUT ;
    USE SIGNAL ;
    SHAPE ABUTMENT ;
    PORT
      LAYER M4 ;
      RECT 176.880 36.768 176.904 36.792 ;
    END
  END w_mask_in[96]
  PIN w_mask_in[97]
    DIRECTION INPUT ;
    USE SIGNAL ;
    SHAPE ABUTMENT ;
    PORT
      LAYER M4 ;
      RECT 176.880 36.864 176.904 36.888 ;
    END
  END w_mask_in[97]
  PIN w_mask_in[98]
    DIRECTION INPUT ;
    USE SIGNAL ;
    SHAPE ABUTMENT ;
    PORT
      LAYER M4 ;
      RECT 176.880 36.960 176.904 36.984 ;
    END
  END w_mask_in[98]
  PIN w_mask_in[99]
    DIRECTION INPUT ;
    USE SIGNAL ;
    SHAPE ABUTMENT ;
    PORT
      LAYER M4 ;
      RECT 176.880 37.056 176.904 37.080 ;
    END
  END w_mask_in[99]
  PIN w_mask_in[100]
    DIRECTION INPUT ;
    USE SIGNAL ;
    SHAPE ABUTMENT ;
    PORT
      LAYER M4 ;
      RECT 176.880 37.152 176.904 37.176 ;
    END
  END w_mask_in[100]
  PIN w_mask_in[101]
    DIRECTION INPUT ;
    USE SIGNAL ;
    SHAPE ABUTMENT ;
    PORT
      LAYER M4 ;
      RECT 176.880 37.248 176.904 37.272 ;
    END
  END w_mask_in[101]
  PIN w_mask_in[102]
    DIRECTION INPUT ;
    USE SIGNAL ;
    SHAPE ABUTMENT ;
    PORT
      LAYER M4 ;
      RECT 176.880 37.344 176.904 37.368 ;
    END
  END w_mask_in[102]
  PIN w_mask_in[103]
    DIRECTION INPUT ;
    USE SIGNAL ;
    SHAPE ABUTMENT ;
    PORT
      LAYER M4 ;
      RECT 176.880 37.440 176.904 37.464 ;
    END
  END w_mask_in[103]
  PIN w_mask_in[104]
    DIRECTION INPUT ;
    USE SIGNAL ;
    SHAPE ABUTMENT ;
    PORT
      LAYER M4 ;
      RECT 176.880 37.536 176.904 37.560 ;
    END
  END w_mask_in[104]
  PIN w_mask_in[105]
    DIRECTION INPUT ;
    USE SIGNAL ;
    SHAPE ABUTMENT ;
    PORT
      LAYER M4 ;
      RECT 176.880 37.632 176.904 37.656 ;
    END
  END w_mask_in[105]
  PIN w_mask_in[106]
    DIRECTION INPUT ;
    USE SIGNAL ;
    SHAPE ABUTMENT ;
    PORT
      LAYER M4 ;
      RECT 176.880 37.728 176.904 37.752 ;
    END
  END w_mask_in[106]
  PIN w_mask_in[107]
    DIRECTION INPUT ;
    USE SIGNAL ;
    SHAPE ABUTMENT ;
    PORT
      LAYER M4 ;
      RECT 176.880 37.824 176.904 37.848 ;
    END
  END w_mask_in[107]
  PIN w_mask_in[108]
    DIRECTION INPUT ;
    USE SIGNAL ;
    SHAPE ABUTMENT ;
    PORT
      LAYER M4 ;
      RECT 176.880 37.920 176.904 37.944 ;
    END
  END w_mask_in[108]
  PIN w_mask_in[109]
    DIRECTION INPUT ;
    USE SIGNAL ;
    SHAPE ABUTMENT ;
    PORT
      LAYER M4 ;
      RECT 176.880 38.016 176.904 38.040 ;
    END
  END w_mask_in[109]
  PIN w_mask_in[110]
    DIRECTION INPUT ;
    USE SIGNAL ;
    SHAPE ABUTMENT ;
    PORT
      LAYER M4 ;
      RECT 176.880 38.112 176.904 38.136 ;
    END
  END w_mask_in[110]
  PIN w_mask_in[111]
    DIRECTION INPUT ;
    USE SIGNAL ;
    SHAPE ABUTMENT ;
    PORT
      LAYER M4 ;
      RECT 176.880 38.208 176.904 38.232 ;
    END
  END w_mask_in[111]
  PIN w_mask_in[112]
    DIRECTION INPUT ;
    USE SIGNAL ;
    SHAPE ABUTMENT ;
    PORT
      LAYER M4 ;
      RECT 176.880 38.304 176.904 38.328 ;
    END
  END w_mask_in[112]
  PIN w_mask_in[113]
    DIRECTION INPUT ;
    USE SIGNAL ;
    SHAPE ABUTMENT ;
    PORT
      LAYER M4 ;
      RECT 176.880 38.400 176.904 38.424 ;
    END
  END w_mask_in[113]
  PIN w_mask_in[114]
    DIRECTION INPUT ;
    USE SIGNAL ;
    SHAPE ABUTMENT ;
    PORT
      LAYER M4 ;
      RECT 176.880 38.496 176.904 38.520 ;
    END
  END w_mask_in[114]
  PIN w_mask_in[115]
    DIRECTION INPUT ;
    USE SIGNAL ;
    SHAPE ABUTMENT ;
    PORT
      LAYER M4 ;
      RECT 176.880 38.592 176.904 38.616 ;
    END
  END w_mask_in[115]
  PIN w_mask_in[116]
    DIRECTION INPUT ;
    USE SIGNAL ;
    SHAPE ABUTMENT ;
    PORT
      LAYER M4 ;
      RECT 176.880 38.688 176.904 38.712 ;
    END
  END w_mask_in[116]
  PIN w_mask_in[117]
    DIRECTION INPUT ;
    USE SIGNAL ;
    SHAPE ABUTMENT ;
    PORT
      LAYER M4 ;
      RECT 176.880 38.784 176.904 38.808 ;
    END
  END w_mask_in[117]
  PIN w_mask_in[118]
    DIRECTION INPUT ;
    USE SIGNAL ;
    SHAPE ABUTMENT ;
    PORT
      LAYER M4 ;
      RECT 176.880 38.880 176.904 38.904 ;
    END
  END w_mask_in[118]
  PIN w_mask_in[119]
    DIRECTION INPUT ;
    USE SIGNAL ;
    SHAPE ABUTMENT ;
    PORT
      LAYER M4 ;
      RECT 176.880 38.976 176.904 39.000 ;
    END
  END w_mask_in[119]
  PIN w_mask_in[120]
    DIRECTION INPUT ;
    USE SIGNAL ;
    SHAPE ABUTMENT ;
    PORT
      LAYER M4 ;
      RECT 176.880 39.072 176.904 39.096 ;
    END
  END w_mask_in[120]
  PIN w_mask_in[121]
    DIRECTION INPUT ;
    USE SIGNAL ;
    SHAPE ABUTMENT ;
    PORT
      LAYER M4 ;
      RECT 176.880 39.168 176.904 39.192 ;
    END
  END w_mask_in[121]
  PIN w_mask_in[122]
    DIRECTION INPUT ;
    USE SIGNAL ;
    SHAPE ABUTMENT ;
    PORT
      LAYER M4 ;
      RECT 176.880 39.264 176.904 39.288 ;
    END
  END w_mask_in[122]
  PIN w_mask_in[123]
    DIRECTION INPUT ;
    USE SIGNAL ;
    SHAPE ABUTMENT ;
    PORT
      LAYER M4 ;
      RECT 176.880 39.360 176.904 39.384 ;
    END
  END w_mask_in[123]
  PIN w_mask_in[124]
    DIRECTION INPUT ;
    USE SIGNAL ;
    SHAPE ABUTMENT ;
    PORT
      LAYER M4 ;
      RECT 176.880 39.456 176.904 39.480 ;
    END
  END w_mask_in[124]
  PIN w_mask_in[125]
    DIRECTION INPUT ;
    USE SIGNAL ;
    SHAPE ABUTMENT ;
    PORT
      LAYER M4 ;
      RECT 176.880 39.552 176.904 39.576 ;
    END
  END w_mask_in[125]
  PIN w_mask_in[126]
    DIRECTION INPUT ;
    USE SIGNAL ;
    SHAPE ABUTMENT ;
    PORT
      LAYER M4 ;
      RECT 176.880 39.648 176.904 39.672 ;
    END
  END w_mask_in[126]
  PIN w_mask_in[127]
    DIRECTION INPUT ;
    USE SIGNAL ;
    SHAPE ABUTMENT ;
    PORT
      LAYER M4 ;
      RECT 176.880 39.744 176.904 39.768 ;
    END
  END w_mask_in[127]
  PIN w_mask_in[128]
    DIRECTION INPUT ;
    USE SIGNAL ;
    SHAPE ABUTMENT ;
    PORT
      LAYER M4 ;
      RECT 176.880 39.840 176.904 39.864 ;
    END
  END w_mask_in[128]
  PIN w_mask_in[129]
    DIRECTION INPUT ;
    USE SIGNAL ;
    SHAPE ABUTMENT ;
    PORT
      LAYER M4 ;
      RECT 176.880 39.936 176.904 39.960 ;
    END
  END w_mask_in[129]
  PIN w_mask_in[130]
    DIRECTION INPUT ;
    USE SIGNAL ;
    SHAPE ABUTMENT ;
    PORT
      LAYER M4 ;
      RECT 176.880 40.032 176.904 40.056 ;
    END
  END w_mask_in[130]
  PIN w_mask_in[131]
    DIRECTION INPUT ;
    USE SIGNAL ;
    SHAPE ABUTMENT ;
    PORT
      LAYER M4 ;
      RECT 176.880 40.128 176.904 40.152 ;
    END
  END w_mask_in[131]
  PIN w_mask_in[132]
    DIRECTION INPUT ;
    USE SIGNAL ;
    SHAPE ABUTMENT ;
    PORT
      LAYER M4 ;
      RECT 176.880 40.224 176.904 40.248 ;
    END
  END w_mask_in[132]
  PIN w_mask_in[133]
    DIRECTION INPUT ;
    USE SIGNAL ;
    SHAPE ABUTMENT ;
    PORT
      LAYER M4 ;
      RECT 176.880 40.320 176.904 40.344 ;
    END
  END w_mask_in[133]
  PIN w_mask_in[134]
    DIRECTION INPUT ;
    USE SIGNAL ;
    SHAPE ABUTMENT ;
    PORT
      LAYER M4 ;
      RECT 176.880 40.416 176.904 40.440 ;
    END
  END w_mask_in[134]
  PIN w_mask_in[135]
    DIRECTION INPUT ;
    USE SIGNAL ;
    SHAPE ABUTMENT ;
    PORT
      LAYER M4 ;
      RECT 176.880 40.512 176.904 40.536 ;
    END
  END w_mask_in[135]
  PIN w_mask_in[136]
    DIRECTION INPUT ;
    USE SIGNAL ;
    SHAPE ABUTMENT ;
    PORT
      LAYER M4 ;
      RECT 176.880 40.608 176.904 40.632 ;
    END
  END w_mask_in[136]
  PIN w_mask_in[137]
    DIRECTION INPUT ;
    USE SIGNAL ;
    SHAPE ABUTMENT ;
    PORT
      LAYER M4 ;
      RECT 176.880 40.704 176.904 40.728 ;
    END
  END w_mask_in[137]
  PIN w_mask_in[138]
    DIRECTION INPUT ;
    USE SIGNAL ;
    SHAPE ABUTMENT ;
    PORT
      LAYER M4 ;
      RECT 176.880 40.800 176.904 40.824 ;
    END
  END w_mask_in[138]
  PIN w_mask_in[139]
    DIRECTION INPUT ;
    USE SIGNAL ;
    SHAPE ABUTMENT ;
    PORT
      LAYER M4 ;
      RECT 176.880 40.896 176.904 40.920 ;
    END
  END w_mask_in[139]
  PIN w_mask_in[140]
    DIRECTION INPUT ;
    USE SIGNAL ;
    SHAPE ABUTMENT ;
    PORT
      LAYER M4 ;
      RECT 176.880 40.992 176.904 41.016 ;
    END
  END w_mask_in[140]
  PIN w_mask_in[141]
    DIRECTION INPUT ;
    USE SIGNAL ;
    SHAPE ABUTMENT ;
    PORT
      LAYER M4 ;
      RECT 176.880 41.088 176.904 41.112 ;
    END
  END w_mask_in[141]
  PIN w_mask_in[142]
    DIRECTION INPUT ;
    USE SIGNAL ;
    SHAPE ABUTMENT ;
    PORT
      LAYER M4 ;
      RECT 176.880 41.184 176.904 41.208 ;
    END
  END w_mask_in[142]
  PIN w_mask_in[143]
    DIRECTION INPUT ;
    USE SIGNAL ;
    SHAPE ABUTMENT ;
    PORT
      LAYER M4 ;
      RECT 176.880 41.280 176.904 41.304 ;
    END
  END w_mask_in[143]
  PIN w_mask_in[144]
    DIRECTION INPUT ;
    USE SIGNAL ;
    SHAPE ABUTMENT ;
    PORT
      LAYER M4 ;
      RECT 176.880 41.376 176.904 41.400 ;
    END
  END w_mask_in[144]
  PIN w_mask_in[145]
    DIRECTION INPUT ;
    USE SIGNAL ;
    SHAPE ABUTMENT ;
    PORT
      LAYER M4 ;
      RECT 176.880 41.472 176.904 41.496 ;
    END
  END w_mask_in[145]
  PIN w_mask_in[146]
    DIRECTION INPUT ;
    USE SIGNAL ;
    SHAPE ABUTMENT ;
    PORT
      LAYER M4 ;
      RECT 176.880 41.568 176.904 41.592 ;
    END
  END w_mask_in[146]
  PIN w_mask_in[147]
    DIRECTION INPUT ;
    USE SIGNAL ;
    SHAPE ABUTMENT ;
    PORT
      LAYER M4 ;
      RECT 176.880 41.664 176.904 41.688 ;
    END
  END w_mask_in[147]
  PIN w_mask_in[148]
    DIRECTION INPUT ;
    USE SIGNAL ;
    SHAPE ABUTMENT ;
    PORT
      LAYER M4 ;
      RECT 176.880 41.760 176.904 41.784 ;
    END
  END w_mask_in[148]
  PIN w_mask_in[149]
    DIRECTION INPUT ;
    USE SIGNAL ;
    SHAPE ABUTMENT ;
    PORT
      LAYER M4 ;
      RECT 176.880 41.856 176.904 41.880 ;
    END
  END w_mask_in[149]
  PIN w_mask_in[150]
    DIRECTION INPUT ;
    USE SIGNAL ;
    SHAPE ABUTMENT ;
    PORT
      LAYER M4 ;
      RECT 176.880 41.952 176.904 41.976 ;
    END
  END w_mask_in[150]
  PIN w_mask_in[151]
    DIRECTION INPUT ;
    USE SIGNAL ;
    SHAPE ABUTMENT ;
    PORT
      LAYER M4 ;
      RECT 176.880 42.048 176.904 42.072 ;
    END
  END w_mask_in[151]
  PIN w_mask_in[152]
    DIRECTION INPUT ;
    USE SIGNAL ;
    SHAPE ABUTMENT ;
    PORT
      LAYER M4 ;
      RECT 176.880 42.144 176.904 42.168 ;
    END
  END w_mask_in[152]
  PIN w_mask_in[153]
    DIRECTION INPUT ;
    USE SIGNAL ;
    SHAPE ABUTMENT ;
    PORT
      LAYER M4 ;
      RECT 176.880 42.240 176.904 42.264 ;
    END
  END w_mask_in[153]
  PIN w_mask_in[154]
    DIRECTION INPUT ;
    USE SIGNAL ;
    SHAPE ABUTMENT ;
    PORT
      LAYER M4 ;
      RECT 176.880 42.336 176.904 42.360 ;
    END
  END w_mask_in[154]
  PIN w_mask_in[155]
    DIRECTION INPUT ;
    USE SIGNAL ;
    SHAPE ABUTMENT ;
    PORT
      LAYER M4 ;
      RECT 176.880 42.432 176.904 42.456 ;
    END
  END w_mask_in[155]
  PIN w_mask_in[156]
    DIRECTION INPUT ;
    USE SIGNAL ;
    SHAPE ABUTMENT ;
    PORT
      LAYER M4 ;
      RECT 176.880 42.528 176.904 42.552 ;
    END
  END w_mask_in[156]
  PIN w_mask_in[157]
    DIRECTION INPUT ;
    USE SIGNAL ;
    SHAPE ABUTMENT ;
    PORT
      LAYER M4 ;
      RECT 176.880 42.624 176.904 42.648 ;
    END
  END w_mask_in[157]
  PIN w_mask_in[158]
    DIRECTION INPUT ;
    USE SIGNAL ;
    SHAPE ABUTMENT ;
    PORT
      LAYER M4 ;
      RECT 176.880 42.720 176.904 42.744 ;
    END
  END w_mask_in[158]
  PIN w_mask_in[159]
    DIRECTION INPUT ;
    USE SIGNAL ;
    SHAPE ABUTMENT ;
    PORT
      LAYER M4 ;
      RECT 176.880 42.816 176.904 42.840 ;
    END
  END w_mask_in[159]
  PIN w_mask_in[160]
    DIRECTION INPUT ;
    USE SIGNAL ;
    SHAPE ABUTMENT ;
    PORT
      LAYER M4 ;
      RECT 176.880 42.912 176.904 42.936 ;
    END
  END w_mask_in[160]
  PIN w_mask_in[161]
    DIRECTION INPUT ;
    USE SIGNAL ;
    SHAPE ABUTMENT ;
    PORT
      LAYER M4 ;
      RECT 176.880 43.008 176.904 43.032 ;
    END
  END w_mask_in[161]
  PIN w_mask_in[162]
    DIRECTION INPUT ;
    USE SIGNAL ;
    SHAPE ABUTMENT ;
    PORT
      LAYER M4 ;
      RECT 176.880 43.104 176.904 43.128 ;
    END
  END w_mask_in[162]
  PIN w_mask_in[163]
    DIRECTION INPUT ;
    USE SIGNAL ;
    SHAPE ABUTMENT ;
    PORT
      LAYER M4 ;
      RECT 176.880 43.200 176.904 43.224 ;
    END
  END w_mask_in[163]
  PIN w_mask_in[164]
    DIRECTION INPUT ;
    USE SIGNAL ;
    SHAPE ABUTMENT ;
    PORT
      LAYER M4 ;
      RECT 176.880 43.296 176.904 43.320 ;
    END
  END w_mask_in[164]
  PIN w_mask_in[165]
    DIRECTION INPUT ;
    USE SIGNAL ;
    SHAPE ABUTMENT ;
    PORT
      LAYER M4 ;
      RECT 176.880 43.392 176.904 43.416 ;
    END
  END w_mask_in[165]
  PIN w_mask_in[166]
    DIRECTION INPUT ;
    USE SIGNAL ;
    SHAPE ABUTMENT ;
    PORT
      LAYER M4 ;
      RECT 176.880 43.488 176.904 43.512 ;
    END
  END w_mask_in[166]
  PIN w_mask_in[167]
    DIRECTION INPUT ;
    USE SIGNAL ;
    SHAPE ABUTMENT ;
    PORT
      LAYER M4 ;
      RECT 176.880 43.584 176.904 43.608 ;
    END
  END w_mask_in[167]
  PIN w_mask_in[168]
    DIRECTION INPUT ;
    USE SIGNAL ;
    SHAPE ABUTMENT ;
    PORT
      LAYER M4 ;
      RECT 176.880 43.680 176.904 43.704 ;
    END
  END w_mask_in[168]
  PIN w_mask_in[169]
    DIRECTION INPUT ;
    USE SIGNAL ;
    SHAPE ABUTMENT ;
    PORT
      LAYER M4 ;
      RECT 176.880 43.776 176.904 43.800 ;
    END
  END w_mask_in[169]
  PIN w_mask_in[170]
    DIRECTION INPUT ;
    USE SIGNAL ;
    SHAPE ABUTMENT ;
    PORT
      LAYER M4 ;
      RECT 176.880 43.872 176.904 43.896 ;
    END
  END w_mask_in[170]
  PIN w_mask_in[171]
    DIRECTION INPUT ;
    USE SIGNAL ;
    SHAPE ABUTMENT ;
    PORT
      LAYER M4 ;
      RECT 176.880 43.968 176.904 43.992 ;
    END
  END w_mask_in[171]
  PIN w_mask_in[172]
    DIRECTION INPUT ;
    USE SIGNAL ;
    SHAPE ABUTMENT ;
    PORT
      LAYER M4 ;
      RECT 176.880 44.064 176.904 44.088 ;
    END
  END w_mask_in[172]
  PIN w_mask_in[173]
    DIRECTION INPUT ;
    USE SIGNAL ;
    SHAPE ABUTMENT ;
    PORT
      LAYER M4 ;
      RECT 176.880 44.160 176.904 44.184 ;
    END
  END w_mask_in[173]
  PIN w_mask_in[174]
    DIRECTION INPUT ;
    USE SIGNAL ;
    SHAPE ABUTMENT ;
    PORT
      LAYER M4 ;
      RECT 176.880 44.256 176.904 44.280 ;
    END
  END w_mask_in[174]
  PIN w_mask_in[175]
    DIRECTION INPUT ;
    USE SIGNAL ;
    SHAPE ABUTMENT ;
    PORT
      LAYER M4 ;
      RECT 176.880 44.352 176.904 44.376 ;
    END
  END w_mask_in[175]
  PIN w_mask_in[176]
    DIRECTION INPUT ;
    USE SIGNAL ;
    SHAPE ABUTMENT ;
    PORT
      LAYER M4 ;
      RECT 176.880 44.448 176.904 44.472 ;
    END
  END w_mask_in[176]
  PIN w_mask_in[177]
    DIRECTION INPUT ;
    USE SIGNAL ;
    SHAPE ABUTMENT ;
    PORT
      LAYER M4 ;
      RECT 176.880 44.544 176.904 44.568 ;
    END
  END w_mask_in[177]
  PIN w_mask_in[178]
    DIRECTION INPUT ;
    USE SIGNAL ;
    SHAPE ABUTMENT ;
    PORT
      LAYER M4 ;
      RECT 176.880 44.640 176.904 44.664 ;
    END
  END w_mask_in[178]
  PIN w_mask_in[179]
    DIRECTION INPUT ;
    USE SIGNAL ;
    SHAPE ABUTMENT ;
    PORT
      LAYER M4 ;
      RECT 176.880 44.736 176.904 44.760 ;
    END
  END w_mask_in[179]
  PIN w_mask_in[180]
    DIRECTION INPUT ;
    USE SIGNAL ;
    SHAPE ABUTMENT ;
    PORT
      LAYER M4 ;
      RECT 176.880 44.832 176.904 44.856 ;
    END
  END w_mask_in[180]
  PIN w_mask_in[181]
    DIRECTION INPUT ;
    USE SIGNAL ;
    SHAPE ABUTMENT ;
    PORT
      LAYER M4 ;
      RECT 176.880 44.928 176.904 44.952 ;
    END
  END w_mask_in[181]
  PIN w_mask_in[182]
    DIRECTION INPUT ;
    USE SIGNAL ;
    SHAPE ABUTMENT ;
    PORT
      LAYER M4 ;
      RECT 176.880 45.024 176.904 45.048 ;
    END
  END w_mask_in[182]
  PIN w_mask_in[183]
    DIRECTION INPUT ;
    USE SIGNAL ;
    SHAPE ABUTMENT ;
    PORT
      LAYER M4 ;
      RECT 176.880 45.120 176.904 45.144 ;
    END
  END w_mask_in[183]
  PIN w_mask_in[184]
    DIRECTION INPUT ;
    USE SIGNAL ;
    SHAPE ABUTMENT ;
    PORT
      LAYER M4 ;
      RECT 176.880 45.216 176.904 45.240 ;
    END
  END w_mask_in[184]
  PIN w_mask_in[185]
    DIRECTION INPUT ;
    USE SIGNAL ;
    SHAPE ABUTMENT ;
    PORT
      LAYER M4 ;
      RECT 176.880 45.312 176.904 45.336 ;
    END
  END w_mask_in[185]
  PIN w_mask_in[186]
    DIRECTION INPUT ;
    USE SIGNAL ;
    SHAPE ABUTMENT ;
    PORT
      LAYER M4 ;
      RECT 176.880 45.408 176.904 45.432 ;
    END
  END w_mask_in[186]
  PIN w_mask_in[187]
    DIRECTION INPUT ;
    USE SIGNAL ;
    SHAPE ABUTMENT ;
    PORT
      LAYER M4 ;
      RECT 176.880 45.504 176.904 45.528 ;
    END
  END w_mask_in[187]
  PIN w_mask_in[188]
    DIRECTION INPUT ;
    USE SIGNAL ;
    SHAPE ABUTMENT ;
    PORT
      LAYER M4 ;
      RECT 176.880 45.600 176.904 45.624 ;
    END
  END w_mask_in[188]
  PIN w_mask_in[189]
    DIRECTION INPUT ;
    USE SIGNAL ;
    SHAPE ABUTMENT ;
    PORT
      LAYER M4 ;
      RECT 176.880 45.696 176.904 45.720 ;
    END
  END w_mask_in[189]
  PIN w_mask_in[190]
    DIRECTION INPUT ;
    USE SIGNAL ;
    SHAPE ABUTMENT ;
    PORT
      LAYER M4 ;
      RECT 176.880 45.792 176.904 45.816 ;
    END
  END w_mask_in[190]
  PIN w_mask_in[191]
    DIRECTION INPUT ;
    USE SIGNAL ;
    SHAPE ABUTMENT ;
    PORT
      LAYER M4 ;
      RECT 176.880 45.888 176.904 45.912 ;
    END
  END w_mask_in[191]
  PIN w_mask_in[192]
    DIRECTION INPUT ;
    USE SIGNAL ;
    SHAPE ABUTMENT ;
    PORT
      LAYER M4 ;
      RECT 176.880 45.984 176.904 46.008 ;
    END
  END w_mask_in[192]
  PIN w_mask_in[193]
    DIRECTION INPUT ;
    USE SIGNAL ;
    SHAPE ABUTMENT ;
    PORT
      LAYER M4 ;
      RECT 176.880 46.080 176.904 46.104 ;
    END
  END w_mask_in[193]
  PIN w_mask_in[194]
    DIRECTION INPUT ;
    USE SIGNAL ;
    SHAPE ABUTMENT ;
    PORT
      LAYER M4 ;
      RECT 176.880 46.176 176.904 46.200 ;
    END
  END w_mask_in[194]
  PIN w_mask_in[195]
    DIRECTION INPUT ;
    USE SIGNAL ;
    SHAPE ABUTMENT ;
    PORT
      LAYER M4 ;
      RECT 176.880 46.272 176.904 46.296 ;
    END
  END w_mask_in[195]
  PIN w_mask_in[196]
    DIRECTION INPUT ;
    USE SIGNAL ;
    SHAPE ABUTMENT ;
    PORT
      LAYER M4 ;
      RECT 176.880 46.368 176.904 46.392 ;
    END
  END w_mask_in[196]
  PIN w_mask_in[197]
    DIRECTION INPUT ;
    USE SIGNAL ;
    SHAPE ABUTMENT ;
    PORT
      LAYER M4 ;
      RECT 176.880 46.464 176.904 46.488 ;
    END
  END w_mask_in[197]
  PIN w_mask_in[198]
    DIRECTION INPUT ;
    USE SIGNAL ;
    SHAPE ABUTMENT ;
    PORT
      LAYER M4 ;
      RECT 176.880 46.560 176.904 46.584 ;
    END
  END w_mask_in[198]
  PIN w_mask_in[199]
    DIRECTION INPUT ;
    USE SIGNAL ;
    SHAPE ABUTMENT ;
    PORT
      LAYER M4 ;
      RECT 176.880 46.656 176.904 46.680 ;
    END
  END w_mask_in[199]
  PIN w_mask_in[200]
    DIRECTION INPUT ;
    USE SIGNAL ;
    SHAPE ABUTMENT ;
    PORT
      LAYER M4 ;
      RECT 176.880 46.752 176.904 46.776 ;
    END
  END w_mask_in[200]
  PIN w_mask_in[201]
    DIRECTION INPUT ;
    USE SIGNAL ;
    SHAPE ABUTMENT ;
    PORT
      LAYER M4 ;
      RECT 176.880 46.848 176.904 46.872 ;
    END
  END w_mask_in[201]
  PIN w_mask_in[202]
    DIRECTION INPUT ;
    USE SIGNAL ;
    SHAPE ABUTMENT ;
    PORT
      LAYER M4 ;
      RECT 176.880 46.944 176.904 46.968 ;
    END
  END w_mask_in[202]
  PIN w_mask_in[203]
    DIRECTION INPUT ;
    USE SIGNAL ;
    SHAPE ABUTMENT ;
    PORT
      LAYER M4 ;
      RECT 176.880 47.040 176.904 47.064 ;
    END
  END w_mask_in[203]
  PIN w_mask_in[204]
    DIRECTION INPUT ;
    USE SIGNAL ;
    SHAPE ABUTMENT ;
    PORT
      LAYER M4 ;
      RECT 176.880 47.136 176.904 47.160 ;
    END
  END w_mask_in[204]
  PIN w_mask_in[205]
    DIRECTION INPUT ;
    USE SIGNAL ;
    SHAPE ABUTMENT ;
    PORT
      LAYER M4 ;
      RECT 176.880 47.232 176.904 47.256 ;
    END
  END w_mask_in[205]
  PIN w_mask_in[206]
    DIRECTION INPUT ;
    USE SIGNAL ;
    SHAPE ABUTMENT ;
    PORT
      LAYER M4 ;
      RECT 176.880 47.328 176.904 47.352 ;
    END
  END w_mask_in[206]
  PIN w_mask_in[207]
    DIRECTION INPUT ;
    USE SIGNAL ;
    SHAPE ABUTMENT ;
    PORT
      LAYER M4 ;
      RECT 176.880 47.424 176.904 47.448 ;
    END
  END w_mask_in[207]
  PIN w_mask_in[208]
    DIRECTION INPUT ;
    USE SIGNAL ;
    SHAPE ABUTMENT ;
    PORT
      LAYER M4 ;
      RECT 176.880 47.520 176.904 47.544 ;
    END
  END w_mask_in[208]
  PIN w_mask_in[209]
    DIRECTION INPUT ;
    USE SIGNAL ;
    SHAPE ABUTMENT ;
    PORT
      LAYER M4 ;
      RECT 176.880 47.616 176.904 47.640 ;
    END
  END w_mask_in[209]
  PIN w_mask_in[210]
    DIRECTION INPUT ;
    USE SIGNAL ;
    SHAPE ABUTMENT ;
    PORT
      LAYER M4 ;
      RECT 176.880 47.712 176.904 47.736 ;
    END
  END w_mask_in[210]
  PIN w_mask_in[211]
    DIRECTION INPUT ;
    USE SIGNAL ;
    SHAPE ABUTMENT ;
    PORT
      LAYER M4 ;
      RECT 176.880 47.808 176.904 47.832 ;
    END
  END w_mask_in[211]
  PIN w_mask_in[212]
    DIRECTION INPUT ;
    USE SIGNAL ;
    SHAPE ABUTMENT ;
    PORT
      LAYER M4 ;
      RECT 176.880 47.904 176.904 47.928 ;
    END
  END w_mask_in[212]
  PIN w_mask_in[213]
    DIRECTION INPUT ;
    USE SIGNAL ;
    SHAPE ABUTMENT ;
    PORT
      LAYER M4 ;
      RECT 176.880 48.000 176.904 48.024 ;
    END
  END w_mask_in[213]
  PIN w_mask_in[214]
    DIRECTION INPUT ;
    USE SIGNAL ;
    SHAPE ABUTMENT ;
    PORT
      LAYER M4 ;
      RECT 176.880 48.096 176.904 48.120 ;
    END
  END w_mask_in[214]
  PIN w_mask_in[215]
    DIRECTION INPUT ;
    USE SIGNAL ;
    SHAPE ABUTMENT ;
    PORT
      LAYER M4 ;
      RECT 176.880 48.192 176.904 48.216 ;
    END
  END w_mask_in[215]
  PIN w_mask_in[216]
    DIRECTION INPUT ;
    USE SIGNAL ;
    SHAPE ABUTMENT ;
    PORT
      LAYER M4 ;
      RECT 176.880 48.288 176.904 48.312 ;
    END
  END w_mask_in[216]
  PIN w_mask_in[217]
    DIRECTION INPUT ;
    USE SIGNAL ;
    SHAPE ABUTMENT ;
    PORT
      LAYER M4 ;
      RECT 176.880 48.384 176.904 48.408 ;
    END
  END w_mask_in[217]
  PIN w_mask_in[218]
    DIRECTION INPUT ;
    USE SIGNAL ;
    SHAPE ABUTMENT ;
    PORT
      LAYER M4 ;
      RECT 176.880 48.480 176.904 48.504 ;
    END
  END w_mask_in[218]
  PIN w_mask_in[219]
    DIRECTION INPUT ;
    USE SIGNAL ;
    SHAPE ABUTMENT ;
    PORT
      LAYER M4 ;
      RECT 176.880 48.576 176.904 48.600 ;
    END
  END w_mask_in[219]
  PIN w_mask_in[220]
    DIRECTION INPUT ;
    USE SIGNAL ;
    SHAPE ABUTMENT ;
    PORT
      LAYER M4 ;
      RECT 176.880 48.672 176.904 48.696 ;
    END
  END w_mask_in[220]
  PIN w_mask_in[221]
    DIRECTION INPUT ;
    USE SIGNAL ;
    SHAPE ABUTMENT ;
    PORT
      LAYER M4 ;
      RECT 176.880 48.768 176.904 48.792 ;
    END
  END w_mask_in[221]
  PIN w_mask_in[222]
    DIRECTION INPUT ;
    USE SIGNAL ;
    SHAPE ABUTMENT ;
    PORT
      LAYER M4 ;
      RECT 176.880 48.864 176.904 48.888 ;
    END
  END w_mask_in[222]
  PIN w_mask_in[223]
    DIRECTION INPUT ;
    USE SIGNAL ;
    SHAPE ABUTMENT ;
    PORT
      LAYER M4 ;
      RECT 176.880 48.960 176.904 48.984 ;
    END
  END w_mask_in[223]
  PIN w_mask_in[224]
    DIRECTION INPUT ;
    USE SIGNAL ;
    SHAPE ABUTMENT ;
    PORT
      LAYER M4 ;
      RECT 176.880 49.056 176.904 49.080 ;
    END
  END w_mask_in[224]
  PIN w_mask_in[225]
    DIRECTION INPUT ;
    USE SIGNAL ;
    SHAPE ABUTMENT ;
    PORT
      LAYER M4 ;
      RECT 176.880 49.152 176.904 49.176 ;
    END
  END w_mask_in[225]
  PIN w_mask_in[226]
    DIRECTION INPUT ;
    USE SIGNAL ;
    SHAPE ABUTMENT ;
    PORT
      LAYER M4 ;
      RECT 176.880 49.248 176.904 49.272 ;
    END
  END w_mask_in[226]
  PIN w_mask_in[227]
    DIRECTION INPUT ;
    USE SIGNAL ;
    SHAPE ABUTMENT ;
    PORT
      LAYER M4 ;
      RECT 176.880 49.344 176.904 49.368 ;
    END
  END w_mask_in[227]
  PIN w_mask_in[228]
    DIRECTION INPUT ;
    USE SIGNAL ;
    SHAPE ABUTMENT ;
    PORT
      LAYER M4 ;
      RECT 176.880 49.440 176.904 49.464 ;
    END
  END w_mask_in[228]
  PIN w_mask_in[229]
    DIRECTION INPUT ;
    USE SIGNAL ;
    SHAPE ABUTMENT ;
    PORT
      LAYER M4 ;
      RECT 176.880 49.536 176.904 49.560 ;
    END
  END w_mask_in[229]
  PIN w_mask_in[230]
    DIRECTION INPUT ;
    USE SIGNAL ;
    SHAPE ABUTMENT ;
    PORT
      LAYER M4 ;
      RECT 176.880 49.632 176.904 49.656 ;
    END
  END w_mask_in[230]
  PIN w_mask_in[231]
    DIRECTION INPUT ;
    USE SIGNAL ;
    SHAPE ABUTMENT ;
    PORT
      LAYER M4 ;
      RECT 176.880 49.728 176.904 49.752 ;
    END
  END w_mask_in[231]
  PIN w_mask_in[232]
    DIRECTION INPUT ;
    USE SIGNAL ;
    SHAPE ABUTMENT ;
    PORT
      LAYER M4 ;
      RECT 176.880 49.824 176.904 49.848 ;
    END
  END w_mask_in[232]
  PIN w_mask_in[233]
    DIRECTION INPUT ;
    USE SIGNAL ;
    SHAPE ABUTMENT ;
    PORT
      LAYER M4 ;
      RECT 176.880 49.920 176.904 49.944 ;
    END
  END w_mask_in[233]
  PIN w_mask_in[234]
    DIRECTION INPUT ;
    USE SIGNAL ;
    SHAPE ABUTMENT ;
    PORT
      LAYER M4 ;
      RECT 176.880 50.016 176.904 50.040 ;
    END
  END w_mask_in[234]
  PIN w_mask_in[235]
    DIRECTION INPUT ;
    USE SIGNAL ;
    SHAPE ABUTMENT ;
    PORT
      LAYER M4 ;
      RECT 176.880 50.112 176.904 50.136 ;
    END
  END w_mask_in[235]
  PIN w_mask_in[236]
    DIRECTION INPUT ;
    USE SIGNAL ;
    SHAPE ABUTMENT ;
    PORT
      LAYER M4 ;
      RECT 176.880 50.208 176.904 50.232 ;
    END
  END w_mask_in[236]
  PIN w_mask_in[237]
    DIRECTION INPUT ;
    USE SIGNAL ;
    SHAPE ABUTMENT ;
    PORT
      LAYER M4 ;
      RECT 176.880 50.304 176.904 50.328 ;
    END
  END w_mask_in[237]
  PIN w_mask_in[238]
    DIRECTION INPUT ;
    USE SIGNAL ;
    SHAPE ABUTMENT ;
    PORT
      LAYER M4 ;
      RECT 176.880 50.400 176.904 50.424 ;
    END
  END w_mask_in[238]
  PIN w_mask_in[239]
    DIRECTION INPUT ;
    USE SIGNAL ;
    SHAPE ABUTMENT ;
    PORT
      LAYER M4 ;
      RECT 176.880 50.496 176.904 50.520 ;
    END
  END w_mask_in[239]
  PIN w_mask_in[240]
    DIRECTION INPUT ;
    USE SIGNAL ;
    SHAPE ABUTMENT ;
    PORT
      LAYER M4 ;
      RECT 176.880 50.592 176.904 50.616 ;
    END
  END w_mask_in[240]
  PIN w_mask_in[241]
    DIRECTION INPUT ;
    USE SIGNAL ;
    SHAPE ABUTMENT ;
    PORT
      LAYER M4 ;
      RECT 176.880 50.688 176.904 50.712 ;
    END
  END w_mask_in[241]
  PIN w_mask_in[242]
    DIRECTION INPUT ;
    USE SIGNAL ;
    SHAPE ABUTMENT ;
    PORT
      LAYER M4 ;
      RECT 176.880 50.784 176.904 50.808 ;
    END
  END w_mask_in[242]
  PIN w_mask_in[243]
    DIRECTION INPUT ;
    USE SIGNAL ;
    SHAPE ABUTMENT ;
    PORT
      LAYER M4 ;
      RECT 176.880 50.880 176.904 50.904 ;
    END
  END w_mask_in[243]
  PIN w_mask_in[244]
    DIRECTION INPUT ;
    USE SIGNAL ;
    SHAPE ABUTMENT ;
    PORT
      LAYER M4 ;
      RECT 176.880 50.976 176.904 51.000 ;
    END
  END w_mask_in[244]
  PIN w_mask_in[245]
    DIRECTION INPUT ;
    USE SIGNAL ;
    SHAPE ABUTMENT ;
    PORT
      LAYER M4 ;
      RECT 176.880 51.072 176.904 51.096 ;
    END
  END w_mask_in[245]
  PIN w_mask_in[246]
    DIRECTION INPUT ;
    USE SIGNAL ;
    SHAPE ABUTMENT ;
    PORT
      LAYER M4 ;
      RECT 176.880 51.168 176.904 51.192 ;
    END
  END w_mask_in[246]
  PIN w_mask_in[247]
    DIRECTION INPUT ;
    USE SIGNAL ;
    SHAPE ABUTMENT ;
    PORT
      LAYER M4 ;
      RECT 176.880 51.264 176.904 51.288 ;
    END
  END w_mask_in[247]
  PIN w_mask_in[248]
    DIRECTION INPUT ;
    USE SIGNAL ;
    SHAPE ABUTMENT ;
    PORT
      LAYER M4 ;
      RECT 176.880 51.360 176.904 51.384 ;
    END
  END w_mask_in[248]
  PIN w_mask_in[249]
    DIRECTION INPUT ;
    USE SIGNAL ;
    SHAPE ABUTMENT ;
    PORT
      LAYER M4 ;
      RECT 176.880 51.456 176.904 51.480 ;
    END
  END w_mask_in[249]
  PIN w_mask_in[250]
    DIRECTION INPUT ;
    USE SIGNAL ;
    SHAPE ABUTMENT ;
    PORT
      LAYER M4 ;
      RECT 176.880 51.552 176.904 51.576 ;
    END
  END w_mask_in[250]
  PIN w_mask_in[251]
    DIRECTION INPUT ;
    USE SIGNAL ;
    SHAPE ABUTMENT ;
    PORT
      LAYER M4 ;
      RECT 176.880 51.648 176.904 51.672 ;
    END
  END w_mask_in[251]
  PIN w_mask_in[252]
    DIRECTION INPUT ;
    USE SIGNAL ;
    SHAPE ABUTMENT ;
    PORT
      LAYER M4 ;
      RECT 176.880 51.744 176.904 51.768 ;
    END
  END w_mask_in[252]
  PIN w_mask_in[253]
    DIRECTION INPUT ;
    USE SIGNAL ;
    SHAPE ABUTMENT ;
    PORT
      LAYER M4 ;
      RECT 176.880 51.840 176.904 51.864 ;
    END
  END w_mask_in[253]
  PIN w_mask_in[254]
    DIRECTION INPUT ;
    USE SIGNAL ;
    SHAPE ABUTMENT ;
    PORT
      LAYER M4 ;
      RECT 176.880 51.936 176.904 51.960 ;
    END
  END w_mask_in[254]
  PIN w_mask_in[255]
    DIRECTION INPUT ;
    USE SIGNAL ;
    SHAPE ABUTMENT ;
    PORT
      LAYER M4 ;
      RECT 176.880 52.032 176.904 52.056 ;
    END
  END w_mask_in[255]
  PIN w_mask_in[256]
    DIRECTION INPUT ;
    USE SIGNAL ;
    SHAPE ABUTMENT ;
    PORT
      LAYER M4 ;
      RECT 176.880 52.128 176.904 52.152 ;
    END
  END w_mask_in[256]
  PIN w_mask_in[257]
    DIRECTION INPUT ;
    USE SIGNAL ;
    SHAPE ABUTMENT ;
    PORT
      LAYER M4 ;
      RECT 176.880 52.224 176.904 52.248 ;
    END
  END w_mask_in[257]
  PIN w_mask_in[258]
    DIRECTION INPUT ;
    USE SIGNAL ;
    SHAPE ABUTMENT ;
    PORT
      LAYER M4 ;
      RECT 176.880 52.320 176.904 52.344 ;
    END
  END w_mask_in[258]
  PIN w_mask_in[259]
    DIRECTION INPUT ;
    USE SIGNAL ;
    SHAPE ABUTMENT ;
    PORT
      LAYER M4 ;
      RECT 176.880 52.416 176.904 52.440 ;
    END
  END w_mask_in[259]
  PIN w_mask_in[260]
    DIRECTION INPUT ;
    USE SIGNAL ;
    SHAPE ABUTMENT ;
    PORT
      LAYER M4 ;
      RECT 176.880 52.512 176.904 52.536 ;
    END
  END w_mask_in[260]
  PIN w_mask_in[261]
    DIRECTION INPUT ;
    USE SIGNAL ;
    SHAPE ABUTMENT ;
    PORT
      LAYER M4 ;
      RECT 176.880 52.608 176.904 52.632 ;
    END
  END w_mask_in[261]
  PIN w_mask_in[262]
    DIRECTION INPUT ;
    USE SIGNAL ;
    SHAPE ABUTMENT ;
    PORT
      LAYER M4 ;
      RECT 176.880 52.704 176.904 52.728 ;
    END
  END w_mask_in[262]
  PIN w_mask_in[263]
    DIRECTION INPUT ;
    USE SIGNAL ;
    SHAPE ABUTMENT ;
    PORT
      LAYER M4 ;
      RECT 176.880 52.800 176.904 52.824 ;
    END
  END w_mask_in[263]
  PIN w_mask_in[264]
    DIRECTION INPUT ;
    USE SIGNAL ;
    SHAPE ABUTMENT ;
    PORT
      LAYER M4 ;
      RECT 176.880 52.896 176.904 52.920 ;
    END
  END w_mask_in[264]
  PIN w_mask_in[265]
    DIRECTION INPUT ;
    USE SIGNAL ;
    SHAPE ABUTMENT ;
    PORT
      LAYER M4 ;
      RECT 176.880 52.992 176.904 53.016 ;
    END
  END w_mask_in[265]
  PIN w_mask_in[266]
    DIRECTION INPUT ;
    USE SIGNAL ;
    SHAPE ABUTMENT ;
    PORT
      LAYER M4 ;
      RECT 176.880 53.088 176.904 53.112 ;
    END
  END w_mask_in[266]
  PIN w_mask_in[267]
    DIRECTION INPUT ;
    USE SIGNAL ;
    SHAPE ABUTMENT ;
    PORT
      LAYER M4 ;
      RECT 176.880 53.184 176.904 53.208 ;
    END
  END w_mask_in[267]
  PIN w_mask_in[268]
    DIRECTION INPUT ;
    USE SIGNAL ;
    SHAPE ABUTMENT ;
    PORT
      LAYER M4 ;
      RECT 176.880 53.280 176.904 53.304 ;
    END
  END w_mask_in[268]
  PIN w_mask_in[269]
    DIRECTION INPUT ;
    USE SIGNAL ;
    SHAPE ABUTMENT ;
    PORT
      LAYER M4 ;
      RECT 176.880 53.376 176.904 53.400 ;
    END
  END w_mask_in[269]
  PIN w_mask_in[270]
    DIRECTION INPUT ;
    USE SIGNAL ;
    SHAPE ABUTMENT ;
    PORT
      LAYER M4 ;
      RECT 176.880 53.472 176.904 53.496 ;
    END
  END w_mask_in[270]
  PIN w_mask_in[271]
    DIRECTION INPUT ;
    USE SIGNAL ;
    SHAPE ABUTMENT ;
    PORT
      LAYER M4 ;
      RECT 176.880 53.568 176.904 53.592 ;
    END
  END w_mask_in[271]
  PIN w_mask_in[272]
    DIRECTION INPUT ;
    USE SIGNAL ;
    SHAPE ABUTMENT ;
    PORT
      LAYER M4 ;
      RECT 176.880 53.664 176.904 53.688 ;
    END
  END w_mask_in[272]
  PIN w_mask_in[273]
    DIRECTION INPUT ;
    USE SIGNAL ;
    SHAPE ABUTMENT ;
    PORT
      LAYER M4 ;
      RECT 176.880 53.760 176.904 53.784 ;
    END
  END w_mask_in[273]
  PIN w_mask_in[274]
    DIRECTION INPUT ;
    USE SIGNAL ;
    SHAPE ABUTMENT ;
    PORT
      LAYER M4 ;
      RECT 176.880 53.856 176.904 53.880 ;
    END
  END w_mask_in[274]
  PIN w_mask_in[275]
    DIRECTION INPUT ;
    USE SIGNAL ;
    SHAPE ABUTMENT ;
    PORT
      LAYER M4 ;
      RECT 176.880 53.952 176.904 53.976 ;
    END
  END w_mask_in[275]
  PIN w_mask_in[276]
    DIRECTION INPUT ;
    USE SIGNAL ;
    SHAPE ABUTMENT ;
    PORT
      LAYER M4 ;
      RECT 176.880 54.048 176.904 54.072 ;
    END
  END w_mask_in[276]
  PIN w_mask_in[277]
    DIRECTION INPUT ;
    USE SIGNAL ;
    SHAPE ABUTMENT ;
    PORT
      LAYER M4 ;
      RECT 176.880 54.144 176.904 54.168 ;
    END
  END w_mask_in[277]
  PIN w_mask_in[278]
    DIRECTION INPUT ;
    USE SIGNAL ;
    SHAPE ABUTMENT ;
    PORT
      LAYER M4 ;
      RECT 176.880 54.240 176.904 54.264 ;
    END
  END w_mask_in[278]
  PIN w_mask_in[279]
    DIRECTION INPUT ;
    USE SIGNAL ;
    SHAPE ABUTMENT ;
    PORT
      LAYER M4 ;
      RECT 176.880 54.336 176.904 54.360 ;
    END
  END w_mask_in[279]
  PIN w_mask_in[280]
    DIRECTION INPUT ;
    USE SIGNAL ;
    SHAPE ABUTMENT ;
    PORT
      LAYER M4 ;
      RECT 176.880 54.432 176.904 54.456 ;
    END
  END w_mask_in[280]
  PIN w_mask_in[281]
    DIRECTION INPUT ;
    USE SIGNAL ;
    SHAPE ABUTMENT ;
    PORT
      LAYER M4 ;
      RECT 176.880 54.528 176.904 54.552 ;
    END
  END w_mask_in[281]
  PIN w_mask_in[282]
    DIRECTION INPUT ;
    USE SIGNAL ;
    SHAPE ABUTMENT ;
    PORT
      LAYER M4 ;
      RECT 176.880 54.624 176.904 54.648 ;
    END
  END w_mask_in[282]
  PIN w_mask_in[283]
    DIRECTION INPUT ;
    USE SIGNAL ;
    SHAPE ABUTMENT ;
    PORT
      LAYER M4 ;
      RECT 176.880 54.720 176.904 54.744 ;
    END
  END w_mask_in[283]
  PIN w_mask_in[284]
    DIRECTION INPUT ;
    USE SIGNAL ;
    SHAPE ABUTMENT ;
    PORT
      LAYER M4 ;
      RECT 176.880 54.816 176.904 54.840 ;
    END
  END w_mask_in[284]
  PIN w_mask_in[285]
    DIRECTION INPUT ;
    USE SIGNAL ;
    SHAPE ABUTMENT ;
    PORT
      LAYER M4 ;
      RECT 176.880 54.912 176.904 54.936 ;
    END
  END w_mask_in[285]
  PIN w_mask_in[286]
    DIRECTION INPUT ;
    USE SIGNAL ;
    SHAPE ABUTMENT ;
    PORT
      LAYER M4 ;
      RECT 176.880 55.008 176.904 55.032 ;
    END
  END w_mask_in[286]
  PIN w_mask_in[287]
    DIRECTION INPUT ;
    USE SIGNAL ;
    SHAPE ABUTMENT ;
    PORT
      LAYER M4 ;
      RECT 176.880 55.104 176.904 55.128 ;
    END
  END w_mask_in[287]
  PIN w_mask_in[288]
    DIRECTION INPUT ;
    USE SIGNAL ;
    SHAPE ABUTMENT ;
    PORT
      LAYER M4 ;
      RECT 176.880 55.200 176.904 55.224 ;
    END
  END w_mask_in[288]
  PIN w_mask_in[289]
    DIRECTION INPUT ;
    USE SIGNAL ;
    SHAPE ABUTMENT ;
    PORT
      LAYER M4 ;
      RECT 176.880 55.296 176.904 55.320 ;
    END
  END w_mask_in[289]
  PIN w_mask_in[290]
    DIRECTION INPUT ;
    USE SIGNAL ;
    SHAPE ABUTMENT ;
    PORT
      LAYER M4 ;
      RECT 176.880 55.392 176.904 55.416 ;
    END
  END w_mask_in[290]
  PIN w_mask_in[291]
    DIRECTION INPUT ;
    USE SIGNAL ;
    SHAPE ABUTMENT ;
    PORT
      LAYER M4 ;
      RECT 176.880 55.488 176.904 55.512 ;
    END
  END w_mask_in[291]
  PIN w_mask_in[292]
    DIRECTION INPUT ;
    USE SIGNAL ;
    SHAPE ABUTMENT ;
    PORT
      LAYER M4 ;
      RECT 176.880 55.584 176.904 55.608 ;
    END
  END w_mask_in[292]
  PIN w_mask_in[293]
    DIRECTION INPUT ;
    USE SIGNAL ;
    SHAPE ABUTMENT ;
    PORT
      LAYER M4 ;
      RECT 176.880 55.680 176.904 55.704 ;
    END
  END w_mask_in[293]
  PIN w_mask_in[294]
    DIRECTION INPUT ;
    USE SIGNAL ;
    SHAPE ABUTMENT ;
    PORT
      LAYER M4 ;
      RECT 176.880 55.776 176.904 55.800 ;
    END
  END w_mask_in[294]
  PIN w_mask_in[295]
    DIRECTION INPUT ;
    USE SIGNAL ;
    SHAPE ABUTMENT ;
    PORT
      LAYER M4 ;
      RECT 176.880 55.872 176.904 55.896 ;
    END
  END w_mask_in[295]
  PIN w_mask_in[296]
    DIRECTION INPUT ;
    USE SIGNAL ;
    SHAPE ABUTMENT ;
    PORT
      LAYER M4 ;
      RECT 176.880 55.968 176.904 55.992 ;
    END
  END w_mask_in[296]
  PIN w_mask_in[297]
    DIRECTION INPUT ;
    USE SIGNAL ;
    SHAPE ABUTMENT ;
    PORT
      LAYER M4 ;
      RECT 176.880 56.064 176.904 56.088 ;
    END
  END w_mask_in[297]
  PIN w_mask_in[298]
    DIRECTION INPUT ;
    USE SIGNAL ;
    SHAPE ABUTMENT ;
    PORT
      LAYER M4 ;
      RECT 176.880 56.160 176.904 56.184 ;
    END
  END w_mask_in[298]
  PIN w_mask_in[299]
    DIRECTION INPUT ;
    USE SIGNAL ;
    SHAPE ABUTMENT ;
    PORT
      LAYER M4 ;
      RECT 176.880 56.256 176.904 56.280 ;
    END
  END w_mask_in[299]
  PIN w_mask_in[300]
    DIRECTION INPUT ;
    USE SIGNAL ;
    SHAPE ABUTMENT ;
    PORT
      LAYER M4 ;
      RECT 176.880 56.352 176.904 56.376 ;
    END
  END w_mask_in[300]
  PIN w_mask_in[301]
    DIRECTION INPUT ;
    USE SIGNAL ;
    SHAPE ABUTMENT ;
    PORT
      LAYER M4 ;
      RECT 176.880 56.448 176.904 56.472 ;
    END
  END w_mask_in[301]
  PIN w_mask_in[302]
    DIRECTION INPUT ;
    USE SIGNAL ;
    SHAPE ABUTMENT ;
    PORT
      LAYER M4 ;
      RECT 176.880 56.544 176.904 56.568 ;
    END
  END w_mask_in[302]
  PIN w_mask_in[303]
    DIRECTION INPUT ;
    USE SIGNAL ;
    SHAPE ABUTMENT ;
    PORT
      LAYER M4 ;
      RECT 176.880 56.640 176.904 56.664 ;
    END
  END w_mask_in[303]
  PIN w_mask_in[304]
    DIRECTION INPUT ;
    USE SIGNAL ;
    SHAPE ABUTMENT ;
    PORT
      LAYER M4 ;
      RECT 176.880 56.736 176.904 56.760 ;
    END
  END w_mask_in[304]
  PIN w_mask_in[305]
    DIRECTION INPUT ;
    USE SIGNAL ;
    SHAPE ABUTMENT ;
    PORT
      LAYER M4 ;
      RECT 176.880 56.832 176.904 56.856 ;
    END
  END w_mask_in[305]
  PIN w_mask_in[306]
    DIRECTION INPUT ;
    USE SIGNAL ;
    SHAPE ABUTMENT ;
    PORT
      LAYER M4 ;
      RECT 176.880 56.928 176.904 56.952 ;
    END
  END w_mask_in[306]
  PIN w_mask_in[307]
    DIRECTION INPUT ;
    USE SIGNAL ;
    SHAPE ABUTMENT ;
    PORT
      LAYER M4 ;
      RECT 176.880 57.024 176.904 57.048 ;
    END
  END w_mask_in[307]
  PIN w_mask_in[308]
    DIRECTION INPUT ;
    USE SIGNAL ;
    SHAPE ABUTMENT ;
    PORT
      LAYER M4 ;
      RECT 176.880 57.120 176.904 57.144 ;
    END
  END w_mask_in[308]
  PIN w_mask_in[309]
    DIRECTION INPUT ;
    USE SIGNAL ;
    SHAPE ABUTMENT ;
    PORT
      LAYER M4 ;
      RECT 176.880 57.216 176.904 57.240 ;
    END
  END w_mask_in[309]
  PIN w_mask_in[310]
    DIRECTION INPUT ;
    USE SIGNAL ;
    SHAPE ABUTMENT ;
    PORT
      LAYER M4 ;
      RECT 176.880 57.312 176.904 57.336 ;
    END
  END w_mask_in[310]
  PIN w_mask_in[311]
    DIRECTION INPUT ;
    USE SIGNAL ;
    SHAPE ABUTMENT ;
    PORT
      LAYER M4 ;
      RECT 176.880 57.408 176.904 57.432 ;
    END
  END w_mask_in[311]
  PIN w_mask_in[312]
    DIRECTION INPUT ;
    USE SIGNAL ;
    SHAPE ABUTMENT ;
    PORT
      LAYER M4 ;
      RECT 176.880 57.504 176.904 57.528 ;
    END
  END w_mask_in[312]
  PIN w_mask_in[313]
    DIRECTION INPUT ;
    USE SIGNAL ;
    SHAPE ABUTMENT ;
    PORT
      LAYER M4 ;
      RECT 176.880 57.600 176.904 57.624 ;
    END
  END w_mask_in[313]
  PIN w_mask_in[314]
    DIRECTION INPUT ;
    USE SIGNAL ;
    SHAPE ABUTMENT ;
    PORT
      LAYER M4 ;
      RECT 176.880 57.696 176.904 57.720 ;
    END
  END w_mask_in[314]
  PIN w_mask_in[315]
    DIRECTION INPUT ;
    USE SIGNAL ;
    SHAPE ABUTMENT ;
    PORT
      LAYER M4 ;
      RECT 176.880 57.792 176.904 57.816 ;
    END
  END w_mask_in[315]
  PIN w_mask_in[316]
    DIRECTION INPUT ;
    USE SIGNAL ;
    SHAPE ABUTMENT ;
    PORT
      LAYER M4 ;
      RECT 176.880 57.888 176.904 57.912 ;
    END
  END w_mask_in[316]
  PIN w_mask_in[317]
    DIRECTION INPUT ;
    USE SIGNAL ;
    SHAPE ABUTMENT ;
    PORT
      LAYER M4 ;
      RECT 176.880 57.984 176.904 58.008 ;
    END
  END w_mask_in[317]
  PIN w_mask_in[318]
    DIRECTION INPUT ;
    USE SIGNAL ;
    SHAPE ABUTMENT ;
    PORT
      LAYER M4 ;
      RECT 176.880 58.080 176.904 58.104 ;
    END
  END w_mask_in[318]
  PIN w_mask_in[319]
    DIRECTION INPUT ;
    USE SIGNAL ;
    SHAPE ABUTMENT ;
    PORT
      LAYER M4 ;
      RECT 176.880 58.176 176.904 58.200 ;
    END
  END w_mask_in[319]
  PIN w_mask_in[320]
    DIRECTION INPUT ;
    USE SIGNAL ;
    SHAPE ABUTMENT ;
    PORT
      LAYER M4 ;
      RECT 176.880 58.272 176.904 58.296 ;
    END
  END w_mask_in[320]
  PIN w_mask_in[321]
    DIRECTION INPUT ;
    USE SIGNAL ;
    SHAPE ABUTMENT ;
    PORT
      LAYER M4 ;
      RECT 176.880 58.368 176.904 58.392 ;
    END
  END w_mask_in[321]
  PIN w_mask_in[322]
    DIRECTION INPUT ;
    USE SIGNAL ;
    SHAPE ABUTMENT ;
    PORT
      LAYER M4 ;
      RECT 176.880 58.464 176.904 58.488 ;
    END
  END w_mask_in[322]
  PIN w_mask_in[323]
    DIRECTION INPUT ;
    USE SIGNAL ;
    SHAPE ABUTMENT ;
    PORT
      LAYER M4 ;
      RECT 176.880 58.560 176.904 58.584 ;
    END
  END w_mask_in[323]
  PIN w_mask_in[324]
    DIRECTION INPUT ;
    USE SIGNAL ;
    SHAPE ABUTMENT ;
    PORT
      LAYER M4 ;
      RECT 176.880 58.656 176.904 58.680 ;
    END
  END w_mask_in[324]
  PIN w_mask_in[325]
    DIRECTION INPUT ;
    USE SIGNAL ;
    SHAPE ABUTMENT ;
    PORT
      LAYER M4 ;
      RECT 176.880 58.752 176.904 58.776 ;
    END
  END w_mask_in[325]
  PIN w_mask_in[326]
    DIRECTION INPUT ;
    USE SIGNAL ;
    SHAPE ABUTMENT ;
    PORT
      LAYER M4 ;
      RECT 176.880 58.848 176.904 58.872 ;
    END
  END w_mask_in[326]
  PIN w_mask_in[327]
    DIRECTION INPUT ;
    USE SIGNAL ;
    SHAPE ABUTMENT ;
    PORT
      LAYER M4 ;
      RECT 176.880 58.944 176.904 58.968 ;
    END
  END w_mask_in[327]
  PIN w_mask_in[328]
    DIRECTION INPUT ;
    USE SIGNAL ;
    SHAPE ABUTMENT ;
    PORT
      LAYER M4 ;
      RECT 176.880 59.040 176.904 59.064 ;
    END
  END w_mask_in[328]
  PIN w_mask_in[329]
    DIRECTION INPUT ;
    USE SIGNAL ;
    SHAPE ABUTMENT ;
    PORT
      LAYER M4 ;
      RECT 176.880 59.136 176.904 59.160 ;
    END
  END w_mask_in[329]
  PIN w_mask_in[330]
    DIRECTION INPUT ;
    USE SIGNAL ;
    SHAPE ABUTMENT ;
    PORT
      LAYER M4 ;
      RECT 176.880 59.232 176.904 59.256 ;
    END
  END w_mask_in[330]
  PIN w_mask_in[331]
    DIRECTION INPUT ;
    USE SIGNAL ;
    SHAPE ABUTMENT ;
    PORT
      LAYER M4 ;
      RECT 176.880 59.328 176.904 59.352 ;
    END
  END w_mask_in[331]
  PIN w_mask_in[332]
    DIRECTION INPUT ;
    USE SIGNAL ;
    SHAPE ABUTMENT ;
    PORT
      LAYER M4 ;
      RECT 176.880 59.424 176.904 59.448 ;
    END
  END w_mask_in[332]
  PIN w_mask_in[333]
    DIRECTION INPUT ;
    USE SIGNAL ;
    SHAPE ABUTMENT ;
    PORT
      LAYER M4 ;
      RECT 176.880 59.520 176.904 59.544 ;
    END
  END w_mask_in[333]
  PIN w_mask_in[334]
    DIRECTION INPUT ;
    USE SIGNAL ;
    SHAPE ABUTMENT ;
    PORT
      LAYER M4 ;
      RECT 176.880 59.616 176.904 59.640 ;
    END
  END w_mask_in[334]
  PIN w_mask_in[335]
    DIRECTION INPUT ;
    USE SIGNAL ;
    SHAPE ABUTMENT ;
    PORT
      LAYER M4 ;
      RECT 176.880 59.712 176.904 59.736 ;
    END
  END w_mask_in[335]
  PIN w_mask_in[336]
    DIRECTION INPUT ;
    USE SIGNAL ;
    SHAPE ABUTMENT ;
    PORT
      LAYER M4 ;
      RECT 176.880 59.808 176.904 59.832 ;
    END
  END w_mask_in[336]
  PIN w_mask_in[337]
    DIRECTION INPUT ;
    USE SIGNAL ;
    SHAPE ABUTMENT ;
    PORT
      LAYER M4 ;
      RECT 176.880 59.904 176.904 59.928 ;
    END
  END w_mask_in[337]
  PIN w_mask_in[338]
    DIRECTION INPUT ;
    USE SIGNAL ;
    SHAPE ABUTMENT ;
    PORT
      LAYER M4 ;
      RECT 176.880 60.000 176.904 60.024 ;
    END
  END w_mask_in[338]
  PIN w_mask_in[339]
    DIRECTION INPUT ;
    USE SIGNAL ;
    SHAPE ABUTMENT ;
    PORT
      LAYER M4 ;
      RECT 176.880 60.096 176.904 60.120 ;
    END
  END w_mask_in[339]
  PIN w_mask_in[340]
    DIRECTION INPUT ;
    USE SIGNAL ;
    SHAPE ABUTMENT ;
    PORT
      LAYER M4 ;
      RECT 176.880 60.192 176.904 60.216 ;
    END
  END w_mask_in[340]
  PIN w_mask_in[341]
    DIRECTION INPUT ;
    USE SIGNAL ;
    SHAPE ABUTMENT ;
    PORT
      LAYER M4 ;
      RECT 176.880 60.288 176.904 60.312 ;
    END
  END w_mask_in[341]
  PIN w_mask_in[342]
    DIRECTION INPUT ;
    USE SIGNAL ;
    SHAPE ABUTMENT ;
    PORT
      LAYER M4 ;
      RECT 176.880 60.384 176.904 60.408 ;
    END
  END w_mask_in[342]
  PIN w_mask_in[343]
    DIRECTION INPUT ;
    USE SIGNAL ;
    SHAPE ABUTMENT ;
    PORT
      LAYER M4 ;
      RECT 176.880 60.480 176.904 60.504 ;
    END
  END w_mask_in[343]
  PIN w_mask_in[344]
    DIRECTION INPUT ;
    USE SIGNAL ;
    SHAPE ABUTMENT ;
    PORT
      LAYER M4 ;
      RECT 176.880 60.576 176.904 60.600 ;
    END
  END w_mask_in[344]
  PIN w_mask_in[345]
    DIRECTION INPUT ;
    USE SIGNAL ;
    SHAPE ABUTMENT ;
    PORT
      LAYER M4 ;
      RECT 176.880 60.672 176.904 60.696 ;
    END
  END w_mask_in[345]
  PIN w_mask_in[346]
    DIRECTION INPUT ;
    USE SIGNAL ;
    SHAPE ABUTMENT ;
    PORT
      LAYER M4 ;
      RECT 176.880 60.768 176.904 60.792 ;
    END
  END w_mask_in[346]
  PIN w_mask_in[347]
    DIRECTION INPUT ;
    USE SIGNAL ;
    SHAPE ABUTMENT ;
    PORT
      LAYER M4 ;
      RECT 176.880 60.864 176.904 60.888 ;
    END
  END w_mask_in[347]
  PIN w_mask_in[348]
    DIRECTION INPUT ;
    USE SIGNAL ;
    SHAPE ABUTMENT ;
    PORT
      LAYER M4 ;
      RECT 176.880 60.960 176.904 60.984 ;
    END
  END w_mask_in[348]
  PIN w_mask_in[349]
    DIRECTION INPUT ;
    USE SIGNAL ;
    SHAPE ABUTMENT ;
    PORT
      LAYER M4 ;
      RECT 176.880 61.056 176.904 61.080 ;
    END
  END w_mask_in[349]
  PIN w_mask_in[350]
    DIRECTION INPUT ;
    USE SIGNAL ;
    SHAPE ABUTMENT ;
    PORT
      LAYER M4 ;
      RECT 176.880 61.152 176.904 61.176 ;
    END
  END w_mask_in[350]
  PIN w_mask_in[351]
    DIRECTION INPUT ;
    USE SIGNAL ;
    SHAPE ABUTMENT ;
    PORT
      LAYER M4 ;
      RECT 176.880 61.248 176.904 61.272 ;
    END
  END w_mask_in[351]
  PIN w_mask_in[352]
    DIRECTION INPUT ;
    USE SIGNAL ;
    SHAPE ABUTMENT ;
    PORT
      LAYER M4 ;
      RECT 176.880 61.344 176.904 61.368 ;
    END
  END w_mask_in[352]
  PIN w_mask_in[353]
    DIRECTION INPUT ;
    USE SIGNAL ;
    SHAPE ABUTMENT ;
    PORT
      LAYER M4 ;
      RECT 176.880 61.440 176.904 61.464 ;
    END
  END w_mask_in[353]
  PIN w_mask_in[354]
    DIRECTION INPUT ;
    USE SIGNAL ;
    SHAPE ABUTMENT ;
    PORT
      LAYER M4 ;
      RECT 176.880 61.536 176.904 61.560 ;
    END
  END w_mask_in[354]
  PIN w_mask_in[355]
    DIRECTION INPUT ;
    USE SIGNAL ;
    SHAPE ABUTMENT ;
    PORT
      LAYER M4 ;
      RECT 176.880 61.632 176.904 61.656 ;
    END
  END w_mask_in[355]
  PIN w_mask_in[356]
    DIRECTION INPUT ;
    USE SIGNAL ;
    SHAPE ABUTMENT ;
    PORT
      LAYER M4 ;
      RECT 176.880 61.728 176.904 61.752 ;
    END
  END w_mask_in[356]
  PIN w_mask_in[357]
    DIRECTION INPUT ;
    USE SIGNAL ;
    SHAPE ABUTMENT ;
    PORT
      LAYER M4 ;
      RECT 176.880 61.824 176.904 61.848 ;
    END
  END w_mask_in[357]
  PIN w_mask_in[358]
    DIRECTION INPUT ;
    USE SIGNAL ;
    SHAPE ABUTMENT ;
    PORT
      LAYER M4 ;
      RECT 176.880 61.920 176.904 61.944 ;
    END
  END w_mask_in[358]
  PIN w_mask_in[359]
    DIRECTION INPUT ;
    USE SIGNAL ;
    SHAPE ABUTMENT ;
    PORT
      LAYER M4 ;
      RECT 176.880 62.016 176.904 62.040 ;
    END
  END w_mask_in[359]
  PIN w_mask_in[360]
    DIRECTION INPUT ;
    USE SIGNAL ;
    SHAPE ABUTMENT ;
    PORT
      LAYER M4 ;
      RECT 176.880 62.112 176.904 62.136 ;
    END
  END w_mask_in[360]
  PIN w_mask_in[361]
    DIRECTION INPUT ;
    USE SIGNAL ;
    SHAPE ABUTMENT ;
    PORT
      LAYER M4 ;
      RECT 176.880 62.208 176.904 62.232 ;
    END
  END w_mask_in[361]
  PIN w_mask_in[362]
    DIRECTION INPUT ;
    USE SIGNAL ;
    SHAPE ABUTMENT ;
    PORT
      LAYER M4 ;
      RECT 176.880 62.304 176.904 62.328 ;
    END
  END w_mask_in[362]
  PIN w_mask_in[363]
    DIRECTION INPUT ;
    USE SIGNAL ;
    SHAPE ABUTMENT ;
    PORT
      LAYER M4 ;
      RECT 176.880 62.400 176.904 62.424 ;
    END
  END w_mask_in[363]
  PIN w_mask_in[364]
    DIRECTION INPUT ;
    USE SIGNAL ;
    SHAPE ABUTMENT ;
    PORT
      LAYER M4 ;
      RECT 176.880 62.496 176.904 62.520 ;
    END
  END w_mask_in[364]
  PIN w_mask_in[365]
    DIRECTION INPUT ;
    USE SIGNAL ;
    SHAPE ABUTMENT ;
    PORT
      LAYER M4 ;
      RECT 176.880 62.592 176.904 62.616 ;
    END
  END w_mask_in[365]
  PIN w_mask_in[366]
    DIRECTION INPUT ;
    USE SIGNAL ;
    SHAPE ABUTMENT ;
    PORT
      LAYER M4 ;
      RECT 176.880 62.688 176.904 62.712 ;
    END
  END w_mask_in[366]
  PIN w_mask_in[367]
    DIRECTION INPUT ;
    USE SIGNAL ;
    SHAPE ABUTMENT ;
    PORT
      LAYER M4 ;
      RECT 176.880 62.784 176.904 62.808 ;
    END
  END w_mask_in[367]
  PIN w_mask_in[368]
    DIRECTION INPUT ;
    USE SIGNAL ;
    SHAPE ABUTMENT ;
    PORT
      LAYER M4 ;
      RECT 176.880 62.880 176.904 62.904 ;
    END
  END w_mask_in[368]
  PIN w_mask_in[369]
    DIRECTION INPUT ;
    USE SIGNAL ;
    SHAPE ABUTMENT ;
    PORT
      LAYER M4 ;
      RECT 176.880 62.976 176.904 63.000 ;
    END
  END w_mask_in[369]
  PIN w_mask_in[370]
    DIRECTION INPUT ;
    USE SIGNAL ;
    SHAPE ABUTMENT ;
    PORT
      LAYER M4 ;
      RECT 176.880 63.072 176.904 63.096 ;
    END
  END w_mask_in[370]
  PIN w_mask_in[371]
    DIRECTION INPUT ;
    USE SIGNAL ;
    SHAPE ABUTMENT ;
    PORT
      LAYER M4 ;
      RECT 176.880 63.168 176.904 63.192 ;
    END
  END w_mask_in[371]
  PIN w_mask_in[372]
    DIRECTION INPUT ;
    USE SIGNAL ;
    SHAPE ABUTMENT ;
    PORT
      LAYER M4 ;
      RECT 176.880 63.264 176.904 63.288 ;
    END
  END w_mask_in[372]
  PIN w_mask_in[373]
    DIRECTION INPUT ;
    USE SIGNAL ;
    SHAPE ABUTMENT ;
    PORT
      LAYER M4 ;
      RECT 176.880 63.360 176.904 63.384 ;
    END
  END w_mask_in[373]
  PIN w_mask_in[374]
    DIRECTION INPUT ;
    USE SIGNAL ;
    SHAPE ABUTMENT ;
    PORT
      LAYER M4 ;
      RECT 176.880 63.456 176.904 63.480 ;
    END
  END w_mask_in[374]
  PIN w_mask_in[375]
    DIRECTION INPUT ;
    USE SIGNAL ;
    SHAPE ABUTMENT ;
    PORT
      LAYER M4 ;
      RECT 176.880 63.552 176.904 63.576 ;
    END
  END w_mask_in[375]
  PIN w_mask_in[376]
    DIRECTION INPUT ;
    USE SIGNAL ;
    SHAPE ABUTMENT ;
    PORT
      LAYER M4 ;
      RECT 176.880 63.648 176.904 63.672 ;
    END
  END w_mask_in[376]
  PIN w_mask_in[377]
    DIRECTION INPUT ;
    USE SIGNAL ;
    SHAPE ABUTMENT ;
    PORT
      LAYER M4 ;
      RECT 176.880 63.744 176.904 63.768 ;
    END
  END w_mask_in[377]
  PIN w_mask_in[378]
    DIRECTION INPUT ;
    USE SIGNAL ;
    SHAPE ABUTMENT ;
    PORT
      LAYER M4 ;
      RECT 176.880 63.840 176.904 63.864 ;
    END
  END w_mask_in[378]
  PIN w_mask_in[379]
    DIRECTION INPUT ;
    USE SIGNAL ;
    SHAPE ABUTMENT ;
    PORT
      LAYER M4 ;
      RECT 176.880 63.936 176.904 63.960 ;
    END
  END w_mask_in[379]
  PIN w_mask_in[380]
    DIRECTION INPUT ;
    USE SIGNAL ;
    SHAPE ABUTMENT ;
    PORT
      LAYER M4 ;
      RECT 176.880 64.032 176.904 64.056 ;
    END
  END w_mask_in[380]
  PIN w_mask_in[381]
    DIRECTION INPUT ;
    USE SIGNAL ;
    SHAPE ABUTMENT ;
    PORT
      LAYER M4 ;
      RECT 176.880 64.128 176.904 64.152 ;
    END
  END w_mask_in[381]
  PIN w_mask_in[382]
    DIRECTION INPUT ;
    USE SIGNAL ;
    SHAPE ABUTMENT ;
    PORT
      LAYER M4 ;
      RECT 176.880 64.224 176.904 64.248 ;
    END
  END w_mask_in[382]
  PIN w_mask_in[383]
    DIRECTION INPUT ;
    USE SIGNAL ;
    SHAPE ABUTMENT ;
    PORT
      LAYER M4 ;
      RECT 176.880 64.320 176.904 64.344 ;
    END
  END w_mask_in[383]
  PIN w_mask_in[384]
    DIRECTION INPUT ;
    USE SIGNAL ;
    SHAPE ABUTMENT ;
    PORT
      LAYER M4 ;
      RECT 176.880 64.416 176.904 64.440 ;
    END
  END w_mask_in[384]
  PIN w_mask_in[385]
    DIRECTION INPUT ;
    USE SIGNAL ;
    SHAPE ABUTMENT ;
    PORT
      LAYER M4 ;
      RECT 176.880 64.512 176.904 64.536 ;
    END
  END w_mask_in[385]
  PIN w_mask_in[386]
    DIRECTION INPUT ;
    USE SIGNAL ;
    SHAPE ABUTMENT ;
    PORT
      LAYER M4 ;
      RECT 176.880 64.608 176.904 64.632 ;
    END
  END w_mask_in[386]
  PIN w_mask_in[387]
    DIRECTION INPUT ;
    USE SIGNAL ;
    SHAPE ABUTMENT ;
    PORT
      LAYER M4 ;
      RECT 176.880 64.704 176.904 64.728 ;
    END
  END w_mask_in[387]
  PIN w_mask_in[388]
    DIRECTION INPUT ;
    USE SIGNAL ;
    SHAPE ABUTMENT ;
    PORT
      LAYER M4 ;
      RECT 176.880 64.800 176.904 64.824 ;
    END
  END w_mask_in[388]
  PIN w_mask_in[389]
    DIRECTION INPUT ;
    USE SIGNAL ;
    SHAPE ABUTMENT ;
    PORT
      LAYER M4 ;
      RECT 176.880 64.896 176.904 64.920 ;
    END
  END w_mask_in[389]
  PIN w_mask_in[390]
    DIRECTION INPUT ;
    USE SIGNAL ;
    SHAPE ABUTMENT ;
    PORT
      LAYER M4 ;
      RECT 176.880 64.992 176.904 65.016 ;
    END
  END w_mask_in[390]
  PIN w_mask_in[391]
    DIRECTION INPUT ;
    USE SIGNAL ;
    SHAPE ABUTMENT ;
    PORT
      LAYER M4 ;
      RECT 176.880 65.088 176.904 65.112 ;
    END
  END w_mask_in[391]
  PIN w_mask_in[392]
    DIRECTION INPUT ;
    USE SIGNAL ;
    SHAPE ABUTMENT ;
    PORT
      LAYER M4 ;
      RECT 176.880 65.184 176.904 65.208 ;
    END
  END w_mask_in[392]
  PIN w_mask_in[393]
    DIRECTION INPUT ;
    USE SIGNAL ;
    SHAPE ABUTMENT ;
    PORT
      LAYER M4 ;
      RECT 176.880 65.280 176.904 65.304 ;
    END
  END w_mask_in[393]
  PIN w_mask_in[394]
    DIRECTION INPUT ;
    USE SIGNAL ;
    SHAPE ABUTMENT ;
    PORT
      LAYER M4 ;
      RECT 176.880 65.376 176.904 65.400 ;
    END
  END w_mask_in[394]
  PIN w_mask_in[395]
    DIRECTION INPUT ;
    USE SIGNAL ;
    SHAPE ABUTMENT ;
    PORT
      LAYER M4 ;
      RECT 176.880 65.472 176.904 65.496 ;
    END
  END w_mask_in[395]
  PIN w_mask_in[396]
    DIRECTION INPUT ;
    USE SIGNAL ;
    SHAPE ABUTMENT ;
    PORT
      LAYER M4 ;
      RECT 176.880 65.568 176.904 65.592 ;
    END
  END w_mask_in[396]
  PIN w_mask_in[397]
    DIRECTION INPUT ;
    USE SIGNAL ;
    SHAPE ABUTMENT ;
    PORT
      LAYER M4 ;
      RECT 176.880 65.664 176.904 65.688 ;
    END
  END w_mask_in[397]
  PIN w_mask_in[398]
    DIRECTION INPUT ;
    USE SIGNAL ;
    SHAPE ABUTMENT ;
    PORT
      LAYER M4 ;
      RECT 176.880 65.760 176.904 65.784 ;
    END
  END w_mask_in[398]
  PIN w_mask_in[399]
    DIRECTION INPUT ;
    USE SIGNAL ;
    SHAPE ABUTMENT ;
    PORT
      LAYER M4 ;
      RECT 176.880 65.856 176.904 65.880 ;
    END
  END w_mask_in[399]
  PIN w_mask_in[400]
    DIRECTION INPUT ;
    USE SIGNAL ;
    SHAPE ABUTMENT ;
    PORT
      LAYER M4 ;
      RECT 176.880 65.952 176.904 65.976 ;
    END
  END w_mask_in[400]
  PIN w_mask_in[401]
    DIRECTION INPUT ;
    USE SIGNAL ;
    SHAPE ABUTMENT ;
    PORT
      LAYER M4 ;
      RECT 176.880 66.048 176.904 66.072 ;
    END
  END w_mask_in[401]
  PIN w_mask_in[402]
    DIRECTION INPUT ;
    USE SIGNAL ;
    SHAPE ABUTMENT ;
    PORT
      LAYER M4 ;
      RECT 176.880 66.144 176.904 66.168 ;
    END
  END w_mask_in[402]
  PIN w_mask_in[403]
    DIRECTION INPUT ;
    USE SIGNAL ;
    SHAPE ABUTMENT ;
    PORT
      LAYER M4 ;
      RECT 176.880 66.240 176.904 66.264 ;
    END
  END w_mask_in[403]
  PIN w_mask_in[404]
    DIRECTION INPUT ;
    USE SIGNAL ;
    SHAPE ABUTMENT ;
    PORT
      LAYER M4 ;
      RECT 176.880 66.336 176.904 66.360 ;
    END
  END w_mask_in[404]
  PIN w_mask_in[405]
    DIRECTION INPUT ;
    USE SIGNAL ;
    SHAPE ABUTMENT ;
    PORT
      LAYER M4 ;
      RECT 176.880 66.432 176.904 66.456 ;
    END
  END w_mask_in[405]
  PIN w_mask_in[406]
    DIRECTION INPUT ;
    USE SIGNAL ;
    SHAPE ABUTMENT ;
    PORT
      LAYER M4 ;
      RECT 176.880 66.528 176.904 66.552 ;
    END
  END w_mask_in[406]
  PIN w_mask_in[407]
    DIRECTION INPUT ;
    USE SIGNAL ;
    SHAPE ABUTMENT ;
    PORT
      LAYER M4 ;
      RECT 176.880 66.624 176.904 66.648 ;
    END
  END w_mask_in[407]
  PIN w_mask_in[408]
    DIRECTION INPUT ;
    USE SIGNAL ;
    SHAPE ABUTMENT ;
    PORT
      LAYER M4 ;
      RECT 176.880 66.720 176.904 66.744 ;
    END
  END w_mask_in[408]
  PIN w_mask_in[409]
    DIRECTION INPUT ;
    USE SIGNAL ;
    SHAPE ABUTMENT ;
    PORT
      LAYER M4 ;
      RECT 176.880 66.816 176.904 66.840 ;
    END
  END w_mask_in[409]
  PIN w_mask_in[410]
    DIRECTION INPUT ;
    USE SIGNAL ;
    SHAPE ABUTMENT ;
    PORT
      LAYER M4 ;
      RECT 176.880 66.912 176.904 66.936 ;
    END
  END w_mask_in[410]
  PIN w_mask_in[411]
    DIRECTION INPUT ;
    USE SIGNAL ;
    SHAPE ABUTMENT ;
    PORT
      LAYER M4 ;
      RECT 176.880 67.008 176.904 67.032 ;
    END
  END w_mask_in[411]
  PIN w_mask_in[412]
    DIRECTION INPUT ;
    USE SIGNAL ;
    SHAPE ABUTMENT ;
    PORT
      LAYER M4 ;
      RECT 176.880 67.104 176.904 67.128 ;
    END
  END w_mask_in[412]
  PIN w_mask_in[413]
    DIRECTION INPUT ;
    USE SIGNAL ;
    SHAPE ABUTMENT ;
    PORT
      LAYER M4 ;
      RECT 176.880 67.200 176.904 67.224 ;
    END
  END w_mask_in[413]
  PIN w_mask_in[414]
    DIRECTION INPUT ;
    USE SIGNAL ;
    SHAPE ABUTMENT ;
    PORT
      LAYER M4 ;
      RECT 176.880 67.296 176.904 67.320 ;
    END
  END w_mask_in[414]
  PIN w_mask_in[415]
    DIRECTION INPUT ;
    USE SIGNAL ;
    SHAPE ABUTMENT ;
    PORT
      LAYER M4 ;
      RECT 176.880 67.392 176.904 67.416 ;
    END
  END w_mask_in[415]
  PIN w_mask_in[416]
    DIRECTION INPUT ;
    USE SIGNAL ;
    SHAPE ABUTMENT ;
    PORT
      LAYER M4 ;
      RECT 176.880 67.488 176.904 67.512 ;
    END
  END w_mask_in[416]
  PIN w_mask_in[417]
    DIRECTION INPUT ;
    USE SIGNAL ;
    SHAPE ABUTMENT ;
    PORT
      LAYER M4 ;
      RECT 176.880 67.584 176.904 67.608 ;
    END
  END w_mask_in[417]
  PIN w_mask_in[418]
    DIRECTION INPUT ;
    USE SIGNAL ;
    SHAPE ABUTMENT ;
    PORT
      LAYER M4 ;
      RECT 176.880 67.680 176.904 67.704 ;
    END
  END w_mask_in[418]
  PIN w_mask_in[419]
    DIRECTION INPUT ;
    USE SIGNAL ;
    SHAPE ABUTMENT ;
    PORT
      LAYER M4 ;
      RECT 176.880 67.776 176.904 67.800 ;
    END
  END w_mask_in[419]
  PIN w_mask_in[420]
    DIRECTION INPUT ;
    USE SIGNAL ;
    SHAPE ABUTMENT ;
    PORT
      LAYER M4 ;
      RECT 176.880 67.872 176.904 67.896 ;
    END
  END w_mask_in[420]
  PIN w_mask_in[421]
    DIRECTION INPUT ;
    USE SIGNAL ;
    SHAPE ABUTMENT ;
    PORT
      LAYER M4 ;
      RECT 176.880 67.968 176.904 67.992 ;
    END
  END w_mask_in[421]
  PIN w_mask_in[422]
    DIRECTION INPUT ;
    USE SIGNAL ;
    SHAPE ABUTMENT ;
    PORT
      LAYER M4 ;
      RECT 176.880 68.064 176.904 68.088 ;
    END
  END w_mask_in[422]
  PIN w_mask_in[423]
    DIRECTION INPUT ;
    USE SIGNAL ;
    SHAPE ABUTMENT ;
    PORT
      LAYER M4 ;
      RECT 176.880 68.160 176.904 68.184 ;
    END
  END w_mask_in[423]
  PIN w_mask_in[424]
    DIRECTION INPUT ;
    USE SIGNAL ;
    SHAPE ABUTMENT ;
    PORT
      LAYER M4 ;
      RECT 176.880 68.256 176.904 68.280 ;
    END
  END w_mask_in[424]
  PIN w_mask_in[425]
    DIRECTION INPUT ;
    USE SIGNAL ;
    SHAPE ABUTMENT ;
    PORT
      LAYER M4 ;
      RECT 176.880 68.352 176.904 68.376 ;
    END
  END w_mask_in[425]
  PIN w_mask_in[426]
    DIRECTION INPUT ;
    USE SIGNAL ;
    SHAPE ABUTMENT ;
    PORT
      LAYER M4 ;
      RECT 176.880 68.448 176.904 68.472 ;
    END
  END w_mask_in[426]
  PIN w_mask_in[427]
    DIRECTION INPUT ;
    USE SIGNAL ;
    SHAPE ABUTMENT ;
    PORT
      LAYER M4 ;
      RECT 176.880 68.544 176.904 68.568 ;
    END
  END w_mask_in[427]
  PIN w_mask_in[428]
    DIRECTION INPUT ;
    USE SIGNAL ;
    SHAPE ABUTMENT ;
    PORT
      LAYER M4 ;
      RECT 176.880 68.640 176.904 68.664 ;
    END
  END w_mask_in[428]
  PIN w_mask_in[429]
    DIRECTION INPUT ;
    USE SIGNAL ;
    SHAPE ABUTMENT ;
    PORT
      LAYER M4 ;
      RECT 176.880 68.736 176.904 68.760 ;
    END
  END w_mask_in[429]
  PIN w_mask_in[430]
    DIRECTION INPUT ;
    USE SIGNAL ;
    SHAPE ABUTMENT ;
    PORT
      LAYER M4 ;
      RECT 176.880 68.832 176.904 68.856 ;
    END
  END w_mask_in[430]
  PIN w_mask_in[431]
    DIRECTION INPUT ;
    USE SIGNAL ;
    SHAPE ABUTMENT ;
    PORT
      LAYER M4 ;
      RECT 176.880 68.928 176.904 68.952 ;
    END
  END w_mask_in[431]
  PIN w_mask_in[432]
    DIRECTION INPUT ;
    USE SIGNAL ;
    SHAPE ABUTMENT ;
    PORT
      LAYER M4 ;
      RECT 176.880 69.024 176.904 69.048 ;
    END
  END w_mask_in[432]
  PIN w_mask_in[433]
    DIRECTION INPUT ;
    USE SIGNAL ;
    SHAPE ABUTMENT ;
    PORT
      LAYER M4 ;
      RECT 176.880 69.120 176.904 69.144 ;
    END
  END w_mask_in[433]
  PIN w_mask_in[434]
    DIRECTION INPUT ;
    USE SIGNAL ;
    SHAPE ABUTMENT ;
    PORT
      LAYER M4 ;
      RECT 176.880 69.216 176.904 69.240 ;
    END
  END w_mask_in[434]
  PIN w_mask_in[435]
    DIRECTION INPUT ;
    USE SIGNAL ;
    SHAPE ABUTMENT ;
    PORT
      LAYER M4 ;
      RECT 176.880 69.312 176.904 69.336 ;
    END
  END w_mask_in[435]
  PIN w_mask_in[436]
    DIRECTION INPUT ;
    USE SIGNAL ;
    SHAPE ABUTMENT ;
    PORT
      LAYER M4 ;
      RECT 176.880 69.408 176.904 69.432 ;
    END
  END w_mask_in[436]
  PIN w_mask_in[437]
    DIRECTION INPUT ;
    USE SIGNAL ;
    SHAPE ABUTMENT ;
    PORT
      LAYER M4 ;
      RECT 176.880 69.504 176.904 69.528 ;
    END
  END w_mask_in[437]
  PIN w_mask_in[438]
    DIRECTION INPUT ;
    USE SIGNAL ;
    SHAPE ABUTMENT ;
    PORT
      LAYER M4 ;
      RECT 176.880 69.600 176.904 69.624 ;
    END
  END w_mask_in[438]
  PIN w_mask_in[439]
    DIRECTION INPUT ;
    USE SIGNAL ;
    SHAPE ABUTMENT ;
    PORT
      LAYER M4 ;
      RECT 176.880 69.696 176.904 69.720 ;
    END
  END w_mask_in[439]
  PIN w_mask_in[440]
    DIRECTION INPUT ;
    USE SIGNAL ;
    SHAPE ABUTMENT ;
    PORT
      LAYER M4 ;
      RECT 176.880 69.792 176.904 69.816 ;
    END
  END w_mask_in[440]
  PIN w_mask_in[441]
    DIRECTION INPUT ;
    USE SIGNAL ;
    SHAPE ABUTMENT ;
    PORT
      LAYER M4 ;
      RECT 176.880 69.888 176.904 69.912 ;
    END
  END w_mask_in[441]
  PIN w_mask_in[442]
    DIRECTION INPUT ;
    USE SIGNAL ;
    SHAPE ABUTMENT ;
    PORT
      LAYER M4 ;
      RECT 176.880 69.984 176.904 70.008 ;
    END
  END w_mask_in[442]
  PIN w_mask_in[443]
    DIRECTION INPUT ;
    USE SIGNAL ;
    SHAPE ABUTMENT ;
    PORT
      LAYER M4 ;
      RECT 176.880 70.080 176.904 70.104 ;
    END
  END w_mask_in[443]
  PIN w_mask_in[444]
    DIRECTION INPUT ;
    USE SIGNAL ;
    SHAPE ABUTMENT ;
    PORT
      LAYER M4 ;
      RECT 176.880 70.176 176.904 70.200 ;
    END
  END w_mask_in[444]
  PIN w_mask_in[445]
    DIRECTION INPUT ;
    USE SIGNAL ;
    SHAPE ABUTMENT ;
    PORT
      LAYER M4 ;
      RECT 176.880 70.272 176.904 70.296 ;
    END
  END w_mask_in[445]
  PIN w_mask_in[446]
    DIRECTION INPUT ;
    USE SIGNAL ;
    SHAPE ABUTMENT ;
    PORT
      LAYER M4 ;
      RECT 176.880 70.368 176.904 70.392 ;
    END
  END w_mask_in[446]
  PIN w_mask_in[447]
    DIRECTION INPUT ;
    USE SIGNAL ;
    SHAPE ABUTMENT ;
    PORT
      LAYER M4 ;
      RECT 176.880 70.464 176.904 70.488 ;
    END
  END w_mask_in[447]
  PIN w_mask_in[448]
    DIRECTION INPUT ;
    USE SIGNAL ;
    SHAPE ABUTMENT ;
    PORT
      LAYER M4 ;
      RECT 176.880 70.560 176.904 70.584 ;
    END
  END w_mask_in[448]
  PIN w_mask_in[449]
    DIRECTION INPUT ;
    USE SIGNAL ;
    SHAPE ABUTMENT ;
    PORT
      LAYER M4 ;
      RECT 176.880 70.656 176.904 70.680 ;
    END
  END w_mask_in[449]
  PIN w_mask_in[450]
    DIRECTION INPUT ;
    USE SIGNAL ;
    SHAPE ABUTMENT ;
    PORT
      LAYER M4 ;
      RECT 176.880 70.752 176.904 70.776 ;
    END
  END w_mask_in[450]
  PIN w_mask_in[451]
    DIRECTION INPUT ;
    USE SIGNAL ;
    SHAPE ABUTMENT ;
    PORT
      LAYER M4 ;
      RECT 176.880 70.848 176.904 70.872 ;
    END
  END w_mask_in[451]
  PIN w_mask_in[452]
    DIRECTION INPUT ;
    USE SIGNAL ;
    SHAPE ABUTMENT ;
    PORT
      LAYER M4 ;
      RECT 176.880 70.944 176.904 70.968 ;
    END
  END w_mask_in[452]
  PIN w_mask_in[453]
    DIRECTION INPUT ;
    USE SIGNAL ;
    SHAPE ABUTMENT ;
    PORT
      LAYER M4 ;
      RECT 176.880 71.040 176.904 71.064 ;
    END
  END w_mask_in[453]
  PIN w_mask_in[454]
    DIRECTION INPUT ;
    USE SIGNAL ;
    SHAPE ABUTMENT ;
    PORT
      LAYER M4 ;
      RECT 176.880 71.136 176.904 71.160 ;
    END
  END w_mask_in[454]
  PIN w_mask_in[455]
    DIRECTION INPUT ;
    USE SIGNAL ;
    SHAPE ABUTMENT ;
    PORT
      LAYER M4 ;
      RECT 176.880 71.232 176.904 71.256 ;
    END
  END w_mask_in[455]
  PIN w_mask_in[456]
    DIRECTION INPUT ;
    USE SIGNAL ;
    SHAPE ABUTMENT ;
    PORT
      LAYER M4 ;
      RECT 176.880 71.328 176.904 71.352 ;
    END
  END w_mask_in[456]
  PIN w_mask_in[457]
    DIRECTION INPUT ;
    USE SIGNAL ;
    SHAPE ABUTMENT ;
    PORT
      LAYER M4 ;
      RECT 176.880 71.424 176.904 71.448 ;
    END
  END w_mask_in[457]
  PIN w_mask_in[458]
    DIRECTION INPUT ;
    USE SIGNAL ;
    SHAPE ABUTMENT ;
    PORT
      LAYER M4 ;
      RECT 176.880 71.520 176.904 71.544 ;
    END
  END w_mask_in[458]
  PIN w_mask_in[459]
    DIRECTION INPUT ;
    USE SIGNAL ;
    SHAPE ABUTMENT ;
    PORT
      LAYER M4 ;
      RECT 176.880 71.616 176.904 71.640 ;
    END
  END w_mask_in[459]
  PIN w_mask_in[460]
    DIRECTION INPUT ;
    USE SIGNAL ;
    SHAPE ABUTMENT ;
    PORT
      LAYER M4 ;
      RECT 176.880 71.712 176.904 71.736 ;
    END
  END w_mask_in[460]
  PIN w_mask_in[461]
    DIRECTION INPUT ;
    USE SIGNAL ;
    SHAPE ABUTMENT ;
    PORT
      LAYER M4 ;
      RECT 176.880 71.808 176.904 71.832 ;
    END
  END w_mask_in[461]
  PIN w_mask_in[462]
    DIRECTION INPUT ;
    USE SIGNAL ;
    SHAPE ABUTMENT ;
    PORT
      LAYER M4 ;
      RECT 176.880 71.904 176.904 71.928 ;
    END
  END w_mask_in[462]
  PIN w_mask_in[463]
    DIRECTION INPUT ;
    USE SIGNAL ;
    SHAPE ABUTMENT ;
    PORT
      LAYER M4 ;
      RECT 176.880 72.000 176.904 72.024 ;
    END
  END w_mask_in[463]
  PIN w_mask_in[464]
    DIRECTION INPUT ;
    USE SIGNAL ;
    SHAPE ABUTMENT ;
    PORT
      LAYER M4 ;
      RECT 176.880 72.096 176.904 72.120 ;
    END
  END w_mask_in[464]
  PIN w_mask_in[465]
    DIRECTION INPUT ;
    USE SIGNAL ;
    SHAPE ABUTMENT ;
    PORT
      LAYER M4 ;
      RECT 176.880 72.192 176.904 72.216 ;
    END
  END w_mask_in[465]
  PIN w_mask_in[466]
    DIRECTION INPUT ;
    USE SIGNAL ;
    SHAPE ABUTMENT ;
    PORT
      LAYER M4 ;
      RECT 176.880 72.288 176.904 72.312 ;
    END
  END w_mask_in[466]
  PIN w_mask_in[467]
    DIRECTION INPUT ;
    USE SIGNAL ;
    SHAPE ABUTMENT ;
    PORT
      LAYER M4 ;
      RECT 176.880 72.384 176.904 72.408 ;
    END
  END w_mask_in[467]
  PIN w_mask_in[468]
    DIRECTION INPUT ;
    USE SIGNAL ;
    SHAPE ABUTMENT ;
    PORT
      LAYER M4 ;
      RECT 176.880 72.480 176.904 72.504 ;
    END
  END w_mask_in[468]
  PIN w_mask_in[469]
    DIRECTION INPUT ;
    USE SIGNAL ;
    SHAPE ABUTMENT ;
    PORT
      LAYER M4 ;
      RECT 176.880 72.576 176.904 72.600 ;
    END
  END w_mask_in[469]
  PIN w_mask_in[470]
    DIRECTION INPUT ;
    USE SIGNAL ;
    SHAPE ABUTMENT ;
    PORT
      LAYER M4 ;
      RECT 176.880 72.672 176.904 72.696 ;
    END
  END w_mask_in[470]
  PIN w_mask_in[471]
    DIRECTION INPUT ;
    USE SIGNAL ;
    SHAPE ABUTMENT ;
    PORT
      LAYER M4 ;
      RECT 176.880 72.768 176.904 72.792 ;
    END
  END w_mask_in[471]
  PIN w_mask_in[472]
    DIRECTION INPUT ;
    USE SIGNAL ;
    SHAPE ABUTMENT ;
    PORT
      LAYER M4 ;
      RECT 176.880 72.864 176.904 72.888 ;
    END
  END w_mask_in[472]
  PIN w_mask_in[473]
    DIRECTION INPUT ;
    USE SIGNAL ;
    SHAPE ABUTMENT ;
    PORT
      LAYER M4 ;
      RECT 176.880 72.960 176.904 72.984 ;
    END
  END w_mask_in[473]
  PIN w_mask_in[474]
    DIRECTION INPUT ;
    USE SIGNAL ;
    SHAPE ABUTMENT ;
    PORT
      LAYER M4 ;
      RECT 176.880 73.056 176.904 73.080 ;
    END
  END w_mask_in[474]
  PIN w_mask_in[475]
    DIRECTION INPUT ;
    USE SIGNAL ;
    SHAPE ABUTMENT ;
    PORT
      LAYER M4 ;
      RECT 176.880 73.152 176.904 73.176 ;
    END
  END w_mask_in[475]
  PIN w_mask_in[476]
    DIRECTION INPUT ;
    USE SIGNAL ;
    SHAPE ABUTMENT ;
    PORT
      LAYER M4 ;
      RECT 176.880 73.248 176.904 73.272 ;
    END
  END w_mask_in[476]
  PIN w_mask_in[477]
    DIRECTION INPUT ;
    USE SIGNAL ;
    SHAPE ABUTMENT ;
    PORT
      LAYER M4 ;
      RECT 176.880 73.344 176.904 73.368 ;
    END
  END w_mask_in[477]
  PIN w_mask_in[478]
    DIRECTION INPUT ;
    USE SIGNAL ;
    SHAPE ABUTMENT ;
    PORT
      LAYER M4 ;
      RECT 176.880 73.440 176.904 73.464 ;
    END
  END w_mask_in[478]
  PIN w_mask_in[479]
    DIRECTION INPUT ;
    USE SIGNAL ;
    SHAPE ABUTMENT ;
    PORT
      LAYER M4 ;
      RECT 176.880 73.536 176.904 73.560 ;
    END
  END w_mask_in[479]
  PIN w_mask_in[480]
    DIRECTION INPUT ;
    USE SIGNAL ;
    SHAPE ABUTMENT ;
    PORT
      LAYER M4 ;
      RECT 176.880 73.632 176.904 73.656 ;
    END
  END w_mask_in[480]
  PIN w_mask_in[481]
    DIRECTION INPUT ;
    USE SIGNAL ;
    SHAPE ABUTMENT ;
    PORT
      LAYER M4 ;
      RECT 176.880 73.728 176.904 73.752 ;
    END
  END w_mask_in[481]
  PIN w_mask_in[482]
    DIRECTION INPUT ;
    USE SIGNAL ;
    SHAPE ABUTMENT ;
    PORT
      LAYER M4 ;
      RECT 176.880 73.824 176.904 73.848 ;
    END
  END w_mask_in[482]
  PIN w_mask_in[483]
    DIRECTION INPUT ;
    USE SIGNAL ;
    SHAPE ABUTMENT ;
    PORT
      LAYER M4 ;
      RECT 176.880 73.920 176.904 73.944 ;
    END
  END w_mask_in[483]
  PIN w_mask_in[484]
    DIRECTION INPUT ;
    USE SIGNAL ;
    SHAPE ABUTMENT ;
    PORT
      LAYER M4 ;
      RECT 176.880 74.016 176.904 74.040 ;
    END
  END w_mask_in[484]
  PIN w_mask_in[485]
    DIRECTION INPUT ;
    USE SIGNAL ;
    SHAPE ABUTMENT ;
    PORT
      LAYER M4 ;
      RECT 176.880 74.112 176.904 74.136 ;
    END
  END w_mask_in[485]
  PIN w_mask_in[486]
    DIRECTION INPUT ;
    USE SIGNAL ;
    SHAPE ABUTMENT ;
    PORT
      LAYER M4 ;
      RECT 176.880 74.208 176.904 74.232 ;
    END
  END w_mask_in[486]
  PIN w_mask_in[487]
    DIRECTION INPUT ;
    USE SIGNAL ;
    SHAPE ABUTMENT ;
    PORT
      LAYER M4 ;
      RECT 176.880 74.304 176.904 74.328 ;
    END
  END w_mask_in[487]
  PIN w_mask_in[488]
    DIRECTION INPUT ;
    USE SIGNAL ;
    SHAPE ABUTMENT ;
    PORT
      LAYER M4 ;
      RECT 176.880 74.400 176.904 74.424 ;
    END
  END w_mask_in[488]
  PIN w_mask_in[489]
    DIRECTION INPUT ;
    USE SIGNAL ;
    SHAPE ABUTMENT ;
    PORT
      LAYER M4 ;
      RECT 176.880 74.496 176.904 74.520 ;
    END
  END w_mask_in[489]
  PIN w_mask_in[490]
    DIRECTION INPUT ;
    USE SIGNAL ;
    SHAPE ABUTMENT ;
    PORT
      LAYER M4 ;
      RECT 176.880 74.592 176.904 74.616 ;
    END
  END w_mask_in[490]
  PIN w_mask_in[491]
    DIRECTION INPUT ;
    USE SIGNAL ;
    SHAPE ABUTMENT ;
    PORT
      LAYER M4 ;
      RECT 176.880 74.688 176.904 74.712 ;
    END
  END w_mask_in[491]
  PIN w_mask_in[492]
    DIRECTION INPUT ;
    USE SIGNAL ;
    SHAPE ABUTMENT ;
    PORT
      LAYER M4 ;
      RECT 176.880 74.784 176.904 74.808 ;
    END
  END w_mask_in[492]
  PIN w_mask_in[493]
    DIRECTION INPUT ;
    USE SIGNAL ;
    SHAPE ABUTMENT ;
    PORT
      LAYER M4 ;
      RECT 176.880 74.880 176.904 74.904 ;
    END
  END w_mask_in[493]
  PIN w_mask_in[494]
    DIRECTION INPUT ;
    USE SIGNAL ;
    SHAPE ABUTMENT ;
    PORT
      LAYER M4 ;
      RECT 176.880 74.976 176.904 75.000 ;
    END
  END w_mask_in[494]
  PIN w_mask_in[495]
    DIRECTION INPUT ;
    USE SIGNAL ;
    SHAPE ABUTMENT ;
    PORT
      LAYER M4 ;
      RECT 176.880 75.072 176.904 75.096 ;
    END
  END w_mask_in[495]
  PIN w_mask_in[496]
    DIRECTION INPUT ;
    USE SIGNAL ;
    SHAPE ABUTMENT ;
    PORT
      LAYER M4 ;
      RECT 176.880 75.168 176.904 75.192 ;
    END
  END w_mask_in[496]
  PIN w_mask_in[497]
    DIRECTION INPUT ;
    USE SIGNAL ;
    SHAPE ABUTMENT ;
    PORT
      LAYER M4 ;
      RECT 176.880 75.264 176.904 75.288 ;
    END
  END w_mask_in[497]
  PIN w_mask_in[498]
    DIRECTION INPUT ;
    USE SIGNAL ;
    SHAPE ABUTMENT ;
    PORT
      LAYER M4 ;
      RECT 176.880 75.360 176.904 75.384 ;
    END
  END w_mask_in[498]
  PIN w_mask_in[499]
    DIRECTION INPUT ;
    USE SIGNAL ;
    SHAPE ABUTMENT ;
    PORT
      LAYER M4 ;
      RECT 176.880 75.456 176.904 75.480 ;
    END
  END w_mask_in[499]
  PIN w_mask_in[500]
    DIRECTION INPUT ;
    USE SIGNAL ;
    SHAPE ABUTMENT ;
    PORT
      LAYER M4 ;
      RECT 176.880 75.552 176.904 75.576 ;
    END
  END w_mask_in[500]
  PIN w_mask_in[501]
    DIRECTION INPUT ;
    USE SIGNAL ;
    SHAPE ABUTMENT ;
    PORT
      LAYER M4 ;
      RECT 176.880 75.648 176.904 75.672 ;
    END
  END w_mask_in[501]
  PIN w_mask_in[502]
    DIRECTION INPUT ;
    USE SIGNAL ;
    SHAPE ABUTMENT ;
    PORT
      LAYER M4 ;
      RECT 176.880 75.744 176.904 75.768 ;
    END
  END w_mask_in[502]
  PIN w_mask_in[503]
    DIRECTION INPUT ;
    USE SIGNAL ;
    SHAPE ABUTMENT ;
    PORT
      LAYER M4 ;
      RECT 176.880 75.840 176.904 75.864 ;
    END
  END w_mask_in[503]
  PIN w_mask_in[504]
    DIRECTION INPUT ;
    USE SIGNAL ;
    SHAPE ABUTMENT ;
    PORT
      LAYER M4 ;
      RECT 176.880 75.936 176.904 75.960 ;
    END
  END w_mask_in[504]
  PIN w_mask_in[505]
    DIRECTION INPUT ;
    USE SIGNAL ;
    SHAPE ABUTMENT ;
    PORT
      LAYER M4 ;
      RECT 176.880 76.032 176.904 76.056 ;
    END
  END w_mask_in[505]
  PIN w_mask_in[506]
    DIRECTION INPUT ;
    USE SIGNAL ;
    SHAPE ABUTMENT ;
    PORT
      LAYER M4 ;
      RECT 176.880 76.128 176.904 76.152 ;
    END
  END w_mask_in[506]
  PIN w_mask_in[507]
    DIRECTION INPUT ;
    USE SIGNAL ;
    SHAPE ABUTMENT ;
    PORT
      LAYER M4 ;
      RECT 176.880 76.224 176.904 76.248 ;
    END
  END w_mask_in[507]
  PIN w_mask_in[508]
    DIRECTION INPUT ;
    USE SIGNAL ;
    SHAPE ABUTMENT ;
    PORT
      LAYER M4 ;
      RECT 176.880 76.320 176.904 76.344 ;
    END
  END w_mask_in[508]
  PIN w_mask_in[509]
    DIRECTION INPUT ;
    USE SIGNAL ;
    SHAPE ABUTMENT ;
    PORT
      LAYER M4 ;
      RECT 176.880 76.416 176.904 76.440 ;
    END
  END w_mask_in[509]
  PIN w_mask_in[510]
    DIRECTION INPUT ;
    USE SIGNAL ;
    SHAPE ABUTMENT ;
    PORT
      LAYER M4 ;
      RECT 176.880 76.512 176.904 76.536 ;
    END
  END w_mask_in[510]
  PIN w_mask_in[511]
    DIRECTION INPUT ;
    USE SIGNAL ;
    SHAPE ABUTMENT ;
    PORT
      LAYER M4 ;
      RECT 176.880 76.608 176.904 76.632 ;
    END
  END w_mask_in[511]
  PIN w_mask_in[512]
    DIRECTION INPUT ;
    USE SIGNAL ;
    SHAPE ABUTMENT ;
    PORT
      LAYER M4 ;
      RECT 176.880 76.704 176.904 76.728 ;
    END
  END w_mask_in[512]
  PIN w_mask_in[513]
    DIRECTION INPUT ;
    USE SIGNAL ;
    SHAPE ABUTMENT ;
    PORT
      LAYER M4 ;
      RECT 176.880 76.800 176.904 76.824 ;
    END
  END w_mask_in[513]
  PIN w_mask_in[514]
    DIRECTION INPUT ;
    USE SIGNAL ;
    SHAPE ABUTMENT ;
    PORT
      LAYER M4 ;
      RECT 176.880 76.896 176.904 76.920 ;
    END
  END w_mask_in[514]
  PIN w_mask_in[515]
    DIRECTION INPUT ;
    USE SIGNAL ;
    SHAPE ABUTMENT ;
    PORT
      LAYER M4 ;
      RECT 176.880 76.992 176.904 77.016 ;
    END
  END w_mask_in[515]
  PIN w_mask_in[516]
    DIRECTION INPUT ;
    USE SIGNAL ;
    SHAPE ABUTMENT ;
    PORT
      LAYER M4 ;
      RECT 176.880 77.088 176.904 77.112 ;
    END
  END w_mask_in[516]
  PIN w_mask_in[517]
    DIRECTION INPUT ;
    USE SIGNAL ;
    SHAPE ABUTMENT ;
    PORT
      LAYER M4 ;
      RECT 176.880 77.184 176.904 77.208 ;
    END
  END w_mask_in[517]
  PIN w_mask_in[518]
    DIRECTION INPUT ;
    USE SIGNAL ;
    SHAPE ABUTMENT ;
    PORT
      LAYER M4 ;
      RECT 176.880 77.280 176.904 77.304 ;
    END
  END w_mask_in[518]
  PIN w_mask_in[519]
    DIRECTION INPUT ;
    USE SIGNAL ;
    SHAPE ABUTMENT ;
    PORT
      LAYER M4 ;
      RECT 176.880 77.376 176.904 77.400 ;
    END
  END w_mask_in[519]
  PIN w_mask_in[520]
    DIRECTION INPUT ;
    USE SIGNAL ;
    SHAPE ABUTMENT ;
    PORT
      LAYER M4 ;
      RECT 176.880 77.472 176.904 77.496 ;
    END
  END w_mask_in[520]
  PIN w_mask_in[521]
    DIRECTION INPUT ;
    USE SIGNAL ;
    SHAPE ABUTMENT ;
    PORT
      LAYER M4 ;
      RECT 176.880 77.568 176.904 77.592 ;
    END
  END w_mask_in[521]
  PIN w_mask_in[522]
    DIRECTION INPUT ;
    USE SIGNAL ;
    SHAPE ABUTMENT ;
    PORT
      LAYER M4 ;
      RECT 176.880 77.664 176.904 77.688 ;
    END
  END w_mask_in[522]
  PIN w_mask_in[523]
    DIRECTION INPUT ;
    USE SIGNAL ;
    SHAPE ABUTMENT ;
    PORT
      LAYER M4 ;
      RECT 176.880 77.760 176.904 77.784 ;
    END
  END w_mask_in[523]
  PIN w_mask_in[524]
    DIRECTION INPUT ;
    USE SIGNAL ;
    SHAPE ABUTMENT ;
    PORT
      LAYER M4 ;
      RECT 176.880 77.856 176.904 77.880 ;
    END
  END w_mask_in[524]
  PIN w_mask_in[525]
    DIRECTION INPUT ;
    USE SIGNAL ;
    SHAPE ABUTMENT ;
    PORT
      LAYER M4 ;
      RECT 176.880 77.952 176.904 77.976 ;
    END
  END w_mask_in[525]
  PIN w_mask_in[526]
    DIRECTION INPUT ;
    USE SIGNAL ;
    SHAPE ABUTMENT ;
    PORT
      LAYER M4 ;
      RECT 176.880 78.048 176.904 78.072 ;
    END
  END w_mask_in[526]
  PIN w_mask_in[527]
    DIRECTION INPUT ;
    USE SIGNAL ;
    SHAPE ABUTMENT ;
    PORT
      LAYER M4 ;
      RECT 176.880 78.144 176.904 78.168 ;
    END
  END w_mask_in[527]
  PIN w_mask_in[528]
    DIRECTION INPUT ;
    USE SIGNAL ;
    SHAPE ABUTMENT ;
    PORT
      LAYER M4 ;
      RECT 176.880 78.240 176.904 78.264 ;
    END
  END w_mask_in[528]
  PIN w_mask_in[529]
    DIRECTION INPUT ;
    USE SIGNAL ;
    SHAPE ABUTMENT ;
    PORT
      LAYER M4 ;
      RECT 176.880 78.336 176.904 78.360 ;
    END
  END w_mask_in[529]
  PIN w_mask_in[530]
    DIRECTION INPUT ;
    USE SIGNAL ;
    SHAPE ABUTMENT ;
    PORT
      LAYER M4 ;
      RECT 176.880 78.432 176.904 78.456 ;
    END
  END w_mask_in[530]
  PIN w_mask_in[531]
    DIRECTION INPUT ;
    USE SIGNAL ;
    SHAPE ABUTMENT ;
    PORT
      LAYER M4 ;
      RECT 176.880 78.528 176.904 78.552 ;
    END
  END w_mask_in[531]
  PIN w_mask_in[532]
    DIRECTION INPUT ;
    USE SIGNAL ;
    SHAPE ABUTMENT ;
    PORT
      LAYER M4 ;
      RECT 176.880 78.624 176.904 78.648 ;
    END
  END w_mask_in[532]
  PIN w_mask_in[533]
    DIRECTION INPUT ;
    USE SIGNAL ;
    SHAPE ABUTMENT ;
    PORT
      LAYER M4 ;
      RECT 176.880 78.720 176.904 78.744 ;
    END
  END w_mask_in[533]
  PIN w_mask_in[534]
    DIRECTION INPUT ;
    USE SIGNAL ;
    SHAPE ABUTMENT ;
    PORT
      LAYER M4 ;
      RECT 176.880 78.816 176.904 78.840 ;
    END
  END w_mask_in[534]
  PIN w_mask_in[535]
    DIRECTION INPUT ;
    USE SIGNAL ;
    SHAPE ABUTMENT ;
    PORT
      LAYER M4 ;
      RECT 176.880 78.912 176.904 78.936 ;
    END
  END w_mask_in[535]
  PIN w_mask_in[536]
    DIRECTION INPUT ;
    USE SIGNAL ;
    SHAPE ABUTMENT ;
    PORT
      LAYER M4 ;
      RECT 176.880 79.008 176.904 79.032 ;
    END
  END w_mask_in[536]
  PIN w_mask_in[537]
    DIRECTION INPUT ;
    USE SIGNAL ;
    SHAPE ABUTMENT ;
    PORT
      LAYER M4 ;
      RECT 176.880 79.104 176.904 79.128 ;
    END
  END w_mask_in[537]
  PIN w_mask_in[538]
    DIRECTION INPUT ;
    USE SIGNAL ;
    SHAPE ABUTMENT ;
    PORT
      LAYER M4 ;
      RECT 176.880 79.200 176.904 79.224 ;
    END
  END w_mask_in[538]
  PIN w_mask_in[539]
    DIRECTION INPUT ;
    USE SIGNAL ;
    SHAPE ABUTMENT ;
    PORT
      LAYER M4 ;
      RECT 176.880 79.296 176.904 79.320 ;
    END
  END w_mask_in[539]
  PIN w_mask_in[540]
    DIRECTION INPUT ;
    USE SIGNAL ;
    SHAPE ABUTMENT ;
    PORT
      LAYER M4 ;
      RECT 176.880 79.392 176.904 79.416 ;
    END
  END w_mask_in[540]
  PIN w_mask_in[541]
    DIRECTION INPUT ;
    USE SIGNAL ;
    SHAPE ABUTMENT ;
    PORT
      LAYER M4 ;
      RECT 176.880 79.488 176.904 79.512 ;
    END
  END w_mask_in[541]
  PIN w_mask_in[542]
    DIRECTION INPUT ;
    USE SIGNAL ;
    SHAPE ABUTMENT ;
    PORT
      LAYER M4 ;
      RECT 176.880 79.584 176.904 79.608 ;
    END
  END w_mask_in[542]
  PIN w_mask_in[543]
    DIRECTION INPUT ;
    USE SIGNAL ;
    SHAPE ABUTMENT ;
    PORT
      LAYER M4 ;
      RECT 176.880 79.680 176.904 79.704 ;
    END
  END w_mask_in[543]
  PIN w_mask_in[544]
    DIRECTION INPUT ;
    USE SIGNAL ;
    SHAPE ABUTMENT ;
    PORT
      LAYER M4 ;
      RECT 176.880 79.776 176.904 79.800 ;
    END
  END w_mask_in[544]
  PIN w_mask_in[545]
    DIRECTION INPUT ;
    USE SIGNAL ;
    SHAPE ABUTMENT ;
    PORT
      LAYER M4 ;
      RECT 176.880 79.872 176.904 79.896 ;
    END
  END w_mask_in[545]
  PIN VDD
    DIRECTION INOUT ;
    USE POWER ;
    PORT
      LAYER M4 ;
      RECT 0.300 0.384 176.604 0.480 ;
      RECT 0.300 1.152 176.604 1.248 ;
      RECT 0.300 1.920 176.604 2.016 ;
      RECT 0.300 2.688 176.604 2.784 ;
      RECT 0.300 3.456 176.604 3.552 ;
      RECT 0.300 4.224 176.604 4.320 ;
      RECT 0.300 4.992 176.604 5.088 ;
      RECT 0.300 5.760 176.604 5.856 ;
      RECT 0.300 6.528 176.604 6.624 ;
      RECT 0.300 7.296 176.604 7.392 ;
      RECT 0.300 8.064 176.604 8.160 ;
      RECT 0.300 8.832 176.604 8.928 ;
      RECT 0.300 9.600 176.604 9.696 ;
      RECT 0.300 10.368 176.604 10.464 ;
      RECT 0.300 11.136 176.604 11.232 ;
      RECT 0.300 11.904 176.604 12.000 ;
      RECT 0.300 12.672 176.604 12.768 ;
      RECT 0.300 13.440 176.604 13.536 ;
      RECT 0.300 14.208 176.604 14.304 ;
      RECT 0.300 14.976 176.604 15.072 ;
      RECT 0.300 15.744 176.604 15.840 ;
      RECT 0.300 16.512 176.604 16.608 ;
      RECT 0.300 17.280 176.604 17.376 ;
      RECT 0.300 18.048 176.604 18.144 ;
      RECT 0.300 18.816 176.604 18.912 ;
      RECT 0.300 19.584 176.604 19.680 ;
      RECT 0.300 20.352 176.604 20.448 ;
      RECT 0.300 21.120 176.604 21.216 ;
      RECT 0.300 21.888 176.604 21.984 ;
      RECT 0.300 22.656 176.604 22.752 ;
      RECT 0.300 23.424 176.604 23.520 ;
      RECT 0.300 24.192 176.604 24.288 ;
      RECT 0.300 24.960 176.604 25.056 ;
      RECT 0.300 25.728 176.604 25.824 ;
      RECT 0.300 26.496 176.604 26.592 ;
      RECT 0.300 27.264 176.604 27.360 ;
      RECT 0.300 28.032 176.604 28.128 ;
      RECT 0.300 28.800 176.604 28.896 ;
      RECT 0.300 29.568 176.604 29.664 ;
      RECT 0.300 30.336 176.604 30.432 ;
      RECT 0.300 31.104 176.604 31.200 ;
      RECT 0.300 31.872 176.604 31.968 ;
      RECT 0.300 32.640 176.604 32.736 ;
      RECT 0.300 33.408 176.604 33.504 ;
      RECT 0.300 34.176 176.604 34.272 ;
      RECT 0.300 34.944 176.604 35.040 ;
      RECT 0.300 35.712 176.604 35.808 ;
      RECT 0.300 36.480 176.604 36.576 ;
      RECT 0.300 37.248 176.604 37.344 ;
      RECT 0.300 38.016 176.604 38.112 ;
      RECT 0.300 38.784 176.604 38.880 ;
      RECT 0.300 39.552 176.604 39.648 ;
      RECT 0.300 40.320 176.604 40.416 ;
      RECT 0.300 41.088 176.604 41.184 ;
      RECT 0.300 41.856 176.604 41.952 ;
      RECT 0.300 42.624 176.604 42.720 ;
      RECT 0.300 43.392 176.604 43.488 ;
      RECT 0.300 44.160 176.604 44.256 ;
      RECT 0.300 44.928 176.604 45.024 ;
      RECT 0.300 45.696 176.604 45.792 ;
      RECT 0.300 46.464 176.604 46.560 ;
      RECT 0.300 47.232 176.604 47.328 ;
      RECT 0.300 48.000 176.604 48.096 ;
      RECT 0.300 48.768 176.604 48.864 ;
      RECT 0.300 49.536 176.604 49.632 ;
      RECT 0.300 50.304 176.604 50.400 ;
      RECT 0.300 51.072 176.604 51.168 ;
      RECT 0.300 51.840 176.604 51.936 ;
      RECT 0.300 52.608 176.604 52.704 ;
      RECT 0.300 53.376 176.604 53.472 ;
      RECT 0.300 54.144 176.604 54.240 ;
      RECT 0.300 54.912 176.604 55.008 ;
      RECT 0.300 55.680 176.604 55.776 ;
      RECT 0.300 56.448 176.604 56.544 ;
      RECT 0.300 57.216 176.604 57.312 ;
      RECT 0.300 57.984 176.604 58.080 ;
      RECT 0.300 58.752 176.604 58.848 ;
      RECT 0.300 59.520 176.604 59.616 ;
      RECT 0.300 60.288 176.604 60.384 ;
      RECT 0.300 61.056 176.604 61.152 ;
      RECT 0.300 61.824 176.604 61.920 ;
      RECT 0.300 62.592 176.604 62.688 ;
      RECT 0.300 63.360 176.604 63.456 ;
      RECT 0.300 64.128 176.604 64.224 ;
      RECT 0.300 64.896 176.604 64.992 ;
      RECT 0.300 65.664 176.604 65.760 ;
      RECT 0.300 66.432 176.604 66.528 ;
      RECT 0.300 67.200 176.604 67.296 ;
      RECT 0.300 67.968 176.604 68.064 ;
      RECT 0.300 68.736 176.604 68.832 ;
      RECT 0.300 69.504 176.604 69.600 ;
      RECT 0.300 70.272 176.604 70.368 ;
      RECT 0.300 71.040 176.604 71.136 ;
      RECT 0.300 71.808 176.604 71.904 ;
      RECT 0.300 72.576 176.604 72.672 ;
      RECT 0.300 73.344 176.604 73.440 ;
      RECT 0.300 74.112 176.604 74.208 ;
      RECT 0.300 74.880 176.604 74.976 ;
      RECT 0.300 75.648 176.604 75.744 ;
      RECT 0.300 76.416 176.604 76.512 ;
      RECT 0.300 77.184 176.604 77.280 ;
      RECT 0.300 77.952 176.604 78.048 ;
      RECT 0.300 78.720 176.604 78.816 ;
      RECT 0.300 79.488 176.604 79.584 ;
      RECT 0.300 80.256 176.604 80.352 ;
    END
  END VDD
  PIN VSS
    DIRECTION INOUT ;
    USE GROUND ;
    PORT
      LAYER M4 ;
      RECT 0.300 0.768 176.604 0.864 ;
      RECT 0.300 1.536 176.604 1.632 ;
      RECT 0.300 2.304 176.604 2.400 ;
      RECT 0.300 3.072 176.604 3.168 ;
      RECT 0.300 3.840 176.604 3.936 ;
      RECT 0.300 4.608 176.604 4.704 ;
      RECT 0.300 5.376 176.604 5.472 ;
      RECT 0.300 6.144 176.604 6.240 ;
      RECT 0.300 6.912 176.604 7.008 ;
      RECT 0.300 7.680 176.604 7.776 ;
      RECT 0.300 8.448 176.604 8.544 ;
      RECT 0.300 9.216 176.604 9.312 ;
      RECT 0.300 9.984 176.604 10.080 ;
      RECT 0.300 10.752 176.604 10.848 ;
      RECT 0.300 11.520 176.604 11.616 ;
      RECT 0.300 12.288 176.604 12.384 ;
      RECT 0.300 13.056 176.604 13.152 ;
      RECT 0.300 13.824 176.604 13.920 ;
      RECT 0.300 14.592 176.604 14.688 ;
      RECT 0.300 15.360 176.604 15.456 ;
      RECT 0.300 16.128 176.604 16.224 ;
      RECT 0.300 16.896 176.604 16.992 ;
      RECT 0.300 17.664 176.604 17.760 ;
      RECT 0.300 18.432 176.604 18.528 ;
      RECT 0.300 19.200 176.604 19.296 ;
      RECT 0.300 19.968 176.604 20.064 ;
      RECT 0.300 20.736 176.604 20.832 ;
      RECT 0.300 21.504 176.604 21.600 ;
      RECT 0.300 22.272 176.604 22.368 ;
      RECT 0.300 23.040 176.604 23.136 ;
      RECT 0.300 23.808 176.604 23.904 ;
      RECT 0.300 24.576 176.604 24.672 ;
      RECT 0.300 25.344 176.604 25.440 ;
      RECT 0.300 26.112 176.604 26.208 ;
      RECT 0.300 26.880 176.604 26.976 ;
      RECT 0.300 27.648 176.604 27.744 ;
      RECT 0.300 28.416 176.604 28.512 ;
      RECT 0.300 29.184 176.604 29.280 ;
      RECT 0.300 29.952 176.604 30.048 ;
      RECT 0.300 30.720 176.604 30.816 ;
      RECT 0.300 31.488 176.604 31.584 ;
      RECT 0.300 32.256 176.604 32.352 ;
      RECT 0.300 33.024 176.604 33.120 ;
      RECT 0.300 33.792 176.604 33.888 ;
      RECT 0.300 34.560 176.604 34.656 ;
      RECT 0.300 35.328 176.604 35.424 ;
      RECT 0.300 36.096 176.604 36.192 ;
      RECT 0.300 36.864 176.604 36.960 ;
      RECT 0.300 37.632 176.604 37.728 ;
      RECT 0.300 38.400 176.604 38.496 ;
      RECT 0.300 39.168 176.604 39.264 ;
      RECT 0.300 39.936 176.604 40.032 ;
      RECT 0.300 40.704 176.604 40.800 ;
      RECT 0.300 41.472 176.604 41.568 ;
      RECT 0.300 42.240 176.604 42.336 ;
      RECT 0.300 43.008 176.604 43.104 ;
      RECT 0.300 43.776 176.604 43.872 ;
      RECT 0.300 44.544 176.604 44.640 ;
      RECT 0.300 45.312 176.604 45.408 ;
      RECT 0.300 46.080 176.604 46.176 ;
      RECT 0.300 46.848 176.604 46.944 ;
      RECT 0.300 47.616 176.604 47.712 ;
      RECT 0.300 48.384 176.604 48.480 ;
      RECT 0.300 49.152 176.604 49.248 ;
      RECT 0.300 49.920 176.604 50.016 ;
      RECT 0.300 50.688 176.604 50.784 ;
      RECT 0.300 51.456 176.604 51.552 ;
      RECT 0.300 52.224 176.604 52.320 ;
      RECT 0.300 52.992 176.604 53.088 ;
      RECT 0.300 53.760 176.604 53.856 ;
      RECT 0.300 54.528 176.604 54.624 ;
      RECT 0.300 55.296 176.604 55.392 ;
      RECT 0.300 56.064 176.604 56.160 ;
      RECT 0.300 56.832 176.604 56.928 ;
      RECT 0.300 57.600 176.604 57.696 ;
      RECT 0.300 58.368 176.604 58.464 ;
      RECT 0.300 59.136 176.604 59.232 ;
      RECT 0.300 59.904 176.604 60.000 ;
      RECT 0.300 60.672 176.604 60.768 ;
      RECT 0.300 61.440 176.604 61.536 ;
      RECT 0.300 62.208 176.604 62.304 ;
      RECT 0.300 62.976 176.604 63.072 ;
      RECT 0.300 63.744 176.604 63.840 ;
      RECT 0.300 64.512 176.604 64.608 ;
      RECT 0.300 65.280 176.604 65.376 ;
      RECT 0.300 66.048 176.604 66.144 ;
      RECT 0.300 66.816 176.604 66.912 ;
      RECT 0.300 67.584 176.604 67.680 ;
      RECT 0.300 68.352 176.604 68.448 ;
      RECT 0.300 69.120 176.604 69.216 ;
      RECT 0.300 69.888 176.604 69.984 ;
      RECT 0.300 70.656 176.604 70.752 ;
      RECT 0.300 71.424 176.604 71.520 ;
      RECT 0.300 72.192 176.604 72.288 ;
      RECT 0.300 72.960 176.604 73.056 ;
      RECT 0.300 73.728 176.604 73.824 ;
      RECT 0.300 74.496 176.604 74.592 ;
      RECT 0.300 75.264 176.604 75.360 ;
      RECT 0.300 76.032 176.604 76.128 ;
      RECT 0.300 76.800 176.604 76.896 ;
      RECT 0.300 77.568 176.604 77.664 ;
      RECT 0.300 78.336 176.604 78.432 ;
      RECT 0.300 79.104 176.604 79.200 ;
      RECT 0.300 79.872 176.604 79.968 ;
      RECT 0.300 80.640 176.604 80.736 ;
    END
  END VSS
  OBS
    LAYER M1 ;
    RECT 0 0 176.904 81.000 ;
    LAYER M2 ;
    RECT 0 0 176.904 81.000 ;
    LAYER M3 ;
    RECT 0 0 176.904 81.000 ;
    LAYER M4 ;
    RECT 0.072 0 176.832 81.000 ;
  END
END ot_sram_1r1w2c_16x546_m1

END LIBRARY
